VERSION 5.8 ;
BUSBITCHARS "[]" ;
DIVIDERCHAR "/" ;
UNITS
    DATABASE MICRONS 1000 ;
END UNITS

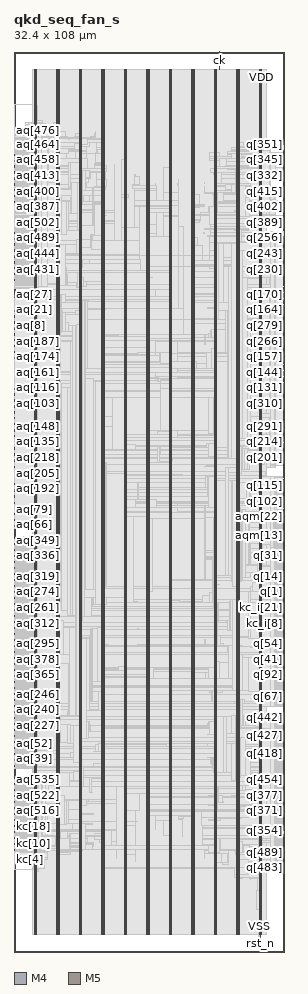
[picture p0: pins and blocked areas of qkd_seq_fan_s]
MACRO qkd_seq_fan_s
  FOREIGN qkd_seq_fan_s 0 0 ;
  CLASS BLOCK ;
  SIZE 32.4 BY 108 ;
  PIN af
    DIRECTION INPUT ;
    USE SIGNAL ;
    PORT
      LAYER M4 ;
        RECT  0 73.872 0.084 73.896 ;
    END
  END af
  PIN af_o
    DIRECTION OUTPUT ;
    USE SIGNAL ;
    PORT
      LAYER M4 ;
        RECT  32.316 47.952 32.4 47.976 ;
    END
  END af_o
  PIN aq[0]
    DIRECTION OUTPUT ;
    USE SIGNAL ;
    PORT
      LAYER M4 ;
        RECT  0 74.016 0.084 74.04 ;
    END
  END aq[0]
  PIN aq[100]
    DIRECTION OUTPUT ;
    USE SIGNAL ;
    PORT
      LAYER M4 ;
        RECT  0 65.376 0.084 65.4 ;
    END
  END aq[100]
  PIN aq[101]
    DIRECTION OUTPUT ;
    USE SIGNAL ;
    PORT
      LAYER M4 ;
        RECT  0 65.52 0.084 65.544 ;
    END
  END aq[101]
  PIN aq[102]
    DIRECTION OUTPUT ;
    USE SIGNAL ;
    PORT
      LAYER M4 ;
        RECT  0 65.664 0.084 65.688 ;
    END
  END aq[102]
  PIN aq[103]
    DIRECTION OUTPUT ;
    USE SIGNAL ;
    PORT
      LAYER M4 ;
        RECT  0 65.808 0.084 65.832 ;
    END
  END aq[103]
  PIN aq[104]
    DIRECTION OUTPUT ;
    USE SIGNAL ;
    PORT
      LAYER M4 ;
        RECT  0 65.952 0.084 65.976 ;
    END
  END aq[104]
  PIN aq[105]
    DIRECTION OUTPUT ;
    USE SIGNAL ;
    PORT
      LAYER M4 ;
        RECT  0 66.096 0.084 66.12 ;
    END
  END aq[105]
  PIN aq[106]
    DIRECTION OUTPUT ;
    USE SIGNAL ;
    PORT
      LAYER M4 ;
        RECT  0 66.24 0.084 66.264 ;
    END
  END aq[106]
  PIN aq[107]
    DIRECTION OUTPUT ;
    USE SIGNAL ;
    PORT
      LAYER M4 ;
        RECT  0 66.384 0.084 66.408 ;
    END
  END aq[107]
  PIN aq[108]
    DIRECTION OUTPUT ;
    USE SIGNAL ;
    PORT
      LAYER M4 ;
        RECT  0 66.528 0.084 66.552 ;
    END
  END aq[108]
  PIN aq[109]
    DIRECTION OUTPUT ;
    USE SIGNAL ;
    PORT
      LAYER M4 ;
        RECT  0 66.672 0.084 66.696 ;
    END
  END aq[109]
  PIN aq[10]
    DIRECTION OUTPUT ;
    USE SIGNAL ;
    PORT
      LAYER M4 ;
        RECT  0 75.456 0.084 75.48 ;
    END
  END aq[10]
  PIN aq[110]
    DIRECTION OUTPUT ;
    USE SIGNAL ;
    PORT
      LAYER M4 ;
        RECT  0 66.816 0.084 66.84 ;
    END
  END aq[110]
  PIN aq[111]
    DIRECTION OUTPUT ;
    USE SIGNAL ;
    PORT
      LAYER M4 ;
        RECT  0 66.96 0.084 66.984 ;
    END
  END aq[111]
  PIN aq[112]
    DIRECTION OUTPUT ;
    USE SIGNAL ;
    PORT
      LAYER M4 ;
        RECT  0 67.104 0.084 67.128 ;
    END
  END aq[112]
  PIN aq[113]
    DIRECTION OUTPUT ;
    USE SIGNAL ;
    PORT
      LAYER M4 ;
        RECT  0 67.248 0.084 67.272 ;
    END
  END aq[113]
  PIN aq[114]
    DIRECTION OUTPUT ;
    USE SIGNAL ;
    PORT
      LAYER M4 ;
        RECT  0 67.392 0.084 67.416 ;
    END
  END aq[114]
  PIN aq[115]
    DIRECTION OUTPUT ;
    USE SIGNAL ;
    PORT
      LAYER M4 ;
        RECT  0 67.536 0.084 67.56 ;
    END
  END aq[115]
  PIN aq[116]
    DIRECTION OUTPUT ;
    USE SIGNAL ;
    PORT
      LAYER M4 ;
        RECT  0 67.68 0.084 67.704 ;
    END
  END aq[116]
  PIN aq[117]
    DIRECTION OUTPUT ;
    USE SIGNAL ;
    PORT
      LAYER M4 ;
        RECT  0 67.824 0.084 67.848 ;
    END
  END aq[117]
  PIN aq[118]
    DIRECTION OUTPUT ;
    USE SIGNAL ;
    PORT
      LAYER M4 ;
        RECT  0 67.968 0.084 67.992 ;
    END
  END aq[118]
  PIN aq[119]
    DIRECTION OUTPUT ;
    USE SIGNAL ;
    PORT
      LAYER M4 ;
        RECT  0 68.112 0.084 68.136 ;
    END
  END aq[119]
  PIN aq[11]
    DIRECTION OUTPUT ;
    USE SIGNAL ;
    PORT
      LAYER M4 ;
        RECT  0 75.6 0.084 75.624 ;
    END
  END aq[11]
  PIN aq[120]
    DIRECTION OUTPUT ;
    USE SIGNAL ;
    PORT
      LAYER M4 ;
        RECT  0 68.256 0.084 68.28 ;
    END
  END aq[120]
  PIN aq[121]
    DIRECTION OUTPUT ;
    USE SIGNAL ;
    PORT
      LAYER M4 ;
        RECT  0 68.4 0.084 68.424 ;
    END
  END aq[121]
  PIN aq[122]
    DIRECTION OUTPUT ;
    USE SIGNAL ;
    PORT
      LAYER M4 ;
        RECT  0 68.544 0.084 68.568 ;
    END
  END aq[122]
  PIN aq[123]
    DIRECTION OUTPUT ;
    USE SIGNAL ;
    PORT
      LAYER M4 ;
        RECT  0 68.688 0.084 68.712 ;
    END
  END aq[123]
  PIN aq[124]
    DIRECTION OUTPUT ;
    USE SIGNAL ;
    PORT
      LAYER M4 ;
        RECT  0 68.832 0.084 68.856 ;
    END
  END aq[124]
  PIN aq[125]
    DIRECTION OUTPUT ;
    USE SIGNAL ;
    PORT
      LAYER M4 ;
        RECT  0 68.976 0.084 69 ;
    END
  END aq[125]
  PIN aq[126]
    DIRECTION OUTPUT ;
    USE SIGNAL ;
    PORT
      LAYER M4 ;
        RECT  0 69.12 0.084 69.144 ;
    END
  END aq[126]
  PIN aq[127]
    DIRECTION OUTPUT ;
    USE SIGNAL ;
    PORT
      LAYER M4 ;
        RECT  0 60.048 0.084 60.072 ;
    END
  END aq[127]
  PIN aq[128]
    DIRECTION OUTPUT ;
    USE SIGNAL ;
    PORT
      LAYER M4 ;
        RECT  0 60.192 0.084 60.216 ;
    END
  END aq[128]
  PIN aq[129]
    DIRECTION OUTPUT ;
    USE SIGNAL ;
    PORT
      LAYER M4 ;
        RECT  0 60.336 0.084 60.36 ;
    END
  END aq[129]
  PIN aq[12]
    DIRECTION OUTPUT ;
    USE SIGNAL ;
    PORT
      LAYER M4 ;
        RECT  0 75.744 0.084 75.768 ;
    END
  END aq[12]
  PIN aq[130]
    DIRECTION OUTPUT ;
    USE SIGNAL ;
    PORT
      LAYER M4 ;
        RECT  0 60.48 0.084 60.504 ;
    END
  END aq[130]
  PIN aq[131]
    DIRECTION OUTPUT ;
    USE SIGNAL ;
    PORT
      LAYER M4 ;
        RECT  0 60.624 0.084 60.648 ;
    END
  END aq[131]
  PIN aq[132]
    DIRECTION OUTPUT ;
    USE SIGNAL ;
    PORT
      LAYER M4 ;
        RECT  0 60.768 0.084 60.792 ;
    END
  END aq[132]
  PIN aq[133]
    DIRECTION OUTPUT ;
    USE SIGNAL ;
    PORT
      LAYER M4 ;
        RECT  0 60.912 0.084 60.936 ;
    END
  END aq[133]
  PIN aq[134]
    DIRECTION OUTPUT ;
    USE SIGNAL ;
    PORT
      LAYER M4 ;
        RECT  0 61.056 0.084 61.08 ;
    END
  END aq[134]
  PIN aq[135]
    DIRECTION OUTPUT ;
    USE SIGNAL ;
    PORT
      LAYER M4 ;
        RECT  0 61.2 0.084 61.224 ;
    END
  END aq[135]
  PIN aq[136]
    DIRECTION OUTPUT ;
    USE SIGNAL ;
    PORT
      LAYER M4 ;
        RECT  0 61.344 0.084 61.368 ;
    END
  END aq[136]
  PIN aq[137]
    DIRECTION OUTPUT ;
    USE SIGNAL ;
    PORT
      LAYER M4 ;
        RECT  0 61.488 0.084 61.512 ;
    END
  END aq[137]
  PIN aq[138]
    DIRECTION OUTPUT ;
    USE SIGNAL ;
    PORT
      LAYER M4 ;
        RECT  0 61.632 0.084 61.656 ;
    END
  END aq[138]
  PIN aq[139]
    DIRECTION OUTPUT ;
    USE SIGNAL ;
    PORT
      LAYER M4 ;
        RECT  0 61.776 0.084 61.8 ;
    END
  END aq[139]
  PIN aq[13]
    DIRECTION OUTPUT ;
    USE SIGNAL ;
    PORT
      LAYER M4 ;
        RECT  0 75.888 0.084 75.912 ;
    END
  END aq[13]
  PIN aq[140]
    DIRECTION OUTPUT ;
    USE SIGNAL ;
    PORT
      LAYER M4 ;
        RECT  0 61.92 0.084 61.944 ;
    END
  END aq[140]
  PIN aq[141]
    DIRECTION OUTPUT ;
    USE SIGNAL ;
    PORT
      LAYER M4 ;
        RECT  0 62.064 0.084 62.088 ;
    END
  END aq[141]
  PIN aq[142]
    DIRECTION OUTPUT ;
    USE SIGNAL ;
    PORT
      LAYER M4 ;
        RECT  0 62.208 0.084 62.232 ;
    END
  END aq[142]
  PIN aq[143]
    DIRECTION OUTPUT ;
    USE SIGNAL ;
    PORT
      LAYER M4 ;
        RECT  0 62.352 0.084 62.376 ;
    END
  END aq[143]
  PIN aq[144]
    DIRECTION OUTPUT ;
    USE SIGNAL ;
    PORT
      LAYER M4 ;
        RECT  0 62.496 0.084 62.52 ;
    END
  END aq[144]
  PIN aq[145]
    DIRECTION OUTPUT ;
    USE SIGNAL ;
    PORT
      LAYER M4 ;
        RECT  0 62.64 0.084 62.664 ;
    END
  END aq[145]
  PIN aq[146]
    DIRECTION OUTPUT ;
    USE SIGNAL ;
    PORT
      LAYER M4 ;
        RECT  0 62.784 0.084 62.808 ;
    END
  END aq[146]
  PIN aq[147]
    DIRECTION OUTPUT ;
    USE SIGNAL ;
    PORT
      LAYER M4 ;
        RECT  0 62.928 0.084 62.952 ;
    END
  END aq[147]
  PIN aq[148]
    DIRECTION OUTPUT ;
    USE SIGNAL ;
    PORT
      LAYER M4 ;
        RECT  0 63.072 0.084 63.096 ;
    END
  END aq[148]
  PIN aq[149]
    DIRECTION OUTPUT ;
    USE SIGNAL ;
    PORT
      LAYER M4 ;
        RECT  0 63.216 0.084 63.24 ;
    END
  END aq[149]
  PIN aq[14]
    DIRECTION OUTPUT ;
    USE SIGNAL ;
    PORT
      LAYER M4 ;
        RECT  0 76.032 0.084 76.056 ;
    END
  END aq[14]
  PIN aq[150]
    DIRECTION OUTPUT ;
    USE SIGNAL ;
    PORT
      LAYER M4 ;
        RECT  0 63.36 0.084 63.384 ;
    END
  END aq[150]
  PIN aq[151]
    DIRECTION OUTPUT ;
    USE SIGNAL ;
    PORT
      LAYER M4 ;
        RECT  0 63.504 0.084 63.528 ;
    END
  END aq[151]
  PIN aq[152]
    DIRECTION OUTPUT ;
    USE SIGNAL ;
    PORT
      LAYER M4 ;
        RECT  0 63.648 0.084 63.672 ;
    END
  END aq[152]
  PIN aq[153]
    DIRECTION OUTPUT ;
    USE SIGNAL ;
    PORT
      LAYER M4 ;
        RECT  0 63.792 0.084 63.816 ;
    END
  END aq[153]
  PIN aq[154]
    DIRECTION OUTPUT ;
    USE SIGNAL ;
    PORT
      LAYER M4 ;
        RECT  0 63.936 0.084 63.96 ;
    END
  END aq[154]
  PIN aq[155]
    DIRECTION OUTPUT ;
    USE SIGNAL ;
    PORT
      LAYER M4 ;
        RECT  0 64.08 0.084 64.104 ;
    END
  END aq[155]
  PIN aq[156]
    DIRECTION OUTPUT ;
    USE SIGNAL ;
    PORT
      LAYER M4 ;
        RECT  0 64.224 0.084 64.248 ;
    END
  END aq[156]
  PIN aq[157]
    DIRECTION OUTPUT ;
    USE SIGNAL ;
    PORT
      LAYER M4 ;
        RECT  0 64.368 0.084 64.392 ;
    END
  END aq[157]
  PIN aq[158]
    DIRECTION OUTPUT ;
    USE SIGNAL ;
    PORT
      LAYER M4 ;
        RECT  0 64.512 0.084 64.536 ;
    END
  END aq[158]
  PIN aq[159]
    DIRECTION OUTPUT ;
    USE SIGNAL ;
    PORT
      LAYER M4 ;
        RECT  0 69.264 0.084 69.288 ;
    END
  END aq[159]
  PIN aq[15]
    DIRECTION OUTPUT ;
    USE SIGNAL ;
    PORT
      LAYER M4 ;
        RECT  0 76.176 0.084 76.2 ;
    END
  END aq[15]
  PIN aq[160]
    DIRECTION OUTPUT ;
    USE SIGNAL ;
    PORT
      LAYER M4 ;
        RECT  0 69.408 0.084 69.432 ;
    END
  END aq[160]
  PIN aq[161]
    DIRECTION OUTPUT ;
    USE SIGNAL ;
    PORT
      LAYER M4 ;
        RECT  0 69.552 0.084 69.576 ;
    END
  END aq[161]
  PIN aq[162]
    DIRECTION OUTPUT ;
    USE SIGNAL ;
    PORT
      LAYER M4 ;
        RECT  0 69.696 0.084 69.72 ;
    END
  END aq[162]
  PIN aq[163]
    DIRECTION OUTPUT ;
    USE SIGNAL ;
    PORT
      LAYER M4 ;
        RECT  0 69.84 0.084 69.864 ;
    END
  END aq[163]
  PIN aq[164]
    DIRECTION OUTPUT ;
    USE SIGNAL ;
    PORT
      LAYER M4 ;
        RECT  0 69.984 0.084 70.008 ;
    END
  END aq[164]
  PIN aq[165]
    DIRECTION OUTPUT ;
    USE SIGNAL ;
    PORT
      LAYER M4 ;
        RECT  0 70.128 0.084 70.152 ;
    END
  END aq[165]
  PIN aq[166]
    DIRECTION OUTPUT ;
    USE SIGNAL ;
    PORT
      LAYER M4 ;
        RECT  0 70.272 0.084 70.296 ;
    END
  END aq[166]
  PIN aq[167]
    DIRECTION OUTPUT ;
    USE SIGNAL ;
    PORT
      LAYER M4 ;
        RECT  0 70.416 0.084 70.44 ;
    END
  END aq[167]
  PIN aq[168]
    DIRECTION OUTPUT ;
    USE SIGNAL ;
    PORT
      LAYER M4 ;
        RECT  0 70.56 0.084 70.584 ;
    END
  END aq[168]
  PIN aq[169]
    DIRECTION OUTPUT ;
    USE SIGNAL ;
    PORT
      LAYER M4 ;
        RECT  0 70.704 0.084 70.728 ;
    END
  END aq[169]
  PIN aq[16]
    DIRECTION OUTPUT ;
    USE SIGNAL ;
    PORT
      LAYER M4 ;
        RECT  0 76.32 0.084 76.344 ;
    END
  END aq[16]
  PIN aq[170]
    DIRECTION OUTPUT ;
    USE SIGNAL ;
    PORT
      LAYER M4 ;
        RECT  0 70.848 0.084 70.872 ;
    END
  END aq[170]
  PIN aq[171]
    DIRECTION OUTPUT ;
    USE SIGNAL ;
    PORT
      LAYER M4 ;
        RECT  0 70.992 0.084 71.016 ;
    END
  END aq[171]
  PIN aq[172]
    DIRECTION OUTPUT ;
    USE SIGNAL ;
    PORT
      LAYER M4 ;
        RECT  0 71.136 0.084 71.16 ;
    END
  END aq[172]
  PIN aq[173]
    DIRECTION OUTPUT ;
    USE SIGNAL ;
    PORT
      LAYER M4 ;
        RECT  0 71.28 0.084 71.304 ;
    END
  END aq[173]
  PIN aq[174]
    DIRECTION OUTPUT ;
    USE SIGNAL ;
    PORT
      LAYER M4 ;
        RECT  0 71.424 0.084 71.448 ;
    END
  END aq[174]
  PIN aq[175]
    DIRECTION OUTPUT ;
    USE SIGNAL ;
    PORT
      LAYER M4 ;
        RECT  0 71.568 0.084 71.592 ;
    END
  END aq[175]
  PIN aq[176]
    DIRECTION OUTPUT ;
    USE SIGNAL ;
    PORT
      LAYER M4 ;
        RECT  0 71.712 0.084 71.736 ;
    END
  END aq[176]
  PIN aq[177]
    DIRECTION OUTPUT ;
    USE SIGNAL ;
    PORT
      LAYER M4 ;
        RECT  0 71.856 0.084 71.88 ;
    END
  END aq[177]
  PIN aq[178]
    DIRECTION OUTPUT ;
    USE SIGNAL ;
    PORT
      LAYER M4 ;
        RECT  0 72 0.084 72.024 ;
    END
  END aq[178]
  PIN aq[179]
    DIRECTION OUTPUT ;
    USE SIGNAL ;
    PORT
      LAYER M4 ;
        RECT  0 72.144 0.084 72.168 ;
    END
  END aq[179]
  PIN aq[17]
    DIRECTION OUTPUT ;
    USE SIGNAL ;
    PORT
      LAYER M4 ;
        RECT  0 76.464 0.084 76.488 ;
    END
  END aq[17]
  PIN aq[180]
    DIRECTION OUTPUT ;
    USE SIGNAL ;
    PORT
      LAYER M4 ;
        RECT  0 72.288 0.084 72.312 ;
    END
  END aq[180]
  PIN aq[181]
    DIRECTION OUTPUT ;
    USE SIGNAL ;
    PORT
      LAYER M4 ;
        RECT  0 72.432 0.084 72.456 ;
    END
  END aq[181]
  PIN aq[182]
    DIRECTION OUTPUT ;
    USE SIGNAL ;
    PORT
      LAYER M4 ;
        RECT  0 72.576 0.084 72.6 ;
    END
  END aq[182]
  PIN aq[183]
    DIRECTION OUTPUT ;
    USE SIGNAL ;
    PORT
      LAYER M4 ;
        RECT  0 72.72 0.084 72.744 ;
    END
  END aq[183]
  PIN aq[184]
    DIRECTION OUTPUT ;
    USE SIGNAL ;
    PORT
      LAYER M4 ;
        RECT  0 72.864 0.084 72.888 ;
    END
  END aq[184]
  PIN aq[185]
    DIRECTION OUTPUT ;
    USE SIGNAL ;
    PORT
      LAYER M4 ;
        RECT  0 73.008 0.084 73.032 ;
    END
  END aq[185]
  PIN aq[186]
    DIRECTION OUTPUT ;
    USE SIGNAL ;
    PORT
      LAYER M4 ;
        RECT  0 73.152 0.084 73.176 ;
    END
  END aq[186]
  PIN aq[187]
    DIRECTION OUTPUT ;
    USE SIGNAL ;
    PORT
      LAYER M4 ;
        RECT  0 73.296 0.084 73.32 ;
    END
  END aq[187]
  PIN aq[188]
    DIRECTION OUTPUT ;
    USE SIGNAL ;
    PORT
      LAYER M4 ;
        RECT  0 73.44 0.084 73.464 ;
    END
  END aq[188]
  PIN aq[189]
    DIRECTION OUTPUT ;
    USE SIGNAL ;
    PORT
      LAYER M4 ;
        RECT  0 73.584 0.084 73.608 ;
    END
  END aq[189]
  PIN aq[18]
    DIRECTION OUTPUT ;
    USE SIGNAL ;
    PORT
      LAYER M4 ;
        RECT  0 76.608 0.084 76.632 ;
    END
  END aq[18]
  PIN aq[190]
    DIRECTION OUTPUT ;
    USE SIGNAL ;
    PORT
      LAYER M4 ;
        RECT  0 73.728 0.084 73.752 ;
    END
  END aq[190]
  PIN aq[191]
    DIRECTION OUTPUT ;
    USE SIGNAL ;
    PORT
      LAYER M4 ;
        RECT  0 55.44 0.084 55.464 ;
    END
  END aq[191]
  PIN aq[192]
    DIRECTION OUTPUT ;
    USE SIGNAL ;
    PORT
      LAYER M4 ;
        RECT  0 55.584 0.084 55.608 ;
    END
  END aq[192]
  PIN aq[193]
    DIRECTION OUTPUT ;
    USE SIGNAL ;
    PORT
      LAYER M4 ;
        RECT  0 55.728 0.084 55.752 ;
    END
  END aq[193]
  PIN aq[194]
    DIRECTION OUTPUT ;
    USE SIGNAL ;
    PORT
      LAYER M4 ;
        RECT  0 55.872 0.084 55.896 ;
    END
  END aq[194]
  PIN aq[195]
    DIRECTION OUTPUT ;
    USE SIGNAL ;
    PORT
      LAYER M4 ;
        RECT  0 56.016 0.084 56.04 ;
    END
  END aq[195]
  PIN aq[196]
    DIRECTION OUTPUT ;
    USE SIGNAL ;
    PORT
      LAYER M4 ;
        RECT  0 56.16 0.084 56.184 ;
    END
  END aq[196]
  PIN aq[197]
    DIRECTION OUTPUT ;
    USE SIGNAL ;
    PORT
      LAYER M4 ;
        RECT  0 56.304 0.084 56.328 ;
    END
  END aq[197]
  PIN aq[198]
    DIRECTION OUTPUT ;
    USE SIGNAL ;
    PORT
      LAYER M4 ;
        RECT  0 56.448 0.084 56.472 ;
    END
  END aq[198]
  PIN aq[199]
    DIRECTION OUTPUT ;
    USE SIGNAL ;
    PORT
      LAYER M4 ;
        RECT  0 56.592 0.084 56.616 ;
    END
  END aq[199]
  PIN aq[19]
    DIRECTION OUTPUT ;
    USE SIGNAL ;
    PORT
      LAYER M4 ;
        RECT  0 76.752 0.084 76.776 ;
    END
  END aq[19]
  PIN aq[1]
    DIRECTION OUTPUT ;
    USE SIGNAL ;
    PORT
      LAYER M4 ;
        RECT  0 74.16 0.084 74.184 ;
    END
  END aq[1]
  PIN aq[200]
    DIRECTION OUTPUT ;
    USE SIGNAL ;
    PORT
      LAYER M4 ;
        RECT  0 56.736 0.084 56.76 ;
    END
  END aq[200]
  PIN aq[201]
    DIRECTION OUTPUT ;
    USE SIGNAL ;
    PORT
      LAYER M4 ;
        RECT  0 56.88 0.084 56.904 ;
    END
  END aq[201]
  PIN aq[202]
    DIRECTION OUTPUT ;
    USE SIGNAL ;
    PORT
      LAYER M4 ;
        RECT  0 57.024 0.084 57.048 ;
    END
  END aq[202]
  PIN aq[203]
    DIRECTION OUTPUT ;
    USE SIGNAL ;
    PORT
      LAYER M4 ;
        RECT  0 57.168 0.084 57.192 ;
    END
  END aq[203]
  PIN aq[204]
    DIRECTION OUTPUT ;
    USE SIGNAL ;
    PORT
      LAYER M4 ;
        RECT  0 57.312 0.084 57.336 ;
    END
  END aq[204]
  PIN aq[205]
    DIRECTION OUTPUT ;
    USE SIGNAL ;
    PORT
      LAYER M4 ;
        RECT  0 57.456 0.084 57.48 ;
    END
  END aq[205]
  PIN aq[206]
    DIRECTION OUTPUT ;
    USE SIGNAL ;
    PORT
      LAYER M4 ;
        RECT  0 57.6 0.084 57.624 ;
    END
  END aq[206]
  PIN aq[207]
    DIRECTION OUTPUT ;
    USE SIGNAL ;
    PORT
      LAYER M4 ;
        RECT  0 57.744 0.084 57.768 ;
    END
  END aq[207]
  PIN aq[208]
    DIRECTION OUTPUT ;
    USE SIGNAL ;
    PORT
      LAYER M4 ;
        RECT  0 57.888 0.084 57.912 ;
    END
  END aq[208]
  PIN aq[209]
    DIRECTION OUTPUT ;
    USE SIGNAL ;
    PORT
      LAYER M4 ;
        RECT  0 58.032 0.084 58.056 ;
    END
  END aq[209]
  PIN aq[20]
    DIRECTION OUTPUT ;
    USE SIGNAL ;
    PORT
      LAYER M4 ;
        RECT  0 76.896 0.084 76.92 ;
    END
  END aq[20]
  PIN aq[210]
    DIRECTION OUTPUT ;
    USE SIGNAL ;
    PORT
      LAYER M4 ;
        RECT  0 58.176 0.084 58.2 ;
    END
  END aq[210]
  PIN aq[211]
    DIRECTION OUTPUT ;
    USE SIGNAL ;
    PORT
      LAYER M4 ;
        RECT  0 58.32 0.084 58.344 ;
    END
  END aq[211]
  PIN aq[212]
    DIRECTION OUTPUT ;
    USE SIGNAL ;
    PORT
      LAYER M4 ;
        RECT  0 58.464 0.084 58.488 ;
    END
  END aq[212]
  PIN aq[213]
    DIRECTION OUTPUT ;
    USE SIGNAL ;
    PORT
      LAYER M4 ;
        RECT  0 58.608 0.084 58.632 ;
    END
  END aq[213]
  PIN aq[214]
    DIRECTION OUTPUT ;
    USE SIGNAL ;
    PORT
      LAYER M4 ;
        RECT  0 58.752 0.084 58.776 ;
    END
  END aq[214]
  PIN aq[215]
    DIRECTION OUTPUT ;
    USE SIGNAL ;
    PORT
      LAYER M4 ;
        RECT  0 58.896 0.084 58.92 ;
    END
  END aq[215]
  PIN aq[216]
    DIRECTION OUTPUT ;
    USE SIGNAL ;
    PORT
      LAYER M4 ;
        RECT  0 59.04 0.084 59.064 ;
    END
  END aq[216]
  PIN aq[217]
    DIRECTION OUTPUT ;
    USE SIGNAL ;
    PORT
      LAYER M4 ;
        RECT  0 59.184 0.084 59.208 ;
    END
  END aq[217]
  PIN aq[218]
    DIRECTION OUTPUT ;
    USE SIGNAL ;
    PORT
      LAYER M4 ;
        RECT  0 59.328 0.084 59.352 ;
    END
  END aq[218]
  PIN aq[219]
    DIRECTION OUTPUT ;
    USE SIGNAL ;
    PORT
      LAYER M4 ;
        RECT  0 59.472 0.084 59.496 ;
    END
  END aq[219]
  PIN aq[21]
    DIRECTION OUTPUT ;
    USE SIGNAL ;
    PORT
      LAYER M4 ;
        RECT  0 77.04 0.084 77.064 ;
    END
  END aq[21]
  PIN aq[220]
    DIRECTION OUTPUT ;
    USE SIGNAL ;
    PORT
      LAYER M4 ;
        RECT  0 59.616 0.084 59.64 ;
    END
  END aq[220]
  PIN aq[221]
    DIRECTION OUTPUT ;
    USE SIGNAL ;
    PORT
      LAYER M4 ;
        RECT  0 59.76 0.084 59.784 ;
    END
  END aq[221]
  PIN aq[222]
    DIRECTION OUTPUT ;
    USE SIGNAL ;
    PORT
      LAYER M4 ;
        RECT  0 59.904 0.084 59.928 ;
    END
  END aq[222]
  PIN aq[223]
    DIRECTION OUTPUT ;
    USE SIGNAL ;
    PORT
      LAYER M4 ;
        RECT  0 26.64 0.084 26.664 ;
    END
  END aq[223]
  PIN aq[224]
    DIRECTION OUTPUT ;
    USE SIGNAL ;
    PORT
      LAYER M4 ;
        RECT  0 26.784 0.084 26.808 ;
    END
  END aq[224]
  PIN aq[225]
    DIRECTION OUTPUT ;
    USE SIGNAL ;
    PORT
      LAYER M4 ;
        RECT  0 26.928 0.084 26.952 ;
    END
  END aq[225]
  PIN aq[226]
    DIRECTION OUTPUT ;
    USE SIGNAL ;
    PORT
      LAYER M4 ;
        RECT  0 27.072 0.084 27.096 ;
    END
  END aq[226]
  PIN aq[227]
    DIRECTION OUTPUT ;
    USE SIGNAL ;
    PORT
      LAYER M4 ;
        RECT  0 27.216 0.084 27.24 ;
    END
  END aq[227]
  PIN aq[228]
    DIRECTION OUTPUT ;
    USE SIGNAL ;
    PORT
      LAYER M4 ;
        RECT  0 27.36 0.084 27.384 ;
    END
  END aq[228]
  PIN aq[229]
    DIRECTION OUTPUT ;
    USE SIGNAL ;
    PORT
      LAYER M4 ;
        RECT  0 27.504 0.084 27.528 ;
    END
  END aq[229]
  PIN aq[22]
    DIRECTION OUTPUT ;
    USE SIGNAL ;
    PORT
      LAYER M4 ;
        RECT  0 77.184 0.084 77.208 ;
    END
  END aq[22]
  PIN aq[230]
    DIRECTION OUTPUT ;
    USE SIGNAL ;
    PORT
      LAYER M4 ;
        RECT  0 27.648 0.084 27.672 ;
    END
  END aq[230]
  PIN aq[231]
    DIRECTION OUTPUT ;
    USE SIGNAL ;
    PORT
      LAYER M4 ;
        RECT  0 27.792 0.084 27.816 ;
    END
  END aq[231]
  PIN aq[232]
    DIRECTION OUTPUT ;
    USE SIGNAL ;
    PORT
      LAYER M4 ;
        RECT  0 27.936 0.084 27.96 ;
    END
  END aq[232]
  PIN aq[233]
    DIRECTION OUTPUT ;
    USE SIGNAL ;
    PORT
      LAYER M4 ;
        RECT  0 28.08 0.084 28.104 ;
    END
  END aq[233]
  PIN aq[234]
    DIRECTION OUTPUT ;
    USE SIGNAL ;
    PORT
      LAYER M4 ;
        RECT  0 28.224 0.084 28.248 ;
    END
  END aq[234]
  PIN aq[235]
    DIRECTION OUTPUT ;
    USE SIGNAL ;
    PORT
      LAYER M4 ;
        RECT  0 28.368 0.084 28.392 ;
    END
  END aq[235]
  PIN aq[236]
    DIRECTION OUTPUT ;
    USE SIGNAL ;
    PORT
      LAYER M4 ;
        RECT  0 28.512 0.084 28.536 ;
    END
  END aq[236]
  PIN aq[237]
    DIRECTION OUTPUT ;
    USE SIGNAL ;
    PORT
      LAYER M4 ;
        RECT  0 28.656 0.084 28.68 ;
    END
  END aq[237]
  PIN aq[238]
    DIRECTION OUTPUT ;
    USE SIGNAL ;
    PORT
      LAYER M4 ;
        RECT  0 28.8 0.084 28.824 ;
    END
  END aq[238]
  PIN aq[239]
    DIRECTION OUTPUT ;
    USE SIGNAL ;
    PORT
      LAYER M4 ;
        RECT  0 28.944 0.084 28.968 ;
    END
  END aq[239]
  PIN aq[23]
    DIRECTION OUTPUT ;
    USE SIGNAL ;
    PORT
      LAYER M4 ;
        RECT  0 77.328 0.084 77.352 ;
    END
  END aq[23]
  PIN aq[240]
    DIRECTION OUTPUT ;
    USE SIGNAL ;
    PORT
      LAYER M4 ;
        RECT  0 29.088 0.084 29.112 ;
    END
  END aq[240]
  PIN aq[241]
    DIRECTION OUTPUT ;
    USE SIGNAL ;
    PORT
      LAYER M4 ;
        RECT  0 29.232 0.084 29.256 ;
    END
  END aq[241]
  PIN aq[242]
    DIRECTION OUTPUT ;
    USE SIGNAL ;
    PORT
      LAYER M4 ;
        RECT  0 29.376 0.084 29.4 ;
    END
  END aq[242]
  PIN aq[243]
    DIRECTION OUTPUT ;
    USE SIGNAL ;
    PORT
      LAYER M4 ;
        RECT  0 29.52 0.084 29.544 ;
    END
  END aq[243]
  PIN aq[244]
    DIRECTION OUTPUT ;
    USE SIGNAL ;
    PORT
      LAYER M4 ;
        RECT  0 29.664 0.084 29.688 ;
    END
  END aq[244]
  PIN aq[245]
    DIRECTION OUTPUT ;
    USE SIGNAL ;
    PORT
      LAYER M4 ;
        RECT  0 29.808 0.084 29.832 ;
    END
  END aq[245]
  PIN aq[246]
    DIRECTION OUTPUT ;
    USE SIGNAL ;
    PORT
      LAYER M4 ;
        RECT  0 29.952 0.084 29.976 ;
    END
  END aq[246]
  PIN aq[247]
    DIRECTION OUTPUT ;
    USE SIGNAL ;
    PORT
      LAYER M4 ;
        RECT  0 30.096 0.084 30.12 ;
    END
  END aq[247]
  PIN aq[248]
    DIRECTION OUTPUT ;
    USE SIGNAL ;
    PORT
      LAYER M4 ;
        RECT  0 30.24 0.084 30.264 ;
    END
  END aq[248]
  PIN aq[249]
    DIRECTION OUTPUT ;
    USE SIGNAL ;
    PORT
      LAYER M4 ;
        RECT  0 30.384 0.084 30.408 ;
    END
  END aq[249]
  PIN aq[24]
    DIRECTION OUTPUT ;
    USE SIGNAL ;
    PORT
      LAYER M4 ;
        RECT  0 77.472 0.084 77.496 ;
    END
  END aq[24]
  PIN aq[250]
    DIRECTION OUTPUT ;
    USE SIGNAL ;
    PORT
      LAYER M4 ;
        RECT  0 30.528 0.084 30.552 ;
    END
  END aq[250]
  PIN aq[251]
    DIRECTION OUTPUT ;
    USE SIGNAL ;
    PORT
      LAYER M4 ;
        RECT  0 30.672 0.084 30.696 ;
    END
  END aq[251]
  PIN aq[252]
    DIRECTION OUTPUT ;
    USE SIGNAL ;
    PORT
      LAYER M4 ;
        RECT  0 30.816 0.084 30.84 ;
    END
  END aq[252]
  PIN aq[253]
    DIRECTION OUTPUT ;
    USE SIGNAL ;
    PORT
      LAYER M4 ;
        RECT  0 30.96 0.084 30.984 ;
    END
  END aq[253]
  PIN aq[254]
    DIRECTION OUTPUT ;
    USE SIGNAL ;
    PORT
      LAYER M4 ;
        RECT  0 31.104 0.084 31.128 ;
    END
  END aq[254]
  PIN aq[255]
    DIRECTION OUTPUT ;
    USE SIGNAL ;
    PORT
      LAYER M4 ;
        RECT  0 40.464 0.084 40.488 ;
    END
  END aq[255]
  PIN aq[256]
    DIRECTION OUTPUT ;
    USE SIGNAL ;
    PORT
      LAYER M4 ;
        RECT  0 40.608 0.084 40.632 ;
    END
  END aq[256]
  PIN aq[257]
    DIRECTION OUTPUT ;
    USE SIGNAL ;
    PORT
      LAYER M4 ;
        RECT  0 40.752 0.084 40.776 ;
    END
  END aq[257]
  PIN aq[258]
    DIRECTION OUTPUT ;
    USE SIGNAL ;
    PORT
      LAYER M4 ;
        RECT  0 40.896 0.084 40.92 ;
    END
  END aq[258]
  PIN aq[259]
    DIRECTION OUTPUT ;
    USE SIGNAL ;
    PORT
      LAYER M4 ;
        RECT  0 41.04 0.084 41.064 ;
    END
  END aq[259]
  PIN aq[25]
    DIRECTION OUTPUT ;
    USE SIGNAL ;
    PORT
      LAYER M4 ;
        RECT  0 77.616 0.084 77.64 ;
    END
  END aq[25]
  PIN aq[260]
    DIRECTION OUTPUT ;
    USE SIGNAL ;
    PORT
      LAYER M4 ;
        RECT  0 41.184 0.084 41.208 ;
    END
  END aq[260]
  PIN aq[261]
    DIRECTION OUTPUT ;
    USE SIGNAL ;
    PORT
      LAYER M4 ;
        RECT  0 41.328 0.084 41.352 ;
    END
  END aq[261]
  PIN aq[262]
    DIRECTION OUTPUT ;
    USE SIGNAL ;
    PORT
      LAYER M4 ;
        RECT  0 41.472 0.084 41.496 ;
    END
  END aq[262]
  PIN aq[263]
    DIRECTION OUTPUT ;
    USE SIGNAL ;
    PORT
      LAYER M4 ;
        RECT  0 41.616 0.084 41.64 ;
    END
  END aq[263]
  PIN aq[264]
    DIRECTION OUTPUT ;
    USE SIGNAL ;
    PORT
      LAYER M4 ;
        RECT  0 41.76 0.084 41.784 ;
    END
  END aq[264]
  PIN aq[265]
    DIRECTION OUTPUT ;
    USE SIGNAL ;
    PORT
      LAYER M4 ;
        RECT  0 41.904 0.084 41.928 ;
    END
  END aq[265]
  PIN aq[266]
    DIRECTION OUTPUT ;
    USE SIGNAL ;
    PORT
      LAYER M4 ;
        RECT  0 42.048 0.084 42.072 ;
    END
  END aq[266]
  PIN aq[267]
    DIRECTION OUTPUT ;
    USE SIGNAL ;
    PORT
      LAYER M4 ;
        RECT  0 42.192 0.084 42.216 ;
    END
  END aq[267]
  PIN aq[268]
    DIRECTION OUTPUT ;
    USE SIGNAL ;
    PORT
      LAYER M4 ;
        RECT  0 42.336 0.084 42.36 ;
    END
  END aq[268]
  PIN aq[269]
    DIRECTION OUTPUT ;
    USE SIGNAL ;
    PORT
      LAYER M4 ;
        RECT  0 42.48 0.084 42.504 ;
    END
  END aq[269]
  PIN aq[26]
    DIRECTION OUTPUT ;
    USE SIGNAL ;
    PORT
      LAYER M4 ;
        RECT  0 77.76 0.084 77.784 ;
    END
  END aq[26]
  PIN aq[270]
    DIRECTION OUTPUT ;
    USE SIGNAL ;
    PORT
      LAYER M4 ;
        RECT  0 42.624 0.084 42.648 ;
    END
  END aq[270]
  PIN aq[271]
    DIRECTION OUTPUT ;
    USE SIGNAL ;
    PORT
      LAYER M4 ;
        RECT  0 42.768 0.084 42.792 ;
    END
  END aq[271]
  PIN aq[272]
    DIRECTION OUTPUT ;
    USE SIGNAL ;
    PORT
      LAYER M4 ;
        RECT  0 42.912 0.084 42.936 ;
    END
  END aq[272]
  PIN aq[273]
    DIRECTION OUTPUT ;
    USE SIGNAL ;
    PORT
      LAYER M4 ;
        RECT  0 43.056 0.084 43.08 ;
    END
  END aq[273]
  PIN aq[274]
    DIRECTION OUTPUT ;
    USE SIGNAL ;
    PORT
      LAYER M4 ;
        RECT  0 43.2 0.084 43.224 ;
    END
  END aq[274]
  PIN aq[275]
    DIRECTION OUTPUT ;
    USE SIGNAL ;
    PORT
      LAYER M4 ;
        RECT  0 43.344 0.084 43.368 ;
    END
  END aq[275]
  PIN aq[276]
    DIRECTION OUTPUT ;
    USE SIGNAL ;
    PORT
      LAYER M4 ;
        RECT  0 43.488 0.084 43.512 ;
    END
  END aq[276]
  PIN aq[277]
    DIRECTION OUTPUT ;
    USE SIGNAL ;
    PORT
      LAYER M4 ;
        RECT  0 43.632 0.084 43.656 ;
    END
  END aq[277]
  PIN aq[278]
    DIRECTION OUTPUT ;
    USE SIGNAL ;
    PORT
      LAYER M4 ;
        RECT  0 43.776 0.084 43.8 ;
    END
  END aq[278]
  PIN aq[279]
    DIRECTION OUTPUT ;
    USE SIGNAL ;
    PORT
      LAYER M4 ;
        RECT  0 43.92 0.084 43.944 ;
    END
  END aq[279]
  PIN aq[27]
    DIRECTION OUTPUT ;
    USE SIGNAL ;
    PORT
      LAYER M4 ;
        RECT  0 77.904 0.084 77.928 ;
    END
  END aq[27]
  PIN aq[280]
    DIRECTION OUTPUT ;
    USE SIGNAL ;
    PORT
      LAYER M4 ;
        RECT  0 44.064 0.084 44.088 ;
    END
  END aq[280]
  PIN aq[281]
    DIRECTION OUTPUT ;
    USE SIGNAL ;
    PORT
      LAYER M4 ;
        RECT  0 44.208 0.084 44.232 ;
    END
  END aq[281]
  PIN aq[282]
    DIRECTION OUTPUT ;
    USE SIGNAL ;
    PORT
      LAYER M4 ;
        RECT  0 44.352 0.084 44.376 ;
    END
  END aq[282]
  PIN aq[283]
    DIRECTION OUTPUT ;
    USE SIGNAL ;
    PORT
      LAYER M4 ;
        RECT  0 44.496 0.084 44.52 ;
    END
  END aq[283]
  PIN aq[284]
    DIRECTION OUTPUT ;
    USE SIGNAL ;
    PORT
      LAYER M4 ;
        RECT  0 44.64 0.084 44.664 ;
    END
  END aq[284]
  PIN aq[285]
    DIRECTION OUTPUT ;
    USE SIGNAL ;
    PORT
      LAYER M4 ;
        RECT  0 44.784 0.084 44.808 ;
    END
  END aq[285]
  PIN aq[286]
    DIRECTION OUTPUT ;
    USE SIGNAL ;
    PORT
      LAYER M4 ;
        RECT  0 44.928 0.084 44.952 ;
    END
  END aq[286]
  PIN aq[287]
    DIRECTION OUTPUT ;
    USE SIGNAL ;
    PORT
      LAYER M4 ;
        RECT  0 35.856 0.084 35.88 ;
    END
  END aq[287]
  PIN aq[288]
    DIRECTION OUTPUT ;
    USE SIGNAL ;
    PORT
      LAYER M4 ;
        RECT  0 36 0.084 36.024 ;
    END
  END aq[288]
  PIN aq[289]
    DIRECTION OUTPUT ;
    USE SIGNAL ;
    PORT
      LAYER M4 ;
        RECT  0 36.144 0.084 36.168 ;
    END
  END aq[289]
  PIN aq[28]
    DIRECTION OUTPUT ;
    USE SIGNAL ;
    PORT
      LAYER M4 ;
        RECT  0 78.048 0.084 78.072 ;
    END
  END aq[28]
  PIN aq[290]
    DIRECTION OUTPUT ;
    USE SIGNAL ;
    PORT
      LAYER M4 ;
        RECT  0 36.288 0.084 36.312 ;
    END
  END aq[290]
  PIN aq[291]
    DIRECTION OUTPUT ;
    USE SIGNAL ;
    PORT
      LAYER M4 ;
        RECT  0 36.432 0.084 36.456 ;
    END
  END aq[291]
  PIN aq[292]
    DIRECTION OUTPUT ;
    USE SIGNAL ;
    PORT
      LAYER M4 ;
        RECT  0 36.576 0.084 36.6 ;
    END
  END aq[292]
  PIN aq[293]
    DIRECTION OUTPUT ;
    USE SIGNAL ;
    PORT
      LAYER M4 ;
        RECT  0 36.72 0.084 36.744 ;
    END
  END aq[293]
  PIN aq[294]
    DIRECTION OUTPUT ;
    USE SIGNAL ;
    PORT
      LAYER M4 ;
        RECT  0 36.864 0.084 36.888 ;
    END
  END aq[294]
  PIN aq[295]
    DIRECTION OUTPUT ;
    USE SIGNAL ;
    PORT
      LAYER M4 ;
        RECT  0 37.008 0.084 37.032 ;
    END
  END aq[295]
  PIN aq[296]
    DIRECTION OUTPUT ;
    USE SIGNAL ;
    PORT
      LAYER M4 ;
        RECT  0 37.152 0.084 37.176 ;
    END
  END aq[296]
  PIN aq[297]
    DIRECTION OUTPUT ;
    USE SIGNAL ;
    PORT
      LAYER M4 ;
        RECT  0 37.296 0.084 37.32 ;
    END
  END aq[297]
  PIN aq[298]
    DIRECTION OUTPUT ;
    USE SIGNAL ;
    PORT
      LAYER M4 ;
        RECT  0 37.44 0.084 37.464 ;
    END
  END aq[298]
  PIN aq[299]
    DIRECTION OUTPUT ;
    USE SIGNAL ;
    PORT
      LAYER M4 ;
        RECT  0 37.584 0.084 37.608 ;
    END
  END aq[299]
  PIN aq[29]
    DIRECTION OUTPUT ;
    USE SIGNAL ;
    PORT
      LAYER M4 ;
        RECT  0 78.192 0.084 78.216 ;
    END
  END aq[29]
  PIN aq[2]
    DIRECTION OUTPUT ;
    USE SIGNAL ;
    PORT
      LAYER M4 ;
        RECT  0 74.304 0.084 74.328 ;
    END
  END aq[2]
  PIN aq[300]
    DIRECTION OUTPUT ;
    USE SIGNAL ;
    PORT
      LAYER M4 ;
        RECT  0 37.728 0.084 37.752 ;
    END
  END aq[300]
  PIN aq[301]
    DIRECTION OUTPUT ;
    USE SIGNAL ;
    PORT
      LAYER M4 ;
        RECT  0 37.872 0.084 37.896 ;
    END
  END aq[301]
  PIN aq[302]
    DIRECTION OUTPUT ;
    USE SIGNAL ;
    PORT
      LAYER M4 ;
        RECT  0 38.016 0.084 38.04 ;
    END
  END aq[302]
  PIN aq[303]
    DIRECTION OUTPUT ;
    USE SIGNAL ;
    PORT
      LAYER M4 ;
        RECT  0 38.16 0.084 38.184 ;
    END
  END aq[303]
  PIN aq[304]
    DIRECTION OUTPUT ;
    USE SIGNAL ;
    PORT
      LAYER M4 ;
        RECT  0 38.304 0.084 38.328 ;
    END
  END aq[304]
  PIN aq[305]
    DIRECTION OUTPUT ;
    USE SIGNAL ;
    PORT
      LAYER M4 ;
        RECT  0 38.448 0.084 38.472 ;
    END
  END aq[305]
  PIN aq[306]
    DIRECTION OUTPUT ;
    USE SIGNAL ;
    PORT
      LAYER M4 ;
        RECT  0 38.592 0.084 38.616 ;
    END
  END aq[306]
  PIN aq[307]
    DIRECTION OUTPUT ;
    USE SIGNAL ;
    PORT
      LAYER M4 ;
        RECT  0 38.736 0.084 38.76 ;
    END
  END aq[307]
  PIN aq[308]
    DIRECTION OUTPUT ;
    USE SIGNAL ;
    PORT
      LAYER M4 ;
        RECT  0 38.88 0.084 38.904 ;
    END
  END aq[308]
  PIN aq[309]
    DIRECTION OUTPUT ;
    USE SIGNAL ;
    PORT
      LAYER M4 ;
        RECT  0 39.024 0.084 39.048 ;
    END
  END aq[309]
  PIN aq[30]
    DIRECTION OUTPUT ;
    USE SIGNAL ;
    PORT
      LAYER M4 ;
        RECT  0 78.336 0.084 78.36 ;
    END
  END aq[30]
  PIN aq[310]
    DIRECTION OUTPUT ;
    USE SIGNAL ;
    PORT
      LAYER M4 ;
        RECT  0 39.168 0.084 39.192 ;
    END
  END aq[310]
  PIN aq[311]
    DIRECTION OUTPUT ;
    USE SIGNAL ;
    PORT
      LAYER M4 ;
        RECT  0 39.312 0.084 39.336 ;
    END
  END aq[311]
  PIN aq[312]
    DIRECTION OUTPUT ;
    USE SIGNAL ;
    PORT
      LAYER M4 ;
        RECT  0 39.456 0.084 39.48 ;
    END
  END aq[312]
  PIN aq[313]
    DIRECTION OUTPUT ;
    USE SIGNAL ;
    PORT
      LAYER M4 ;
        RECT  0 39.6 0.084 39.624 ;
    END
  END aq[313]
  PIN aq[314]
    DIRECTION OUTPUT ;
    USE SIGNAL ;
    PORT
      LAYER M4 ;
        RECT  0 39.744 0.084 39.768 ;
    END
  END aq[314]
  PIN aq[315]
    DIRECTION OUTPUT ;
    USE SIGNAL ;
    PORT
      LAYER M4 ;
        RECT  0 39.888 0.084 39.912 ;
    END
  END aq[315]
  PIN aq[316]
    DIRECTION OUTPUT ;
    USE SIGNAL ;
    PORT
      LAYER M4 ;
        RECT  0 40.032 0.084 40.056 ;
    END
  END aq[316]
  PIN aq[317]
    DIRECTION OUTPUT ;
    USE SIGNAL ;
    PORT
      LAYER M4 ;
        RECT  0 40.176 0.084 40.2 ;
    END
  END aq[317]
  PIN aq[318]
    DIRECTION OUTPUT ;
    USE SIGNAL ;
    PORT
      LAYER M4 ;
        RECT  0 40.32 0.084 40.344 ;
    END
  END aq[318]
  PIN aq[319]
    DIRECTION OUTPUT ;
    USE SIGNAL ;
    PORT
      LAYER M4 ;
        RECT  0 45.072 0.084 45.096 ;
    END
  END aq[319]
  PIN aq[31]
    DIRECTION OUTPUT ;
    USE SIGNAL ;
    PORT
      LAYER M4 ;
        RECT  0 22.032 0.084 22.056 ;
    END
  END aq[31]
  PIN aq[320]
    DIRECTION OUTPUT ;
    USE SIGNAL ;
    PORT
      LAYER M4 ;
        RECT  0 45.216 0.084 45.24 ;
    END
  END aq[320]
  PIN aq[321]
    DIRECTION OUTPUT ;
    USE SIGNAL ;
    PORT
      LAYER M4 ;
        RECT  0 45.36 0.084 45.384 ;
    END
  END aq[321]
  PIN aq[322]
    DIRECTION OUTPUT ;
    USE SIGNAL ;
    PORT
      LAYER M4 ;
        RECT  0 45.504 0.084 45.528 ;
    END
  END aq[322]
  PIN aq[323]
    DIRECTION OUTPUT ;
    USE SIGNAL ;
    PORT
      LAYER M4 ;
        RECT  0 45.648 0.084 45.672 ;
    END
  END aq[323]
  PIN aq[324]
    DIRECTION OUTPUT ;
    USE SIGNAL ;
    PORT
      LAYER M4 ;
        RECT  0 45.792 0.084 45.816 ;
    END
  END aq[324]
  PIN aq[325]
    DIRECTION OUTPUT ;
    USE SIGNAL ;
    PORT
      LAYER M4 ;
        RECT  0 45.936 0.084 45.96 ;
    END
  END aq[325]
  PIN aq[326]
    DIRECTION OUTPUT ;
    USE SIGNAL ;
    PORT
      LAYER M4 ;
        RECT  0 46.08 0.084 46.104 ;
    END
  END aq[326]
  PIN aq[327]
    DIRECTION OUTPUT ;
    USE SIGNAL ;
    PORT
      LAYER M4 ;
        RECT  0 46.224 0.084 46.248 ;
    END
  END aq[327]
  PIN aq[328]
    DIRECTION OUTPUT ;
    USE SIGNAL ;
    PORT
      LAYER M4 ;
        RECT  0 46.368 0.084 46.392 ;
    END
  END aq[328]
  PIN aq[329]
    DIRECTION OUTPUT ;
    USE SIGNAL ;
    PORT
      LAYER M4 ;
        RECT  0 46.512 0.084 46.536 ;
    END
  END aq[329]
  PIN aq[32]
    DIRECTION OUTPUT ;
    USE SIGNAL ;
    PORT
      LAYER M4 ;
        RECT  0 22.176 0.084 22.2 ;
    END
  END aq[32]
  PIN aq[330]
    DIRECTION OUTPUT ;
    USE SIGNAL ;
    PORT
      LAYER M4 ;
        RECT  0 46.656 0.084 46.68 ;
    END
  END aq[330]
  PIN aq[331]
    DIRECTION OUTPUT ;
    USE SIGNAL ;
    PORT
      LAYER M4 ;
        RECT  0 46.8 0.084 46.824 ;
    END
  END aq[331]
  PIN aq[332]
    DIRECTION OUTPUT ;
    USE SIGNAL ;
    PORT
      LAYER M4 ;
        RECT  0 46.944 0.084 46.968 ;
    END
  END aq[332]
  PIN aq[333]
    DIRECTION OUTPUT ;
    USE SIGNAL ;
    PORT
      LAYER M4 ;
        RECT  0 47.088 0.084 47.112 ;
    END
  END aq[333]
  PIN aq[334]
    DIRECTION OUTPUT ;
    USE SIGNAL ;
    PORT
      LAYER M4 ;
        RECT  0 47.232 0.084 47.256 ;
    END
  END aq[334]
  PIN aq[335]
    DIRECTION OUTPUT ;
    USE SIGNAL ;
    PORT
      LAYER M4 ;
        RECT  0 47.376 0.084 47.4 ;
    END
  END aq[335]
  PIN aq[336]
    DIRECTION OUTPUT ;
    USE SIGNAL ;
    PORT
      LAYER M4 ;
        RECT  0 47.52 0.084 47.544 ;
    END
  END aq[336]
  PIN aq[337]
    DIRECTION OUTPUT ;
    USE SIGNAL ;
    PORT
      LAYER M4 ;
        RECT  0 47.664 0.084 47.688 ;
    END
  END aq[337]
  PIN aq[338]
    DIRECTION OUTPUT ;
    USE SIGNAL ;
    PORT
      LAYER M4 ;
        RECT  0 47.808 0.084 47.832 ;
    END
  END aq[338]
  PIN aq[339]
    DIRECTION OUTPUT ;
    USE SIGNAL ;
    PORT
      LAYER M4 ;
        RECT  0 47.952 0.084 47.976 ;
    END
  END aq[339]
  PIN aq[33]
    DIRECTION OUTPUT ;
    USE SIGNAL ;
    PORT
      LAYER M4 ;
        RECT  0 22.32 0.084 22.344 ;
    END
  END aq[33]
  PIN aq[340]
    DIRECTION OUTPUT ;
    USE SIGNAL ;
    PORT
      LAYER M4 ;
        RECT  0 48.096 0.084 48.12 ;
    END
  END aq[340]
  PIN aq[341]
    DIRECTION OUTPUT ;
    USE SIGNAL ;
    PORT
      LAYER M4 ;
        RECT  0 48.24 0.084 48.264 ;
    END
  END aq[341]
  PIN aq[342]
    DIRECTION OUTPUT ;
    USE SIGNAL ;
    PORT
      LAYER M4 ;
        RECT  0 48.384 0.084 48.408 ;
    END
  END aq[342]
  PIN aq[343]
    DIRECTION OUTPUT ;
    USE SIGNAL ;
    PORT
      LAYER M4 ;
        RECT  0 48.528 0.084 48.552 ;
    END
  END aq[343]
  PIN aq[344]
    DIRECTION OUTPUT ;
    USE SIGNAL ;
    PORT
      LAYER M4 ;
        RECT  0 48.672 0.084 48.696 ;
    END
  END aq[344]
  PIN aq[345]
    DIRECTION OUTPUT ;
    USE SIGNAL ;
    PORT
      LAYER M4 ;
        RECT  0 48.816 0.084 48.84 ;
    END
  END aq[345]
  PIN aq[346]
    DIRECTION OUTPUT ;
    USE SIGNAL ;
    PORT
      LAYER M4 ;
        RECT  0 48.96 0.084 48.984 ;
    END
  END aq[346]
  PIN aq[347]
    DIRECTION OUTPUT ;
    USE SIGNAL ;
    PORT
      LAYER M4 ;
        RECT  0 49.104 0.084 49.128 ;
    END
  END aq[347]
  PIN aq[348]
    DIRECTION OUTPUT ;
    USE SIGNAL ;
    PORT
      LAYER M4 ;
        RECT  0 49.248 0.084 49.272 ;
    END
  END aq[348]
  PIN aq[349]
    DIRECTION OUTPUT ;
    USE SIGNAL ;
    PORT
      LAYER M4 ;
        RECT  0 49.392 0.084 49.416 ;
    END
  END aq[349]
  PIN aq[34]
    DIRECTION OUTPUT ;
    USE SIGNAL ;
    PORT
      LAYER M4 ;
        RECT  0 22.464 0.084 22.488 ;
    END
  END aq[34]
  PIN aq[350]
    DIRECTION OUTPUT ;
    USE SIGNAL ;
    PORT
      LAYER M4 ;
        RECT  0 49.536 0.084 49.56 ;
    END
  END aq[350]
  PIN aq[351]
    DIRECTION OUTPUT ;
    USE SIGNAL ;
    PORT
      LAYER M4 ;
        RECT  0 31.248 0.084 31.272 ;
    END
  END aq[351]
  PIN aq[352]
    DIRECTION OUTPUT ;
    USE SIGNAL ;
    PORT
      LAYER M4 ;
        RECT  0 31.392 0.084 31.416 ;
    END
  END aq[352]
  PIN aq[353]
    DIRECTION OUTPUT ;
    USE SIGNAL ;
    PORT
      LAYER M4 ;
        RECT  0 31.536 0.084 31.56 ;
    END
  END aq[353]
  PIN aq[354]
    DIRECTION OUTPUT ;
    USE SIGNAL ;
    PORT
      LAYER M4 ;
        RECT  0 31.68 0.084 31.704 ;
    END
  END aq[354]
  PIN aq[355]
    DIRECTION OUTPUT ;
    USE SIGNAL ;
    PORT
      LAYER M4 ;
        RECT  0 31.824 0.084 31.848 ;
    END
  END aq[355]
  PIN aq[356]
    DIRECTION OUTPUT ;
    USE SIGNAL ;
    PORT
      LAYER M4 ;
        RECT  0 31.968 0.084 31.992 ;
    END
  END aq[356]
  PIN aq[357]
    DIRECTION OUTPUT ;
    USE SIGNAL ;
    PORT
      LAYER M4 ;
        RECT  0 32.112 0.084 32.136 ;
    END
  END aq[357]
  PIN aq[358]
    DIRECTION OUTPUT ;
    USE SIGNAL ;
    PORT
      LAYER M4 ;
        RECT  0 32.256 0.084 32.28 ;
    END
  END aq[358]
  PIN aq[359]
    DIRECTION OUTPUT ;
    USE SIGNAL ;
    PORT
      LAYER M4 ;
        RECT  0 32.4 0.084 32.424 ;
    END
  END aq[359]
  PIN aq[35]
    DIRECTION OUTPUT ;
    USE SIGNAL ;
    PORT
      LAYER M4 ;
        RECT  0 22.608 0.084 22.632 ;
    END
  END aq[35]
  PIN aq[360]
    DIRECTION OUTPUT ;
    USE SIGNAL ;
    PORT
      LAYER M4 ;
        RECT  0 32.544 0.084 32.568 ;
    END
  END aq[360]
  PIN aq[361]
    DIRECTION OUTPUT ;
    USE SIGNAL ;
    PORT
      LAYER M4 ;
        RECT  0 32.688 0.084 32.712 ;
    END
  END aq[361]
  PIN aq[362]
    DIRECTION OUTPUT ;
    USE SIGNAL ;
    PORT
      LAYER M4 ;
        RECT  0 32.832 0.084 32.856 ;
    END
  END aq[362]
  PIN aq[363]
    DIRECTION OUTPUT ;
    USE SIGNAL ;
    PORT
      LAYER M4 ;
        RECT  0 32.976 0.084 33 ;
    END
  END aq[363]
  PIN aq[364]
    DIRECTION OUTPUT ;
    USE SIGNAL ;
    PORT
      LAYER M4 ;
        RECT  0 33.12 0.084 33.144 ;
    END
  END aq[364]
  PIN aq[365]
    DIRECTION OUTPUT ;
    USE SIGNAL ;
    PORT
      LAYER M4 ;
        RECT  0 33.264 0.084 33.288 ;
    END
  END aq[365]
  PIN aq[366]
    DIRECTION OUTPUT ;
    USE SIGNAL ;
    PORT
      LAYER M4 ;
        RECT  0 33.408 0.084 33.432 ;
    END
  END aq[366]
  PIN aq[367]
    DIRECTION OUTPUT ;
    USE SIGNAL ;
    PORT
      LAYER M4 ;
        RECT  0 33.552 0.084 33.576 ;
    END
  END aq[367]
  PIN aq[368]
    DIRECTION OUTPUT ;
    USE SIGNAL ;
    PORT
      LAYER M4 ;
        RECT  0 33.696 0.084 33.72 ;
    END
  END aq[368]
  PIN aq[369]
    DIRECTION OUTPUT ;
    USE SIGNAL ;
    PORT
      LAYER M4 ;
        RECT  0 33.84 0.084 33.864 ;
    END
  END aq[369]
  PIN aq[36]
    DIRECTION OUTPUT ;
    USE SIGNAL ;
    PORT
      LAYER M4 ;
        RECT  0 22.752 0.084 22.776 ;
    END
  END aq[36]
  PIN aq[370]
    DIRECTION OUTPUT ;
    USE SIGNAL ;
    PORT
      LAYER M4 ;
        RECT  0 33.984 0.084 34.008 ;
    END
  END aq[370]
  PIN aq[371]
    DIRECTION OUTPUT ;
    USE SIGNAL ;
    PORT
      LAYER M4 ;
        RECT  0 34.128 0.084 34.152 ;
    END
  END aq[371]
  PIN aq[372]
    DIRECTION OUTPUT ;
    USE SIGNAL ;
    PORT
      LAYER M4 ;
        RECT  0 34.272 0.084 34.296 ;
    END
  END aq[372]
  PIN aq[373]
    DIRECTION OUTPUT ;
    USE SIGNAL ;
    PORT
      LAYER M4 ;
        RECT  0 34.416 0.084 34.44 ;
    END
  END aq[373]
  PIN aq[374]
    DIRECTION OUTPUT ;
    USE SIGNAL ;
    PORT
      LAYER M4 ;
        RECT  0 34.56 0.084 34.584 ;
    END
  END aq[374]
  PIN aq[375]
    DIRECTION OUTPUT ;
    USE SIGNAL ;
    PORT
      LAYER M4 ;
        RECT  0 34.704 0.084 34.728 ;
    END
  END aq[375]
  PIN aq[376]
    DIRECTION OUTPUT ;
    USE SIGNAL ;
    PORT
      LAYER M4 ;
        RECT  0 34.848 0.084 34.872 ;
    END
  END aq[376]
  PIN aq[377]
    DIRECTION OUTPUT ;
    USE SIGNAL ;
    PORT
      LAYER M4 ;
        RECT  0 34.992 0.084 35.016 ;
    END
  END aq[377]
  PIN aq[378]
    DIRECTION OUTPUT ;
    USE SIGNAL ;
    PORT
      LAYER M4 ;
        RECT  0 35.136 0.084 35.16 ;
    END
  END aq[378]
  PIN aq[379]
    DIRECTION OUTPUT ;
    USE SIGNAL ;
    PORT
      LAYER M4 ;
        RECT  0 35.28 0.084 35.304 ;
    END
  END aq[379]
  PIN aq[37]
    DIRECTION OUTPUT ;
    USE SIGNAL ;
    PORT
      LAYER M4 ;
        RECT  0 22.896 0.084 22.92 ;
    END
  END aq[37]
  PIN aq[380]
    DIRECTION OUTPUT ;
    USE SIGNAL ;
    PORT
      LAYER M4 ;
        RECT  0 35.424 0.084 35.448 ;
    END
  END aq[380]
  PIN aq[381]
    DIRECTION OUTPUT ;
    USE SIGNAL ;
    PORT
      LAYER M4 ;
        RECT  0 35.568 0.084 35.592 ;
    END
  END aq[381]
  PIN aq[382]
    DIRECTION OUTPUT ;
    USE SIGNAL ;
    PORT
      LAYER M4 ;
        RECT  0 35.712 0.084 35.736 ;
    END
  END aq[382]
  PIN aq[383]
    DIRECTION OUTPUT ;
    USE SIGNAL ;
    PORT
      LAYER M4 ;
        RECT  0 88.848 0.084 88.872 ;
    END
  END aq[383]
  PIN aq[384]
    DIRECTION OUTPUT ;
    USE SIGNAL ;
    PORT
      LAYER M4 ;
        RECT  0 88.992 0.084 89.016 ;
    END
  END aq[384]
  PIN aq[385]
    DIRECTION OUTPUT ;
    USE SIGNAL ;
    PORT
      LAYER M4 ;
        RECT  0 89.136 0.084 89.16 ;
    END
  END aq[385]
  PIN aq[386]
    DIRECTION OUTPUT ;
    USE SIGNAL ;
    PORT
      LAYER M4 ;
        RECT  0 89.28 0.084 89.304 ;
    END
  END aq[386]
  PIN aq[387]
    DIRECTION OUTPUT ;
    USE SIGNAL ;
    PORT
      LAYER M4 ;
        RECT  0 89.424 0.084 89.448 ;
    END
  END aq[387]
  PIN aq[388]
    DIRECTION OUTPUT ;
    USE SIGNAL ;
    PORT
      LAYER M4 ;
        RECT  0 89.568 0.084 89.592 ;
    END
  END aq[388]
  PIN aq[389]
    DIRECTION OUTPUT ;
    USE SIGNAL ;
    PORT
      LAYER M4 ;
        RECT  0 89.712 0.084 89.736 ;
    END
  END aq[389]
  PIN aq[38]
    DIRECTION OUTPUT ;
    USE SIGNAL ;
    PORT
      LAYER M4 ;
        RECT  0 23.04 0.084 23.064 ;
    END
  END aq[38]
  PIN aq[390]
    DIRECTION OUTPUT ;
    USE SIGNAL ;
    PORT
      LAYER M4 ;
        RECT  0 89.856 0.084 89.88 ;
    END
  END aq[390]
  PIN aq[391]
    DIRECTION OUTPUT ;
    USE SIGNAL ;
    PORT
      LAYER M4 ;
        RECT  0 90 0.084 90.024 ;
    END
  END aq[391]
  PIN aq[392]
    DIRECTION OUTPUT ;
    USE SIGNAL ;
    PORT
      LAYER M4 ;
        RECT  0 90.144 0.084 90.168 ;
    END
  END aq[392]
  PIN aq[393]
    DIRECTION OUTPUT ;
    USE SIGNAL ;
    PORT
      LAYER M4 ;
        RECT  0 90.288 0.084 90.312 ;
    END
  END aq[393]
  PIN aq[394]
    DIRECTION OUTPUT ;
    USE SIGNAL ;
    PORT
      LAYER M4 ;
        RECT  0 90.432 0.084 90.456 ;
    END
  END aq[394]
  PIN aq[395]
    DIRECTION OUTPUT ;
    USE SIGNAL ;
    PORT
      LAYER M4 ;
        RECT  0 90.576 0.084 90.6 ;
    END
  END aq[395]
  PIN aq[396]
    DIRECTION OUTPUT ;
    USE SIGNAL ;
    PORT
      LAYER M4 ;
        RECT  0 90.72 0.084 90.744 ;
    END
  END aq[396]
  PIN aq[397]
    DIRECTION OUTPUT ;
    USE SIGNAL ;
    PORT
      LAYER M4 ;
        RECT  0 90.864 0.084 90.888 ;
    END
  END aq[397]
  PIN aq[398]
    DIRECTION OUTPUT ;
    USE SIGNAL ;
    PORT
      LAYER M4 ;
        RECT  0 91.008 0.084 91.032 ;
    END
  END aq[398]
  PIN aq[399]
    DIRECTION OUTPUT ;
    USE SIGNAL ;
    PORT
      LAYER M4 ;
        RECT  0 91.152 0.084 91.176 ;
    END
  END aq[399]
  PIN aq[39]
    DIRECTION OUTPUT ;
    USE SIGNAL ;
    PORT
      LAYER M4 ;
        RECT  0 23.184 0.084 23.208 ;
    END
  END aq[39]
  PIN aq[3]
    DIRECTION OUTPUT ;
    USE SIGNAL ;
    PORT
      LAYER M4 ;
        RECT  0 74.448 0.084 74.472 ;
    END
  END aq[3]
  PIN aq[400]
    DIRECTION OUTPUT ;
    USE SIGNAL ;
    PORT
      LAYER M4 ;
        RECT  0 91.296 0.084 91.32 ;
    END
  END aq[400]
  PIN aq[401]
    DIRECTION OUTPUT ;
    USE SIGNAL ;
    PORT
      LAYER M4 ;
        RECT  0 91.44 0.084 91.464 ;
    END
  END aq[401]
  PIN aq[402]
    DIRECTION OUTPUT ;
    USE SIGNAL ;
    PORT
      LAYER M4 ;
        RECT  0 91.584 0.084 91.608 ;
    END
  END aq[402]
  PIN aq[403]
    DIRECTION OUTPUT ;
    USE SIGNAL ;
    PORT
      LAYER M4 ;
        RECT  0 91.728 0.084 91.752 ;
    END
  END aq[403]
  PIN aq[404]
    DIRECTION OUTPUT ;
    USE SIGNAL ;
    PORT
      LAYER M4 ;
        RECT  0 91.872 0.084 91.896 ;
    END
  END aq[404]
  PIN aq[405]
    DIRECTION OUTPUT ;
    USE SIGNAL ;
    PORT
      LAYER M4 ;
        RECT  0 92.016 0.084 92.04 ;
    END
  END aq[405]
  PIN aq[406]
    DIRECTION OUTPUT ;
    USE SIGNAL ;
    PORT
      LAYER M4 ;
        RECT  0 92.16 0.084 92.184 ;
    END
  END aq[406]
  PIN aq[407]
    DIRECTION OUTPUT ;
    USE SIGNAL ;
    PORT
      LAYER M4 ;
        RECT  0 92.304 0.084 92.328 ;
    END
  END aq[407]
  PIN aq[408]
    DIRECTION OUTPUT ;
    USE SIGNAL ;
    PORT
      LAYER M4 ;
        RECT  0 92.448 0.084 92.472 ;
    END
  END aq[408]
  PIN aq[409]
    DIRECTION OUTPUT ;
    USE SIGNAL ;
    PORT
      LAYER M4 ;
        RECT  0 92.592 0.084 92.616 ;
    END
  END aq[409]
  PIN aq[40]
    DIRECTION OUTPUT ;
    USE SIGNAL ;
    PORT
      LAYER M4 ;
        RECT  0 23.328 0.084 23.352 ;
    END
  END aq[40]
  PIN aq[410]
    DIRECTION OUTPUT ;
    USE SIGNAL ;
    PORT
      LAYER M4 ;
        RECT  0 92.736 0.084 92.76 ;
    END
  END aq[410]
  PIN aq[411]
    DIRECTION OUTPUT ;
    USE SIGNAL ;
    PORT
      LAYER M4 ;
        RECT  0 92.88 0.084 92.904 ;
    END
  END aq[411]
  PIN aq[412]
    DIRECTION OUTPUT ;
    USE SIGNAL ;
    PORT
      LAYER M4 ;
        RECT  0 93.024 0.084 93.048 ;
    END
  END aq[412]
  PIN aq[413]
    DIRECTION OUTPUT ;
    USE SIGNAL ;
    PORT
      LAYER M4 ;
        RECT  0 93.168 0.084 93.192 ;
    END
  END aq[413]
  PIN aq[414]
    DIRECTION OUTPUT ;
    USE SIGNAL ;
    PORT
      LAYER M4 ;
        RECT  0 93.312 0.084 93.336 ;
    END
  END aq[414]
  PIN aq[415]
    DIRECTION OUTPUT ;
    USE SIGNAL ;
    PORT
      LAYER M4 ;
        RECT  0 79.632 0.084 79.656 ;
    END
  END aq[415]
  PIN aq[416]
    DIRECTION OUTPUT ;
    USE SIGNAL ;
    PORT
      LAYER M4 ;
        RECT  0 79.776 0.084 79.8 ;
    END
  END aq[416]
  PIN aq[417]
    DIRECTION OUTPUT ;
    USE SIGNAL ;
    PORT
      LAYER M4 ;
        RECT  0 79.92 0.084 79.944 ;
    END
  END aq[417]
  PIN aq[418]
    DIRECTION OUTPUT ;
    USE SIGNAL ;
    PORT
      LAYER M4 ;
        RECT  0 80.064 0.084 80.088 ;
    END
  END aq[418]
  PIN aq[419]
    DIRECTION OUTPUT ;
    USE SIGNAL ;
    PORT
      LAYER M4 ;
        RECT  0 80.208 0.084 80.232 ;
    END
  END aq[419]
  PIN aq[41]
    DIRECTION OUTPUT ;
    USE SIGNAL ;
    PORT
      LAYER M4 ;
        RECT  0 23.472 0.084 23.496 ;
    END
  END aq[41]
  PIN aq[420]
    DIRECTION OUTPUT ;
    USE SIGNAL ;
    PORT
      LAYER M4 ;
        RECT  0 80.352 0.084 80.376 ;
    END
  END aq[420]
  PIN aq[421]
    DIRECTION OUTPUT ;
    USE SIGNAL ;
    PORT
      LAYER M4 ;
        RECT  0 80.496 0.084 80.52 ;
    END
  END aq[421]
  PIN aq[422]
    DIRECTION OUTPUT ;
    USE SIGNAL ;
    PORT
      LAYER M4 ;
        RECT  0 80.64 0.084 80.664 ;
    END
  END aq[422]
  PIN aq[423]
    DIRECTION OUTPUT ;
    USE SIGNAL ;
    PORT
      LAYER M4 ;
        RECT  0 80.784 0.084 80.808 ;
    END
  END aq[423]
  PIN aq[424]
    DIRECTION OUTPUT ;
    USE SIGNAL ;
    PORT
      LAYER M4 ;
        RECT  0 80.928 0.084 80.952 ;
    END
  END aq[424]
  PIN aq[425]
    DIRECTION OUTPUT ;
    USE SIGNAL ;
    PORT
      LAYER M4 ;
        RECT  0 81.072 0.084 81.096 ;
    END
  END aq[425]
  PIN aq[426]
    DIRECTION OUTPUT ;
    USE SIGNAL ;
    PORT
      LAYER M4 ;
        RECT  0 81.216 0.084 81.24 ;
    END
  END aq[426]
  PIN aq[427]
    DIRECTION OUTPUT ;
    USE SIGNAL ;
    PORT
      LAYER M4 ;
        RECT  0 81.36 0.084 81.384 ;
    END
  END aq[427]
  PIN aq[428]
    DIRECTION OUTPUT ;
    USE SIGNAL ;
    PORT
      LAYER M4 ;
        RECT  0 81.504 0.084 81.528 ;
    END
  END aq[428]
  PIN aq[429]
    DIRECTION OUTPUT ;
    USE SIGNAL ;
    PORT
      LAYER M4 ;
        RECT  0 81.648 0.084 81.672 ;
    END
  END aq[429]
  PIN aq[42]
    DIRECTION OUTPUT ;
    USE SIGNAL ;
    PORT
      LAYER M4 ;
        RECT  0 23.616 0.084 23.64 ;
    END
  END aq[42]
  PIN aq[430]
    DIRECTION OUTPUT ;
    USE SIGNAL ;
    PORT
      LAYER M4 ;
        RECT  0 81.792 0.084 81.816 ;
    END
  END aq[430]
  PIN aq[431]
    DIRECTION OUTPUT ;
    USE SIGNAL ;
    PORT
      LAYER M4 ;
        RECT  0 81.936 0.084 81.96 ;
    END
  END aq[431]
  PIN aq[432]
    DIRECTION OUTPUT ;
    USE SIGNAL ;
    PORT
      LAYER M4 ;
        RECT  0 82.08 0.084 82.104 ;
    END
  END aq[432]
  PIN aq[433]
    DIRECTION OUTPUT ;
    USE SIGNAL ;
    PORT
      LAYER M4 ;
        RECT  0 82.224 0.084 82.248 ;
    END
  END aq[433]
  PIN aq[434]
    DIRECTION OUTPUT ;
    USE SIGNAL ;
    PORT
      LAYER M4 ;
        RECT  0 82.368 0.084 82.392 ;
    END
  END aq[434]
  PIN aq[435]
    DIRECTION OUTPUT ;
    USE SIGNAL ;
    PORT
      LAYER M4 ;
        RECT  0 82.512 0.084 82.536 ;
    END
  END aq[435]
  PIN aq[436]
    DIRECTION OUTPUT ;
    USE SIGNAL ;
    PORT
      LAYER M4 ;
        RECT  0 82.656 0.084 82.68 ;
    END
  END aq[436]
  PIN aq[437]
    DIRECTION OUTPUT ;
    USE SIGNAL ;
    PORT
      LAYER M4 ;
        RECT  0 82.8 0.084 82.824 ;
    END
  END aq[437]
  PIN aq[438]
    DIRECTION OUTPUT ;
    USE SIGNAL ;
    PORT
      LAYER M4 ;
        RECT  0 82.944 0.084 82.968 ;
    END
  END aq[438]
  PIN aq[439]
    DIRECTION OUTPUT ;
    USE SIGNAL ;
    PORT
      LAYER M4 ;
        RECT  0 83.088 0.084 83.112 ;
    END
  END aq[439]
  PIN aq[43]
    DIRECTION OUTPUT ;
    USE SIGNAL ;
    PORT
      LAYER M4 ;
        RECT  0 23.76 0.084 23.784 ;
    END
  END aq[43]
  PIN aq[440]
    DIRECTION OUTPUT ;
    USE SIGNAL ;
    PORT
      LAYER M4 ;
        RECT  0 83.232 0.084 83.256 ;
    END
  END aq[440]
  PIN aq[441]
    DIRECTION OUTPUT ;
    USE SIGNAL ;
    PORT
      LAYER M4 ;
        RECT  0 83.376 0.084 83.4 ;
    END
  END aq[441]
  PIN aq[442]
    DIRECTION OUTPUT ;
    USE SIGNAL ;
    PORT
      LAYER M4 ;
        RECT  0 83.52 0.084 83.544 ;
    END
  END aq[442]
  PIN aq[443]
    DIRECTION OUTPUT ;
    USE SIGNAL ;
    PORT
      LAYER M4 ;
        RECT  0 83.664 0.084 83.688 ;
    END
  END aq[443]
  PIN aq[444]
    DIRECTION OUTPUT ;
    USE SIGNAL ;
    PORT
      LAYER M4 ;
        RECT  0 83.808 0.084 83.832 ;
    END
  END aq[444]
  PIN aq[445]
    DIRECTION OUTPUT ;
    USE SIGNAL ;
    PORT
      LAYER M4 ;
        RECT  0 83.952 0.084 83.976 ;
    END
  END aq[445]
  PIN aq[446]
    DIRECTION OUTPUT ;
    USE SIGNAL ;
    PORT
      LAYER M4 ;
        RECT  0 84.096 0.084 84.12 ;
    END
  END aq[446]
  PIN aq[447]
    DIRECTION OUTPUT ;
    USE SIGNAL ;
    PORT
      LAYER M4 ;
        RECT  0 93.456 0.084 93.48 ;
    END
  END aq[447]
  PIN aq[448]
    DIRECTION OUTPUT ;
    USE SIGNAL ;
    PORT
      LAYER M4 ;
        RECT  0 93.6 0.084 93.624 ;
    END
  END aq[448]
  PIN aq[449]
    DIRECTION OUTPUT ;
    USE SIGNAL ;
    PORT
      LAYER M4 ;
        RECT  0 93.744 0.084 93.768 ;
    END
  END aq[449]
  PIN aq[44]
    DIRECTION OUTPUT ;
    USE SIGNAL ;
    PORT
      LAYER M4 ;
        RECT  0 23.904 0.084 23.928 ;
    END
  END aq[44]
  PIN aq[450]
    DIRECTION OUTPUT ;
    USE SIGNAL ;
    PORT
      LAYER M4 ;
        RECT  0 93.888 0.084 93.912 ;
    END
  END aq[450]
  PIN aq[451]
    DIRECTION OUTPUT ;
    USE SIGNAL ;
    PORT
      LAYER M4 ;
        RECT  0 94.032 0.084 94.056 ;
    END
  END aq[451]
  PIN aq[452]
    DIRECTION OUTPUT ;
    USE SIGNAL ;
    PORT
      LAYER M4 ;
        RECT  0 94.176 0.084 94.2 ;
    END
  END aq[452]
  PIN aq[453]
    DIRECTION OUTPUT ;
    USE SIGNAL ;
    PORT
      LAYER M4 ;
        RECT  0 94.32 0.084 94.344 ;
    END
  END aq[453]
  PIN aq[454]
    DIRECTION OUTPUT ;
    USE SIGNAL ;
    PORT
      LAYER M4 ;
        RECT  0 94.464 0.084 94.488 ;
    END
  END aq[454]
  PIN aq[455]
    DIRECTION OUTPUT ;
    USE SIGNAL ;
    PORT
      LAYER M4 ;
        RECT  0 94.608 0.084 94.632 ;
    END
  END aq[455]
  PIN aq[456]
    DIRECTION OUTPUT ;
    USE SIGNAL ;
    PORT
      LAYER M4 ;
        RECT  0 94.752 0.084 94.776 ;
    END
  END aq[456]
  PIN aq[457]
    DIRECTION OUTPUT ;
    USE SIGNAL ;
    PORT
      LAYER M4 ;
        RECT  0 94.896 0.084 94.92 ;
    END
  END aq[457]
  PIN aq[458]
    DIRECTION OUTPUT ;
    USE SIGNAL ;
    PORT
      LAYER M4 ;
        RECT  0 95.04 0.084 95.064 ;
    END
  END aq[458]
  PIN aq[459]
    DIRECTION OUTPUT ;
    USE SIGNAL ;
    PORT
      LAYER M4 ;
        RECT  0 95.184 0.084 95.208 ;
    END
  END aq[459]
  PIN aq[45]
    DIRECTION OUTPUT ;
    USE SIGNAL ;
    PORT
      LAYER M4 ;
        RECT  0 24.048 0.084 24.072 ;
    END
  END aq[45]
  PIN aq[460]
    DIRECTION OUTPUT ;
    USE SIGNAL ;
    PORT
      LAYER M4 ;
        RECT  0 95.328 0.084 95.352 ;
    END
  END aq[460]
  PIN aq[461]
    DIRECTION OUTPUT ;
    USE SIGNAL ;
    PORT
      LAYER M4 ;
        RECT  0 95.472 0.084 95.496 ;
    END
  END aq[461]
  PIN aq[462]
    DIRECTION OUTPUT ;
    USE SIGNAL ;
    PORT
      LAYER M4 ;
        RECT  0 95.616 0.084 95.64 ;
    END
  END aq[462]
  PIN aq[463]
    DIRECTION OUTPUT ;
    USE SIGNAL ;
    PORT
      LAYER M4 ;
        RECT  0 95.76 0.084 95.784 ;
    END
  END aq[463]
  PIN aq[464]
    DIRECTION OUTPUT ;
    USE SIGNAL ;
    PORT
      LAYER M4 ;
        RECT  0 95.904 0.084 95.928 ;
    END
  END aq[464]
  PIN aq[465]
    DIRECTION OUTPUT ;
    USE SIGNAL ;
    PORT
      LAYER M4 ;
        RECT  0 96.048 0.084 96.072 ;
    END
  END aq[465]
  PIN aq[466]
    DIRECTION OUTPUT ;
    USE SIGNAL ;
    PORT
      LAYER M4 ;
        RECT  0 96.192 0.084 96.216 ;
    END
  END aq[466]
  PIN aq[467]
    DIRECTION OUTPUT ;
    USE SIGNAL ;
    PORT
      LAYER M4 ;
        RECT  0 96.336 0.084 96.36 ;
    END
  END aq[467]
  PIN aq[468]
    DIRECTION OUTPUT ;
    USE SIGNAL ;
    PORT
      LAYER M4 ;
        RECT  0 96.48 0.084 96.504 ;
    END
  END aq[468]
  PIN aq[469]
    DIRECTION OUTPUT ;
    USE SIGNAL ;
    PORT
      LAYER M4 ;
        RECT  0 96.624 0.084 96.648 ;
    END
  END aq[469]
  PIN aq[46]
    DIRECTION OUTPUT ;
    USE SIGNAL ;
    PORT
      LAYER M4 ;
        RECT  0 24.192 0.084 24.216 ;
    END
  END aq[46]
  PIN aq[470]
    DIRECTION OUTPUT ;
    USE SIGNAL ;
    PORT
      LAYER M4 ;
        RECT  0 96.768 0.084 96.792 ;
    END
  END aq[470]
  PIN aq[471]
    DIRECTION OUTPUT ;
    USE SIGNAL ;
    PORT
      LAYER M4 ;
        RECT  0 96.912 0.084 96.936 ;
    END
  END aq[471]
  PIN aq[472]
    DIRECTION OUTPUT ;
    USE SIGNAL ;
    PORT
      LAYER M4 ;
        RECT  0 97.056 0.084 97.08 ;
    END
  END aq[472]
  PIN aq[473]
    DIRECTION OUTPUT ;
    USE SIGNAL ;
    PORT
      LAYER M4 ;
        RECT  0 97.2 0.084 97.224 ;
    END
  END aq[473]
  PIN aq[474]
    DIRECTION OUTPUT ;
    USE SIGNAL ;
    PORT
      LAYER M4 ;
        RECT  0 97.344 0.084 97.368 ;
    END
  END aq[474]
  PIN aq[475]
    DIRECTION OUTPUT ;
    USE SIGNAL ;
    PORT
      LAYER M4 ;
        RECT  0 97.488 0.084 97.512 ;
    END
  END aq[475]
  PIN aq[476]
    DIRECTION OUTPUT ;
    USE SIGNAL ;
    PORT
      LAYER M4 ;
        RECT  0 97.632 0.084 97.656 ;
    END
  END aq[476]
  PIN aq[477]
    DIRECTION OUTPUT ;
    USE SIGNAL ;
    PORT
      LAYER M4 ;
        RECT  0 97.776 0.084 97.8 ;
    END
  END aq[477]
  PIN aq[478]
    DIRECTION OUTPUT ;
    USE SIGNAL ;
    PORT
      LAYER M4 ;
        RECT  0 97.92 0.084 97.944 ;
    END
  END aq[478]
  PIN aq[479]
    DIRECTION OUTPUT ;
    USE SIGNAL ;
    PORT
      LAYER M4 ;
        RECT  0 84.24 0.084 84.264 ;
    END
  END aq[479]
  PIN aq[47]
    DIRECTION OUTPUT ;
    USE SIGNAL ;
    PORT
      LAYER M4 ;
        RECT  0 24.336 0.084 24.36 ;
    END
  END aq[47]
  PIN aq[480]
    DIRECTION OUTPUT ;
    USE SIGNAL ;
    PORT
      LAYER M4 ;
        RECT  0 84.384 0.084 84.408 ;
    END
  END aq[480]
  PIN aq[481]
    DIRECTION OUTPUT ;
    USE SIGNAL ;
    PORT
      LAYER M4 ;
        RECT  0 84.528 0.084 84.552 ;
    END
  END aq[481]
  PIN aq[482]
    DIRECTION OUTPUT ;
    USE SIGNAL ;
    PORT
      LAYER M4 ;
        RECT  0 84.672 0.084 84.696 ;
    END
  END aq[482]
  PIN aq[483]
    DIRECTION OUTPUT ;
    USE SIGNAL ;
    PORT
      LAYER M4 ;
        RECT  0 84.816 0.084 84.84 ;
    END
  END aq[483]
  PIN aq[484]
    DIRECTION OUTPUT ;
    USE SIGNAL ;
    PORT
      LAYER M4 ;
        RECT  0 84.96 0.084 84.984 ;
    END
  END aq[484]
  PIN aq[485]
    DIRECTION OUTPUT ;
    USE SIGNAL ;
    PORT
      LAYER M4 ;
        RECT  0 85.104 0.084 85.128 ;
    END
  END aq[485]
  PIN aq[486]
    DIRECTION OUTPUT ;
    USE SIGNAL ;
    PORT
      LAYER M4 ;
        RECT  0 85.248 0.084 85.272 ;
    END
  END aq[486]
  PIN aq[487]
    DIRECTION OUTPUT ;
    USE SIGNAL ;
    PORT
      LAYER M4 ;
        RECT  0 85.392 0.084 85.416 ;
    END
  END aq[487]
  PIN aq[488]
    DIRECTION OUTPUT ;
    USE SIGNAL ;
    PORT
      LAYER M4 ;
        RECT  0 85.536 0.084 85.56 ;
    END
  END aq[488]
  PIN aq[489]
    DIRECTION OUTPUT ;
    USE SIGNAL ;
    PORT
      LAYER M4 ;
        RECT  0 85.68 0.084 85.704 ;
    END
  END aq[489]
  PIN aq[48]
    DIRECTION OUTPUT ;
    USE SIGNAL ;
    PORT
      LAYER M4 ;
        RECT  0 24.48 0.084 24.504 ;
    END
  END aq[48]
  PIN aq[490]
    DIRECTION OUTPUT ;
    USE SIGNAL ;
    PORT
      LAYER M4 ;
        RECT  0 85.824 0.084 85.848 ;
    END
  END aq[490]
  PIN aq[491]
    DIRECTION OUTPUT ;
    USE SIGNAL ;
    PORT
      LAYER M4 ;
        RECT  0 85.968 0.084 85.992 ;
    END
  END aq[491]
  PIN aq[492]
    DIRECTION OUTPUT ;
    USE SIGNAL ;
    PORT
      LAYER M4 ;
        RECT  0 86.112 0.084 86.136 ;
    END
  END aq[492]
  PIN aq[493]
    DIRECTION OUTPUT ;
    USE SIGNAL ;
    PORT
      LAYER M4 ;
        RECT  0 86.256 0.084 86.28 ;
    END
  END aq[493]
  PIN aq[494]
    DIRECTION OUTPUT ;
    USE SIGNAL ;
    PORT
      LAYER M4 ;
        RECT  0 86.4 0.084 86.424 ;
    END
  END aq[494]
  PIN aq[495]
    DIRECTION OUTPUT ;
    USE SIGNAL ;
    PORT
      LAYER M4 ;
        RECT  0 86.544 0.084 86.568 ;
    END
  END aq[495]
  PIN aq[496]
    DIRECTION OUTPUT ;
    USE SIGNAL ;
    PORT
      LAYER M4 ;
        RECT  0 86.688 0.084 86.712 ;
    END
  END aq[496]
  PIN aq[497]
    DIRECTION OUTPUT ;
    USE SIGNAL ;
    PORT
      LAYER M4 ;
        RECT  0 86.832 0.084 86.856 ;
    END
  END aq[497]
  PIN aq[498]
    DIRECTION OUTPUT ;
    USE SIGNAL ;
    PORT
      LAYER M4 ;
        RECT  0 86.976 0.084 87 ;
    END
  END aq[498]
  PIN aq[499]
    DIRECTION OUTPUT ;
    USE SIGNAL ;
    PORT
      LAYER M4 ;
        RECT  0 87.12 0.084 87.144 ;
    END
  END aq[499]
  PIN aq[49]
    DIRECTION OUTPUT ;
    USE SIGNAL ;
    PORT
      LAYER M4 ;
        RECT  0 24.624 0.084 24.648 ;
    END
  END aq[49]
  PIN aq[4]
    DIRECTION OUTPUT ;
    USE SIGNAL ;
    PORT
      LAYER M4 ;
        RECT  0 74.592 0.084 74.616 ;
    END
  END aq[4]
  PIN aq[500]
    DIRECTION OUTPUT ;
    USE SIGNAL ;
    PORT
      LAYER M4 ;
        RECT  0 87.264 0.084 87.288 ;
    END
  END aq[500]
  PIN aq[501]
    DIRECTION OUTPUT ;
    USE SIGNAL ;
    PORT
      LAYER M4 ;
        RECT  0 87.408 0.084 87.432 ;
    END
  END aq[501]
  PIN aq[502]
    DIRECTION OUTPUT ;
    USE SIGNAL ;
    PORT
      LAYER M4 ;
        RECT  0 87.552 0.084 87.576 ;
    END
  END aq[502]
  PIN aq[503]
    DIRECTION OUTPUT ;
    USE SIGNAL ;
    PORT
      LAYER M4 ;
        RECT  0 87.696 0.084 87.72 ;
    END
  END aq[503]
  PIN aq[504]
    DIRECTION OUTPUT ;
    USE SIGNAL ;
    PORT
      LAYER M4 ;
        RECT  0 87.84 0.084 87.864 ;
    END
  END aq[504]
  PIN aq[505]
    DIRECTION OUTPUT ;
    USE SIGNAL ;
    PORT
      LAYER M4 ;
        RECT  0 87.984 0.084 88.008 ;
    END
  END aq[505]
  PIN aq[506]
    DIRECTION OUTPUT ;
    USE SIGNAL ;
    PORT
      LAYER M4 ;
        RECT  0 88.128 0.084 88.152 ;
    END
  END aq[506]
  PIN aq[507]
    DIRECTION OUTPUT ;
    USE SIGNAL ;
    PORT
      LAYER M4 ;
        RECT  0 88.272 0.084 88.296 ;
    END
  END aq[507]
  PIN aq[508]
    DIRECTION OUTPUT ;
    USE SIGNAL ;
    PORT
      LAYER M4 ;
        RECT  0 88.416 0.084 88.44 ;
    END
  END aq[508]
  PIN aq[509]
    DIRECTION OUTPUT ;
    USE SIGNAL ;
    PORT
      LAYER M4 ;
        RECT  0 88.56 0.084 88.584 ;
    END
  END aq[509]
  PIN aq[50]
    DIRECTION OUTPUT ;
    USE SIGNAL ;
    PORT
      LAYER M4 ;
        RECT  0 24.768 0.084 24.792 ;
    END
  END aq[50]
  PIN aq[510]
    DIRECTION OUTPUT ;
    USE SIGNAL ;
    PORT
      LAYER M4 ;
        RECT  0 88.704 0.084 88.728 ;
    END
  END aq[510]
  PIN aq[511]
    DIRECTION OUTPUT ;
    USE SIGNAL ;
    PORT
      LAYER M4 ;
        RECT  0 16.272 0.084 16.296 ;
    END
  END aq[511]
  PIN aq[512]
    DIRECTION OUTPUT ;
    USE SIGNAL ;
    PORT
      LAYER M4 ;
        RECT  0 16.416 0.084 16.44 ;
    END
  END aq[512]
  PIN aq[513]
    DIRECTION OUTPUT ;
    USE SIGNAL ;
    PORT
      LAYER M4 ;
        RECT  0 16.56 0.084 16.584 ;
    END
  END aq[513]
  PIN aq[514]
    DIRECTION OUTPUT ;
    USE SIGNAL ;
    PORT
      LAYER M4 ;
        RECT  0 16.704 0.084 16.728 ;
    END
  END aq[514]
  PIN aq[515]
    DIRECTION OUTPUT ;
    USE SIGNAL ;
    PORT
      LAYER M4 ;
        RECT  0 16.848 0.084 16.872 ;
    END
  END aq[515]
  PIN aq[516]
    DIRECTION OUTPUT ;
    USE SIGNAL ;
    PORT
      LAYER M4 ;
        RECT  0 16.992 0.084 17.016 ;
    END
  END aq[516]
  PIN aq[517]
    DIRECTION OUTPUT ;
    USE SIGNAL ;
    PORT
      LAYER M4 ;
        RECT  0 17.136 0.084 17.16 ;
    END
  END aq[517]
  PIN aq[518]
    DIRECTION OUTPUT ;
    USE SIGNAL ;
    PORT
      LAYER M4 ;
        RECT  0 17.28 0.084 17.304 ;
    END
  END aq[518]
  PIN aq[519]
    DIRECTION OUTPUT ;
    USE SIGNAL ;
    PORT
      LAYER M4 ;
        RECT  0 17.424 0.084 17.448 ;
    END
  END aq[519]
  PIN aq[51]
    DIRECTION OUTPUT ;
    USE SIGNAL ;
    PORT
      LAYER M4 ;
        RECT  0 24.912 0.084 24.936 ;
    END
  END aq[51]
  PIN aq[520]
    DIRECTION OUTPUT ;
    USE SIGNAL ;
    PORT
      LAYER M4 ;
        RECT  0 17.568 0.084 17.592 ;
    END
  END aq[520]
  PIN aq[521]
    DIRECTION OUTPUT ;
    USE SIGNAL ;
    PORT
      LAYER M4 ;
        RECT  0 17.712 0.084 17.736 ;
    END
  END aq[521]
  PIN aq[522]
    DIRECTION OUTPUT ;
    USE SIGNAL ;
    PORT
      LAYER M4 ;
        RECT  0 17.856 0.084 17.88 ;
    END
  END aq[522]
  PIN aq[523]
    DIRECTION OUTPUT ;
    USE SIGNAL ;
    PORT
      LAYER M4 ;
        RECT  0 18 0.084 18.024 ;
    END
  END aq[523]
  PIN aq[524]
    DIRECTION OUTPUT ;
    USE SIGNAL ;
    PORT
      LAYER M4 ;
        RECT  0 18.144 0.084 18.168 ;
    END
  END aq[524]
  PIN aq[525]
    DIRECTION OUTPUT ;
    USE SIGNAL ;
    PORT
      LAYER M4 ;
        RECT  0 18.288 0.084 18.312 ;
    END
  END aq[525]
  PIN aq[526]
    DIRECTION OUTPUT ;
    USE SIGNAL ;
    PORT
      LAYER M4 ;
        RECT  0 18.432 0.084 18.456 ;
    END
  END aq[526]
  PIN aq[527]
    DIRECTION OUTPUT ;
    USE SIGNAL ;
    PORT
      LAYER M4 ;
        RECT  0 18.576 0.084 18.6 ;
    END
  END aq[527]
  PIN aq[528]
    DIRECTION OUTPUT ;
    USE SIGNAL ;
    PORT
      LAYER M4 ;
        RECT  0 18.72 0.084 18.744 ;
    END
  END aq[528]
  PIN aq[529]
    DIRECTION OUTPUT ;
    USE SIGNAL ;
    PORT
      LAYER M4 ;
        RECT  0 18.864 0.084 18.888 ;
    END
  END aq[529]
  PIN aq[52]
    DIRECTION OUTPUT ;
    USE SIGNAL ;
    PORT
      LAYER M4 ;
        RECT  0 25.056 0.084 25.08 ;
    END
  END aq[52]
  PIN aq[530]
    DIRECTION OUTPUT ;
    USE SIGNAL ;
    PORT
      LAYER M4 ;
        RECT  0 19.008 0.084 19.032 ;
    END
  END aq[530]
  PIN aq[531]
    DIRECTION OUTPUT ;
    USE SIGNAL ;
    PORT
      LAYER M4 ;
        RECT  0 19.152 0.084 19.176 ;
    END
  END aq[531]
  PIN aq[532]
    DIRECTION OUTPUT ;
    USE SIGNAL ;
    PORT
      LAYER M4 ;
        RECT  0 19.296 0.084 19.32 ;
    END
  END aq[532]
  PIN aq[533]
    DIRECTION OUTPUT ;
    USE SIGNAL ;
    PORT
      LAYER M4 ;
        RECT  0 19.44 0.084 19.464 ;
    END
  END aq[533]
  PIN aq[534]
    DIRECTION OUTPUT ;
    USE SIGNAL ;
    PORT
      LAYER M4 ;
        RECT  0 19.584 0.084 19.608 ;
    END
  END aq[534]
  PIN aq[535]
    DIRECTION OUTPUT ;
    USE SIGNAL ;
    PORT
      LAYER M4 ;
        RECT  0 19.728 0.084 19.752 ;
    END
  END aq[535]
  PIN aq[536]
    DIRECTION OUTPUT ;
    USE SIGNAL ;
    PORT
      LAYER M4 ;
        RECT  0 19.872 0.084 19.896 ;
    END
  END aq[536]
  PIN aq[537]
    DIRECTION OUTPUT ;
    USE SIGNAL ;
    PORT
      LAYER M4 ;
        RECT  0 20.016 0.084 20.04 ;
    END
  END aq[537]
  PIN aq[538]
    DIRECTION OUTPUT ;
    USE SIGNAL ;
    PORT
      LAYER M4 ;
        RECT  0 20.16 0.084 20.184 ;
    END
  END aq[538]
  PIN aq[539]
    DIRECTION OUTPUT ;
    USE SIGNAL ;
    PORT
      LAYER M4 ;
        RECT  0 20.304 0.084 20.328 ;
    END
  END aq[539]
  PIN aq[53]
    DIRECTION OUTPUT ;
    USE SIGNAL ;
    PORT
      LAYER M4 ;
        RECT  0 25.2 0.084 25.224 ;
    END
  END aq[53]
  PIN aq[54]
    DIRECTION OUTPUT ;
    USE SIGNAL ;
    PORT
      LAYER M4 ;
        RECT  0 25.344 0.084 25.368 ;
    END
  END aq[54]
  PIN aq[55]
    DIRECTION OUTPUT ;
    USE SIGNAL ;
    PORT
      LAYER M4 ;
        RECT  0 25.488 0.084 25.512 ;
    END
  END aq[55]
  PIN aq[56]
    DIRECTION OUTPUT ;
    USE SIGNAL ;
    PORT
      LAYER M4 ;
        RECT  0 25.632 0.084 25.656 ;
    END
  END aq[56]
  PIN aq[57]
    DIRECTION OUTPUT ;
    USE SIGNAL ;
    PORT
      LAYER M4 ;
        RECT  0 25.776 0.084 25.8 ;
    END
  END aq[57]
  PIN aq[58]
    DIRECTION OUTPUT ;
    USE SIGNAL ;
    PORT
      LAYER M4 ;
        RECT  0 25.92 0.084 25.944 ;
    END
  END aq[58]
  PIN aq[59]
    DIRECTION OUTPUT ;
    USE SIGNAL ;
    PORT
      LAYER M4 ;
        RECT  0 26.064 0.084 26.088 ;
    END
  END aq[59]
  PIN aq[5]
    DIRECTION OUTPUT ;
    USE SIGNAL ;
    PORT
      LAYER M4 ;
        RECT  0 74.736 0.084 74.76 ;
    END
  END aq[5]
  PIN aq[60]
    DIRECTION OUTPUT ;
    USE SIGNAL ;
    PORT
      LAYER M4 ;
        RECT  0 26.208 0.084 26.232 ;
    END
  END aq[60]
  PIN aq[61]
    DIRECTION OUTPUT ;
    USE SIGNAL ;
    PORT
      LAYER M4 ;
        RECT  0 26.352 0.084 26.376 ;
    END
  END aq[61]
  PIN aq[62]
    DIRECTION OUTPUT ;
    USE SIGNAL ;
    PORT
      LAYER M4 ;
        RECT  0 26.496 0.084 26.52 ;
    END
  END aq[62]
  PIN aq[63]
    DIRECTION OUTPUT ;
    USE SIGNAL ;
    PORT
      LAYER M4 ;
        RECT  0 50.832 0.084 50.856 ;
    END
  END aq[63]
  PIN aq[64]
    DIRECTION OUTPUT ;
    USE SIGNAL ;
    PORT
      LAYER M4 ;
        RECT  0 50.976 0.084 51 ;
    END
  END aq[64]
  PIN aq[65]
    DIRECTION OUTPUT ;
    USE SIGNAL ;
    PORT
      LAYER M4 ;
        RECT  0 51.12 0.084 51.144 ;
    END
  END aq[65]
  PIN aq[66]
    DIRECTION OUTPUT ;
    USE SIGNAL ;
    PORT
      LAYER M4 ;
        RECT  0 51.264 0.084 51.288 ;
    END
  END aq[66]
  PIN aq[67]
    DIRECTION OUTPUT ;
    USE SIGNAL ;
    PORT
      LAYER M4 ;
        RECT  0 51.408 0.084 51.432 ;
    END
  END aq[67]
  PIN aq[68]
    DIRECTION OUTPUT ;
    USE SIGNAL ;
    PORT
      LAYER M4 ;
        RECT  0 51.552 0.084 51.576 ;
    END
  END aq[68]
  PIN aq[69]
    DIRECTION OUTPUT ;
    USE SIGNAL ;
    PORT
      LAYER M4 ;
        RECT  0 51.696 0.084 51.72 ;
    END
  END aq[69]
  PIN aq[6]
    DIRECTION OUTPUT ;
    USE SIGNAL ;
    PORT
      LAYER M4 ;
        RECT  0 74.88 0.084 74.904 ;
    END
  END aq[6]
  PIN aq[70]
    DIRECTION OUTPUT ;
    USE SIGNAL ;
    PORT
      LAYER M4 ;
        RECT  0 51.84 0.084 51.864 ;
    END
  END aq[70]
  PIN aq[71]
    DIRECTION OUTPUT ;
    USE SIGNAL ;
    PORT
      LAYER M4 ;
        RECT  0 51.984 0.084 52.008 ;
    END
  END aq[71]
  PIN aq[72]
    DIRECTION OUTPUT ;
    USE SIGNAL ;
    PORT
      LAYER M4 ;
        RECT  0 52.128 0.084 52.152 ;
    END
  END aq[72]
  PIN aq[73]
    DIRECTION OUTPUT ;
    USE SIGNAL ;
    PORT
      LAYER M4 ;
        RECT  0 52.272 0.084 52.296 ;
    END
  END aq[73]
  PIN aq[74]
    DIRECTION OUTPUT ;
    USE SIGNAL ;
    PORT
      LAYER M4 ;
        RECT  0 52.416 0.084 52.44 ;
    END
  END aq[74]
  PIN aq[75]
    DIRECTION OUTPUT ;
    USE SIGNAL ;
    PORT
      LAYER M4 ;
        RECT  0 52.56 0.084 52.584 ;
    END
  END aq[75]
  PIN aq[76]
    DIRECTION OUTPUT ;
    USE SIGNAL ;
    PORT
      LAYER M4 ;
        RECT  0 52.704 0.084 52.728 ;
    END
  END aq[76]
  PIN aq[77]
    DIRECTION OUTPUT ;
    USE SIGNAL ;
    PORT
      LAYER M4 ;
        RECT  0 52.848 0.084 52.872 ;
    END
  END aq[77]
  PIN aq[78]
    DIRECTION OUTPUT ;
    USE SIGNAL ;
    PORT
      LAYER M4 ;
        RECT  0 52.992 0.084 53.016 ;
    END
  END aq[78]
  PIN aq[79]
    DIRECTION OUTPUT ;
    USE SIGNAL ;
    PORT
      LAYER M4 ;
        RECT  0 53.136 0.084 53.16 ;
    END
  END aq[79]
  PIN aq[7]
    DIRECTION OUTPUT ;
    USE SIGNAL ;
    PORT
      LAYER M4 ;
        RECT  0 75.024 0.084 75.048 ;
    END
  END aq[7]
  PIN aq[80]
    DIRECTION OUTPUT ;
    USE SIGNAL ;
    PORT
      LAYER M4 ;
        RECT  0 53.28 0.084 53.304 ;
    END
  END aq[80]
  PIN aq[81]
    DIRECTION OUTPUT ;
    USE SIGNAL ;
    PORT
      LAYER M4 ;
        RECT  0 53.424 0.084 53.448 ;
    END
  END aq[81]
  PIN aq[82]
    DIRECTION OUTPUT ;
    USE SIGNAL ;
    PORT
      LAYER M4 ;
        RECT  0 53.568 0.084 53.592 ;
    END
  END aq[82]
  PIN aq[83]
    DIRECTION OUTPUT ;
    USE SIGNAL ;
    PORT
      LAYER M4 ;
        RECT  0 53.712 0.084 53.736 ;
    END
  END aq[83]
  PIN aq[84]
    DIRECTION OUTPUT ;
    USE SIGNAL ;
    PORT
      LAYER M4 ;
        RECT  0 53.856 0.084 53.88 ;
    END
  END aq[84]
  PIN aq[85]
    DIRECTION OUTPUT ;
    USE SIGNAL ;
    PORT
      LAYER M4 ;
        RECT  0 54 0.084 54.024 ;
    END
  END aq[85]
  PIN aq[86]
    DIRECTION OUTPUT ;
    USE SIGNAL ;
    PORT
      LAYER M4 ;
        RECT  0 54.144 0.084 54.168 ;
    END
  END aq[86]
  PIN aq[87]
    DIRECTION OUTPUT ;
    USE SIGNAL ;
    PORT
      LAYER M4 ;
        RECT  0 54.288 0.084 54.312 ;
    END
  END aq[87]
  PIN aq[88]
    DIRECTION OUTPUT ;
    USE SIGNAL ;
    PORT
      LAYER M4 ;
        RECT  0 54.432 0.084 54.456 ;
    END
  END aq[88]
  PIN aq[89]
    DIRECTION OUTPUT ;
    USE SIGNAL ;
    PORT
      LAYER M4 ;
        RECT  0 54.576 0.084 54.6 ;
    END
  END aq[89]
  PIN aq[8]
    DIRECTION OUTPUT ;
    USE SIGNAL ;
    PORT
      LAYER M4 ;
        RECT  0 75.168 0.084 75.192 ;
    END
  END aq[8]
  PIN aq[90]
    DIRECTION OUTPUT ;
    USE SIGNAL ;
    PORT
      LAYER M4 ;
        RECT  0 54.72 0.084 54.744 ;
    END
  END aq[90]
  PIN aq[91]
    DIRECTION OUTPUT ;
    USE SIGNAL ;
    PORT
      LAYER M4 ;
        RECT  0 54.864 0.084 54.888 ;
    END
  END aq[91]
  PIN aq[92]
    DIRECTION OUTPUT ;
    USE SIGNAL ;
    PORT
      LAYER M4 ;
        RECT  0 55.008 0.084 55.032 ;
    END
  END aq[92]
  PIN aq[93]
    DIRECTION OUTPUT ;
    USE SIGNAL ;
    PORT
      LAYER M4 ;
        RECT  0 55.152 0.084 55.176 ;
    END
  END aq[93]
  PIN aq[94]
    DIRECTION OUTPUT ;
    USE SIGNAL ;
    PORT
      LAYER M4 ;
        RECT  0 55.296 0.084 55.32 ;
    END
  END aq[94]
  PIN aq[95]
    DIRECTION OUTPUT ;
    USE SIGNAL ;
    PORT
      LAYER M4 ;
        RECT  0 64.656 0.084 64.68 ;
    END
  END aq[95]
  PIN aq[96]
    DIRECTION OUTPUT ;
    USE SIGNAL ;
    PORT
      LAYER M4 ;
        RECT  0 64.8 0.084 64.824 ;
    END
  END aq[96]
  PIN aq[97]
    DIRECTION OUTPUT ;
    USE SIGNAL ;
    PORT
      LAYER M4 ;
        RECT  0 64.944 0.084 64.968 ;
    END
  END aq[97]
  PIN aq[98]
    DIRECTION OUTPUT ;
    USE SIGNAL ;
    PORT
      LAYER M4 ;
        RECT  0 65.088 0.084 65.112 ;
    END
  END aq[98]
  PIN aq[99]
    DIRECTION OUTPUT ;
    USE SIGNAL ;
    PORT
      LAYER M4 ;
        RECT  0 65.232 0.084 65.256 ;
    END
  END aq[99]
  PIN aq[9]
    DIRECTION OUTPUT ;
    USE SIGNAL ;
    PORT
      LAYER M4 ;
        RECT  0 75.312 0.084 75.336 ;
    END
  END aq[9]
  PIN aqm[0]
    DIRECTION INPUT ;
    USE SIGNAL ;
    PORT
      LAYER M4 ;
        RECT  32.316 48.096 32.4 48.12 ;
    END
  END aqm[0]
  PIN aqm[10]
    DIRECTION INPUT ;
    USE SIGNAL ;
    PORT
      LAYER M4 ;
        RECT  32.316 49.536 32.4 49.56 ;
    END
  END aqm[10]
  PIN aqm[11]
    DIRECTION INPUT ;
    USE SIGNAL ;
    PORT
      LAYER M4 ;
        RECT  32.316 49.68 32.4 49.704 ;
    END
  END aqm[11]
  PIN aqm[12]
    DIRECTION INPUT ;
    USE SIGNAL ;
    PORT
      LAYER M4 ;
        RECT  32.316 49.824 32.4 49.848 ;
    END
  END aqm[12]
  PIN aqm[13]
    DIRECTION INPUT ;
    USE SIGNAL ;
    PORT
      LAYER M4 ;
        RECT  32.316 49.968 32.4 49.992 ;
    END
  END aqm[13]
  PIN aqm[14]
    DIRECTION INPUT ;
    USE SIGNAL ;
    PORT
      LAYER M4 ;
        RECT  32.316 50.112 32.4 50.136 ;
    END
  END aqm[14]
  PIN aqm[15]
    DIRECTION INPUT ;
    USE SIGNAL ;
    PORT
      LAYER M4 ;
        RECT  32.316 50.256 32.4 50.28 ;
    END
  END aqm[15]
  PIN aqm[16]
    DIRECTION INPUT ;
    USE SIGNAL ;
    PORT
      LAYER M4 ;
        RECT  32.316 50.4 32.4 50.424 ;
    END
  END aqm[16]
  PIN aqm[17]
    DIRECTION INPUT ;
    USE SIGNAL ;
    PORT
      LAYER M4 ;
        RECT  32.316 50.544 32.4 50.568 ;
    END
  END aqm[17]
  PIN aqm[18]
    DIRECTION INPUT ;
    USE SIGNAL ;
    PORT
      LAYER M4 ;
        RECT  32.316 50.688 32.4 50.712 ;
    END
  END aqm[18]
  PIN aqm[19]
    DIRECTION INPUT ;
    USE SIGNAL ;
    PORT
      LAYER M4 ;
        RECT  32.316 50.832 32.4 50.856 ;
    END
  END aqm[19]
  PIN aqm[1]
    DIRECTION INPUT ;
    USE SIGNAL ;
    PORT
      LAYER M4 ;
        RECT  32.316 48.24 32.4 48.264 ;
    END
  END aqm[1]
  PIN aqm[20]
    DIRECTION INPUT ;
    USE SIGNAL ;
    PORT
      LAYER M4 ;
        RECT  32.316 50.976 32.4 51 ;
    END
  END aqm[20]
  PIN aqm[21]
    DIRECTION INPUT ;
    USE SIGNAL ;
    PORT
      LAYER M4 ;
        RECT  32.316 51.12 32.4 51.144 ;
    END
  END aqm[21]
  PIN aqm[22]
    DIRECTION INPUT ;
    USE SIGNAL ;
    PORT
      LAYER M4 ;
        RECT  32.316 51.264 32.4 51.288 ;
    END
  END aqm[22]
  PIN aqm[23]
    DIRECTION INPUT ;
    USE SIGNAL ;
    PORT
      LAYER M4 ;
        RECT  32.316 51.408 32.4 51.432 ;
    END
  END aqm[23]
  PIN aqm[24]
    DIRECTION INPUT ;
    USE SIGNAL ;
    PORT
      LAYER M4 ;
        RECT  32.316 51.552 32.4 51.576 ;
    END
  END aqm[24]
  PIN aqm[25]
    DIRECTION INPUT ;
    USE SIGNAL ;
    PORT
      LAYER M4 ;
        RECT  32.316 51.696 32.4 51.72 ;
    END
  END aqm[25]
  PIN aqm[26]
    DIRECTION INPUT ;
    USE SIGNAL ;
    PORT
      LAYER M4 ;
        RECT  32.316 51.84 32.4 51.864 ;
    END
  END aqm[26]
  PIN aqm[27]
    DIRECTION INPUT ;
    USE SIGNAL ;
    PORT
      LAYER M4 ;
        RECT  32.316 51.984 32.4 52.008 ;
    END
  END aqm[27]
  PIN aqm[2]
    DIRECTION INPUT ;
    USE SIGNAL ;
    PORT
      LAYER M4 ;
        RECT  32.316 48.384 32.4 48.408 ;
    END
  END aqm[2]
  PIN aqm[3]
    DIRECTION INPUT ;
    USE SIGNAL ;
    PORT
      LAYER M4 ;
        RECT  32.316 48.528 32.4 48.552 ;
    END
  END aqm[3]
  PIN aqm[4]
    DIRECTION INPUT ;
    USE SIGNAL ;
    PORT
      LAYER M4 ;
        RECT  32.316 48.672 32.4 48.696 ;
    END
  END aqm[4]
  PIN aqm[5]
    DIRECTION INPUT ;
    USE SIGNAL ;
    PORT
      LAYER M4 ;
        RECT  32.316 48.816 32.4 48.84 ;
    END
  END aqm[5]
  PIN aqm[6]
    DIRECTION INPUT ;
    USE SIGNAL ;
    PORT
      LAYER M4 ;
        RECT  32.316 48.96 32.4 48.984 ;
    END
  END aqm[6]
  PIN aqm[7]
    DIRECTION INPUT ;
    USE SIGNAL ;
    PORT
      LAYER M4 ;
        RECT  32.316 49.104 32.4 49.128 ;
    END
  END aqm[7]
  PIN aqm[8]
    DIRECTION INPUT ;
    USE SIGNAL ;
    PORT
      LAYER M4 ;
        RECT  32.316 49.248 32.4 49.272 ;
    END
  END aqm[8]
  PIN aqm[9]
    DIRECTION INPUT ;
    USE SIGNAL ;
    PORT
      LAYER M4 ;
        RECT  32.316 49.392 32.4 49.416 ;
    END
  END aqm[9]
  PIN ck
    DIRECTION INPUT ;
    USE SIGNAL ;
    PORT
      LAYER M5 ;
        RECT  24.624 107.916 24.648 108 ;
    END
    PORT
      LAYER M5 ;
        RECT  24.624 105.863 24.648 107.984 ;
    END
  END ck
  PIN kc[0]
    DIRECTION OUTPUT ;
    USE SIGNAL ;
    PORT
      LAYER M4 ;
        RECT  0 20.448 0.084 20.472 ;
    END
  END kc[0]
  PIN kc[10]
    DIRECTION OUTPUT ;
    USE SIGNAL ;
    PORT
      LAYER M4 ;
        RECT  0 12.96 0.084 12.984 ;
    END
  END kc[10]
  PIN kc[11]
    DIRECTION OUTPUT ;
    USE SIGNAL ;
    PORT
      LAYER M4 ;
        RECT  0 13.104 0.084 13.128 ;
    END
  END kc[11]
  PIN kc[12]
    DIRECTION OUTPUT ;
    USE SIGNAL ;
    PORT
      LAYER M4 ;
        RECT  0 13.248 0.084 13.272 ;
    END
  END kc[12]
  PIN kc[13]
    DIRECTION OUTPUT ;
    USE SIGNAL ;
    PORT
      LAYER M4 ;
        RECT  0 13.392 0.084 13.416 ;
    END
  END kc[13]
  PIN kc[14]
    DIRECTION OUTPUT ;
    USE SIGNAL ;
    PORT
      LAYER M4 ;
        RECT  0 13.536 0.084 13.56 ;
    END
  END kc[14]
  PIN kc[15]
    DIRECTION OUTPUT ;
    USE SIGNAL ;
    PORT
      LAYER M4 ;
        RECT  0 13.68 0.084 13.704 ;
    END
  END kc[15]
  PIN kc[16]
    DIRECTION OUTPUT ;
    USE SIGNAL ;
    PORT
      LAYER M4 ;
        RECT  0 13.824 0.084 13.848 ;
    END
  END kc[16]
  PIN kc[17]
    DIRECTION OUTPUT ;
    USE SIGNAL ;
    PORT
      LAYER M4 ;
        RECT  0 13.968 0.084 13.992 ;
    END
  END kc[17]
  PIN kc[18]
    DIRECTION OUTPUT ;
    USE SIGNAL ;
    PORT
      LAYER M4 ;
        RECT  0 14.112 0.084 14.136 ;
    END
  END kc[18]
  PIN kc[19]
    DIRECTION OUTPUT ;
    USE SIGNAL ;
    PORT
      LAYER M4 ;
        RECT  0 14.256 0.084 14.28 ;
    END
  END kc[19]
  PIN kc[1]
    DIRECTION OUTPUT ;
    USE SIGNAL ;
    PORT
      LAYER M4 ;
        RECT  0 20.592 0.084 20.616 ;
    END
  END kc[1]
  PIN kc[20]
    DIRECTION OUTPUT ;
    USE SIGNAL ;
    PORT
      LAYER M4 ;
        RECT  0 14.4 0.084 14.424 ;
    END
  END kc[20]
  PIN kc[21]
    DIRECTION OUTPUT ;
    USE SIGNAL ;
    PORT
      LAYER M4 ;
        RECT  0 14.544 0.084 14.568 ;
    END
  END kc[21]
  PIN kc[22]
    DIRECTION OUTPUT ;
    USE SIGNAL ;
    PORT
      LAYER M4 ;
        RECT  0 14.688 0.084 14.712 ;
    END
  END kc[22]
  PIN kc[23]
    DIRECTION OUTPUT ;
    USE SIGNAL ;
    PORT
      LAYER M4 ;
        RECT  0 14.832 0.084 14.856 ;
    END
  END kc[23]
  PIN kc[24]
    DIRECTION OUTPUT ;
    USE SIGNAL ;
    PORT
      LAYER M4 ;
        RECT  0 14.976 0.084 15 ;
    END
  END kc[24]
  PIN kc[25]
    DIRECTION OUTPUT ;
    USE SIGNAL ;
    PORT
      LAYER M4 ;
        RECT  0 15.12 0.084 15.144 ;
    END
  END kc[25]
  PIN kc[26]
    DIRECTION OUTPUT ;
    USE SIGNAL ;
    PORT
      LAYER M4 ;
        RECT  0 15.264 0.084 15.288 ;
    END
  END kc[26]
  PIN kc[27]
    DIRECTION OUTPUT ;
    USE SIGNAL ;
    PORT
      LAYER M4 ;
        RECT  0 15.408 0.084 15.432 ;
    END
  END kc[27]
  PIN kc[28]
    DIRECTION OUTPUT ;
    USE SIGNAL ;
    PORT
      LAYER M4 ;
        RECT  0 15.552 0.084 15.576 ;
    END
  END kc[28]
  PIN kc[29]
    DIRECTION OUTPUT ;
    USE SIGNAL ;
    PORT
      LAYER M4 ;
        RECT  0 15.696 0.084 15.72 ;
    END
  END kc[29]
  PIN kc[2]
    DIRECTION OUTPUT ;
    USE SIGNAL ;
    PORT
      LAYER M4 ;
        RECT  0 20.736 0.084 20.76 ;
    END
  END kc[2]
  PIN kc[30]
    DIRECTION OUTPUT ;
    USE SIGNAL ;
    PORT
      LAYER M4 ;
        RECT  0 15.84 0.084 15.864 ;
    END
  END kc[30]
  PIN kc[31]
    DIRECTION OUTPUT ;
    USE SIGNAL ;
    PORT
      LAYER M4 ;
        RECT  0 15.984 0.084 16.008 ;
    END
  END kc[31]
  PIN kc[32]
    DIRECTION OUTPUT ;
    USE SIGNAL ;
    PORT
      LAYER M4 ;
        RECT  0 16.128 0.084 16.152 ;
    END
  END kc[32]
  PIN kc[3]
    DIRECTION OUTPUT ;
    USE SIGNAL ;
    PORT
      LAYER M4 ;
        RECT  0 11.952 0.084 11.976 ;
    END
  END kc[3]
  PIN kc[4]
    DIRECTION OUTPUT ;
    USE SIGNAL ;
    PORT
      LAYER M4 ;
        RECT  0 12.096 0.084 12.12 ;
    END
  END kc[4]
  PIN kc[5]
    DIRECTION OUTPUT ;
    USE SIGNAL ;
    PORT
      LAYER M4 ;
        RECT  0 12.24 0.084 12.264 ;
    END
  END kc[5]
  PIN kc[6]
    DIRECTION OUTPUT ;
    USE SIGNAL ;
    PORT
      LAYER M4 ;
        RECT  0 12.384 0.084 12.408 ;
    END
  END kc[6]
  PIN kc[7]
    DIRECTION OUTPUT ;
    USE SIGNAL ;
    PORT
      LAYER M4 ;
        RECT  0 12.528 0.084 12.552 ;
    END
  END kc[7]
  PIN kc[8]
    DIRECTION OUTPUT ;
    USE SIGNAL ;
    PORT
      LAYER M4 ;
        RECT  0 12.672 0.084 12.696 ;
    END
  END kc[8]
  PIN kc[9]
    DIRECTION OUTPUT ;
    USE SIGNAL ;
    PORT
      LAYER M4 ;
        RECT  0 12.816 0.084 12.84 ;
    END
  END kc[9]
  PIN kc_i[0]
    DIRECTION INPUT ;
    USE SIGNAL ;
    PORT
      LAYER M4 ;
        RECT  32.316 52.128 32.4 52.152 ;
    END
  END kc_i[0]
  PIN kc_i[10]
    DIRECTION INPUT ;
    USE SIGNAL ;
    PORT
      LAYER M4 ;
        RECT  32.316 39.744 32.4 39.768 ;
    END
  END kc_i[10]
  PIN kc_i[11]
    DIRECTION INPUT ;
    USE SIGNAL ;
    PORT
      LAYER M4 ;
        RECT  32.316 39.888 32.4 39.912 ;
    END
  END kc_i[11]
  PIN kc_i[12]
    DIRECTION INPUT ;
    USE SIGNAL ;
    PORT
      LAYER M4 ;
        RECT  32.316 40.032 32.4 40.056 ;
    END
  END kc_i[12]
  PIN kc_i[13]
    DIRECTION INPUT ;
    USE SIGNAL ;
    PORT
      LAYER M4 ;
        RECT  32.316 40.176 32.4 40.2 ;
    END
  END kc_i[13]
  PIN kc_i[14]
    DIRECTION INPUT ;
    USE SIGNAL ;
    PORT
      LAYER M4 ;
        RECT  32.316 40.32 32.4 40.344 ;
    END
  END kc_i[14]
  PIN kc_i[15]
    DIRECTION INPUT ;
    USE SIGNAL ;
    PORT
      LAYER M4 ;
        RECT  32.316 40.464 32.4 40.488 ;
    END
  END kc_i[15]
  PIN kc_i[16]
    DIRECTION INPUT ;
    USE SIGNAL ;
    PORT
      LAYER M4 ;
        RECT  32.316 40.608 32.4 40.632 ;
    END
  END kc_i[16]
  PIN kc_i[17]
    DIRECTION INPUT ;
    USE SIGNAL ;
    PORT
      LAYER M4 ;
        RECT  32.316 40.752 32.4 40.776 ;
    END
  END kc_i[17]
  PIN kc_i[18]
    DIRECTION INPUT ;
    USE SIGNAL ;
    PORT
      LAYER M4 ;
        RECT  32.316 40.896 32.4 40.92 ;
    END
  END kc_i[18]
  PIN kc_i[19]
    DIRECTION INPUT ;
    USE SIGNAL ;
    PORT
      LAYER M4 ;
        RECT  32.316 41.04 32.4 41.064 ;
    END
  END kc_i[19]
  PIN kc_i[1]
    DIRECTION INPUT ;
    USE SIGNAL ;
    PORT
      LAYER M4 ;
        RECT  32.316 52.272 32.4 52.296 ;
    END
  END kc_i[1]
  PIN kc_i[20]
    DIRECTION INPUT ;
    USE SIGNAL ;
    PORT
      LAYER M4 ;
        RECT  32.316 41.184 32.4 41.208 ;
    END
  END kc_i[20]
  PIN kc_i[21]
    DIRECTION INPUT ;
    USE SIGNAL ;
    PORT
      LAYER M4 ;
        RECT  32.316 41.328 32.4 41.352 ;
    END
  END kc_i[21]
  PIN kc_i[22]
    DIRECTION INPUT ;
    USE SIGNAL ;
    PORT
      LAYER M4 ;
        RECT  32.316 41.472 32.4 41.496 ;
    END
  END kc_i[22]
  PIN kc_i[23]
    DIRECTION INPUT ;
    USE SIGNAL ;
    PORT
      LAYER M4 ;
        RECT  32.316 41.616 32.4 41.64 ;
    END
  END kc_i[23]
  PIN kc_i[24]
    DIRECTION INPUT ;
    USE SIGNAL ;
    PORT
      LAYER M4 ;
        RECT  32.316 41.76 32.4 41.784 ;
    END
  END kc_i[24]
  PIN kc_i[25]
    DIRECTION INPUT ;
    USE SIGNAL ;
    PORT
      LAYER M4 ;
        RECT  32.316 41.904 32.4 41.928 ;
    END
  END kc_i[25]
  PIN kc_i[26]
    DIRECTION INPUT ;
    USE SIGNAL ;
    PORT
      LAYER M4 ;
        RECT  32.316 42.048 32.4 42.072 ;
    END
  END kc_i[26]
  PIN kc_i[27]
    DIRECTION INPUT ;
    USE SIGNAL ;
    PORT
      LAYER M4 ;
        RECT  32.316 42.192 32.4 42.216 ;
    END
  END kc_i[27]
  PIN kc_i[28]
    DIRECTION INPUT ;
    USE SIGNAL ;
    PORT
      LAYER M4 ;
        RECT  32.316 42.336 32.4 42.36 ;
    END
  END kc_i[28]
  PIN kc_i[29]
    DIRECTION INPUT ;
    USE SIGNAL ;
    PORT
      LAYER M4 ;
        RECT  32.316 42.48 32.4 42.504 ;
    END
  END kc_i[29]
  PIN kc_i[2]
    DIRECTION INPUT ;
    USE SIGNAL ;
    PORT
      LAYER M4 ;
        RECT  32.316 52.416 32.4 52.44 ;
    END
  END kc_i[2]
  PIN kc_i[30]
    DIRECTION INPUT ;
    USE SIGNAL ;
    PORT
      LAYER M4 ;
        RECT  32.316 42.624 32.4 42.648 ;
    END
  END kc_i[30]
  PIN kc_i[31]
    DIRECTION INPUT ;
    USE SIGNAL ;
    PORT
      LAYER M4 ;
        RECT  32.316 42.768 32.4 42.792 ;
    END
  END kc_i[31]
  PIN kc_i[32]
    DIRECTION INPUT ;
    USE SIGNAL ;
    PORT
      LAYER M4 ;
        RECT  32.316 42.912 32.4 42.936 ;
    END
  END kc_i[32]
  PIN kc_i[3]
    DIRECTION INPUT ;
    USE SIGNAL ;
    PORT
      LAYER M4 ;
        RECT  32.316 38.736 32.4 38.76 ;
    END
  END kc_i[3]
  PIN kc_i[4]
    DIRECTION INPUT ;
    USE SIGNAL ;
    PORT
      LAYER M4 ;
        RECT  32.316 38.88 32.4 38.904 ;
    END
  END kc_i[4]
  PIN kc_i[5]
    DIRECTION INPUT ;
    USE SIGNAL ;
    PORT
      LAYER M4 ;
        RECT  32.316 39.024 32.4 39.048 ;
    END
  END kc_i[5]
  PIN kc_i[6]
    DIRECTION INPUT ;
    USE SIGNAL ;
    PORT
      LAYER M4 ;
        RECT  32.316 39.168 32.4 39.192 ;
    END
  END kc_i[6]
  PIN kc_i[7]
    DIRECTION INPUT ;
    USE SIGNAL ;
    PORT
      LAYER M4 ;
        RECT  32.316 39.312 32.4 39.336 ;
    END
  END kc_i[7]
  PIN kc_i[8]
    DIRECTION INPUT ;
    USE SIGNAL ;
    PORT
      LAYER M4 ;
        RECT  32.316 39.456 32.4 39.48 ;
    END
  END kc_i[8]
  PIN kc_i[9]
    DIRECTION INPUT ;
    USE SIGNAL ;
    PORT
      LAYER M4 ;
        RECT  32.316 39.6 32.4 39.624 ;
    END
  END kc_i[9]
  PIN q[0]
    DIRECTION INPUT ;
    USE SIGNAL ;
    PORT
      LAYER M4 ;
        RECT  32.316 43.056 32.4 43.08 ;
    END
  END q[0]
  PIN q[100]
    DIRECTION INPUT ;
    USE SIGNAL ;
    PORT
      LAYER M4 ;
        RECT  32.316 52.848 32.4 52.872 ;
    END
  END q[100]
  PIN q[101]
    DIRECTION INPUT ;
    USE SIGNAL ;
    PORT
      LAYER M4 ;
        RECT  32.316 52.992 32.4 53.016 ;
    END
  END q[101]
  PIN q[102]
    DIRECTION INPUT ;
    USE SIGNAL ;
    PORT
      LAYER M4 ;
        RECT  32.316 53.136 32.4 53.16 ;
    END
  END q[102]
  PIN q[103]
    DIRECTION INPUT ;
    USE SIGNAL ;
    PORT
      LAYER M4 ;
        RECT  32.316 53.28 32.4 53.304 ;
    END
  END q[103]
  PIN q[104]
    DIRECTION INPUT ;
    USE SIGNAL ;
    PORT
      LAYER M4 ;
        RECT  32.316 53.424 32.4 53.448 ;
    END
  END q[104]
  PIN q[105]
    DIRECTION INPUT ;
    USE SIGNAL ;
    PORT
      LAYER M4 ;
        RECT  32.316 53.568 32.4 53.592 ;
    END
  END q[105]
  PIN q[106]
    DIRECTION INPUT ;
    USE SIGNAL ;
    PORT
      LAYER M4 ;
        RECT  32.316 53.712 32.4 53.736 ;
    END
  END q[106]
  PIN q[107]
    DIRECTION INPUT ;
    USE SIGNAL ;
    PORT
      LAYER M4 ;
        RECT  32.316 53.856 32.4 53.88 ;
    END
  END q[107]
  PIN q[108]
    DIRECTION INPUT ;
    USE SIGNAL ;
    PORT
      LAYER M4 ;
        RECT  32.316 54 32.4 54.024 ;
    END
  END q[108]
  PIN q[109]
    DIRECTION INPUT ;
    USE SIGNAL ;
    PORT
      LAYER M4 ;
        RECT  32.316 54.144 32.4 54.168 ;
    END
  END q[109]
  PIN q[10]
    DIRECTION INPUT ;
    USE SIGNAL ;
    PORT
      LAYER M4 ;
        RECT  32.316 44.496 32.4 44.52 ;
    END
  END q[10]
  PIN q[110]
    DIRECTION INPUT ;
    USE SIGNAL ;
    PORT
      LAYER M4 ;
        RECT  32.316 54.288 32.4 54.312 ;
    END
  END q[110]
  PIN q[111]
    DIRECTION INPUT ;
    USE SIGNAL ;
    PORT
      LAYER M4 ;
        RECT  32.316 54.432 32.4 54.456 ;
    END
  END q[111]
  PIN q[112]
    DIRECTION INPUT ;
    USE SIGNAL ;
    PORT
      LAYER M4 ;
        RECT  32.316 54.576 32.4 54.6 ;
    END
  END q[112]
  PIN q[113]
    DIRECTION INPUT ;
    USE SIGNAL ;
    PORT
      LAYER M4 ;
        RECT  32.316 54.72 32.4 54.744 ;
    END
  END q[113]
  PIN q[114]
    DIRECTION INPUT ;
    USE SIGNAL ;
    PORT
      LAYER M4 ;
        RECT  32.316 54.864 32.4 54.888 ;
    END
  END q[114]
  PIN q[115]
    DIRECTION INPUT ;
    USE SIGNAL ;
    PORT
      LAYER M4 ;
        RECT  32.316 55.008 32.4 55.032 ;
    END
  END q[115]
  PIN q[116]
    DIRECTION INPUT ;
    USE SIGNAL ;
    PORT
      LAYER M4 ;
        RECT  32.316 55.152 32.4 55.176 ;
    END
  END q[116]
  PIN q[117]
    DIRECTION INPUT ;
    USE SIGNAL ;
    PORT
      LAYER M4 ;
        RECT  32.316 55.296 32.4 55.32 ;
    END
  END q[117]
  PIN q[118]
    DIRECTION INPUT ;
    USE SIGNAL ;
    PORT
      LAYER M4 ;
        RECT  32.316 55.44 32.4 55.464 ;
    END
  END q[118]
  PIN q[119]
    DIRECTION INPUT ;
    USE SIGNAL ;
    PORT
      LAYER M4 ;
        RECT  32.316 55.584 32.4 55.608 ;
    END
  END q[119]
  PIN q[11]
    DIRECTION INPUT ;
    USE SIGNAL ;
    PORT
      LAYER M4 ;
        RECT  32.316 44.64 32.4 44.664 ;
    END
  END q[11]
  PIN q[120]
    DIRECTION INPUT ;
    USE SIGNAL ;
    PORT
      LAYER M4 ;
        RECT  32.316 55.728 32.4 55.752 ;
    END
  END q[120]
  PIN q[121]
    DIRECTION INPUT ;
    USE SIGNAL ;
    PORT
      LAYER M4 ;
        RECT  32.316 55.872 32.4 55.896 ;
    END
  END q[121]
  PIN q[122]
    DIRECTION INPUT ;
    USE SIGNAL ;
    PORT
      LAYER M4 ;
        RECT  32.316 56.016 32.4 56.04 ;
    END
  END q[122]
  PIN q[123]
    DIRECTION INPUT ;
    USE SIGNAL ;
    PORT
      LAYER M4 ;
        RECT  32.316 56.16 32.4 56.184 ;
    END
  END q[123]
  PIN q[124]
    DIRECTION INPUT ;
    USE SIGNAL ;
    PORT
      LAYER M4 ;
        RECT  32.316 56.304 32.4 56.328 ;
    END
  END q[124]
  PIN q[125]
    DIRECTION INPUT ;
    USE SIGNAL ;
    PORT
      LAYER M4 ;
        RECT  32.316 56.448 32.4 56.472 ;
    END
  END q[125]
  PIN q[126]
    DIRECTION INPUT ;
    USE SIGNAL ;
    PORT
      LAYER M4 ;
        RECT  32.316 56.592 32.4 56.616 ;
    END
  END q[126]
  PIN q[127]
    DIRECTION INPUT ;
    USE SIGNAL ;
    PORT
      LAYER M4 ;
        RECT  32.316 56.736 32.4 56.76 ;
    END
  END q[127]
  PIN q[128]
    DIRECTION INPUT ;
    USE SIGNAL ;
    PORT
      LAYER M4 ;
        RECT  32.316 56.88 32.4 56.904 ;
    END
  END q[128]
  PIN q[129]
    DIRECTION INPUT ;
    USE SIGNAL ;
    PORT
      LAYER M4 ;
        RECT  32.316 57.024 32.4 57.048 ;
    END
  END q[129]
  PIN q[12]
    DIRECTION INPUT ;
    USE SIGNAL ;
    PORT
      LAYER M4 ;
        RECT  32.316 44.784 32.4 44.808 ;
    END
  END q[12]
  PIN q[130]
    DIRECTION INPUT ;
    USE SIGNAL ;
    PORT
      LAYER M4 ;
        RECT  32.316 67.536 32.4 67.56 ;
    END
  END q[130]
  PIN q[131]
    DIRECTION INPUT ;
    USE SIGNAL ;
    PORT
      LAYER M4 ;
        RECT  32.316 67.68 32.4 67.704 ;
    END
  END q[131]
  PIN q[132]
    DIRECTION INPUT ;
    USE SIGNAL ;
    PORT
      LAYER M4 ;
        RECT  32.316 67.824 32.4 67.848 ;
    END
  END q[132]
  PIN q[133]
    DIRECTION INPUT ;
    USE SIGNAL ;
    PORT
      LAYER M4 ;
        RECT  32.316 67.968 32.4 67.992 ;
    END
  END q[133]
  PIN q[134]
    DIRECTION INPUT ;
    USE SIGNAL ;
    PORT
      LAYER M4 ;
        RECT  32.316 68.112 32.4 68.136 ;
    END
  END q[134]
  PIN q[135]
    DIRECTION INPUT ;
    USE SIGNAL ;
    PORT
      LAYER M4 ;
        RECT  32.316 68.256 32.4 68.28 ;
    END
  END q[135]
  PIN q[136]
    DIRECTION INPUT ;
    USE SIGNAL ;
    PORT
      LAYER M4 ;
        RECT  32.316 68.4 32.4 68.424 ;
    END
  END q[136]
  PIN q[137]
    DIRECTION INPUT ;
    USE SIGNAL ;
    PORT
      LAYER M4 ;
        RECT  32.316 68.544 32.4 68.568 ;
    END
  END q[137]
  PIN q[138]
    DIRECTION INPUT ;
    USE SIGNAL ;
    PORT
      LAYER M4 ;
        RECT  32.316 68.688 32.4 68.712 ;
    END
  END q[138]
  PIN q[139]
    DIRECTION INPUT ;
    USE SIGNAL ;
    PORT
      LAYER M4 ;
        RECT  32.316 68.832 32.4 68.856 ;
    END
  END q[139]
  PIN q[13]
    DIRECTION INPUT ;
    USE SIGNAL ;
    PORT
      LAYER M4 ;
        RECT  32.316 44.928 32.4 44.952 ;
    END
  END q[13]
  PIN q[140]
    DIRECTION INPUT ;
    USE SIGNAL ;
    PORT
      LAYER M4 ;
        RECT  32.316 68.976 32.4 69 ;
    END
  END q[140]
  PIN q[141]
    DIRECTION INPUT ;
    USE SIGNAL ;
    PORT
      LAYER M4 ;
        RECT  32.316 69.12 32.4 69.144 ;
    END
  END q[141]
  PIN q[142]
    DIRECTION INPUT ;
    USE SIGNAL ;
    PORT
      LAYER M4 ;
        RECT  32.316 69.264 32.4 69.288 ;
    END
  END q[142]
  PIN q[143]
    DIRECTION INPUT ;
    USE SIGNAL ;
    PORT
      LAYER M4 ;
        RECT  32.316 69.408 32.4 69.432 ;
    END
  END q[143]
  PIN q[144]
    DIRECTION INPUT ;
    USE SIGNAL ;
    PORT
      LAYER M4 ;
        RECT  32.316 69.552 32.4 69.576 ;
    END
  END q[144]
  PIN q[145]
    DIRECTION INPUT ;
    USE SIGNAL ;
    PORT
      LAYER M4 ;
        RECT  32.316 69.696 32.4 69.72 ;
    END
  END q[145]
  PIN q[146]
    DIRECTION INPUT ;
    USE SIGNAL ;
    PORT
      LAYER M4 ;
        RECT  32.316 69.84 32.4 69.864 ;
    END
  END q[146]
  PIN q[147]
    DIRECTION INPUT ;
    USE SIGNAL ;
    PORT
      LAYER M4 ;
        RECT  32.316 69.984 32.4 70.008 ;
    END
  END q[147]
  PIN q[148]
    DIRECTION INPUT ;
    USE SIGNAL ;
    PORT
      LAYER M4 ;
        RECT  32.316 70.128 32.4 70.152 ;
    END
  END q[148]
  PIN q[149]
    DIRECTION INPUT ;
    USE SIGNAL ;
    PORT
      LAYER M4 ;
        RECT  32.316 70.272 32.4 70.296 ;
    END
  END q[149]
  PIN q[14]
    DIRECTION INPUT ;
    USE SIGNAL ;
    PORT
      LAYER M4 ;
        RECT  32.316 45.072 32.4 45.096 ;
    END
  END q[14]
  PIN q[150]
    DIRECTION INPUT ;
    USE SIGNAL ;
    PORT
      LAYER M4 ;
        RECT  32.316 70.416 32.4 70.44 ;
    END
  END q[150]
  PIN q[151]
    DIRECTION INPUT ;
    USE SIGNAL ;
    PORT
      LAYER M4 ;
        RECT  32.316 70.56 32.4 70.584 ;
    END
  END q[151]
  PIN q[152]
    DIRECTION INPUT ;
    USE SIGNAL ;
    PORT
      LAYER M4 ;
        RECT  32.316 70.704 32.4 70.728 ;
    END
  END q[152]
  PIN q[153]
    DIRECTION INPUT ;
    USE SIGNAL ;
    PORT
      LAYER M4 ;
        RECT  32.316 70.848 32.4 70.872 ;
    END
  END q[153]
  PIN q[154]
    DIRECTION INPUT ;
    USE SIGNAL ;
    PORT
      LAYER M4 ;
        RECT  32.316 70.992 32.4 71.016 ;
    END
  END q[154]
  PIN q[155]
    DIRECTION INPUT ;
    USE SIGNAL ;
    PORT
      LAYER M4 ;
        RECT  32.316 71.136 32.4 71.16 ;
    END
  END q[155]
  PIN q[156]
    DIRECTION INPUT ;
    USE SIGNAL ;
    PORT
      LAYER M4 ;
        RECT  32.316 71.28 32.4 71.304 ;
    END
  END q[156]
  PIN q[157]
    DIRECTION INPUT ;
    USE SIGNAL ;
    PORT
      LAYER M4 ;
        RECT  32.316 71.424 32.4 71.448 ;
    END
  END q[157]
  PIN q[158]
    DIRECTION INPUT ;
    USE SIGNAL ;
    PORT
      LAYER M4 ;
        RECT  32.316 71.568 32.4 71.592 ;
    END
  END q[158]
  PIN q[159]
    DIRECTION INPUT ;
    USE SIGNAL ;
    PORT
      LAYER M4 ;
        RECT  32.316 71.712 32.4 71.736 ;
    END
  END q[159]
  PIN q[15]
    DIRECTION INPUT ;
    USE SIGNAL ;
    PORT
      LAYER M4 ;
        RECT  32.316 45.216 32.4 45.24 ;
    END
  END q[15]
  PIN q[160]
    DIRECTION INPUT ;
    USE SIGNAL ;
    PORT
      LAYER M4 ;
        RECT  32.316 71.856 32.4 71.88 ;
    END
  END q[160]
  PIN q[161]
    DIRECTION INPUT ;
    USE SIGNAL ;
    PORT
      LAYER M4 ;
        RECT  32.316 72 32.4 72.024 ;
    END
  END q[161]
  PIN q[162]
    DIRECTION INPUT ;
    USE SIGNAL ;
    PORT
      LAYER M4 ;
        RECT  32.316 76.752 32.4 76.776 ;
    END
  END q[162]
  PIN q[163]
    DIRECTION INPUT ;
    USE SIGNAL ;
    PORT
      LAYER M4 ;
        RECT  32.316 76.896 32.4 76.92 ;
    END
  END q[163]
  PIN q[164]
    DIRECTION INPUT ;
    USE SIGNAL ;
    PORT
      LAYER M4 ;
        RECT  32.316 77.04 32.4 77.064 ;
    END
  END q[164]
  PIN q[165]
    DIRECTION INPUT ;
    USE SIGNAL ;
    PORT
      LAYER M4 ;
        RECT  32.316 77.184 32.4 77.208 ;
    END
  END q[165]
  PIN q[166]
    DIRECTION INPUT ;
    USE SIGNAL ;
    PORT
      LAYER M4 ;
        RECT  32.316 77.328 32.4 77.352 ;
    END
  END q[166]
  PIN q[167]
    DIRECTION INPUT ;
    USE SIGNAL ;
    PORT
      LAYER M4 ;
        RECT  32.316 77.472 32.4 77.496 ;
    END
  END q[167]
  PIN q[168]
    DIRECTION INPUT ;
    USE SIGNAL ;
    PORT
      LAYER M4 ;
        RECT  32.316 77.616 32.4 77.64 ;
    END
  END q[168]
  PIN q[169]
    DIRECTION INPUT ;
    USE SIGNAL ;
    PORT
      LAYER M4 ;
        RECT  32.316 77.76 32.4 77.784 ;
    END
  END q[169]
  PIN q[16]
    DIRECTION INPUT ;
    USE SIGNAL ;
    PORT
      LAYER M4 ;
        RECT  32.316 45.36 32.4 45.384 ;
    END
  END q[16]
  PIN q[170]
    DIRECTION INPUT ;
    USE SIGNAL ;
    PORT
      LAYER M4 ;
        RECT  32.316 77.904 32.4 77.928 ;
    END
  END q[170]
  PIN q[171]
    DIRECTION INPUT ;
    USE SIGNAL ;
    PORT
      LAYER M4 ;
        RECT  32.316 78.048 32.4 78.072 ;
    END
  END q[171]
  PIN q[172]
    DIRECTION INPUT ;
    USE SIGNAL ;
    PORT
      LAYER M4 ;
        RECT  32.316 78.192 32.4 78.216 ;
    END
  END q[172]
  PIN q[173]
    DIRECTION INPUT ;
    USE SIGNAL ;
    PORT
      LAYER M4 ;
        RECT  32.316 78.336 32.4 78.36 ;
    END
  END q[173]
  PIN q[174]
    DIRECTION INPUT ;
    USE SIGNAL ;
    PORT
      LAYER M4 ;
        RECT  32.316 78.48 32.4 78.504 ;
    END
  END q[174]
  PIN q[175]
    DIRECTION INPUT ;
    USE SIGNAL ;
    PORT
      LAYER M4 ;
        RECT  32.316 78.624 32.4 78.648 ;
    END
  END q[175]
  PIN q[176]
    DIRECTION INPUT ;
    USE SIGNAL ;
    PORT
      LAYER M4 ;
        RECT  32.316 78.768 32.4 78.792 ;
    END
  END q[176]
  PIN q[177]
    DIRECTION INPUT ;
    USE SIGNAL ;
    PORT
      LAYER M4 ;
        RECT  32.316 78.912 32.4 78.936 ;
    END
  END q[177]
  PIN q[178]
    DIRECTION INPUT ;
    USE SIGNAL ;
    PORT
      LAYER M4 ;
        RECT  32.316 79.056 32.4 79.08 ;
    END
  END q[178]
  PIN q[179]
    DIRECTION INPUT ;
    USE SIGNAL ;
    PORT
      LAYER M4 ;
        RECT  32.316 79.2 32.4 79.224 ;
    END
  END q[179]
  PIN q[17]
    DIRECTION INPUT ;
    USE SIGNAL ;
    PORT
      LAYER M4 ;
        RECT  32.316 45.504 32.4 45.528 ;
    END
  END q[17]
  PIN q[180]
    DIRECTION INPUT ;
    USE SIGNAL ;
    PORT
      LAYER M4 ;
        RECT  32.316 79.344 32.4 79.368 ;
    END
  END q[180]
  PIN q[181]
    DIRECTION INPUT ;
    USE SIGNAL ;
    PORT
      LAYER M4 ;
        RECT  32.316 79.488 32.4 79.512 ;
    END
  END q[181]
  PIN q[182]
    DIRECTION INPUT ;
    USE SIGNAL ;
    PORT
      LAYER M4 ;
        RECT  32.316 79.632 32.4 79.656 ;
    END
  END q[182]
  PIN q[183]
    DIRECTION INPUT ;
    USE SIGNAL ;
    PORT
      LAYER M4 ;
        RECT  32.316 79.776 32.4 79.8 ;
    END
  END q[183]
  PIN q[184]
    DIRECTION INPUT ;
    USE SIGNAL ;
    PORT
      LAYER M4 ;
        RECT  32.316 79.92 32.4 79.944 ;
    END
  END q[184]
  PIN q[185]
    DIRECTION INPUT ;
    USE SIGNAL ;
    PORT
      LAYER M4 ;
        RECT  32.316 80.064 32.4 80.088 ;
    END
  END q[185]
  PIN q[186]
    DIRECTION INPUT ;
    USE SIGNAL ;
    PORT
      LAYER M4 ;
        RECT  32.316 80.208 32.4 80.232 ;
    END
  END q[186]
  PIN q[187]
    DIRECTION INPUT ;
    USE SIGNAL ;
    PORT
      LAYER M4 ;
        RECT  32.316 80.352 32.4 80.376 ;
    END
  END q[187]
  PIN q[188]
    DIRECTION INPUT ;
    USE SIGNAL ;
    PORT
      LAYER M4 ;
        RECT  32.316 80.496 32.4 80.52 ;
    END
  END q[188]
  PIN q[189]
    DIRECTION INPUT ;
    USE SIGNAL ;
    PORT
      LAYER M4 ;
        RECT  32.316 80.64 32.4 80.664 ;
    END
  END q[189]
  PIN q[18]
    DIRECTION INPUT ;
    USE SIGNAL ;
    PORT
      LAYER M4 ;
        RECT  32.316 45.648 32.4 45.672 ;
    END
  END q[18]
  PIN q[190]
    DIRECTION INPUT ;
    USE SIGNAL ;
    PORT
      LAYER M4 ;
        RECT  32.316 80.784 32.4 80.808 ;
    END
  END q[190]
  PIN q[191]
    DIRECTION INPUT ;
    USE SIGNAL ;
    PORT
      LAYER M4 ;
        RECT  32.316 80.928 32.4 80.952 ;
    END
  END q[191]
  PIN q[192]
    DIRECTION INPUT ;
    USE SIGNAL ;
    PORT
      LAYER M4 ;
        RECT  32.316 81.072 32.4 81.096 ;
    END
  END q[192]
  PIN q[193]
    DIRECTION INPUT ;
    USE SIGNAL ;
    PORT
      LAYER M4 ;
        RECT  32.316 81.216 32.4 81.24 ;
    END
  END q[193]
  PIN q[194]
    DIRECTION INPUT ;
    USE SIGNAL ;
    PORT
      LAYER M4 ;
        RECT  32.316 58.32 32.4 58.344 ;
    END
  END q[194]
  PIN q[195]
    DIRECTION INPUT ;
    USE SIGNAL ;
    PORT
      LAYER M4 ;
        RECT  32.316 58.464 32.4 58.488 ;
    END
  END q[195]
  PIN q[196]
    DIRECTION INPUT ;
    USE SIGNAL ;
    PORT
      LAYER M4 ;
        RECT  32.316 58.608 32.4 58.632 ;
    END
  END q[196]
  PIN q[197]
    DIRECTION INPUT ;
    USE SIGNAL ;
    PORT
      LAYER M4 ;
        RECT  32.316 58.752 32.4 58.776 ;
    END
  END q[197]
  PIN q[198]
    DIRECTION INPUT ;
    USE SIGNAL ;
    PORT
      LAYER M4 ;
        RECT  32.316 58.896 32.4 58.92 ;
    END
  END q[198]
  PIN q[199]
    DIRECTION INPUT ;
    USE SIGNAL ;
    PORT
      LAYER M4 ;
        RECT  32.316 59.04 32.4 59.064 ;
    END
  END q[199]
  PIN q[19]
    DIRECTION INPUT ;
    USE SIGNAL ;
    PORT
      LAYER M4 ;
        RECT  32.316 45.792 32.4 45.816 ;
    END
  END q[19]
  PIN q[1]
    DIRECTION INPUT ;
    USE SIGNAL ;
    PORT
      LAYER M4 ;
        RECT  32.316 43.2 32.4 43.224 ;
    END
  END q[1]
  PIN q[200]
    DIRECTION INPUT ;
    USE SIGNAL ;
    PORT
      LAYER M4 ;
        RECT  32.316 59.184 32.4 59.208 ;
    END
  END q[200]
  PIN q[201]
    DIRECTION INPUT ;
    USE SIGNAL ;
    PORT
      LAYER M4 ;
        RECT  32.316 59.328 32.4 59.352 ;
    END
  END q[201]
  PIN q[202]
    DIRECTION INPUT ;
    USE SIGNAL ;
    PORT
      LAYER M4 ;
        RECT  32.316 59.472 32.4 59.496 ;
    END
  END q[202]
  PIN q[203]
    DIRECTION INPUT ;
    USE SIGNAL ;
    PORT
      LAYER M4 ;
        RECT  32.316 59.616 32.4 59.64 ;
    END
  END q[203]
  PIN q[204]
    DIRECTION INPUT ;
    USE SIGNAL ;
    PORT
      LAYER M4 ;
        RECT  32.316 59.76 32.4 59.784 ;
    END
  END q[204]
  PIN q[205]
    DIRECTION INPUT ;
    USE SIGNAL ;
    PORT
      LAYER M4 ;
        RECT  32.316 59.904 32.4 59.928 ;
    END
  END q[205]
  PIN q[206]
    DIRECTION INPUT ;
    USE SIGNAL ;
    PORT
      LAYER M4 ;
        RECT  32.316 60.048 32.4 60.072 ;
    END
  END q[206]
  PIN q[207]
    DIRECTION INPUT ;
    USE SIGNAL ;
    PORT
      LAYER M4 ;
        RECT  32.316 60.192 32.4 60.216 ;
    END
  END q[207]
  PIN q[208]
    DIRECTION INPUT ;
    USE SIGNAL ;
    PORT
      LAYER M4 ;
        RECT  32.316 60.336 32.4 60.36 ;
    END
  END q[208]
  PIN q[209]
    DIRECTION INPUT ;
    USE SIGNAL ;
    PORT
      LAYER M4 ;
        RECT  32.316 60.48 32.4 60.504 ;
    END
  END q[209]
  PIN q[20]
    DIRECTION INPUT ;
    USE SIGNAL ;
    PORT
      LAYER M4 ;
        RECT  32.316 45.936 32.4 45.96 ;
    END
  END q[20]
  PIN q[210]
    DIRECTION INPUT ;
    USE SIGNAL ;
    PORT
      LAYER M4 ;
        RECT  32.316 60.624 32.4 60.648 ;
    END
  END q[210]
  PIN q[211]
    DIRECTION INPUT ;
    USE SIGNAL ;
    PORT
      LAYER M4 ;
        RECT  32.316 60.768 32.4 60.792 ;
    END
  END q[211]
  PIN q[212]
    DIRECTION INPUT ;
    USE SIGNAL ;
    PORT
      LAYER M4 ;
        RECT  32.316 60.912 32.4 60.936 ;
    END
  END q[212]
  PIN q[213]
    DIRECTION INPUT ;
    USE SIGNAL ;
    PORT
      LAYER M4 ;
        RECT  32.316 61.056 32.4 61.08 ;
    END
  END q[213]
  PIN q[214]
    DIRECTION INPUT ;
    USE SIGNAL ;
    PORT
      LAYER M4 ;
        RECT  32.316 61.2 32.4 61.224 ;
    END
  END q[214]
  PIN q[215]
    DIRECTION INPUT ;
    USE SIGNAL ;
    PORT
      LAYER M4 ;
        RECT  32.316 61.344 32.4 61.368 ;
    END
  END q[215]
  PIN q[216]
    DIRECTION INPUT ;
    USE SIGNAL ;
    PORT
      LAYER M4 ;
        RECT  32.316 61.488 32.4 61.512 ;
    END
  END q[216]
  PIN q[217]
    DIRECTION INPUT ;
    USE SIGNAL ;
    PORT
      LAYER M4 ;
        RECT  32.316 61.632 32.4 61.656 ;
    END
  END q[217]
  PIN q[218]
    DIRECTION INPUT ;
    USE SIGNAL ;
    PORT
      LAYER M4 ;
        RECT  32.316 61.776 32.4 61.8 ;
    END
  END q[218]
  PIN q[219]
    DIRECTION INPUT ;
    USE SIGNAL ;
    PORT
      LAYER M4 ;
        RECT  32.316 61.92 32.4 61.944 ;
    END
  END q[219]
  PIN q[21]
    DIRECTION INPUT ;
    USE SIGNAL ;
    PORT
      LAYER M4 ;
        RECT  32.316 46.08 32.4 46.104 ;
    END
  END q[21]
  PIN q[220]
    DIRECTION INPUT ;
    USE SIGNAL ;
    PORT
      LAYER M4 ;
        RECT  32.316 62.064 32.4 62.088 ;
    END
  END q[220]
  PIN q[221]
    DIRECTION INPUT ;
    USE SIGNAL ;
    PORT
      LAYER M4 ;
        RECT  32.316 62.208 32.4 62.232 ;
    END
  END q[221]
  PIN q[222]
    DIRECTION INPUT ;
    USE SIGNAL ;
    PORT
      LAYER M4 ;
        RECT  32.316 62.352 32.4 62.376 ;
    END
  END q[222]
  PIN q[223]
    DIRECTION INPUT ;
    USE SIGNAL ;
    PORT
      LAYER M4 ;
        RECT  32.316 62.496 32.4 62.52 ;
    END
  END q[223]
  PIN q[224]
    DIRECTION INPUT ;
    USE SIGNAL ;
    PORT
      LAYER M4 ;
        RECT  32.316 62.64 32.4 62.664 ;
    END
  END q[224]
  PIN q[225]
    DIRECTION INPUT ;
    USE SIGNAL ;
    PORT
      LAYER M4 ;
        RECT  32.316 62.784 32.4 62.808 ;
    END
  END q[225]
  PIN q[226]
    DIRECTION INPUT ;
    USE SIGNAL ;
    PORT
      LAYER M4 ;
        RECT  32.316 81.36 32.4 81.384 ;
    END
  END q[226]
  PIN q[227]
    DIRECTION INPUT ;
    USE SIGNAL ;
    PORT
      LAYER M4 ;
        RECT  32.316 81.504 32.4 81.528 ;
    END
  END q[227]
  PIN q[228]
    DIRECTION INPUT ;
    USE SIGNAL ;
    PORT
      LAYER M4 ;
        RECT  32.316 81.648 32.4 81.672 ;
    END
  END q[228]
  PIN q[229]
    DIRECTION INPUT ;
    USE SIGNAL ;
    PORT
      LAYER M4 ;
        RECT  32.316 81.792 32.4 81.816 ;
    END
  END q[229]
  PIN q[22]
    DIRECTION INPUT ;
    USE SIGNAL ;
    PORT
      LAYER M4 ;
        RECT  32.316 46.224 32.4 46.248 ;
    END
  END q[22]
  PIN q[230]
    DIRECTION INPUT ;
    USE SIGNAL ;
    PORT
      LAYER M4 ;
        RECT  32.316 81.936 32.4 81.96 ;
    END
  END q[230]
  PIN q[231]
    DIRECTION INPUT ;
    USE SIGNAL ;
    PORT
      LAYER M4 ;
        RECT  32.316 82.08 32.4 82.104 ;
    END
  END q[231]
  PIN q[232]
    DIRECTION INPUT ;
    USE SIGNAL ;
    PORT
      LAYER M4 ;
        RECT  32.316 82.224 32.4 82.248 ;
    END
  END q[232]
  PIN q[233]
    DIRECTION INPUT ;
    USE SIGNAL ;
    PORT
      LAYER M4 ;
        RECT  32.316 82.368 32.4 82.392 ;
    END
  END q[233]
  PIN q[234]
    DIRECTION INPUT ;
    USE SIGNAL ;
    PORT
      LAYER M4 ;
        RECT  32.316 82.512 32.4 82.536 ;
    END
  END q[234]
  PIN q[235]
    DIRECTION INPUT ;
    USE SIGNAL ;
    PORT
      LAYER M4 ;
        RECT  32.316 82.656 32.4 82.68 ;
    END
  END q[235]
  PIN q[236]
    DIRECTION INPUT ;
    USE SIGNAL ;
    PORT
      LAYER M4 ;
        RECT  32.316 82.8 32.4 82.824 ;
    END
  END q[236]
  PIN q[237]
    DIRECTION INPUT ;
    USE SIGNAL ;
    PORT
      LAYER M4 ;
        RECT  32.316 82.944 32.4 82.968 ;
    END
  END q[237]
  PIN q[238]
    DIRECTION INPUT ;
    USE SIGNAL ;
    PORT
      LAYER M4 ;
        RECT  32.316 83.088 32.4 83.112 ;
    END
  END q[238]
  PIN q[239]
    DIRECTION INPUT ;
    USE SIGNAL ;
    PORT
      LAYER M4 ;
        RECT  32.316 83.232 32.4 83.256 ;
    END
  END q[239]
  PIN q[23]
    DIRECTION INPUT ;
    USE SIGNAL ;
    PORT
      LAYER M4 ;
        RECT  32.316 46.368 32.4 46.392 ;
    END
  END q[23]
  PIN q[240]
    DIRECTION INPUT ;
    USE SIGNAL ;
    PORT
      LAYER M4 ;
        RECT  32.316 83.376 32.4 83.4 ;
    END
  END q[240]
  PIN q[241]
    DIRECTION INPUT ;
    USE SIGNAL ;
    PORT
      LAYER M4 ;
        RECT  32.316 83.52 32.4 83.544 ;
    END
  END q[241]
  PIN q[242]
    DIRECTION INPUT ;
    USE SIGNAL ;
    PORT
      LAYER M4 ;
        RECT  32.316 83.664 32.4 83.688 ;
    END
  END q[242]
  PIN q[243]
    DIRECTION INPUT ;
    USE SIGNAL ;
    PORT
      LAYER M4 ;
        RECT  32.316 83.808 32.4 83.832 ;
    END
  END q[243]
  PIN q[244]
    DIRECTION INPUT ;
    USE SIGNAL ;
    PORT
      LAYER M4 ;
        RECT  32.316 83.952 32.4 83.976 ;
    END
  END q[244]
  PIN q[245]
    DIRECTION INPUT ;
    USE SIGNAL ;
    PORT
      LAYER M4 ;
        RECT  32.316 84.096 32.4 84.12 ;
    END
  END q[245]
  PIN q[246]
    DIRECTION INPUT ;
    USE SIGNAL ;
    PORT
      LAYER M4 ;
        RECT  32.316 84.24 32.4 84.264 ;
    END
  END q[246]
  PIN q[247]
    DIRECTION INPUT ;
    USE SIGNAL ;
    PORT
      LAYER M4 ;
        RECT  32.316 84.384 32.4 84.408 ;
    END
  END q[247]
  PIN q[248]
    DIRECTION INPUT ;
    USE SIGNAL ;
    PORT
      LAYER M4 ;
        RECT  32.316 84.528 32.4 84.552 ;
    END
  END q[248]
  PIN q[249]
    DIRECTION INPUT ;
    USE SIGNAL ;
    PORT
      LAYER M4 ;
        RECT  32.316 84.672 32.4 84.696 ;
    END
  END q[249]
  PIN q[24]
    DIRECTION INPUT ;
    USE SIGNAL ;
    PORT
      LAYER M4 ;
        RECT  32.316 46.512 32.4 46.536 ;
    END
  END q[24]
  PIN q[250]
    DIRECTION INPUT ;
    USE SIGNAL ;
    PORT
      LAYER M4 ;
        RECT  32.316 84.816 32.4 84.84 ;
    END
  END q[250]
  PIN q[251]
    DIRECTION INPUT ;
    USE SIGNAL ;
    PORT
      LAYER M4 ;
        RECT  32.316 84.96 32.4 84.984 ;
    END
  END q[251]
  PIN q[252]
    DIRECTION INPUT ;
    USE SIGNAL ;
    PORT
      LAYER M4 ;
        RECT  32.316 85.104 32.4 85.128 ;
    END
  END q[252]
  PIN q[253]
    DIRECTION INPUT ;
    USE SIGNAL ;
    PORT
      LAYER M4 ;
        RECT  32.316 85.248 32.4 85.272 ;
    END
  END q[253]
  PIN q[254]
    DIRECTION INPUT ;
    USE SIGNAL ;
    PORT
      LAYER M4 ;
        RECT  32.316 85.392 32.4 85.416 ;
    END
  END q[254]
  PIN q[255]
    DIRECTION INPUT ;
    USE SIGNAL ;
    PORT
      LAYER M4 ;
        RECT  32.316 85.536 32.4 85.56 ;
    END
  END q[255]
  PIN q[256]
    DIRECTION INPUT ;
    USE SIGNAL ;
    PORT
      LAYER M4 ;
        RECT  32.316 85.68 32.4 85.704 ;
    END
  END q[256]
  PIN q[257]
    DIRECTION INPUT ;
    USE SIGNAL ;
    PORT
      LAYER M4 ;
        RECT  32.316 85.824 32.4 85.848 ;
    END
  END q[257]
  PIN q[258]
    DIRECTION INPUT ;
    USE SIGNAL ;
    PORT
      LAYER M4 ;
        RECT  32.316 72.144 32.4 72.168 ;
    END
  END q[258]
  PIN q[259]
    DIRECTION INPUT ;
    USE SIGNAL ;
    PORT
      LAYER M4 ;
        RECT  32.316 72.288 32.4 72.312 ;
    END
  END q[259]
  PIN q[25]
    DIRECTION INPUT ;
    USE SIGNAL ;
    PORT
      LAYER M4 ;
        RECT  32.316 46.656 32.4 46.68 ;
    END
  END q[25]
  PIN q[260]
    DIRECTION INPUT ;
    USE SIGNAL ;
    PORT
      LAYER M4 ;
        RECT  32.316 72.432 32.4 72.456 ;
    END
  END q[260]
  PIN q[261]
    DIRECTION INPUT ;
    USE SIGNAL ;
    PORT
      LAYER M4 ;
        RECT  32.316 72.576 32.4 72.6 ;
    END
  END q[261]
  PIN q[262]
    DIRECTION INPUT ;
    USE SIGNAL ;
    PORT
      LAYER M4 ;
        RECT  32.316 72.72 32.4 72.744 ;
    END
  END q[262]
  PIN q[263]
    DIRECTION INPUT ;
    USE SIGNAL ;
    PORT
      LAYER M4 ;
        RECT  32.316 72.864 32.4 72.888 ;
    END
  END q[263]
  PIN q[264]
    DIRECTION INPUT ;
    USE SIGNAL ;
    PORT
      LAYER M4 ;
        RECT  32.316 73.008 32.4 73.032 ;
    END
  END q[264]
  PIN q[265]
    DIRECTION INPUT ;
    USE SIGNAL ;
    PORT
      LAYER M4 ;
        RECT  32.316 73.152 32.4 73.176 ;
    END
  END q[265]
  PIN q[266]
    DIRECTION INPUT ;
    USE SIGNAL ;
    PORT
      LAYER M4 ;
        RECT  32.316 73.296 32.4 73.32 ;
    END
  END q[266]
  PIN q[267]
    DIRECTION INPUT ;
    USE SIGNAL ;
    PORT
      LAYER M4 ;
        RECT  32.316 73.44 32.4 73.464 ;
    END
  END q[267]
  PIN q[268]
    DIRECTION INPUT ;
    USE SIGNAL ;
    PORT
      LAYER M4 ;
        RECT  32.316 73.584 32.4 73.608 ;
    END
  END q[268]
  PIN q[269]
    DIRECTION INPUT ;
    USE SIGNAL ;
    PORT
      LAYER M4 ;
        RECT  32.316 73.728 32.4 73.752 ;
    END
  END q[269]
  PIN q[26]
    DIRECTION INPUT ;
    USE SIGNAL ;
    PORT
      LAYER M4 ;
        RECT  32.316 46.8 32.4 46.824 ;
    END
  END q[26]
  PIN q[270]
    DIRECTION INPUT ;
    USE SIGNAL ;
    PORT
      LAYER M4 ;
        RECT  32.316 73.872 32.4 73.896 ;
    END
  END q[270]
  PIN q[271]
    DIRECTION INPUT ;
    USE SIGNAL ;
    PORT
      LAYER M4 ;
        RECT  32.316 74.016 32.4 74.04 ;
    END
  END q[271]
  PIN q[272]
    DIRECTION INPUT ;
    USE SIGNAL ;
    PORT
      LAYER M4 ;
        RECT  32.316 74.16 32.4 74.184 ;
    END
  END q[272]
  PIN q[273]
    DIRECTION INPUT ;
    USE SIGNAL ;
    PORT
      LAYER M4 ;
        RECT  32.316 74.304 32.4 74.328 ;
    END
  END q[273]
  PIN q[274]
    DIRECTION INPUT ;
    USE SIGNAL ;
    PORT
      LAYER M4 ;
        RECT  32.316 74.448 32.4 74.472 ;
    END
  END q[274]
  PIN q[275]
    DIRECTION INPUT ;
    USE SIGNAL ;
    PORT
      LAYER M4 ;
        RECT  32.316 74.592 32.4 74.616 ;
    END
  END q[275]
  PIN q[276]
    DIRECTION INPUT ;
    USE SIGNAL ;
    PORT
      LAYER M4 ;
        RECT  32.316 74.736 32.4 74.76 ;
    END
  END q[276]
  PIN q[277]
    DIRECTION INPUT ;
    USE SIGNAL ;
    PORT
      LAYER M4 ;
        RECT  32.316 74.88 32.4 74.904 ;
    END
  END q[277]
  PIN q[278]
    DIRECTION INPUT ;
    USE SIGNAL ;
    PORT
      LAYER M4 ;
        RECT  32.316 75.024 32.4 75.048 ;
    END
  END q[278]
  PIN q[279]
    DIRECTION INPUT ;
    USE SIGNAL ;
    PORT
      LAYER M4 ;
        RECT  32.316 75.168 32.4 75.192 ;
    END
  END q[279]
  PIN q[27]
    DIRECTION INPUT ;
    USE SIGNAL ;
    PORT
      LAYER M4 ;
        RECT  32.316 46.944 32.4 46.968 ;
    END
  END q[27]
  PIN q[280]
    DIRECTION INPUT ;
    USE SIGNAL ;
    PORT
      LAYER M4 ;
        RECT  32.316 75.312 32.4 75.336 ;
    END
  END q[280]
  PIN q[281]
    DIRECTION INPUT ;
    USE SIGNAL ;
    PORT
      LAYER M4 ;
        RECT  32.316 75.456 32.4 75.48 ;
    END
  END q[281]
  PIN q[282]
    DIRECTION INPUT ;
    USE SIGNAL ;
    PORT
      LAYER M4 ;
        RECT  32.316 75.6 32.4 75.624 ;
    END
  END q[282]
  PIN q[283]
    DIRECTION INPUT ;
    USE SIGNAL ;
    PORT
      LAYER M4 ;
        RECT  32.316 75.744 32.4 75.768 ;
    END
  END q[283]
  PIN q[284]
    DIRECTION INPUT ;
    USE SIGNAL ;
    PORT
      LAYER M4 ;
        RECT  32.316 75.888 32.4 75.912 ;
    END
  END q[284]
  PIN q[285]
    DIRECTION INPUT ;
    USE SIGNAL ;
    PORT
      LAYER M4 ;
        RECT  32.316 76.032 32.4 76.056 ;
    END
  END q[285]
  PIN q[286]
    DIRECTION INPUT ;
    USE SIGNAL ;
    PORT
      LAYER M4 ;
        RECT  32.316 76.176 32.4 76.2 ;
    END
  END q[286]
  PIN q[287]
    DIRECTION INPUT ;
    USE SIGNAL ;
    PORT
      LAYER M4 ;
        RECT  32.316 76.32 32.4 76.344 ;
    END
  END q[287]
  PIN q[288]
    DIRECTION INPUT ;
    USE SIGNAL ;
    PORT
      LAYER M4 ;
        RECT  32.316 76.464 32.4 76.488 ;
    END
  END q[288]
  PIN q[289]
    DIRECTION INPUT ;
    USE SIGNAL ;
    PORT
      LAYER M4 ;
        RECT  32.316 76.608 32.4 76.632 ;
    END
  END q[289]
  PIN q[28]
    DIRECTION INPUT ;
    USE SIGNAL ;
    PORT
      LAYER M4 ;
        RECT  32.316 47.088 32.4 47.112 ;
    END
  END q[28]
  PIN q[290]
    DIRECTION INPUT ;
    USE SIGNAL ;
    PORT
      LAYER M4 ;
        RECT  32.316 62.928 32.4 62.952 ;
    END
  END q[290]
  PIN q[291]
    DIRECTION INPUT ;
    USE SIGNAL ;
    PORT
      LAYER M4 ;
        RECT  32.316 63.072 32.4 63.096 ;
    END
  END q[291]
  PIN q[292]
    DIRECTION INPUT ;
    USE SIGNAL ;
    PORT
      LAYER M4 ;
        RECT  32.316 63.216 32.4 63.24 ;
    END
  END q[292]
  PIN q[293]
    DIRECTION INPUT ;
    USE SIGNAL ;
    PORT
      LAYER M4 ;
        RECT  32.316 63.36 32.4 63.384 ;
    END
  END q[293]
  PIN q[294]
    DIRECTION INPUT ;
    USE SIGNAL ;
    PORT
      LAYER M4 ;
        RECT  32.316 63.504 32.4 63.528 ;
    END
  END q[294]
  PIN q[295]
    DIRECTION INPUT ;
    USE SIGNAL ;
    PORT
      LAYER M4 ;
        RECT  32.316 63.648 32.4 63.672 ;
    END
  END q[295]
  PIN q[296]
    DIRECTION INPUT ;
    USE SIGNAL ;
    PORT
      LAYER M4 ;
        RECT  32.316 63.792 32.4 63.816 ;
    END
  END q[296]
  PIN q[297]
    DIRECTION INPUT ;
    USE SIGNAL ;
    PORT
      LAYER M4 ;
        RECT  32.316 63.936 32.4 63.96 ;
    END
  END q[297]
  PIN q[298]
    DIRECTION INPUT ;
    USE SIGNAL ;
    PORT
      LAYER M4 ;
        RECT  32.316 64.08 32.4 64.104 ;
    END
  END q[298]
  PIN q[299]
    DIRECTION INPUT ;
    USE SIGNAL ;
    PORT
      LAYER M4 ;
        RECT  32.316 64.224 32.4 64.248 ;
    END
  END q[299]
  PIN q[29]
    DIRECTION INPUT ;
    USE SIGNAL ;
    PORT
      LAYER M4 ;
        RECT  32.316 47.232 32.4 47.256 ;
    END
  END q[29]
  PIN q[2]
    DIRECTION INPUT ;
    USE SIGNAL ;
    PORT
      LAYER M4 ;
        RECT  32.316 43.344 32.4 43.368 ;
    END
  END q[2]
  PIN q[300]
    DIRECTION INPUT ;
    USE SIGNAL ;
    PORT
      LAYER M4 ;
        RECT  32.316 64.368 32.4 64.392 ;
    END
  END q[300]
  PIN q[301]
    DIRECTION INPUT ;
    USE SIGNAL ;
    PORT
      LAYER M4 ;
        RECT  32.316 64.512 32.4 64.536 ;
    END
  END q[301]
  PIN q[302]
    DIRECTION INPUT ;
    USE SIGNAL ;
    PORT
      LAYER M4 ;
        RECT  32.316 64.656 32.4 64.68 ;
    END
  END q[302]
  PIN q[303]
    DIRECTION INPUT ;
    USE SIGNAL ;
    PORT
      LAYER M4 ;
        RECT  32.316 64.8 32.4 64.824 ;
    END
  END q[303]
  PIN q[304]
    DIRECTION INPUT ;
    USE SIGNAL ;
    PORT
      LAYER M4 ;
        RECT  32.316 64.944 32.4 64.968 ;
    END
  END q[304]
  PIN q[305]
    DIRECTION INPUT ;
    USE SIGNAL ;
    PORT
      LAYER M4 ;
        RECT  32.316 65.088 32.4 65.112 ;
    END
  END q[305]
  PIN q[306]
    DIRECTION INPUT ;
    USE SIGNAL ;
    PORT
      LAYER M4 ;
        RECT  32.316 65.232 32.4 65.256 ;
    END
  END q[306]
  PIN q[307]
    DIRECTION INPUT ;
    USE SIGNAL ;
    PORT
      LAYER M4 ;
        RECT  32.316 65.376 32.4 65.4 ;
    END
  END q[307]
  PIN q[308]
    DIRECTION INPUT ;
    USE SIGNAL ;
    PORT
      LAYER M4 ;
        RECT  32.316 65.52 32.4 65.544 ;
    END
  END q[308]
  PIN q[309]
    DIRECTION INPUT ;
    USE SIGNAL ;
    PORT
      LAYER M4 ;
        RECT  32.316 65.664 32.4 65.688 ;
    END
  END q[309]
  PIN q[30]
    DIRECTION INPUT ;
    USE SIGNAL ;
    PORT
      LAYER M4 ;
        RECT  32.316 47.376 32.4 47.4 ;
    END
  END q[30]
  PIN q[310]
    DIRECTION INPUT ;
    USE SIGNAL ;
    PORT
      LAYER M4 ;
        RECT  32.316 65.808 32.4 65.832 ;
    END
  END q[310]
  PIN q[311]
    DIRECTION INPUT ;
    USE SIGNAL ;
    PORT
      LAYER M4 ;
        RECT  32.316 65.952 32.4 65.976 ;
    END
  END q[311]
  PIN q[312]
    DIRECTION INPUT ;
    USE SIGNAL ;
    PORT
      LAYER M4 ;
        RECT  32.316 66.096 32.4 66.12 ;
    END
  END q[312]
  PIN q[313]
    DIRECTION INPUT ;
    USE SIGNAL ;
    PORT
      LAYER M4 ;
        RECT  32.316 66.24 32.4 66.264 ;
    END
  END q[313]
  PIN q[314]
    DIRECTION INPUT ;
    USE SIGNAL ;
    PORT
      LAYER M4 ;
        RECT  32.316 66.384 32.4 66.408 ;
    END
  END q[314]
  PIN q[315]
    DIRECTION INPUT ;
    USE SIGNAL ;
    PORT
      LAYER M4 ;
        RECT  32.316 66.528 32.4 66.552 ;
    END
  END q[315]
  PIN q[316]
    DIRECTION INPUT ;
    USE SIGNAL ;
    PORT
      LAYER M4 ;
        RECT  32.316 66.672 32.4 66.696 ;
    END
  END q[316]
  PIN q[317]
    DIRECTION INPUT ;
    USE SIGNAL ;
    PORT
      LAYER M4 ;
        RECT  32.316 66.816 32.4 66.84 ;
    END
  END q[317]
  PIN q[318]
    DIRECTION INPUT ;
    USE SIGNAL ;
    PORT
      LAYER M4 ;
        RECT  32.316 66.96 32.4 66.984 ;
    END
  END q[318]
  PIN q[319]
    DIRECTION INPUT ;
    USE SIGNAL ;
    PORT
      LAYER M4 ;
        RECT  32.316 67.104 32.4 67.128 ;
    END
  END q[319]
  PIN q[31]
    DIRECTION INPUT ;
    USE SIGNAL ;
    PORT
      LAYER M4 ;
        RECT  32.316 47.52 32.4 47.544 ;
    END
  END q[31]
  PIN q[320]
    DIRECTION INPUT ;
    USE SIGNAL ;
    PORT
      LAYER M4 ;
        RECT  32.316 67.248 32.4 67.272 ;
    END
  END q[320]
  PIN q[321]
    DIRECTION INPUT ;
    USE SIGNAL ;
    PORT
      LAYER M4 ;
        RECT  32.316 67.392 32.4 67.416 ;
    END
  END q[321]
  PIN q[322]
    DIRECTION INPUT ;
    USE SIGNAL ;
    PORT
      LAYER M4 ;
        RECT  32.316 91.728 32.4 91.752 ;
    END
  END q[322]
  PIN q[323]
    DIRECTION INPUT ;
    USE SIGNAL ;
    PORT
      LAYER M4 ;
        RECT  32.316 91.872 32.4 91.896 ;
    END
  END q[323]
  PIN q[324]
    DIRECTION INPUT ;
    USE SIGNAL ;
    PORT
      LAYER M4 ;
        RECT  32.316 92.016 32.4 92.04 ;
    END
  END q[324]
  PIN q[325]
    DIRECTION INPUT ;
    USE SIGNAL ;
    PORT
      LAYER M4 ;
        RECT  32.316 92.16 32.4 92.184 ;
    END
  END q[325]
  PIN q[326]
    DIRECTION INPUT ;
    USE SIGNAL ;
    PORT
      LAYER M4 ;
        RECT  32.316 92.304 32.4 92.328 ;
    END
  END q[326]
  PIN q[327]
    DIRECTION INPUT ;
    USE SIGNAL ;
    PORT
      LAYER M4 ;
        RECT  32.316 92.448 32.4 92.472 ;
    END
  END q[327]
  PIN q[328]
    DIRECTION INPUT ;
    USE SIGNAL ;
    PORT
      LAYER M4 ;
        RECT  32.316 92.592 32.4 92.616 ;
    END
  END q[328]
  PIN q[329]
    DIRECTION INPUT ;
    USE SIGNAL ;
    PORT
      LAYER M4 ;
        RECT  32.316 92.736 32.4 92.76 ;
    END
  END q[329]
  PIN q[32]
    DIRECTION INPUT ;
    USE SIGNAL ;
    PORT
      LAYER M4 ;
        RECT  32.316 47.664 32.4 47.688 ;
    END
  END q[32]
  PIN q[330]
    DIRECTION INPUT ;
    USE SIGNAL ;
    PORT
      LAYER M4 ;
        RECT  32.316 92.88 32.4 92.904 ;
    END
  END q[330]
  PIN q[331]
    DIRECTION INPUT ;
    USE SIGNAL ;
    PORT
      LAYER M4 ;
        RECT  32.316 93.024 32.4 93.048 ;
    END
  END q[331]
  PIN q[332]
    DIRECTION INPUT ;
    USE SIGNAL ;
    PORT
      LAYER M4 ;
        RECT  32.316 93.168 32.4 93.192 ;
    END
  END q[332]
  PIN q[333]
    DIRECTION INPUT ;
    USE SIGNAL ;
    PORT
      LAYER M4 ;
        RECT  32.316 93.312 32.4 93.336 ;
    END
  END q[333]
  PIN q[334]
    DIRECTION INPUT ;
    USE SIGNAL ;
    PORT
      LAYER M4 ;
        RECT  32.316 93.456 32.4 93.48 ;
    END
  END q[334]
  PIN q[335]
    DIRECTION INPUT ;
    USE SIGNAL ;
    PORT
      LAYER M4 ;
        RECT  32.316 93.6 32.4 93.624 ;
    END
  END q[335]
  PIN q[336]
    DIRECTION INPUT ;
    USE SIGNAL ;
    PORT
      LAYER M4 ;
        RECT  32.316 93.744 32.4 93.768 ;
    END
  END q[336]
  PIN q[337]
    DIRECTION INPUT ;
    USE SIGNAL ;
    PORT
      LAYER M4 ;
        RECT  32.316 93.888 32.4 93.912 ;
    END
  END q[337]
  PIN q[338]
    DIRECTION INPUT ;
    USE SIGNAL ;
    PORT
      LAYER M4 ;
        RECT  32.316 94.032 32.4 94.056 ;
    END
  END q[338]
  PIN q[339]
    DIRECTION INPUT ;
    USE SIGNAL ;
    PORT
      LAYER M4 ;
        RECT  32.316 94.176 32.4 94.2 ;
    END
  END q[339]
  PIN q[33]
    DIRECTION INPUT ;
    USE SIGNAL ;
    PORT
      LAYER M4 ;
        RECT  32.316 47.808 32.4 47.832 ;
    END
  END q[33]
  PIN q[340]
    DIRECTION INPUT ;
    USE SIGNAL ;
    PORT
      LAYER M4 ;
        RECT  32.316 94.32 32.4 94.344 ;
    END
  END q[340]
  PIN q[341]
    DIRECTION INPUT ;
    USE SIGNAL ;
    PORT
      LAYER M4 ;
        RECT  32.316 94.464 32.4 94.488 ;
    END
  END q[341]
  PIN q[342]
    DIRECTION INPUT ;
    USE SIGNAL ;
    PORT
      LAYER M4 ;
        RECT  32.316 94.608 32.4 94.632 ;
    END
  END q[342]
  PIN q[343]
    DIRECTION INPUT ;
    USE SIGNAL ;
    PORT
      LAYER M4 ;
        RECT  32.316 94.752 32.4 94.776 ;
    END
  END q[343]
  PIN q[344]
    DIRECTION INPUT ;
    USE SIGNAL ;
    PORT
      LAYER M4 ;
        RECT  32.316 94.896 32.4 94.92 ;
    END
  END q[344]
  PIN q[345]
    DIRECTION INPUT ;
    USE SIGNAL ;
    PORT
      LAYER M4 ;
        RECT  32.316 95.04 32.4 95.064 ;
    END
  END q[345]
  PIN q[346]
    DIRECTION INPUT ;
    USE SIGNAL ;
    PORT
      LAYER M4 ;
        RECT  32.316 95.184 32.4 95.208 ;
    END
  END q[346]
  PIN q[347]
    DIRECTION INPUT ;
    USE SIGNAL ;
    PORT
      LAYER M4 ;
        RECT  32.316 95.328 32.4 95.352 ;
    END
  END q[347]
  PIN q[348]
    DIRECTION INPUT ;
    USE SIGNAL ;
    PORT
      LAYER M4 ;
        RECT  32.316 95.472 32.4 95.496 ;
    END
  END q[348]
  PIN q[349]
    DIRECTION INPUT ;
    USE SIGNAL ;
    PORT
      LAYER M4 ;
        RECT  32.316 95.616 32.4 95.64 ;
    END
  END q[349]
  PIN q[34]
    DIRECTION INPUT ;
    USE SIGNAL ;
    PORT
      LAYER M4 ;
        RECT  32.316 34.128 32.4 34.152 ;
    END
  END q[34]
  PIN q[350]
    DIRECTION INPUT ;
    USE SIGNAL ;
    PORT
      LAYER M4 ;
        RECT  32.316 95.76 32.4 95.784 ;
    END
  END q[350]
  PIN q[351]
    DIRECTION INPUT ;
    USE SIGNAL ;
    PORT
      LAYER M4 ;
        RECT  32.316 95.904 32.4 95.928 ;
    END
  END q[351]
  PIN q[352]
    DIRECTION INPUT ;
    USE SIGNAL ;
    PORT
      LAYER M4 ;
        RECT  32.316 96.048 32.4 96.072 ;
    END
  END q[352]
  PIN q[353]
    DIRECTION INPUT ;
    USE SIGNAL ;
    PORT
      LAYER M4 ;
        RECT  32.316 96.192 32.4 96.216 ;
    END
  END q[353]
  PIN q[354]
    DIRECTION INPUT ;
    USE SIGNAL ;
    PORT
      LAYER M4 ;
        RECT  32.316 14.544 32.4 14.568 ;
    END
  END q[354]
  PIN q[355]
    DIRECTION INPUT ;
    USE SIGNAL ;
    PORT
      LAYER M4 ;
        RECT  32.316 14.688 32.4 14.712 ;
    END
  END q[355]
  PIN q[356]
    DIRECTION INPUT ;
    USE SIGNAL ;
    PORT
      LAYER M4 ;
        RECT  32.316 14.832 32.4 14.856 ;
    END
  END q[356]
  PIN q[357]
    DIRECTION INPUT ;
    USE SIGNAL ;
    PORT
      LAYER M4 ;
        RECT  32.316 14.976 32.4 15 ;
    END
  END q[357]
  PIN q[358]
    DIRECTION INPUT ;
    USE SIGNAL ;
    PORT
      LAYER M4 ;
        RECT  32.316 15.12 32.4 15.144 ;
    END
  END q[358]
  PIN q[359]
    DIRECTION INPUT ;
    USE SIGNAL ;
    PORT
      LAYER M4 ;
        RECT  32.316 15.264 32.4 15.288 ;
    END
  END q[359]
  PIN q[35]
    DIRECTION INPUT ;
    USE SIGNAL ;
    PORT
      LAYER M4 ;
        RECT  32.316 34.272 32.4 34.296 ;
    END
  END q[35]
  PIN q[360]
    DIRECTION INPUT ;
    USE SIGNAL ;
    PORT
      LAYER M4 ;
        RECT  32.316 15.408 32.4 15.432 ;
    END
  END q[360]
  PIN q[361]
    DIRECTION INPUT ;
    USE SIGNAL ;
    PORT
      LAYER M4 ;
        RECT  32.316 15.552 32.4 15.576 ;
    END
  END q[361]
  PIN q[362]
    DIRECTION INPUT ;
    USE SIGNAL ;
    PORT
      LAYER M4 ;
        RECT  32.316 15.696 32.4 15.72 ;
    END
  END q[362]
  PIN q[363]
    DIRECTION INPUT ;
    USE SIGNAL ;
    PORT
      LAYER M4 ;
        RECT  32.316 15.84 32.4 15.864 ;
    END
  END q[363]
  PIN q[364]
    DIRECTION INPUT ;
    USE SIGNAL ;
    PORT
      LAYER M4 ;
        RECT  32.316 15.984 32.4 16.008 ;
    END
  END q[364]
  PIN q[365]
    DIRECTION INPUT ;
    USE SIGNAL ;
    PORT
      LAYER M4 ;
        RECT  32.316 16.128 32.4 16.152 ;
    END
  END q[365]
  PIN q[366]
    DIRECTION INPUT ;
    USE SIGNAL ;
    PORT
      LAYER M4 ;
        RECT  32.316 16.272 32.4 16.296 ;
    END
  END q[366]
  PIN q[367]
    DIRECTION INPUT ;
    USE SIGNAL ;
    PORT
      LAYER M4 ;
        RECT  32.316 16.416 32.4 16.44 ;
    END
  END q[367]
  PIN q[368]
    DIRECTION INPUT ;
    USE SIGNAL ;
    PORT
      LAYER M4 ;
        RECT  32.316 16.56 32.4 16.584 ;
    END
  END q[368]
  PIN q[369]
    DIRECTION INPUT ;
    USE SIGNAL ;
    PORT
      LAYER M4 ;
        RECT  32.316 16.704 32.4 16.728 ;
    END
  END q[369]
  PIN q[36]
    DIRECTION INPUT ;
    USE SIGNAL ;
    PORT
      LAYER M4 ;
        RECT  32.316 34.416 32.4 34.44 ;
    END
  END q[36]
  PIN q[370]
    DIRECTION INPUT ;
    USE SIGNAL ;
    PORT
      LAYER M4 ;
        RECT  32.316 16.848 32.4 16.872 ;
    END
  END q[370]
  PIN q[371]
    DIRECTION INPUT ;
    USE SIGNAL ;
    PORT
      LAYER M4 ;
        RECT  32.316 16.992 32.4 17.016 ;
    END
  END q[371]
  PIN q[372]
    DIRECTION INPUT ;
    USE SIGNAL ;
    PORT
      LAYER M4 ;
        RECT  32.316 17.136 32.4 17.16 ;
    END
  END q[372]
  PIN q[373]
    DIRECTION INPUT ;
    USE SIGNAL ;
    PORT
      LAYER M4 ;
        RECT  32.316 17.28 32.4 17.304 ;
    END
  END q[373]
  PIN q[374]
    DIRECTION INPUT ;
    USE SIGNAL ;
    PORT
      LAYER M4 ;
        RECT  32.316 17.424 32.4 17.448 ;
    END
  END q[374]
  PIN q[375]
    DIRECTION INPUT ;
    USE SIGNAL ;
    PORT
      LAYER M4 ;
        RECT  32.316 17.568 32.4 17.592 ;
    END
  END q[375]
  PIN q[376]
    DIRECTION INPUT ;
    USE SIGNAL ;
    PORT
      LAYER M4 ;
        RECT  32.316 17.712 32.4 17.736 ;
    END
  END q[376]
  PIN q[377]
    DIRECTION INPUT ;
    USE SIGNAL ;
    PORT
      LAYER M4 ;
        RECT  32.316 17.856 32.4 17.88 ;
    END
  END q[377]
  PIN q[378]
    DIRECTION INPUT ;
    USE SIGNAL ;
    PORT
      LAYER M4 ;
        RECT  32.316 18 32.4 18.024 ;
    END
  END q[378]
  PIN q[379]
    DIRECTION INPUT ;
    USE SIGNAL ;
    PORT
      LAYER M4 ;
        RECT  32.316 18.144 32.4 18.168 ;
    END
  END q[379]
  PIN q[37]
    DIRECTION INPUT ;
    USE SIGNAL ;
    PORT
      LAYER M4 ;
        RECT  32.316 34.56 32.4 34.584 ;
    END
  END q[37]
  PIN q[380]
    DIRECTION INPUT ;
    USE SIGNAL ;
    PORT
      LAYER M4 ;
        RECT  32.316 18.288 32.4 18.312 ;
    END
  END q[380]
  PIN q[381]
    DIRECTION INPUT ;
    USE SIGNAL ;
    PORT
      LAYER M4 ;
        RECT  32.316 18.432 32.4 18.456 ;
    END
  END q[381]
  PIN q[382]
    DIRECTION INPUT ;
    USE SIGNAL ;
    PORT
      LAYER M4 ;
        RECT  32.316 18.576 32.4 18.6 ;
    END
  END q[382]
  PIN q[383]
    DIRECTION INPUT ;
    USE SIGNAL ;
    PORT
      LAYER M4 ;
        RECT  32.316 18.72 32.4 18.744 ;
    END
  END q[383]
  PIN q[384]
    DIRECTION INPUT ;
    USE SIGNAL ;
    PORT
      LAYER M4 ;
        RECT  32.316 18.864 32.4 18.888 ;
    END
  END q[384]
  PIN q[385]
    DIRECTION INPUT ;
    USE SIGNAL ;
    PORT
      LAYER M4 ;
        RECT  32.316 19.008 32.4 19.032 ;
    END
  END q[385]
  PIN q[386]
    DIRECTION INPUT ;
    USE SIGNAL ;
    PORT
      LAYER M4 ;
        RECT  32.316 87.12 32.4 87.144 ;
    END
  END q[386]
  PIN q[387]
    DIRECTION INPUT ;
    USE SIGNAL ;
    PORT
      LAYER M4 ;
        RECT  32.316 87.264 32.4 87.288 ;
    END
  END q[387]
  PIN q[388]
    DIRECTION INPUT ;
    USE SIGNAL ;
    PORT
      LAYER M4 ;
        RECT  32.316 87.408 32.4 87.432 ;
    END
  END q[388]
  PIN q[389]
    DIRECTION INPUT ;
    USE SIGNAL ;
    PORT
      LAYER M4 ;
        RECT  32.316 87.552 32.4 87.576 ;
    END
  END q[389]
  PIN q[38]
    DIRECTION INPUT ;
    USE SIGNAL ;
    PORT
      LAYER M4 ;
        RECT  32.316 34.704 32.4 34.728 ;
    END
  END q[38]
  PIN q[390]
    DIRECTION INPUT ;
    USE SIGNAL ;
    PORT
      LAYER M4 ;
        RECT  32.316 87.696 32.4 87.72 ;
    END
  END q[390]
  PIN q[391]
    DIRECTION INPUT ;
    USE SIGNAL ;
    PORT
      LAYER M4 ;
        RECT  32.316 87.84 32.4 87.864 ;
    END
  END q[391]
  PIN q[392]
    DIRECTION INPUT ;
    USE SIGNAL ;
    PORT
      LAYER M4 ;
        RECT  32.316 87.984 32.4 88.008 ;
    END
  END q[392]
  PIN q[393]
    DIRECTION INPUT ;
    USE SIGNAL ;
    PORT
      LAYER M4 ;
        RECT  32.316 88.128 32.4 88.152 ;
    END
  END q[393]
  PIN q[394]
    DIRECTION INPUT ;
    USE SIGNAL ;
    PORT
      LAYER M4 ;
        RECT  32.316 88.272 32.4 88.296 ;
    END
  END q[394]
  PIN q[395]
    DIRECTION INPUT ;
    USE SIGNAL ;
    PORT
      LAYER M4 ;
        RECT  32.316 88.416 32.4 88.44 ;
    END
  END q[395]
  PIN q[396]
    DIRECTION INPUT ;
    USE SIGNAL ;
    PORT
      LAYER M4 ;
        RECT  32.316 88.56 32.4 88.584 ;
    END
  END q[396]
  PIN q[397]
    DIRECTION INPUT ;
    USE SIGNAL ;
    PORT
      LAYER M4 ;
        RECT  32.316 88.704 32.4 88.728 ;
    END
  END q[397]
  PIN q[398]
    DIRECTION INPUT ;
    USE SIGNAL ;
    PORT
      LAYER M4 ;
        RECT  32.316 88.848 32.4 88.872 ;
    END
  END q[398]
  PIN q[399]
    DIRECTION INPUT ;
    USE SIGNAL ;
    PORT
      LAYER M4 ;
        RECT  32.316 88.992 32.4 89.016 ;
    END
  END q[399]
  PIN q[39]
    DIRECTION INPUT ;
    USE SIGNAL ;
    PORT
      LAYER M4 ;
        RECT  32.316 34.848 32.4 34.872 ;
    END
  END q[39]
  PIN q[3]
    DIRECTION INPUT ;
    USE SIGNAL ;
    PORT
      LAYER M4 ;
        RECT  32.316 43.488 32.4 43.512 ;
    END
  END q[3]
  PIN q[400]
    DIRECTION INPUT ;
    USE SIGNAL ;
    PORT
      LAYER M4 ;
        RECT  32.316 89.136 32.4 89.16 ;
    END
  END q[400]
  PIN q[401]
    DIRECTION INPUT ;
    USE SIGNAL ;
    PORT
      LAYER M4 ;
        RECT  32.316 89.28 32.4 89.304 ;
    END
  END q[401]
  PIN q[402]
    DIRECTION INPUT ;
    USE SIGNAL ;
    PORT
      LAYER M4 ;
        RECT  32.316 89.424 32.4 89.448 ;
    END
  END q[402]
  PIN q[403]
    DIRECTION INPUT ;
    USE SIGNAL ;
    PORT
      LAYER M4 ;
        RECT  32.316 89.568 32.4 89.592 ;
    END
  END q[403]
  PIN q[404]
    DIRECTION INPUT ;
    USE SIGNAL ;
    PORT
      LAYER M4 ;
        RECT  32.316 89.712 32.4 89.736 ;
    END
  END q[404]
  PIN q[405]
    DIRECTION INPUT ;
    USE SIGNAL ;
    PORT
      LAYER M4 ;
        RECT  32.316 89.856 32.4 89.88 ;
    END
  END q[405]
  PIN q[406]
    DIRECTION INPUT ;
    USE SIGNAL ;
    PORT
      LAYER M4 ;
        RECT  32.316 90 32.4 90.024 ;
    END
  END q[406]
  PIN q[407]
    DIRECTION INPUT ;
    USE SIGNAL ;
    PORT
      LAYER M4 ;
        RECT  32.316 90.144 32.4 90.168 ;
    END
  END q[407]
  PIN q[408]
    DIRECTION INPUT ;
    USE SIGNAL ;
    PORT
      LAYER M4 ;
        RECT  32.316 90.288 32.4 90.312 ;
    END
  END q[408]
  PIN q[409]
    DIRECTION INPUT ;
    USE SIGNAL ;
    PORT
      LAYER M4 ;
        RECT  32.316 90.432 32.4 90.456 ;
    END
  END q[409]
  PIN q[40]
    DIRECTION INPUT ;
    USE SIGNAL ;
    PORT
      LAYER M4 ;
        RECT  32.316 34.992 32.4 35.016 ;
    END
  END q[40]
  PIN q[410]
    DIRECTION INPUT ;
    USE SIGNAL ;
    PORT
      LAYER M4 ;
        RECT  32.316 90.576 32.4 90.6 ;
    END
  END q[410]
  PIN q[411]
    DIRECTION INPUT ;
    USE SIGNAL ;
    PORT
      LAYER M4 ;
        RECT  32.316 90.72 32.4 90.744 ;
    END
  END q[411]
  PIN q[412]
    DIRECTION INPUT ;
    USE SIGNAL ;
    PORT
      LAYER M4 ;
        RECT  32.316 90.864 32.4 90.888 ;
    END
  END q[412]
  PIN q[413]
    DIRECTION INPUT ;
    USE SIGNAL ;
    PORT
      LAYER M4 ;
        RECT  32.316 91.008 32.4 91.032 ;
    END
  END q[413]
  PIN q[414]
    DIRECTION INPUT ;
    USE SIGNAL ;
    PORT
      LAYER M4 ;
        RECT  32.316 91.152 32.4 91.176 ;
    END
  END q[414]
  PIN q[415]
    DIRECTION INPUT ;
    USE SIGNAL ;
    PORT
      LAYER M4 ;
        RECT  32.316 91.296 32.4 91.32 ;
    END
  END q[415]
  PIN q[416]
    DIRECTION INPUT ;
    USE SIGNAL ;
    PORT
      LAYER M4 ;
        RECT  32.316 91.44 32.4 91.464 ;
    END
  END q[416]
  PIN q[417]
    DIRECTION INPUT ;
    USE SIGNAL ;
    PORT
      LAYER M4 ;
        RECT  32.316 91.584 32.4 91.608 ;
    END
  END q[417]
  PIN q[418]
    DIRECTION INPUT ;
    USE SIGNAL ;
    PORT
      LAYER M4 ;
        RECT  32.316 23.76 32.4 23.784 ;
    END
  END q[418]
  PIN q[419]
    DIRECTION INPUT ;
    USE SIGNAL ;
    PORT
      LAYER M4 ;
        RECT  32.316 23.904 32.4 23.928 ;
    END
  END q[419]
  PIN q[41]
    DIRECTION INPUT ;
    USE SIGNAL ;
    PORT
      LAYER M4 ;
        RECT  32.316 35.136 32.4 35.16 ;
    END
  END q[41]
  PIN q[420]
    DIRECTION INPUT ;
    USE SIGNAL ;
    PORT
      LAYER M4 ;
        RECT  32.316 24.048 32.4 24.072 ;
    END
  END q[420]
  PIN q[421]
    DIRECTION INPUT ;
    USE SIGNAL ;
    PORT
      LAYER M4 ;
        RECT  32.316 24.192 32.4 24.216 ;
    END
  END q[421]
  PIN q[422]
    DIRECTION INPUT ;
    USE SIGNAL ;
    PORT
      LAYER M4 ;
        RECT  32.316 24.336 32.4 24.36 ;
    END
  END q[422]
  PIN q[423]
    DIRECTION INPUT ;
    USE SIGNAL ;
    PORT
      LAYER M4 ;
        RECT  32.316 24.48 32.4 24.504 ;
    END
  END q[423]
  PIN q[424]
    DIRECTION INPUT ;
    USE SIGNAL ;
    PORT
      LAYER M4 ;
        RECT  32.316 24.624 32.4 24.648 ;
    END
  END q[424]
  PIN q[425]
    DIRECTION INPUT ;
    USE SIGNAL ;
    PORT
      LAYER M4 ;
        RECT  32.316 24.768 32.4 24.792 ;
    END
  END q[425]
  PIN q[426]
    DIRECTION INPUT ;
    USE SIGNAL ;
    PORT
      LAYER M4 ;
        RECT  32.316 24.912 32.4 24.936 ;
    END
  END q[426]
  PIN q[427]
    DIRECTION INPUT ;
    USE SIGNAL ;
    PORT
      LAYER M4 ;
        RECT  32.316 25.056 32.4 25.08 ;
    END
  END q[427]
  PIN q[428]
    DIRECTION INPUT ;
    USE SIGNAL ;
    PORT
      LAYER M4 ;
        RECT  32.316 25.2 32.4 25.224 ;
    END
  END q[428]
  PIN q[429]
    DIRECTION INPUT ;
    USE SIGNAL ;
    PORT
      LAYER M4 ;
        RECT  32.316 25.344 32.4 25.368 ;
    END
  END q[429]
  PIN q[42]
    DIRECTION INPUT ;
    USE SIGNAL ;
    PORT
      LAYER M4 ;
        RECT  32.316 35.28 32.4 35.304 ;
    END
  END q[42]
  PIN q[430]
    DIRECTION INPUT ;
    USE SIGNAL ;
    PORT
      LAYER M4 ;
        RECT  32.316 25.488 32.4 25.512 ;
    END
  END q[430]
  PIN q[431]
    DIRECTION INPUT ;
    USE SIGNAL ;
    PORT
      LAYER M4 ;
        RECT  32.316 25.632 32.4 25.656 ;
    END
  END q[431]
  PIN q[432]
    DIRECTION INPUT ;
    USE SIGNAL ;
    PORT
      LAYER M4 ;
        RECT  32.316 25.776 32.4 25.8 ;
    END
  END q[432]
  PIN q[433]
    DIRECTION INPUT ;
    USE SIGNAL ;
    PORT
      LAYER M4 ;
        RECT  32.316 25.92 32.4 25.944 ;
    END
  END q[433]
  PIN q[434]
    DIRECTION INPUT ;
    USE SIGNAL ;
    PORT
      LAYER M4 ;
        RECT  32.316 26.064 32.4 26.088 ;
    END
  END q[434]
  PIN q[435]
    DIRECTION INPUT ;
    USE SIGNAL ;
    PORT
      LAYER M4 ;
        RECT  32.316 26.208 32.4 26.232 ;
    END
  END q[435]
  PIN q[436]
    DIRECTION INPUT ;
    USE SIGNAL ;
    PORT
      LAYER M4 ;
        RECT  32.316 26.352 32.4 26.376 ;
    END
  END q[436]
  PIN q[437]
    DIRECTION INPUT ;
    USE SIGNAL ;
    PORT
      LAYER M4 ;
        RECT  32.316 26.496 32.4 26.52 ;
    END
  END q[437]
  PIN q[438]
    DIRECTION INPUT ;
    USE SIGNAL ;
    PORT
      LAYER M4 ;
        RECT  32.316 26.64 32.4 26.664 ;
    END
  END q[438]
  PIN q[439]
    DIRECTION INPUT ;
    USE SIGNAL ;
    PORT
      LAYER M4 ;
        RECT  32.316 26.784 32.4 26.808 ;
    END
  END q[439]
  PIN q[43]
    DIRECTION INPUT ;
    USE SIGNAL ;
    PORT
      LAYER M4 ;
        RECT  32.316 35.424 32.4 35.448 ;
    END
  END q[43]
  PIN q[440]
    DIRECTION INPUT ;
    USE SIGNAL ;
    PORT
      LAYER M4 ;
        RECT  32.316 26.928 32.4 26.952 ;
    END
  END q[440]
  PIN q[441]
    DIRECTION INPUT ;
    USE SIGNAL ;
    PORT
      LAYER M4 ;
        RECT  32.316 27.072 32.4 27.096 ;
    END
  END q[441]
  PIN q[442]
    DIRECTION INPUT ;
    USE SIGNAL ;
    PORT
      LAYER M4 ;
        RECT  32.316 27.216 32.4 27.24 ;
    END
  END q[442]
  PIN q[443]
    DIRECTION INPUT ;
    USE SIGNAL ;
    PORT
      LAYER M4 ;
        RECT  32.316 27.36 32.4 27.384 ;
    END
  END q[443]
  PIN q[444]
    DIRECTION INPUT ;
    USE SIGNAL ;
    PORT
      LAYER M4 ;
        RECT  32.316 27.504 32.4 27.528 ;
    END
  END q[444]
  PIN q[445]
    DIRECTION INPUT ;
    USE SIGNAL ;
    PORT
      LAYER M4 ;
        RECT  32.316 27.648 32.4 27.672 ;
    END
  END q[445]
  PIN q[446]
    DIRECTION INPUT ;
    USE SIGNAL ;
    PORT
      LAYER M4 ;
        RECT  32.316 27.792 32.4 27.816 ;
    END
  END q[446]
  PIN q[447]
    DIRECTION INPUT ;
    USE SIGNAL ;
    PORT
      LAYER M4 ;
        RECT  32.316 27.936 32.4 27.96 ;
    END
  END q[447]
  PIN q[448]
    DIRECTION INPUT ;
    USE SIGNAL ;
    PORT
      LAYER M4 ;
        RECT  32.316 28.08 32.4 28.104 ;
    END
  END q[448]
  PIN q[449]
    DIRECTION INPUT ;
    USE SIGNAL ;
    PORT
      LAYER M4 ;
        RECT  32.316 28.224 32.4 28.248 ;
    END
  END q[449]
  PIN q[44]
    DIRECTION INPUT ;
    USE SIGNAL ;
    PORT
      LAYER M4 ;
        RECT  32.316 35.568 32.4 35.592 ;
    END
  END q[44]
  PIN q[450]
    DIRECTION INPUT ;
    USE SIGNAL ;
    PORT
      LAYER M4 ;
        RECT  32.316 19.152 32.4 19.176 ;
    END
  END q[450]
  PIN q[451]
    DIRECTION INPUT ;
    USE SIGNAL ;
    PORT
      LAYER M4 ;
        RECT  32.316 19.296 32.4 19.32 ;
    END
  END q[451]
  PIN q[452]
    DIRECTION INPUT ;
    USE SIGNAL ;
    PORT
      LAYER M4 ;
        RECT  32.316 19.44 32.4 19.464 ;
    END
  END q[452]
  PIN q[453]
    DIRECTION INPUT ;
    USE SIGNAL ;
    PORT
      LAYER M4 ;
        RECT  32.316 19.584 32.4 19.608 ;
    END
  END q[453]
  PIN q[454]
    DIRECTION INPUT ;
    USE SIGNAL ;
    PORT
      LAYER M4 ;
        RECT  32.316 19.728 32.4 19.752 ;
    END
  END q[454]
  PIN q[455]
    DIRECTION INPUT ;
    USE SIGNAL ;
    PORT
      LAYER M4 ;
        RECT  32.316 19.872 32.4 19.896 ;
    END
  END q[455]
  PIN q[456]
    DIRECTION INPUT ;
    USE SIGNAL ;
    PORT
      LAYER M4 ;
        RECT  32.316 20.016 32.4 20.04 ;
    END
  END q[456]
  PIN q[457]
    DIRECTION INPUT ;
    USE SIGNAL ;
    PORT
      LAYER M4 ;
        RECT  32.316 20.16 32.4 20.184 ;
    END
  END q[457]
  PIN q[458]
    DIRECTION INPUT ;
    USE SIGNAL ;
    PORT
      LAYER M4 ;
        RECT  32.316 20.304 32.4 20.328 ;
    END
  END q[458]
  PIN q[459]
    DIRECTION INPUT ;
    USE SIGNAL ;
    PORT
      LAYER M4 ;
        RECT  32.316 20.448 32.4 20.472 ;
    END
  END q[459]
  PIN q[45]
    DIRECTION INPUT ;
    USE SIGNAL ;
    PORT
      LAYER M4 ;
        RECT  32.316 35.712 32.4 35.736 ;
    END
  END q[45]
  PIN q[460]
    DIRECTION INPUT ;
    USE SIGNAL ;
    PORT
      LAYER M4 ;
        RECT  32.316 20.592 32.4 20.616 ;
    END
  END q[460]
  PIN q[461]
    DIRECTION INPUT ;
    USE SIGNAL ;
    PORT
      LAYER M4 ;
        RECT  32.316 20.736 32.4 20.76 ;
    END
  END q[461]
  PIN q[462]
    DIRECTION INPUT ;
    USE SIGNAL ;
    PORT
      LAYER M4 ;
        RECT  32.316 20.88 32.4 20.904 ;
    END
  END q[462]
  PIN q[463]
    DIRECTION INPUT ;
    USE SIGNAL ;
    PORT
      LAYER M4 ;
        RECT  32.316 21.024 32.4 21.048 ;
    END
  END q[463]
  PIN q[464]
    DIRECTION INPUT ;
    USE SIGNAL ;
    PORT
      LAYER M4 ;
        RECT  32.316 21.168 32.4 21.192 ;
    END
  END q[464]
  PIN q[465]
    DIRECTION INPUT ;
    USE SIGNAL ;
    PORT
      LAYER M4 ;
        RECT  32.316 21.312 32.4 21.336 ;
    END
  END q[465]
  PIN q[466]
    DIRECTION INPUT ;
    USE SIGNAL ;
    PORT
      LAYER M4 ;
        RECT  32.316 21.456 32.4 21.48 ;
    END
  END q[466]
  PIN q[467]
    DIRECTION INPUT ;
    USE SIGNAL ;
    PORT
      LAYER M4 ;
        RECT  32.316 21.6 32.4 21.624 ;
    END
  END q[467]
  PIN q[468]
    DIRECTION INPUT ;
    USE SIGNAL ;
    PORT
      LAYER M4 ;
        RECT  32.316 21.744 32.4 21.768 ;
    END
  END q[468]
  PIN q[469]
    DIRECTION INPUT ;
    USE SIGNAL ;
    PORT
      LAYER M4 ;
        RECT  32.316 21.888 32.4 21.912 ;
    END
  END q[469]
  PIN q[46]
    DIRECTION INPUT ;
    USE SIGNAL ;
    PORT
      LAYER M4 ;
        RECT  32.316 35.856 32.4 35.88 ;
    END
  END q[46]
  PIN q[470]
    DIRECTION INPUT ;
    USE SIGNAL ;
    PORT
      LAYER M4 ;
        RECT  32.316 22.032 32.4 22.056 ;
    END
  END q[470]
  PIN q[471]
    DIRECTION INPUT ;
    USE SIGNAL ;
    PORT
      LAYER M4 ;
        RECT  32.316 22.176 32.4 22.2 ;
    END
  END q[471]
  PIN q[472]
    DIRECTION INPUT ;
    USE SIGNAL ;
    PORT
      LAYER M4 ;
        RECT  32.316 22.32 32.4 22.344 ;
    END
  END q[472]
  PIN q[473]
    DIRECTION INPUT ;
    USE SIGNAL ;
    PORT
      LAYER M4 ;
        RECT  32.316 22.464 32.4 22.488 ;
    END
  END q[473]
  PIN q[474]
    DIRECTION INPUT ;
    USE SIGNAL ;
    PORT
      LAYER M4 ;
        RECT  32.316 22.608 32.4 22.632 ;
    END
  END q[474]
  PIN q[475]
    DIRECTION INPUT ;
    USE SIGNAL ;
    PORT
      LAYER M4 ;
        RECT  32.316 22.752 32.4 22.776 ;
    END
  END q[475]
  PIN q[476]
    DIRECTION INPUT ;
    USE SIGNAL ;
    PORT
      LAYER M4 ;
        RECT  32.316 22.896 32.4 22.92 ;
    END
  END q[476]
  PIN q[477]
    DIRECTION INPUT ;
    USE SIGNAL ;
    PORT
      LAYER M4 ;
        RECT  32.316 23.04 32.4 23.064 ;
    END
  END q[477]
  PIN q[478]
    DIRECTION INPUT ;
    USE SIGNAL ;
    PORT
      LAYER M4 ;
        RECT  32.316 23.184 32.4 23.208 ;
    END
  END q[478]
  PIN q[479]
    DIRECTION INPUT ;
    USE SIGNAL ;
    PORT
      LAYER M4 ;
        RECT  32.316 23.328 32.4 23.352 ;
    END
  END q[479]
  PIN q[47]
    DIRECTION INPUT ;
    USE SIGNAL ;
    PORT
      LAYER M4 ;
        RECT  32.316 36 32.4 36.024 ;
    END
  END q[47]
  PIN q[480]
    DIRECTION INPUT ;
    USE SIGNAL ;
    PORT
      LAYER M4 ;
        RECT  32.316 23.472 32.4 23.496 ;
    END
  END q[480]
  PIN q[481]
    DIRECTION INPUT ;
    USE SIGNAL ;
    PORT
      LAYER M4 ;
        RECT  32.316 23.616 32.4 23.64 ;
    END
  END q[481]
  PIN q[482]
    DIRECTION INPUT ;
    USE SIGNAL ;
    PORT
      LAYER M4 ;
        RECT  32.316 9.936 32.4 9.96 ;
    END
  END q[482]
  PIN q[483]
    DIRECTION INPUT ;
    USE SIGNAL ;
    PORT
      LAYER M4 ;
        RECT  32.316 10.08 32.4 10.104 ;
    END
  END q[483]
  PIN q[484]
    DIRECTION INPUT ;
    USE SIGNAL ;
    PORT
      LAYER M4 ;
        RECT  32.316 10.224 32.4 10.248 ;
    END
  END q[484]
  PIN q[485]
    DIRECTION INPUT ;
    USE SIGNAL ;
    PORT
      LAYER M4 ;
        RECT  32.316 10.368 32.4 10.392 ;
    END
  END q[485]
  PIN q[486]
    DIRECTION INPUT ;
    USE SIGNAL ;
    PORT
      LAYER M4 ;
        RECT  32.316 10.512 32.4 10.536 ;
    END
  END q[486]
  PIN q[487]
    DIRECTION INPUT ;
    USE SIGNAL ;
    PORT
      LAYER M4 ;
        RECT  32.316 10.656 32.4 10.68 ;
    END
  END q[487]
  PIN q[488]
    DIRECTION INPUT ;
    USE SIGNAL ;
    PORT
      LAYER M4 ;
        RECT  32.316 10.8 32.4 10.824 ;
    END
  END q[488]
  PIN q[489]
    DIRECTION INPUT ;
    USE SIGNAL ;
    PORT
      LAYER M4 ;
        RECT  32.316 10.944 32.4 10.968 ;
    END
  END q[489]
  PIN q[48]
    DIRECTION INPUT ;
    USE SIGNAL ;
    PORT
      LAYER M4 ;
        RECT  32.316 36.144 32.4 36.168 ;
    END
  END q[48]
  PIN q[490]
    DIRECTION INPUT ;
    USE SIGNAL ;
    PORT
      LAYER M4 ;
        RECT  32.316 11.088 32.4 11.112 ;
    END
  END q[490]
  PIN q[491]
    DIRECTION INPUT ;
    USE SIGNAL ;
    PORT
      LAYER M4 ;
        RECT  32.316 11.232 32.4 11.256 ;
    END
  END q[491]
  PIN q[492]
    DIRECTION INPUT ;
    USE SIGNAL ;
    PORT
      LAYER M4 ;
        RECT  32.316 11.376 32.4 11.4 ;
    END
  END q[492]
  PIN q[493]
    DIRECTION INPUT ;
    USE SIGNAL ;
    PORT
      LAYER M4 ;
        RECT  32.316 11.52 32.4 11.544 ;
    END
  END q[493]
  PIN q[494]
    DIRECTION INPUT ;
    USE SIGNAL ;
    PORT
      LAYER M4 ;
        RECT  32.316 11.664 32.4 11.688 ;
    END
  END q[494]
  PIN q[495]
    DIRECTION INPUT ;
    USE SIGNAL ;
    PORT
      LAYER M4 ;
        RECT  32.316 11.808 32.4 11.832 ;
    END
  END q[495]
  PIN q[496]
    DIRECTION INPUT ;
    USE SIGNAL ;
    PORT
      LAYER M4 ;
        RECT  32.316 11.952 32.4 11.976 ;
    END
  END q[496]
  PIN q[497]
    DIRECTION INPUT ;
    USE SIGNAL ;
    PORT
      LAYER M4 ;
        RECT  32.316 12.096 32.4 12.12 ;
    END
  END q[497]
  PIN q[498]
    DIRECTION INPUT ;
    USE SIGNAL ;
    PORT
      LAYER M4 ;
        RECT  32.316 12.24 32.4 12.264 ;
    END
  END q[498]
  PIN q[499]
    DIRECTION INPUT ;
    USE SIGNAL ;
    PORT
      LAYER M4 ;
        RECT  32.316 12.384 32.4 12.408 ;
    END
  END q[499]
  PIN q[49]
    DIRECTION INPUT ;
    USE SIGNAL ;
    PORT
      LAYER M4 ;
        RECT  32.316 36.288 32.4 36.312 ;
    END
  END q[49]
  PIN q[4]
    DIRECTION INPUT ;
    USE SIGNAL ;
    PORT
      LAYER M4 ;
        RECT  32.316 43.632 32.4 43.656 ;
    END
  END q[4]
  PIN q[500]
    DIRECTION INPUT ;
    USE SIGNAL ;
    PORT
      LAYER M4 ;
        RECT  32.316 12.528 32.4 12.552 ;
    END
  END q[500]
  PIN q[501]
    DIRECTION INPUT ;
    USE SIGNAL ;
    PORT
      LAYER M4 ;
        RECT  32.316 12.672 32.4 12.696 ;
    END
  END q[501]
  PIN q[502]
    DIRECTION INPUT ;
    USE SIGNAL ;
    PORT
      LAYER M4 ;
        RECT  32.316 12.816 32.4 12.84 ;
    END
  END q[502]
  PIN q[503]
    DIRECTION INPUT ;
    USE SIGNAL ;
    PORT
      LAYER M4 ;
        RECT  32.316 12.96 32.4 12.984 ;
    END
  END q[503]
  PIN q[504]
    DIRECTION INPUT ;
    USE SIGNAL ;
    PORT
      LAYER M4 ;
        RECT  32.316 13.104 32.4 13.128 ;
    END
  END q[504]
  PIN q[505]
    DIRECTION INPUT ;
    USE SIGNAL ;
    PORT
      LAYER M4 ;
        RECT  32.316 13.248 32.4 13.272 ;
    END
  END q[505]
  PIN q[506]
    DIRECTION INPUT ;
    USE SIGNAL ;
    PORT
      LAYER M4 ;
        RECT  32.316 13.392 32.4 13.416 ;
    END
  END q[506]
  PIN q[507]
    DIRECTION INPUT ;
    USE SIGNAL ;
    PORT
      LAYER M4 ;
        RECT  32.316 13.536 32.4 13.56 ;
    END
  END q[507]
  PIN q[508]
    DIRECTION INPUT ;
    USE SIGNAL ;
    PORT
      LAYER M4 ;
        RECT  32.316 13.68 32.4 13.704 ;
    END
  END q[508]
  PIN q[509]
    DIRECTION INPUT ;
    USE SIGNAL ;
    PORT
      LAYER M4 ;
        RECT  32.316 13.824 32.4 13.848 ;
    END
  END q[509]
  PIN q[50]
    DIRECTION INPUT ;
    USE SIGNAL ;
    PORT
      LAYER M4 ;
        RECT  32.316 36.432 32.4 36.456 ;
    END
  END q[50]
  PIN q[510]
    DIRECTION INPUT ;
    USE SIGNAL ;
    PORT
      LAYER M4 ;
        RECT  32.316 13.968 32.4 13.992 ;
    END
  END q[510]
  PIN q[511]
    DIRECTION INPUT ;
    USE SIGNAL ;
    PORT
      LAYER M4 ;
        RECT  32.316 14.112 32.4 14.136 ;
    END
  END q[511]
  PIN q[51]
    DIRECTION INPUT ;
    USE SIGNAL ;
    PORT
      LAYER M4 ;
        RECT  32.316 36.576 32.4 36.6 ;
    END
  END q[51]
  PIN q[52]
    DIRECTION INPUT ;
    USE SIGNAL ;
    PORT
      LAYER M4 ;
        RECT  32.316 36.72 32.4 36.744 ;
    END
  END q[52]
  PIN q[53]
    DIRECTION INPUT ;
    USE SIGNAL ;
    PORT
      LAYER M4 ;
        RECT  32.316 36.864 32.4 36.888 ;
    END
  END q[53]
  PIN q[54]
    DIRECTION INPUT ;
    USE SIGNAL ;
    PORT
      LAYER M4 ;
        RECT  32.316 37.008 32.4 37.032 ;
    END
  END q[54]
  PIN q[55]
    DIRECTION INPUT ;
    USE SIGNAL ;
    PORT
      LAYER M4 ;
        RECT  32.316 37.152 32.4 37.176 ;
    END
  END q[55]
  PIN q[56]
    DIRECTION INPUT ;
    USE SIGNAL ;
    PORT
      LAYER M4 ;
        RECT  32.316 37.296 32.4 37.32 ;
    END
  END q[56]
  PIN q[57]
    DIRECTION INPUT ;
    USE SIGNAL ;
    PORT
      LAYER M4 ;
        RECT  32.316 37.44 32.4 37.464 ;
    END
  END q[57]
  PIN q[58]
    DIRECTION INPUT ;
    USE SIGNAL ;
    PORT
      LAYER M4 ;
        RECT  32.316 37.584 32.4 37.608 ;
    END
  END q[58]
  PIN q[59]
    DIRECTION INPUT ;
    USE SIGNAL ;
    PORT
      LAYER M4 ;
        RECT  32.316 37.728 32.4 37.752 ;
    END
  END q[59]
  PIN q[5]
    DIRECTION INPUT ;
    USE SIGNAL ;
    PORT
      LAYER M4 ;
        RECT  32.316 43.776 32.4 43.8 ;
    END
  END q[5]
  PIN q[60]
    DIRECTION INPUT ;
    USE SIGNAL ;
    PORT
      LAYER M4 ;
        RECT  32.316 37.872 32.4 37.896 ;
    END
  END q[60]
  PIN q[61]
    DIRECTION INPUT ;
    USE SIGNAL ;
    PORT
      LAYER M4 ;
        RECT  32.316 38.016 32.4 38.04 ;
    END
  END q[61]
  PIN q[62]
    DIRECTION INPUT ;
    USE SIGNAL ;
    PORT
      LAYER M4 ;
        RECT  32.316 38.16 32.4 38.184 ;
    END
  END q[62]
  PIN q[63]
    DIRECTION INPUT ;
    USE SIGNAL ;
    PORT
      LAYER M4 ;
        RECT  32.316 38.304 32.4 38.328 ;
    END
  END q[63]
  PIN q[64]
    DIRECTION INPUT ;
    USE SIGNAL ;
    PORT
      LAYER M4 ;
        RECT  32.316 38.448 32.4 38.472 ;
    END
  END q[64]
  PIN q[65]
    DIRECTION INPUT ;
    USE SIGNAL ;
    PORT
      LAYER M4 ;
        RECT  32.316 38.592 32.4 38.616 ;
    END
  END q[65]
  PIN q[66]
    DIRECTION INPUT ;
    USE SIGNAL ;
    PORT
      LAYER M4 ;
        RECT  32.316 29.52 32.4 29.544 ;
    END
  END q[66]
  PIN q[67]
    DIRECTION INPUT ;
    USE SIGNAL ;
    PORT
      LAYER M4 ;
        RECT  32.316 29.664 32.4 29.688 ;
    END
  END q[67]
  PIN q[68]
    DIRECTION INPUT ;
    USE SIGNAL ;
    PORT
      LAYER M4 ;
        RECT  32.316 29.808 32.4 29.832 ;
    END
  END q[68]
  PIN q[69]
    DIRECTION INPUT ;
    USE SIGNAL ;
    PORT
      LAYER M4 ;
        RECT  32.316 29.952 32.4 29.976 ;
    END
  END q[69]
  PIN q[6]
    DIRECTION INPUT ;
    USE SIGNAL ;
    PORT
      LAYER M4 ;
        RECT  32.316 43.92 32.4 43.944 ;
    END
  END q[6]
  PIN q[70]
    DIRECTION INPUT ;
    USE SIGNAL ;
    PORT
      LAYER M4 ;
        RECT  32.316 30.096 32.4 30.12 ;
    END
  END q[70]
  PIN q[71]
    DIRECTION INPUT ;
    USE SIGNAL ;
    PORT
      LAYER M4 ;
        RECT  32.316 30.24 32.4 30.264 ;
    END
  END q[71]
  PIN q[72]
    DIRECTION INPUT ;
    USE SIGNAL ;
    PORT
      LAYER M4 ;
        RECT  32.316 30.384 32.4 30.408 ;
    END
  END q[72]
  PIN q[73]
    DIRECTION INPUT ;
    USE SIGNAL ;
    PORT
      LAYER M4 ;
        RECT  32.316 30.528 32.4 30.552 ;
    END
  END q[73]
  PIN q[74]
    DIRECTION INPUT ;
    USE SIGNAL ;
    PORT
      LAYER M4 ;
        RECT  32.316 30.672 32.4 30.696 ;
    END
  END q[74]
  PIN q[75]
    DIRECTION INPUT ;
    USE SIGNAL ;
    PORT
      LAYER M4 ;
        RECT  32.316 30.816 32.4 30.84 ;
    END
  END q[75]
  PIN q[76]
    DIRECTION INPUT ;
    USE SIGNAL ;
    PORT
      LAYER M4 ;
        RECT  32.316 30.96 32.4 30.984 ;
    END
  END q[76]
  PIN q[77]
    DIRECTION INPUT ;
    USE SIGNAL ;
    PORT
      LAYER M4 ;
        RECT  32.316 31.104 32.4 31.128 ;
    END
  END q[77]
  PIN q[78]
    DIRECTION INPUT ;
    USE SIGNAL ;
    PORT
      LAYER M4 ;
        RECT  32.316 31.248 32.4 31.272 ;
    END
  END q[78]
  PIN q[79]
    DIRECTION INPUT ;
    USE SIGNAL ;
    PORT
      LAYER M4 ;
        RECT  32.316 31.392 32.4 31.416 ;
    END
  END q[79]
  PIN q[7]
    DIRECTION INPUT ;
    USE SIGNAL ;
    PORT
      LAYER M4 ;
        RECT  32.316 44.064 32.4 44.088 ;
    END
  END q[7]
  PIN q[80]
    DIRECTION INPUT ;
    USE SIGNAL ;
    PORT
      LAYER M4 ;
        RECT  32.316 31.536 32.4 31.56 ;
    END
  END q[80]
  PIN q[81]
    DIRECTION INPUT ;
    USE SIGNAL ;
    PORT
      LAYER M4 ;
        RECT  32.316 31.68 32.4 31.704 ;
    END
  END q[81]
  PIN q[82]
    DIRECTION INPUT ;
    USE SIGNAL ;
    PORT
      LAYER M4 ;
        RECT  32.316 31.824 32.4 31.848 ;
    END
  END q[82]
  PIN q[83]
    DIRECTION INPUT ;
    USE SIGNAL ;
    PORT
      LAYER M4 ;
        RECT  32.316 31.968 32.4 31.992 ;
    END
  END q[83]
  PIN q[84]
    DIRECTION INPUT ;
    USE SIGNAL ;
    PORT
      LAYER M4 ;
        RECT  32.316 32.112 32.4 32.136 ;
    END
  END q[84]
  PIN q[85]
    DIRECTION INPUT ;
    USE SIGNAL ;
    PORT
      LAYER M4 ;
        RECT  32.316 32.256 32.4 32.28 ;
    END
  END q[85]
  PIN q[86]
    DIRECTION INPUT ;
    USE SIGNAL ;
    PORT
      LAYER M4 ;
        RECT  32.316 32.4 32.4 32.424 ;
    END
  END q[86]
  PIN q[87]
    DIRECTION INPUT ;
    USE SIGNAL ;
    PORT
      LAYER M4 ;
        RECT  32.316 32.544 32.4 32.568 ;
    END
  END q[87]
  PIN q[88]
    DIRECTION INPUT ;
    USE SIGNAL ;
    PORT
      LAYER M4 ;
        RECT  32.316 32.688 32.4 32.712 ;
    END
  END q[88]
  PIN q[89]
    DIRECTION INPUT ;
    USE SIGNAL ;
    PORT
      LAYER M4 ;
        RECT  32.316 32.832 32.4 32.856 ;
    END
  END q[89]
  PIN q[8]
    DIRECTION INPUT ;
    USE SIGNAL ;
    PORT
      LAYER M4 ;
        RECT  32.316 44.208 32.4 44.232 ;
    END
  END q[8]
  PIN q[90]
    DIRECTION INPUT ;
    USE SIGNAL ;
    PORT
      LAYER M4 ;
        RECT  32.316 32.976 32.4 33 ;
    END
  END q[90]
  PIN q[91]
    DIRECTION INPUT ;
    USE SIGNAL ;
    PORT
      LAYER M4 ;
        RECT  32.316 33.12 32.4 33.144 ;
    END
  END q[91]
  PIN q[92]
    DIRECTION INPUT ;
    USE SIGNAL ;
    PORT
      LAYER M4 ;
        RECT  32.316 33.264 32.4 33.288 ;
    END
  END q[92]
  PIN q[93]
    DIRECTION INPUT ;
    USE SIGNAL ;
    PORT
      LAYER M4 ;
        RECT  32.316 33.408 32.4 33.432 ;
    END
  END q[93]
  PIN q[94]
    DIRECTION INPUT ;
    USE SIGNAL ;
    PORT
      LAYER M4 ;
        RECT  32.316 33.552 32.4 33.576 ;
    END
  END q[94]
  PIN q[95]
    DIRECTION INPUT ;
    USE SIGNAL ;
    PORT
      LAYER M4 ;
        RECT  32.316 33.696 32.4 33.72 ;
    END
  END q[95]
  PIN q[96]
    DIRECTION INPUT ;
    USE SIGNAL ;
    PORT
      LAYER M4 ;
        RECT  32.316 33.84 32.4 33.864 ;
    END
  END q[96]
  PIN q[97]
    DIRECTION INPUT ;
    USE SIGNAL ;
    PORT
      LAYER M4 ;
        RECT  32.316 33.984 32.4 34.008 ;
    END
  END q[97]
  PIN q[98]
    DIRECTION INPUT ;
    USE SIGNAL ;
    PORT
      LAYER M4 ;
        RECT  32.316 52.56 32.4 52.584 ;
    END
  END q[98]
  PIN q[99]
    DIRECTION INPUT ;
    USE SIGNAL ;
    PORT
      LAYER M4 ;
        RECT  32.316 52.704 32.4 52.728 ;
    END
  END q[99]
  PIN q[9]
    DIRECTION INPUT ;
    USE SIGNAL ;
    PORT
      LAYER M4 ;
        RECT  32.316 44.352 32.4 44.376 ;
    END
  END q[9]
  PIN rst_n
    DIRECTION INPUT ;
    USE SIGNAL ;
    PORT
      LAYER M5 ;
        RECT  29.52 0 29.544 0.084 ;
    END
    PORT
      LAYER M5 ;
        RECT  29.52 0.016 29.544 2.137 ;
    END
  END rst_n
  PIN VDD
    DIRECTION INOUT ;
    USE POWER ;
    PORT
      LAYER M5 ;
        RECT  29.592 2.151 29.712 105.849 ;
        RECT  26.892 2.151 27.012 105.849 ;
        RECT  24.192 2.151 24.312 105.849 ;
        RECT  21.492 2.151 21.612 105.849 ;
        RECT  18.792 2.151 18.912 105.849 ;
        RECT  16.092 2.151 16.212 105.849 ;
        RECT  13.392 2.151 13.512 105.849 ;
        RECT  10.692 2.151 10.812 105.849 ;
        RECT  7.992 2.151 8.112 105.849 ;
        RECT  5.292 2.151 5.412 105.849 ;
        RECT  2.592 2.151 2.712 105.849 ;
    END
  END VDD
  PIN VSS
    DIRECTION INOUT ;
    USE GROUND ;
    PORT
      LAYER M5 ;
        RECT  29.4 2.137 29.52 105.863 ;
        RECT  26.7 2.137 26.82 105.863 ;
        RECT  24 2.137 24.12 105.863 ;
        RECT  21.3 2.137 21.42 105.863 ;
        RECT  18.6 2.137 18.72 105.863 ;
        RECT  15.9 2.137 16.02 105.863 ;
        RECT  13.2 2.137 13.32 105.863 ;
        RECT  10.5 2.137 10.62 105.863 ;
        RECT  7.8 2.137 7.92 105.863 ;
        RECT  5.1 2.137 5.22 105.863 ;
        RECT  2.4 2.137 2.52 105.863 ;
    END
  END VSS
  # OT_OBS_CLOSED layer=M5 d_um=1.536 added=88
  OBS
    LAYER RVTN ;
     RECT  2.16 2.16 30.24 2.295 ;
     RECT  2.16 2.565 30.24 2.835 ;
     RECT  2.16 3.105 30.24 3.375 ;
     RECT  2.16 3.645 30.24 3.915 ;
     RECT  2.16 4.185 30.24 4.455 ;
     RECT  2.16 4.725 30.24 4.995 ;
     RECT  2.16 5.265 30.24 5.535 ;
     RECT  2.16 5.805 30.24 6.075 ;
     RECT  2.16 6.345 30.24 6.615 ;
     RECT  2.16 6.885 30.24 7.155 ;
     RECT  2.16 7.425 30.24 7.695 ;
     RECT  2.16 7.965 30.24 8.235 ;
     RECT  2.16 8.505 30.24 8.775 ;
     RECT  2.16 9.045 30.24 9.315 ;
     RECT  2.16 9.585 30.24 9.855 ;
     RECT  2.16 10.125 30.24 10.395 ;
     RECT  2.16 10.665 30.24 10.935 ;
     RECT  2.16 11.205 30.24 11.475 ;
     RECT  2.16 11.745 30.24 12.015 ;
     RECT  2.16 12.285 30.24 12.555 ;
     RECT  2.16 12.825 30.24 13.095 ;
     RECT  2.16 13.365 30.24 13.635 ;
     RECT  2.16 13.905 30.24 14.175 ;
     RECT  2.16 14.445 30.24 14.715 ;
     RECT  2.16 14.985 30.24 15.255 ;
     RECT  2.16 15.525 30.24 15.795 ;
     RECT  2.16 16.065 30.24 16.335 ;
     RECT  2.16 16.605 30.24 16.875 ;
     RECT  2.16 17.145 30.24 17.415 ;
     RECT  2.16 17.685 30.24 17.955 ;
     RECT  2.16 18.225 30.24 18.495 ;
     RECT  2.16 18.765 30.24 19.035 ;
     RECT  2.16 19.305 30.24 19.575 ;
     RECT  2.16 19.845 30.24 20.115 ;
     RECT  2.16 20.385 30.24 20.655 ;
     RECT  2.16 20.925 30.24 21.195 ;
     RECT  2.16 21.465 30.24 21.735 ;
     RECT  2.16 22.005 30.24 22.275 ;
     RECT  2.16 22.545 30.24 22.815 ;
     RECT  2.16 23.085 30.24 23.355 ;
     RECT  2.16 23.625 30.24 23.895 ;
     RECT  2.16 24.165 30.24 24.435 ;
     RECT  2.16 24.705 30.24 24.975 ;
     RECT  2.16 25.245 30.24 25.515 ;
     RECT  2.16 25.785 30.24 26.055 ;
     RECT  2.16 26.325 30.24 26.595 ;
     RECT  2.16 26.865 30.24 27.135 ;
     RECT  2.16 27.405 30.24 27.675 ;
     RECT  2.16 27.945 30.24 28.215 ;
     RECT  2.16 28.485 30.24 28.755 ;
     RECT  2.16 29.025 30.24 29.295 ;
     RECT  2.16 29.565 30.24 29.835 ;
     RECT  2.16 30.105 30.24 30.375 ;
     RECT  2.16 30.645 30.24 30.915 ;
     RECT  2.16 31.185 30.24 31.455 ;
     RECT  2.16 31.725 30.24 31.995 ;
     RECT  2.16 32.265 30.24 32.535 ;
     RECT  2.16 32.805 30.24 33.075 ;
     RECT  2.16 33.345 30.24 33.615 ;
     RECT  2.16 33.885 30.24 34.155 ;
     RECT  2.16 34.425 30.24 34.695 ;
     RECT  2.16 34.965 30.24 35.235 ;
     RECT  2.16 35.505 30.24 35.775 ;
     RECT  2.16 36.045 30.24 36.315 ;
     RECT  2.16 36.585 30.24 36.855 ;
     RECT  2.16 37.125 30.24 37.395 ;
     RECT  2.16 37.665 30.24 37.935 ;
     RECT  2.16 38.205 30.24 38.475 ;
     RECT  2.16 38.745 30.24 39.015 ;
     RECT  2.16 39.285 30.24 39.555 ;
     RECT  2.16 39.825 30.24 40.095 ;
     RECT  2.16 40.365 30.24 40.635 ;
     RECT  2.16 40.905 30.24 41.175 ;
     RECT  2.16 41.445 30.24 41.715 ;
     RECT  2.16 41.985 30.24 42.255 ;
     RECT  2.16 42.525 30.24 42.795 ;
     RECT  2.16 43.065 30.24 43.335 ;
     RECT  2.16 43.605 30.24 43.875 ;
     RECT  2.16 44.145 30.24 44.415 ;
     RECT  2.16 44.685 30.24 44.955 ;
     RECT  2.16 45.225 30.24 45.495 ;
     RECT  2.16 45.765 30.24 46.035 ;
     RECT  2.16 46.305 30.24 46.575 ;
     RECT  2.16 46.845 30.24 47.115 ;
     RECT  2.16 47.385 30.24 47.655 ;
     RECT  2.16 47.925 30.24 48.195 ;
     RECT  2.16 48.465 30.24 48.735 ;
     RECT  2.16 49.005 30.24 49.275 ;
     RECT  2.16 49.545 30.24 49.815 ;
     RECT  2.16 50.085 30.24 50.355 ;
     RECT  2.16 50.625 30.24 50.895 ;
     RECT  2.16 51.165 30.24 51.435 ;
     RECT  2.16 51.705 30.24 51.975 ;
     RECT  2.16 52.245 30.24 52.515 ;
     RECT  2.16 52.785 30.24 53.055 ;
     RECT  2.16 53.325 30.24 53.595 ;
     RECT  2.16 53.865 30.24 54.135 ;
     RECT  2.16 54.405 30.24 54.675 ;
     RECT  2.16 54.945 30.24 55.215 ;
     RECT  2.16 55.485 30.24 55.755 ;
     RECT  2.16 56.025 30.24 56.295 ;
     RECT  2.16 56.565 30.24 56.835 ;
     RECT  2.16 57.105 30.24 57.375 ;
     RECT  2.16 57.645 30.24 57.915 ;
     RECT  2.16 58.185 30.24 58.455 ;
     RECT  2.16 58.725 30.24 58.995 ;
     RECT  2.16 59.265 30.24 59.535 ;
     RECT  2.16 59.805 30.24 60.075 ;
     RECT  2.16 60.345 30.24 60.615 ;
     RECT  2.16 60.885 30.24 61.155 ;
     RECT  2.16 61.425 30.24 61.695 ;
     RECT  2.16 61.965 30.24 62.235 ;
     RECT  2.16 62.505 30.24 62.775 ;
     RECT  2.16 63.045 30.24 63.315 ;
     RECT  2.16 63.585 30.24 63.855 ;
     RECT  2.16 64.125 30.24 64.395 ;
     RECT  2.16 64.665 30.24 64.935 ;
     RECT  2.16 65.205 30.24 65.475 ;
     RECT  2.16 65.745 30.24 66.015 ;
     RECT  2.16 66.285 30.24 66.555 ;
     RECT  2.16 66.825 30.24 67.095 ;
     RECT  2.16 67.365 30.24 67.635 ;
     RECT  2.16 67.905 30.24 68.175 ;
     RECT  2.16 68.445 30.24 68.715 ;
     RECT  2.16 68.985 30.24 69.255 ;
     RECT  2.16 69.525 30.24 69.795 ;
     RECT  2.16 70.065 30.24 70.335 ;
     RECT  2.16 70.605 30.24 70.875 ;
     RECT  2.16 71.145 30.24 71.415 ;
     RECT  2.16 71.685 30.24 71.955 ;
     RECT  2.16 72.225 30.24 72.495 ;
     RECT  2.16 72.765 30.24 73.035 ;
     RECT  2.16 73.305 30.24 73.575 ;
     RECT  2.16 73.845 30.24 74.115 ;
     RECT  2.16 74.385 30.24 74.655 ;
     RECT  2.16 74.925 30.24 75.195 ;
     RECT  2.16 75.465 30.24 75.735 ;
     RECT  2.16 76.005 30.24 76.275 ;
     RECT  2.16 76.545 30.24 76.815 ;
     RECT  2.16 77.085 30.24 77.355 ;
     RECT  2.16 77.625 30.24 77.895 ;
     RECT  2.16 78.165 30.24 78.435 ;
     RECT  2.16 78.705 30.24 78.975 ;
     RECT  2.16 79.245 30.24 79.515 ;
     RECT  2.16 79.785 30.24 80.055 ;
     RECT  2.16 80.325 30.24 80.595 ;
     RECT  2.16 80.865 30.24 81.135 ;
     RECT  2.16 81.405 30.24 81.675 ;
     RECT  2.16 81.945 30.24 82.215 ;
     RECT  2.16 82.485 30.24 82.755 ;
     RECT  2.16 83.025 30.24 83.295 ;
     RECT  2.16 83.565 30.24 83.835 ;
     RECT  2.16 84.105 30.24 84.375 ;
     RECT  2.16 84.645 30.24 84.915 ;
     RECT  2.16 85.185 30.24 85.455 ;
     RECT  2.16 85.725 30.24 85.995 ;
     RECT  2.16 86.265 30.24 86.535 ;
     RECT  2.16 86.805 30.24 87.075 ;
     RECT  2.16 87.345 30.24 87.615 ;
     RECT  2.16 87.885 30.24 88.155 ;
     RECT  2.16 88.425 30.24 88.695 ;
     RECT  2.16 88.965 30.24 89.235 ;
     RECT  2.16 89.505 30.24 89.775 ;
     RECT  2.16 90.045 30.24 90.315 ;
     RECT  2.16 90.585 30.24 90.855 ;
     RECT  2.16 91.125 30.24 91.395 ;
     RECT  2.16 91.665 30.24 91.935 ;
     RECT  2.16 92.205 30.24 92.475 ;
     RECT  2.16 92.745 30.24 93.015 ;
     RECT  2.16 93.285 30.24 93.555 ;
     RECT  2.16 93.825 30.24 94.095 ;
     RECT  2.16 94.365 30.24 94.635 ;
     RECT  2.16 94.905 30.24 95.175 ;
     RECT  2.16 95.445 30.24 95.715 ;
     RECT  2.16 95.985 30.24 96.255 ;
     RECT  2.16 96.525 30.24 96.795 ;
     RECT  2.16 97.065 30.24 97.335 ;
     RECT  2.16 97.605 30.24 97.875 ;
     RECT  2.16 98.145 30.24 98.415 ;
     RECT  2.16 98.685 30.24 98.955 ;
     RECT  2.16 99.225 30.24 99.495 ;
     RECT  2.16 99.765 30.24 100.035 ;
     RECT  2.16 100.305 30.24 100.575 ;
     RECT  2.16 100.845 30.24 101.115 ;
     RECT  2.16 101.385 30.24 101.655 ;
     RECT  2.16 101.925 30.24 102.195 ;
     RECT  2.16 102.465 30.24 102.735 ;
     RECT  2.16 103.005 30.24 103.275 ;
     RECT  2.16 103.545 30.24 103.815 ;
     RECT  2.16 104.085 30.24 104.355 ;
     RECT  2.16 104.625 30.24 104.895 ;
     RECT  2.16 105.165 30.24 105.435 ;
     RECT  2.16 105.705 30.24 105.84 ;
    LAYER RVTP ;
     RECT  2.16 2.295 30.24 2.565 ;
     RECT  2.16 2.835 30.24 3.105 ;
     RECT  2.16 3.375 30.24 3.645 ;
     RECT  2.16 3.915 30.24 4.185 ;
     RECT  2.16 4.455 30.24 4.725 ;
     RECT  2.16 4.995 30.24 5.265 ;
     RECT  2.16 5.535 30.24 5.805 ;
     RECT  2.16 6.075 30.24 6.345 ;
     RECT  2.16 6.615 30.24 6.885 ;
     RECT  2.16 7.155 30.24 7.425 ;
     RECT  2.16 7.695 30.24 7.965 ;
     RECT  2.16 8.235 30.24 8.505 ;
     RECT  2.16 8.775 30.24 9.045 ;
     RECT  2.16 9.315 30.24 9.585 ;
     RECT  2.16 9.855 30.24 10.125 ;
     RECT  2.16 10.395 30.24 10.665 ;
     RECT  2.16 10.935 30.24 11.205 ;
     RECT  2.16 11.475 30.24 11.745 ;
     RECT  2.16 12.015 30.24 12.285 ;
     RECT  2.16 12.555 30.24 12.825 ;
     RECT  2.16 13.095 30.24 13.365 ;
     RECT  2.16 13.635 30.24 13.905 ;
     RECT  2.16 14.175 30.24 14.445 ;
     RECT  2.16 14.715 30.24 14.985 ;
     RECT  2.16 15.255 30.24 15.525 ;
     RECT  2.16 15.795 30.24 16.065 ;
     RECT  2.16 16.335 30.24 16.605 ;
     RECT  2.16 16.875 30.24 17.145 ;
     RECT  2.16 17.415 30.24 17.685 ;
     RECT  2.16 17.955 30.24 18.225 ;
     RECT  2.16 18.495 30.24 18.765 ;
     RECT  2.16 19.035 30.24 19.305 ;
     RECT  2.16 19.575 30.24 19.845 ;
     RECT  2.16 20.115 30.24 20.385 ;
     RECT  2.16 20.655 30.24 20.925 ;
     RECT  2.16 21.195 30.24 21.465 ;
     RECT  2.16 21.735 30.24 22.005 ;
     RECT  2.16 22.275 30.24 22.545 ;
     RECT  2.16 22.815 30.24 23.085 ;
     RECT  2.16 23.355 30.24 23.625 ;
     RECT  2.16 23.895 30.24 24.165 ;
     RECT  2.16 24.435 30.24 24.705 ;
     RECT  2.16 24.975 30.24 25.245 ;
     RECT  2.16 25.515 30.24 25.785 ;
     RECT  2.16 26.055 30.24 26.325 ;
     RECT  2.16 26.595 30.24 26.865 ;
     RECT  2.16 27.135 30.24 27.405 ;
     RECT  2.16 27.675 30.24 27.945 ;
     RECT  2.16 28.215 30.24 28.485 ;
     RECT  2.16 28.755 30.24 29.025 ;
     RECT  2.16 29.295 30.24 29.565 ;
     RECT  2.16 29.835 30.24 30.105 ;
     RECT  2.16 30.375 30.24 30.645 ;
     RECT  2.16 30.915 30.24 31.185 ;
     RECT  2.16 31.455 30.24 31.725 ;
     RECT  2.16 31.995 30.24 32.265 ;
     RECT  2.16 32.535 30.24 32.805 ;
     RECT  2.16 33.075 30.24 33.345 ;
     RECT  2.16 33.615 30.24 33.885 ;
     RECT  2.16 34.155 30.24 34.425 ;
     RECT  2.16 34.695 30.24 34.965 ;
     RECT  2.16 35.235 30.24 35.505 ;
     RECT  2.16 35.775 30.24 36.045 ;
     RECT  2.16 36.315 30.24 36.585 ;
     RECT  2.16 36.855 30.24 37.125 ;
     RECT  2.16 37.395 30.24 37.665 ;
     RECT  2.16 37.935 30.24 38.205 ;
     RECT  2.16 38.475 30.24 38.745 ;
     RECT  2.16 39.015 30.24 39.285 ;
     RECT  2.16 39.555 30.24 39.825 ;
     RECT  2.16 40.095 30.24 40.365 ;
     RECT  2.16 40.635 30.24 40.905 ;
     RECT  2.16 41.175 30.24 41.445 ;
     RECT  2.16 41.715 30.24 41.985 ;
     RECT  2.16 42.255 30.24 42.525 ;
     RECT  2.16 42.795 30.24 43.065 ;
     RECT  2.16 43.335 30.24 43.605 ;
     RECT  2.16 43.875 30.24 44.145 ;
     RECT  2.16 44.415 30.24 44.685 ;
     RECT  2.16 44.955 30.24 45.225 ;
     RECT  2.16 45.495 30.24 45.765 ;
     RECT  2.16 46.035 30.24 46.305 ;
     RECT  2.16 46.575 30.24 46.845 ;
     RECT  2.16 47.115 30.24 47.385 ;
     RECT  2.16 47.655 30.24 47.925 ;
     RECT  2.16 48.195 30.24 48.465 ;
     RECT  2.16 48.735 30.24 49.005 ;
     RECT  2.16 49.275 30.24 49.545 ;
     RECT  2.16 49.815 30.24 50.085 ;
     RECT  2.16 50.355 30.24 50.625 ;
     RECT  2.16 50.895 30.24 51.165 ;
     RECT  2.16 51.435 30.24 51.705 ;
     RECT  2.16 51.975 30.24 52.245 ;
     RECT  2.16 52.515 30.24 52.785 ;
     RECT  2.16 53.055 30.24 53.325 ;
     RECT  2.16 53.595 30.24 53.865 ;
     RECT  2.16 54.135 30.24 54.405 ;
     RECT  2.16 54.675 30.24 54.945 ;
     RECT  2.16 55.215 30.24 55.485 ;
     RECT  2.16 55.755 30.24 56.025 ;
     RECT  2.16 56.295 30.24 56.565 ;
     RECT  2.16 56.835 30.24 57.105 ;
     RECT  2.16 57.375 30.24 57.645 ;
     RECT  2.16 57.915 30.24 58.185 ;
     RECT  2.16 58.455 30.24 58.725 ;
     RECT  2.16 58.995 30.24 59.265 ;
     RECT  2.16 59.535 30.24 59.805 ;
     RECT  2.16 60.075 30.24 60.345 ;
     RECT  2.16 60.615 30.24 60.885 ;
     RECT  2.16 61.155 30.24 61.425 ;
     RECT  2.16 61.695 30.24 61.965 ;
     RECT  2.16 62.235 30.24 62.505 ;
     RECT  2.16 62.775 30.24 63.045 ;
     RECT  2.16 63.315 30.24 63.585 ;
     RECT  2.16 63.855 30.24 64.125 ;
     RECT  2.16 64.395 30.24 64.665 ;
     RECT  2.16 64.935 30.24 65.205 ;
     RECT  2.16 65.475 30.24 65.745 ;
     RECT  2.16 66.015 30.24 66.285 ;
     RECT  2.16 66.555 30.24 66.825 ;
     RECT  2.16 67.095 30.24 67.365 ;
     RECT  2.16 67.635 30.24 67.905 ;
     RECT  2.16 68.175 30.24 68.445 ;
     RECT  2.16 68.715 30.24 68.985 ;
     RECT  2.16 69.255 30.24 69.525 ;
     RECT  2.16 69.795 30.24 70.065 ;
     RECT  2.16 70.335 30.24 70.605 ;
     RECT  2.16 70.875 30.24 71.145 ;
     RECT  2.16 71.415 30.24 71.685 ;
     RECT  2.16 71.955 30.24 72.225 ;
     RECT  2.16 72.495 30.24 72.765 ;
     RECT  2.16 73.035 30.24 73.305 ;
     RECT  2.16 73.575 30.24 73.845 ;
     RECT  2.16 74.115 30.24 74.385 ;
     RECT  2.16 74.655 30.24 74.925 ;
     RECT  2.16 75.195 30.24 75.465 ;
     RECT  2.16 75.735 30.24 76.005 ;
     RECT  2.16 76.275 30.24 76.545 ;
     RECT  2.16 76.815 30.24 77.085 ;
     RECT  2.16 77.355 30.24 77.625 ;
     RECT  2.16 77.895 30.24 78.165 ;
     RECT  2.16 78.435 30.24 78.705 ;
     RECT  2.16 78.975 30.24 79.245 ;
     RECT  2.16 79.515 30.24 79.785 ;
     RECT  2.16 80.055 30.24 80.325 ;
     RECT  2.16 80.595 30.24 80.865 ;
     RECT  2.16 81.135 30.24 81.405 ;
     RECT  2.16 81.675 30.24 81.945 ;
     RECT  2.16 82.215 30.24 82.485 ;
     RECT  2.16 82.755 30.24 83.025 ;
     RECT  2.16 83.295 30.24 83.565 ;
     RECT  2.16 83.835 30.24 84.105 ;
     RECT  2.16 84.375 30.24 84.645 ;
     RECT  2.16 84.915 30.24 85.185 ;
     RECT  2.16 85.455 30.24 85.725 ;
     RECT  2.16 85.995 30.24 86.265 ;
     RECT  2.16 86.535 30.24 86.805 ;
     RECT  2.16 87.075 30.24 87.345 ;
     RECT  2.16 87.615 30.24 87.885 ;
     RECT  2.16 88.155 30.24 88.425 ;
     RECT  2.16 88.695 30.24 88.965 ;
     RECT  2.16 89.235 30.24 89.505 ;
     RECT  2.16 89.775 30.24 90.045 ;
     RECT  2.16 90.315 30.24 90.585 ;
     RECT  2.16 90.855 30.24 91.125 ;
     RECT  2.16 91.395 30.24 91.665 ;
     RECT  2.16 91.935 30.24 92.205 ;
     RECT  2.16 92.475 30.24 92.745 ;
     RECT  2.16 93.015 30.24 93.285 ;
     RECT  2.16 93.555 30.24 93.825 ;
     RECT  2.16 94.095 30.24 94.365 ;
     RECT  2.16 94.635 30.24 94.905 ;
     RECT  2.16 95.175 30.24 95.445 ;
     RECT  2.16 95.715 30.24 95.985 ;
     RECT  2.16 96.255 30.24 96.525 ;
     RECT  2.16 96.795 30.24 97.065 ;
     RECT  2.16 97.335 30.24 97.605 ;
     RECT  2.16 97.875 30.24 98.145 ;
     RECT  2.16 98.415 30.24 98.685 ;
     RECT  2.16 98.955 30.24 99.225 ;
     RECT  2.16 99.495 30.24 99.765 ;
     RECT  2.16 100.035 30.24 100.305 ;
     RECT  2.16 100.575 30.24 100.845 ;
     RECT  2.16 101.115 30.24 101.385 ;
     RECT  2.16 101.655 30.24 101.925 ;
     RECT  2.16 102.195 30.24 102.465 ;
     RECT  2.16 102.735 30.24 103.005 ;
     RECT  2.16 103.275 30.24 103.545 ;
     RECT  2.16 103.815 30.24 104.085 ;
     RECT  2.16 104.355 30.24 104.625 ;
     RECT  2.16 104.895 30.24 105.165 ;
     RECT  2.16 105.435 30.24 105.705 ;
    LAYER M1 ;
     RECT  2.16 2.151 30.24 105.849 ;
    LAYER M2 ;
     RECT  0.031 10.836 0.131 10.854 ;
     RECT  0.031 95.724 0.131 95.742 ;
     RECT  0.175 12.294 0.211 12.312 ;
     RECT  0.103 14.796 0.211 14.814 ;
     RECT  0.103 39.096 0.239 39.114 ;
     RECT  0.139 11.214 0.283 11.394 ;
     RECT  0.211 12.294 0.283 12.546 ;
     RECT  0.463 22.626 0.499 22.644 ;
     RECT  0.499 22.518 0.535 22.644 ;
     RECT  0.499 24.48 0.535 24.498 ;
     RECT  0.499 52.416 0.535 53.154 ;
     RECT  0.499 57.726 0.535 57.744 ;
     RECT  0.103 72.54 0.535 72.558 ;
     RECT  0.535 63.396 1.147 63.414 ;
     RECT  0.535 22.014 1.175 23.148 ;
     RECT  0.535 51.246 1.175 53.856 ;
     RECT  1.147 63.324 1.175 63.414 ;
     RECT  0.283 11.214 1.435 12.546 ;
     RECT  1.399 99.576 1.723 99.594 ;
     RECT  1.759 98.496 1.795 98.514 ;
     RECT  1.795 98.46 1.831 98.514 ;
     RECT  1.831 98.226 2.155 98.514 ;
     RECT  1.723 99.306 2.155 99.594 ;
     RECT  0.031 9.936 2.16 9.954 ;
     RECT  1.435 10.746 2.16 12.546 ;
     RECT  0.499 13.644 2.16 13.662 ;
     RECT  0.211 14.454 2.16 14.814 ;
     RECT  0.103 15.876 2.16 15.894 ;
     RECT  1.175 22.014 2.16 22.914 ;
     RECT  0.535 23.904 2.16 25.614 ;
     RECT  0.535 27.144 2.16 27.162 ;
     RECT  0.535 31.806 2.16 31.824 ;
     RECT  0.535 35.244 2.16 35.262 ;
     RECT  1.147 49.896 2.16 49.914 ;
     RECT  1.175 51.246 2.16 51.264 ;
     RECT  1.175 52.056 2.16 53.856 ;
     RECT  0.535 55.224 2.16 55.242 ;
     RECT  0.535 57.384 2.16 57.744 ;
     RECT  1.175 63.324 2.16 63.342 ;
     RECT  0.535 68.256 2.16 68.274 ;
     RECT  0.535 69.498 2.16 69.516 ;
     RECT  0.535 72.126 2.16 72.558 ;
     RECT  0.175 79.596 2.16 79.614 ;
     RECT  0.535 80.874 2.16 81.774 ;
     RECT  0.535 82.764 2.16 82.782 ;
     RECT  0.535 85.194 2.16 85.212 ;
     RECT  0.103 88.866 2.16 88.884 ;
     RECT  0.103 92.286 2.16 92.304 ;
     RECT  0.535 93.834 2.16 93.852 ;
     RECT  0.211 94.608 2.16 94.626 ;
     RECT  2.155 98.226 2.16 99.594 ;
     RECT  0.031 101.736 2.16 101.754 ;
     RECT  2.16 2.151 30.24 105.849 ;
     RECT  30.24 29.772 30.659 33.336 ;
     RECT  30.24 10.062 30.767 28.71 ;
     RECT  30.24 34.128 30.767 57.06 ;
     RECT  30.24 58.122 30.767 86.49 ;
     RECT  30.24 87.282 30.767 96.786 ;
     RECT  30.767 10.062 30.803 24.39 ;
     RECT  30.767 25.452 30.803 28.71 ;
     RECT  30.767 34.362 30.803 39.276 ;
     RECT  30.767 45.162 30.803 53.82 ;
     RECT  30.767 58.122 30.803 68.94 ;
     RECT  30.767 70.074 30.803 84.06 ;
     RECT  30.767 87.282 30.803 92.196 ;
     RECT  30.803 45.432 30.839 53.82 ;
     RECT  30.803 70.074 30.839 82.71 ;
     RECT  30.803 87.282 30.839 91.89 ;
     RECT  30.803 15.57 31.307 18.99 ;
     RECT  30.803 19.782 31.307 24.39 ;
     RECT  30.803 36.63 31.307 39.276 ;
     RECT  30.767 40.068 31.307 44.37 ;
     RECT  30.839 45.432 31.307 52.812 ;
     RECT  30.767 54.756 31.307 57.06 ;
     RECT  30.803 58.122 31.307 59.49 ;
     RECT  30.803 60.282 31.307 63.576 ;
     RECT  30.803 67.068 31.307 68.94 ;
     RECT  30.767 93.258 31.307 94.86 ;
     RECT  30.803 10.062 31.343 14.67 ;
     RECT  31.307 15.57 31.343 16.02 ;
     RECT  31.307 16.812 31.343 16.83 ;
     RECT  31.307 17.694 31.343 18.72 ;
     RECT  31.307 19.782 31.343 21.42 ;
     RECT  31.307 22.212 31.343 24.39 ;
     RECT  30.803 26.334 31.343 28.71 ;
     RECT  30.659 29.772 31.343 33.3 ;
     RECT  30.803 34.362 31.343 35.73 ;
     RECT  31.307 36.63 31.343 38.196 ;
     RECT  31.307 38.988 31.343 39.078 ;
     RECT  31.307 40.068 31.343 40.896 ;
     RECT  31.307 41.688 31.343 44.37 ;
     RECT  31.307 45.432 31.343 49.572 ;
     RECT  31.307 50.328 31.343 52.812 ;
     RECT  31.307 54.756 31.343 54.9 ;
     RECT  31.307 55.692 31.343 56.79 ;
     RECT  31.307 58.122 31.343 59.22 ;
     RECT  31.307 60.282 31.343 60.3 ;
     RECT  31.307 61.128 31.343 61.146 ;
     RECT  31.307 61.902 31.343 62.532 ;
     RECT  31.307 63.324 31.343 63.576 ;
     RECT  30.803 64.674 31.343 66.24 ;
     RECT  31.307 67.068 31.343 68.13 ;
     RECT  30.839 70.074 31.343 79.272 ;
     RECT  30.839 80.028 31.343 82.71 ;
     RECT  30.803 84.042 31.343 84.06 ;
     RECT  30.767 84.888 31.343 86.49 ;
     RECT  30.839 87.282 31.343 91.08 ;
     RECT  30.839 91.872 31.343 91.89 ;
     RECT  31.307 93.6 31.343 94.86 ;
     RECT  31.343 11.826 31.379 12.114 ;
     RECT  31.343 17.694 31.379 17.712 ;
     RECT  31.343 39.06 31.379 39.078 ;
     RECT  31.343 46.584 31.379 48.384 ;
     RECT  31.343 54.756 31.379 54.774 ;
     RECT  31.343 58.122 31.379 58.14 ;
     RECT  31.343 63.324 31.379 63.342 ;
     RECT  31.307 68.922 31.379 68.94 ;
     RECT  31.343 70.578 31.379 70.596 ;
     RECT  30.767 95.652 31.379 95.976 ;
     RECT  31.379 46.584 31.415 47.646 ;
     RECT  31.343 28.026 32.279 28.71 ;
     RECT  31.343 51.714 32.279 51.768 ;
     RECT  31.343 52.56 32.279 52.812 ;
     RECT  31.343 64.674 32.279 65.7 ;
     RECT  31.343 67.068 32.279 67.32 ;
     RECT  31.343 90.018 32.279 90.144 ;
     RECT  31.343 93.798 32.279 94.194 ;
     RECT  31.379 11.826 32.315 11.844 ;
     RECT  31.343 26.334 32.315 26.82 ;
     RECT  32.279 28.026 32.315 28.044 ;
     RECT  31.343 30.384 32.315 30.402 ;
     RECT  31.343 36.63 32.315 37.224 ;
     RECT  31.343 41.688 32.315 42.012 ;
     RECT  31.415 46.584 32.315 47.106 ;
     RECT  31.343 50.868 32.315 50.886 ;
     RECT  32.279 51.714 32.315 51.732 ;
     RECT  32.279 52.794 32.315 52.812 ;
     RECT  32.279 64.674 32.315 64.692 ;
     RECT  32.279 65.682 32.315 65.7 ;
     RECT  32.279 67.068 32.315 67.086 ;
     RECT  31.343 72.576 32.315 72.792 ;
     RECT  31.343 78.372 32.315 79.272 ;
     RECT  31.343 81.954 32.315 82.71 ;
     RECT  31.343 86.472 32.315 86.49 ;
     RECT  31.343 88.398 32.315 88.416 ;
     RECT  32.279 90.018 32.315 90.036 ;
     RECT  32.279 93.798 32.315 93.816 ;
     RECT  31.379 95.958 32.315 95.976 ;
     RECT  30.767 96.768 32.315 96.786 ;
    LAYER M3 ;
     RECT  29.34 1.723 29.358 2.143 ;
     RECT  2.415 2.143 2.505 2.413 ;
     RECT  5.115 2.143 5.205 2.413 ;
     RECT  7.815 2.143 7.905 2.413 ;
     RECT  10.515 2.143 10.605 2.413 ;
     RECT  13.215 2.143 13.305 2.413 ;
     RECT  15.915 2.143 16.005 2.413 ;
     RECT  18.615 2.143 18.705 2.413 ;
     RECT  21.315 2.143 21.405 2.413 ;
     RECT  24.015 2.143 24.105 2.413 ;
     RECT  26.715 2.143 26.805 2.413 ;
     RECT  29.34 2.143 29.505 2.413 ;
     RECT  29.34 2.413 29.697 2.525 ;
     RECT  29.415 2.525 29.697 5.071 ;
     RECT  29.088 5.071 29.697 7.385 ;
     RECT  28.332 8.671 28.35 8.815 ;
     RECT  26.715 2.413 26.997 8.851 ;
     RECT  28.296 8.815 28.35 8.851 ;
     RECT  29.16 7.385 29.697 8.851 ;
     RECT  26.715 8.851 27.45 8.941 ;
     RECT  28.296 8.851 29.697 8.941 ;
     RECT  26.715 8.941 29.697 8.977 ;
     RECT  26.496 8.977 29.697 9.293 ;
     RECT  2.415 2.413 2.697 9.625 ;
     RECT  2.415 9.625 2.79 9.661 ;
     RECT  26.64 9.293 29.697 9.815 ;
     RECT  2.415 9.661 2.934 9.895 ;
     RECT  2.376 9.895 2.934 10.057 ;
     RECT  26.715 9.815 29.697 10.075 ;
     RECT  26.715 10.075 29.826 10.157 ;
     RECT  31.32 9.931 31.338 10.219 ;
     RECT  30.744 10.219 31.338 10.355 ;
     RECT  2.376 10.057 3.618 10.669 ;
     RECT  24.015 2.413 24.297 10.705 ;
     RECT  25.056 10.471 25.722 10.705 ;
     RECT  24.015 10.705 25.722 10.733 ;
     RECT  0.036 9.931 0.054 10.831 ;
     RECT  0.036 10.831 0.126 10.859 ;
     RECT  1.44 10.741 1.458 11.011 ;
     RECT  2.304 10.669 3.618 11.011 ;
     RECT  26.715 10.157 29.697 11.083 ;
     RECT  1.44 11.011 3.618 11.137 ;
     RECT  0.108 10.859 0.126 11.209 ;
     RECT  31.284 10.355 31.338 11.227 ;
     RECT  0.108 11.209 0.522 11.281 ;
     RECT  1.44 11.137 3.978 11.281 ;
     RECT  26.715 11.083 30.222 11.641 ;
     RECT  31.248 11.227 31.338 11.641 ;
     RECT  5.115 2.413 5.397 11.749 ;
     RECT  13.215 2.413 13.497 11.749 ;
     RECT  14.544 10.903 14.562 11.749 ;
     RECT  22.824 11.209 22.842 11.821 ;
     RECT  24.015 10.733 24.858 11.821 ;
     RECT  25.668 10.733 25.722 11.821 ;
     RECT  32.292 11.803 32.31 11.849 ;
     RECT  0.108 11.281 3.978 11.983 ;
     RECT  5.115 11.749 6.75 11.983 ;
     RECT  26.568 11.641 31.338 12.047 ;
     RECT  0.108 11.983 4.05 12.055 ;
     RECT  5.115 11.983 6.786 12.091 ;
     RECT  7.815 2.413 8.097 12.091 ;
     RECT  26.568 12.047 29.754 12.091 ;
     RECT  30.744 12.047 31.338 12.091 ;
     RECT  0.108 12.055 4.23 12.125 ;
     RECT  1.152 12.125 4.23 12.181 ;
     RECT  5.115 12.091 8.097 12.181 ;
     RECT  22.824 11.821 25.722 12.181 ;
     RECT  26.496 12.091 29.754 12.181 ;
     RECT  1.152 12.181 8.19 12.361 ;
     RECT  30.744 12.091 31.374 12.413 ;
     RECT  22.824 12.181 29.754 12.523 ;
     RECT  12.24 11.209 12.258 12.559 ;
     RECT  1.152 12.361 8.838 12.631 ;
     RECT  1.152 12.631 9.486 12.749 ;
     RECT  22.68 12.523 29.754 12.901 ;
     RECT  1.152 12.749 3.654 13.019 ;
     RECT  4.932 12.749 9.486 13.019 ;
     RECT  5.004 13.019 9.486 13.091 ;
     RECT  10.515 2.413 10.797 13.171 ;
     RECT  11.736 12.559 12.258 13.261 ;
     RECT  0.108 12.125 0.306 13.277 ;
     RECT  10.296 13.171 10.797 13.441 ;
     RECT  22.608 12.901 29.79 13.441 ;
     RECT  1.152 13.019 3.618 13.565 ;
     RECT  0.144 13.277 0.306 13.639 ;
     RECT  1.152 13.565 1.458 13.639 ;
     RECT  22.608 13.441 29.826 13.639 ;
     RECT  30.744 12.413 31.338 13.639 ;
     RECT  5.004 13.091 8.838 13.661 ;
     RECT  0.144 13.639 1.458 13.709 ;
     RECT  2.232 13.565 3.618 13.801 ;
     RECT  5.004 13.661 5.526 13.801 ;
     RECT  6.444 13.661 8.838 13.909 ;
     RECT  9.612 13.441 10.797 13.909 ;
     RECT  22.608 13.639 31.338 13.937 ;
     RECT  6.444 13.909 10.797 13.981 ;
     RECT  18.615 2.413 18.897 13.981 ;
     RECT  30.744 13.937 31.338 14.171 ;
     RECT  2.232 13.801 5.526 14.485 ;
     RECT  6.444 13.981 10.818 14.485 ;
     RECT  2.232 14.485 10.818 14.521 ;
     RECT  11.664 13.261 12.258 14.521 ;
     RECT  0.144 13.709 1.206 14.573 ;
     RECT  2.232 14.521 12.258 14.675 ;
     RECT  31.284 14.171 31.338 14.675 ;
     RECT  0.144 14.573 0.522 14.717 ;
     RECT  0.144 14.717 0.234 14.791 ;
     RECT  22.608 13.937 30.006 14.827 ;
     RECT  22.608 14.827 30.222 14.917 ;
     RECT  20.232 13.909 20.25 14.989 ;
     RECT  0.108 14.791 0.234 15.005 ;
     RECT  0.108 15.005 0.126 15.149 ;
     RECT  22.608 14.917 30.798 15.215 ;
     RECT  13.215 11.749 14.562 15.223 ;
     RECT  22.608 15.215 30.222 15.223 ;
     RECT  2.232 14.675 7.038 15.421 ;
     RECT  2.232 15.421 7.074 15.449 ;
     RECT  2.268 15.449 7.074 15.5 ;
     RECT  2.304 15.5 7.074 15.601 ;
     RECT  7.815 14.675 12.258 15.601 ;
     RECT  13.215 15.223 14.634 15.601 ;
     RECT  13.215 15.601 14.85 15.719 ;
     RECT  16.92 14.683 16.938 15.727 ;
     RECT  17.964 13.981 18.897 15.727 ;
     RECT  20.196 14.989 20.25 15.871 ;
     RECT  0.108 15.871 0.126 16.027 ;
     RECT  19.692 15.871 20.25 16.069 ;
     RECT  22.5 15.223 30.222 16.097 ;
     RECT  31.284 15.403 31.338 16.123 ;
     RECT  0.108 16.027 0.162 16.157 ;
     RECT  0.108 16.157 0.126 16.301 ;
     RECT  19.692 16.069 20.286 16.303 ;
     RECT  21.315 2.413 21.597 16.303 ;
     RECT  16.92 15.727 18.897 16.375 ;
     RECT  19.692 16.303 21.597 16.375 ;
     RECT  15.915 2.413 16.197 16.411 ;
     RECT  16.92 16.375 21.597 16.411 ;
     RECT  15.915 16.411 21.597 16.807 ;
     RECT  22.5 16.097 29.826 16.807 ;
     RECT  13.215 15.719 14.634 16.951 ;
     RECT  15.915 16.807 29.826 16.951 ;
     RECT  30.708 16.123 31.338 16.951 ;
     RECT  15.915 16.951 31.338 17.069 ;
     RECT  0.144 16.987 0.162 17.405 ;
     RECT  15.915 17.069 29.826 17.645 ;
     RECT  30.744 17.069 31.338 17.689 ;
     RECT  2.304 15.601 12.258 17.851 ;
     RECT  30.744 17.689 31.374 17.885 ;
     RECT  2.268 17.851 12.258 18.329 ;
     RECT  15.915 17.645 29.718 18.535 ;
     RECT  15.915 18.535 29.934 18.689 ;
     RECT  30.744 17.885 31.338 18.725 ;
     RECT  30.744 18.725 31.302 18.995 ;
     RECT  13.215 16.951 15.102 19.003 ;
     RECT  15.915 18.689 29.79 19.003 ;
     RECT  30.744 18.995 30.798 19.325 ;
     RECT  13.215 19.003 29.79 19.579 ;
     RECT  2.304 18.329 12.258 19.849 ;
     RECT  13.215 19.579 30.258 19.849 ;
     RECT  0.144 19.723 0.162 20.141 ;
     RECT  31.32 19.723 31.338 20.281 ;
     RECT  31.284 20.281 31.338 20.333 ;
     RECT  2.304 19.849 30.258 20.417 ;
     RECT  2.304 20.417 30.114 20.443 ;
     RECT  2.268 20.443 30.114 20.489 ;
     RECT  2.304 20.489 30.114 21.157 ;
     RECT  31.32 20.333 31.338 21.157 ;
     RECT  2.304 21.157 31.338 21.197 ;
     RECT  31.284 21.197 31.338 21.425 ;
     RECT  31.284 21.425 31.302 21.695 ;
     RECT  2.304 21.197 30.222 21.811 ;
     RECT  2.268 21.811 30.222 22.199 ;
     RECT  2.268 22.199 29.826 22.205 ;
     RECT  2.34 22.205 29.826 22.235 ;
     RECT  31.32 22.171 31.338 22.459 ;
     RECT  0.54 22.009 0.558 22.513 ;
     RECT  30.636 22.459 31.338 22.541 ;
     RECT  0.504 22.513 0.558 22.549 ;
     RECT  0.504 22.549 1.17 22.603 ;
     RECT  0.504 22.603 1.278 22.621 ;
     RECT  0.468 22.621 1.278 22.781 ;
     RECT  30.708 22.541 31.338 22.811 ;
     RECT  2.34 22.235 29.697 23.053 ;
     RECT  2.34 23.053 29.718 23.083 ;
     RECT  2.304 23.083 29.718 23.089 ;
     RECT  0.468 22.781 1.17 23.153 ;
     RECT  2.304 23.089 29.754 23.851 ;
     RECT  2.268 23.851 29.754 23.863 ;
     RECT  0.468 23.153 0.558 23.933 ;
     RECT  2.268 23.863 29.79 24.365 ;
     RECT  30.744 22.811 31.338 24.395 ;
     RECT  2.304 24.365 29.79 24.619 ;
     RECT  30.744 24.395 30.762 24.619 ;
     RECT  0.504 23.933 0.558 24.667 ;
     RECT  0.504 24.667 1.17 25.085 ;
     RECT  2.304 24.619 30.762 25.277 ;
     RECT  0.504 25.085 0.558 25.339 ;
     RECT  30.672 25.277 30.762 25.447 ;
     RECT  0.144 25.339 0.558 25.469 ;
     RECT  2.304 25.277 29.826 25.709 ;
     RECT  30.672 25.447 30.798 25.745 ;
     RECT  0.54 25.469 0.558 25.949 ;
     RECT  30.744 25.745 30.798 26.347 ;
     RECT  2.304 25.709 29.754 26.761 ;
     RECT  30.744 26.347 31.338 26.779 ;
     RECT  32.292 26.059 32.31 26.825 ;
     RECT  30.636 26.779 31.338 26.861 ;
     RECT  30.744 26.861 31.338 26.897 ;
     RECT  2.304 26.761 29.826 26.923 ;
     RECT  0.144 26.203 0.162 27.139 ;
     RECT  2.268 26.923 29.898 27.239 ;
     RECT  0.144 27.139 0.558 27.389 ;
     RECT  30.78 26.897 31.338 27.779 ;
     RECT  2.304 27.239 29.898 27.913 ;
     RECT  0.144 27.389 0.162 27.917 ;
     RECT  32.292 27.787 32.31 27.931 ;
     RECT  32.256 27.931 32.31 28.049 ;
     RECT  2.304 27.913 30.762 28.211 ;
     RECT  30.744 28.211 30.762 28.481 ;
     RECT  32.256 28.049 32.274 28.715 ;
     RECT  0.144 28.651 0.162 28.781 ;
     RECT  2.304 28.211 29.697 29.083 ;
     RECT  2.268 29.083 29.697 29.497 ;
     RECT  2.268 29.497 30.186 29.803 ;
     RECT  31.32 29.659 31.338 29.803 ;
     RECT  2.268 29.803 31.338 29.867 ;
     RECT  0.144 29.851 0.162 29.981 ;
     RECT  2.34 29.867 31.338 30.065 ;
     RECT  32.292 30.091 32.31 30.407 ;
     RECT  0.324 30.235 0.342 30.413 ;
     RECT  0.144 30.811 0.162 30.941 ;
     RECT  2.34 30.065 29.79 30.955 ;
     RECT  30.708 30.065 31.338 30.955 ;
     RECT  1.152 31.483 1.17 31.531 ;
     RECT  1.152 31.531 1.278 31.709 ;
     RECT  2.304 30.955 31.338 31.765 ;
     RECT  2.268 31.765 31.338 31.853 ;
     RECT  2.304 31.853 31.338 31.955 ;
     RECT  0.54 31.801 0.558 31.997 ;
     RECT  2.304 31.955 29.718 32.881 ;
     RECT  2.304 32.881 29.898 32.971 ;
     RECT  2.268 32.971 29.898 33.071 ;
     RECT  2.304 33.071 29.898 33.241 ;
     RECT  30.708 31.955 31.338 33.241 ;
     RECT  2.304 33.241 31.338 33.305 ;
     RECT  0.144 33.307 0.162 33.437 ;
     RECT  2.304 33.305 30.762 33.883 ;
     RECT  2.268 33.883 30.762 34.013 ;
     RECT  2.304 34.013 30.762 34.123 ;
     RECT  0.144 34.843 0.162 35.239 ;
     RECT  0.144 35.239 0.558 35.453 ;
     RECT  2.304 34.123 31.338 35.735 ;
     RECT  2.304 35.735 30.798 35.885 ;
     RECT  2.34 35.885 30.798 36.617 ;
     RECT  2.34 36.617 29.826 36.715 ;
     RECT  30.744 36.617 30.798 36.715 ;
     RECT  0.144 35.453 0.162 37.037 ;
     RECT  32.292 36.283 32.31 37.229 ;
     RECT  2.304 36.715 29.826 37.723 ;
     RECT  30.744 36.715 31.338 37.723 ;
     RECT  2.268 37.723 31.338 38.039 ;
     RECT  0.144 37.915 0.162 38.045 ;
     RECT  2.304 38.039 31.338 38.731 ;
     RECT  0.144 39.019 0.162 39.067 ;
     RECT  2.304 38.731 31.374 39.083 ;
     RECT  0.144 39.067 0.234 39.091 ;
     RECT  0.108 39.091 0.234 39.341 ;
     RECT  2.304 39.083 31.338 39.551 ;
     RECT  32.22 39.883 32.238 40.013 ;
     RECT  0.324 39.883 0.342 40.061 ;
     RECT  2.304 39.551 30.222 40.315 ;
     RECT  31.32 39.551 31.338 40.891 ;
     RECT  2.304 40.315 30.294 41.035 ;
     RECT  31.284 40.891 31.338 41.035 ;
     RECT  2.304 41.035 31.338 41.171 ;
     RECT  31.284 41.171 31.338 41.243 ;
     RECT  2.304 41.171 30.222 41.513 ;
     RECT  32.292 41.467 32.31 41.611 ;
     RECT  0.144 40.459 0.162 41.741 ;
     RECT  32.256 41.611 32.31 41.755 ;
     RECT  32.22 41.755 32.31 41.819 ;
     RECT  32.292 41.819 32.31 42.017 ;
     RECT  31.32 41.243 31.338 42.025 ;
     RECT  2.304 41.513 29.697 42.331 ;
     RECT  30.78 42.025 31.338 42.331 ;
     RECT  0.144 42.619 0.162 43.229 ;
     RECT  2.304 42.331 31.338 43.609 ;
     RECT  2.268 43.609 31.338 43.673 ;
     RECT  2.268 43.673 29.79 44.528 ;
     RECT  2.304 44.528 29.79 44.635 ;
     RECT  30.744 43.673 31.338 44.635 ;
     RECT  2.304 44.635 31.338 44.915 ;
     RECT  0.144 45.067 0.162 45.197 ;
     RECT  0.324 45.355 0.342 45.533 ;
     RECT  19.62 44.915 31.338 46.337 ;
     RECT  30.78 46.337 31.338 46.541 ;
     RECT  31.32 46.541 31.338 46.651 ;
     RECT  0.144 45.931 0.162 46.685 ;
     RECT  31.32 46.651 31.374 46.877 ;
     RECT  32.292 46.363 32.31 47.111 ;
     RECT  19.62 46.337 29.826 47.227 ;
     RECT  19.62 47.227 30.222 47.317 ;
     RECT  31.32 46.877 31.338 47.317 ;
     RECT  19.62 47.317 31.338 47.405 ;
     RECT  19.62 47.405 30.222 47.453 ;
     RECT  31.284 47.405 31.338 47.623 ;
     RECT  31.284 47.623 31.41 47.837 ;
     RECT  2.304 44.915 18.897 47.893 ;
     RECT  19.62 47.453 29.754 47.893 ;
     RECT  0.144 48.091 0.162 48.221 ;
     RECT  31.284 47.837 31.374 48.235 ;
     RECT  2.304 47.893 29.754 48.361 ;
     RECT  2.304 48.361 29.826 48.389 ;
     RECT  31.248 48.235 31.374 48.413 ;
     RECT  19.62 48.389 29.826 48.461 ;
     RECT  31.248 48.413 31.338 48.523 ;
     RECT  2.304 48.389 18.897 48.569 ;
     RECT  30.744 48.523 31.338 49.351 ;
     RECT  0.144 49.099 0.162 49.517 ;
     RECT  30.708 49.351 31.338 49.541 ;
     RECT  2.415 48.569 18.897 49.621 ;
     RECT  19.62 48.461 29.79 49.621 ;
     RECT  1.152 47.803 1.17 49.919 ;
     RECT  2.376 49.621 18.897 50.045 ;
     RECT  19.62 49.621 29.934 50.107 ;
     RECT  19.62 50.107 30.222 50.395 ;
     RECT  31.284 49.541 31.338 50.539 ;
     RECT  2.415 50.045 18.897 50.593 ;
     RECT  19.62 50.395 30.258 50.593 ;
     RECT  2.415 50.593 30.258 50.693 ;
     RECT  2.415 50.693 29.697 50.791 ;
     RECT  2.376 50.791 29.697 51.511 ;
     RECT  32.292 50.683 32.31 51.547 ;
     RECT  31.104 50.539 31.338 51.673 ;
     RECT  2.304 51.511 29.697 51.709 ;
     RECT  30.78 51.673 31.338 51.725 ;
     RECT  2.268 51.709 29.697 51.781 ;
     RECT  2.268 51.781 30.114 51.869 ;
     RECT  2.304 51.869 30.114 51.971 ;
     RECT  0.54 51.241 0.558 51.979 ;
     RECT  0.54 51.979 1.17 52.079 ;
     RECT  0.54 52.079 0.558 52.123 ;
     RECT  0.144 52.123 0.558 52.253 ;
     RECT  32.256 51.547 32.31 52.583 ;
     RECT  31.248 51.725 31.338 52.699 ;
     RECT  2.304 51.971 29.826 52.709 ;
     RECT  30.744 52.699 31.338 52.745 ;
     RECT  2.304 52.709 18.897 52.789 ;
     RECT  32.292 52.583 32.31 52.817 ;
     RECT  19.62 52.709 29.826 52.861 ;
     RECT  30.744 52.745 30.798 52.861 ;
     RECT  2.268 52.789 18.897 52.877 ;
     RECT  0.504 52.253 0.558 53.419 ;
     RECT  19.62 52.861 30.798 53.527 ;
     RECT  0.18 53.419 0.558 53.707 ;
     RECT  2.304 52.877 18.897 53.761 ;
     RECT  19.62 53.527 30.834 53.761 ;
     RECT  0.18 53.707 1.17 53.837 ;
     RECT  2.304 53.761 30.834 53.885 ;
     RECT  0.18 53.837 0.558 53.899 ;
     RECT  2.304 53.885 30.762 54.059 ;
     RECT  0.144 53.899 0.558 54.173 ;
     RECT  0.144 54.173 0.162 54.413 ;
     RECT  2.415 54.059 30.762 54.671 ;
     RECT  30.708 54.671 30.762 54.715 ;
     RECT  30.708 54.715 31.338 54.751 ;
     RECT  2.415 54.671 29.826 55.111 ;
     RECT  30.708 54.751 31.374 55.181 ;
     RECT  1.152 54.571 1.17 55.219 ;
     RECT  0.54 55.219 1.17 55.469 ;
     RECT  2.376 55.111 29.826 55.525 ;
     RECT  2.304 55.525 29.826 55.723 ;
     RECT  30.708 55.181 31.338 55.723 ;
     RECT  2.304 55.723 31.338 55.823 ;
     RECT  32.22 55.867 32.238 55.997 ;
     RECT  30.708 55.823 31.338 56.597 ;
     RECT  31.284 56.597 31.338 56.795 ;
     RECT  2.304 55.823 29.754 56.875 ;
     RECT  31.284 56.795 31.302 57.065 ;
     RECT  2.304 56.875 30.222 57.173 ;
     RECT  0.144 55.579 0.162 57.197 ;
     RECT  2.304 57.173 30.186 57.641 ;
     RECT  2.304 57.641 29.754 57.713 ;
     RECT  0.504 57.379 0.558 57.931 ;
     RECT  0.504 57.931 1.17 58.061 ;
     RECT  0.504 58.061 0.522 58.349 ;
     RECT  31.356 58.117 31.374 58.349 ;
     RECT  2.304 57.713 29.697 58.531 ;
     RECT  0.18 58.507 0.198 58.637 ;
     RECT  30.744 58.387 31.338 58.991 ;
     RECT  2.304 58.531 30.006 59.189 ;
     RECT  31.284 58.991 31.338 59.225 ;
     RECT  2.376 59.189 30.006 59.323 ;
     RECT  0.324 59.323 0.342 59.501 ;
     RECT  2.376 59.323 30.222 59.645 ;
     RECT  2.415 59.645 30.222 59.737 ;
     RECT  31.284 59.225 31.302 59.737 ;
     RECT  0.144 59.899 0.162 60.029 ;
     RECT  2.415 59.737 31.302 60.187 ;
     RECT  2.415 60.187 31.338 60.611 ;
     RECT  0.324 60.475 0.342 60.653 ;
     RECT  2.415 60.611 29.934 60.763 ;
     RECT  30.744 60.611 31.338 61.229 ;
     RECT  2.304 60.763 29.934 61.339 ;
     RECT  1.152 61.387 1.17 61.517 ;
     RECT  2.304 61.339 30.186 61.727 ;
     RECT  0.324 61.771 0.342 61.949 ;
     RECT  19.656 61.727 30.186 62.005 ;
     RECT  0.216 61.963 0.234 62.093 ;
     RECT  19.656 62.005 30.222 62.093 ;
     RECT  2.304 61.727 18.897 62.159 ;
     RECT  31.284 61.229 31.338 62.203 ;
     RECT  17.208 62.159 18.897 62.465 ;
     RECT  0.144 62.539 0.162 62.669 ;
     RECT  17.244 62.465 18.897 63.085 ;
     RECT  19.656 62.093 29.697 63.085 ;
     RECT  17.244 63.085 29.697 63.211 ;
     RECT  30.708 62.203 31.338 63.211 ;
     RECT  17.244 63.211 31.338 63.319 ;
     RECT  1.152 62.347 1.17 63.391 ;
     RECT  0.54 63.391 1.17 63.677 ;
     RECT  17.244 63.319 31.374 63.677 ;
     RECT  0.54 63.677 0.558 63.965 ;
     RECT  17.244 63.677 30.798 64.589 ;
     RECT  30.744 64.589 30.798 64.625 ;
     RECT  2.304 62.159 16.197 64.633 ;
     RECT  17.244 64.589 29.697 64.633 ;
     RECT  0.144 64.219 0.162 64.637 ;
     RECT  1.152 64.699 1.17 64.829 ;
     RECT  30.78 64.625 30.798 64.829 ;
     RECT  32.292 64.651 32.31 65.083 ;
     RECT  32.256 65.083 32.31 65.165 ;
     RECT  2.304 64.633 29.697 65.399 ;
     RECT  31.32 65.209 31.374 65.405 ;
     RECT  0.144 65.371 0.162 65.501 ;
     RECT  2.34 65.399 29.697 65.515 ;
     RECT  32.292 65.165 32.31 65.705 ;
     RECT  31.32 65.405 31.338 65.803 ;
     RECT  2.34 65.515 29.826 65.947 ;
     RECT  30.744 65.803 31.338 65.947 ;
     RECT  0.216 65.803 0.342 65.981 ;
     RECT  0.216 65.981 0.234 66.125 ;
     RECT  2.34 65.947 31.338 66.245 ;
     RECT  2.34 66.245 30.798 66.283 ;
     RECT  2.304 66.283 30.798 66.413 ;
     RECT  2.34 66.413 30.798 66.557 ;
     RECT  32.292 66.955 32.31 67.09 ;
     RECT  32.256 67.09 32.31 67.091 ;
     RECT  2.34 66.557 30.762 67.297 ;
     RECT  32.256 67.091 32.274 67.325 ;
     RECT  2.304 67.297 30.762 67.387 ;
     RECT  2.304 67.387 31.338 67.433 ;
     RECT  30.6 67.433 31.338 67.595 ;
     RECT  30.636 67.595 31.338 68.135 ;
     RECT  2.304 67.433 29.826 68.207 ;
     RECT  0.144 66.571 0.162 68.251 ;
     RECT  0.144 68.251 0.558 68.429 ;
     RECT  19.656 68.207 29.826 68.539 ;
     RECT  30.636 68.135 31.302 68.539 ;
     RECT  2.304 68.207 18.897 68.573 ;
     RECT  2.412 68.573 18.897 68.639 ;
     RECT  19.656 68.539 31.302 68.917 ;
     RECT  19.656 68.917 31.374 69.005 ;
     RECT  16.92 68.639 18.897 69.025 ;
     RECT  19.656 69.005 30.762 69.025 ;
     RECT  2.412 68.639 16.197 69.331 ;
     RECT  0.144 68.429 0.162 69.493 ;
     RECT  16.92 69.025 30.762 69.521 ;
     RECT  2.304 69.331 16.197 69.529 ;
     RECT  16.92 69.521 18.897 69.529 ;
     RECT  0.144 69.493 0.558 69.533 ;
     RECT  0.54 69.533 0.558 69.725 ;
     RECT  19.656 69.521 30.762 69.835 ;
     RECT  19.656 69.835 31.338 69.989 ;
     RECT  30.636 69.989 31.338 70.061 ;
     RECT  19.656 69.989 29.862 70.097 ;
     RECT  2.304 69.529 18.897 70.123 ;
     RECT  2.268 70.123 18.897 70.445 ;
     RECT  30.744 70.061 31.338 70.573 ;
     RECT  30.744 70.573 31.374 70.733 ;
     RECT  30.744 70.733 31.338 70.834 ;
     RECT  30.708 70.834 31.338 70.979 ;
     RECT  0.144 70.987 0.162 71.117 ;
     RECT  19.656 70.097 29.826 71.419 ;
     RECT  2.304 70.445 18.897 71.609 ;
     RECT  2.304 71.609 16.254 71.681 ;
     RECT  19.656 71.419 30.222 71.851 ;
     RECT  19.656 71.851 30.258 71.995 ;
     RECT  31.284 70.979 31.338 71.995 ;
     RECT  0.54 72.121 0.558 72.187 ;
     RECT  0.144 72.187 0.558 72.535 ;
     RECT  2.304 71.681 16.197 72.571 ;
     RECT  32.292 72.427 32.31 72.797 ;
     RECT  0.108 72.535 0.558 72.893 ;
     RECT  17.028 71.609 18.897 73.237 ;
     RECT  19.656 71.995 31.338 73.237 ;
     RECT  2.304 72.571 16.254 73.381 ;
     RECT  17.028 73.237 31.338 73.381 ;
     RECT  0.108 72.893 0.126 73.627 ;
     RECT  2.304 73.381 31.338 73.805 ;
     RECT  0.108 73.627 0.162 73.901 ;
     RECT  2.304 73.805 20.43 73.949 ;
     RECT  21.315 73.805 31.338 74.045 ;
     RECT  30.636 74.045 31.338 74.381 ;
     RECT  0.144 73.901 0.162 75.149 ;
     RECT  31.284 74.381 31.338 75.163 ;
     RECT  30.744 75.163 31.338 75.307 ;
     RECT  21.315 74.045 29.826 75.451 ;
     RECT  30.636 75.307 31.338 75.451 ;
     RECT  21.315 75.451 31.338 75.965 ;
     RECT  0.324 76.603 0.342 76.781 ;
     RECT  2.304 73.949 20.358 77.279 ;
     RECT  31.284 75.965 31.338 77.855 ;
     RECT  0.144 77.179 0.162 77.885 ;
     RECT  21.315 75.965 30.222 77.899 ;
     RECT  2.304 77.279 18.897 78.089 ;
     RECT  21.315 77.899 30.258 78.133 ;
     RECT  31.32 77.855 31.338 78.161 ;
     RECT  2.34 78.089 18.897 78.359 ;
     RECT  0.108 78.331 0.126 78.461 ;
     RECT  21.315 78.133 30.294 78.619 ;
     RECT  2.376 78.359 18.897 78.701 ;
     RECT  21.315 78.619 30.762 78.901 ;
     RECT  21.315 78.901 30.798 79.007 ;
     RECT  30.744 79.007 30.798 79.051 ;
     RECT  32.292 78.187 32.31 79.277 ;
     RECT  2.376 78.701 16.197 79.483 ;
     RECT  17.028 78.701 18.897 79.483 ;
     RECT  32.22 79.339 32.238 79.483 ;
     RECT  32.148 79.483 32.238 79.565 ;
     RECT  32.148 79.565 32.166 79.613 ;
     RECT  21.315 79.007 29.826 79.771 ;
     RECT  30.744 79.051 31.338 79.771 ;
     RECT  0.18 79.591 0.198 79.819 ;
     RECT  0.144 79.819 0.198 79.949 ;
     RECT  2.376 79.483 18.897 80.059 ;
     RECT  21.315 79.771 31.338 80.123 ;
     RECT  0.18 79.949 0.198 80.869 ;
     RECT  0.18 80.869 0.558 80.923 ;
     RECT  21.315 80.123 29.697 80.923 ;
     RECT  30.708 80.123 31.338 80.923 ;
     RECT  0.144 80.923 1.134 81.053 ;
     RECT  2.304 80.059 18.897 81.599 ;
     RECT  21.315 80.923 31.338 81.635 ;
     RECT  2.415 81.599 18.897 81.779 ;
     RECT  21.315 81.635 30.798 82.363 ;
     RECT  21.315 82.363 31.338 82.445 ;
     RECT  2.415 81.779 15.174 82.651 ;
     RECT  32.292 81.355 32.31 82.715 ;
     RECT  21.315 82.445 30.798 82.949 ;
     RECT  0.54 81.053 0.558 82.987 ;
     RECT  0.144 82.987 0.558 83.117 ;
     RECT  2.304 82.651 15.174 83.129 ;
     RECT  0.18 83.117 0.558 83.261 ;
     RECT  0.18 83.261 0.198 83.405 ;
     RECT  2.304 83.129 15.102 83.563 ;
     RECT  2.268 83.563 15.102 83.693 ;
     RECT  23.508 82.949 30.798 83.947 ;
     RECT  21.315 82.949 22.59 84.749 ;
     RECT  0.144 84.139 0.162 84.941 ;
     RECT  23.508 83.947 31.338 85.145 ;
     RECT  2.304 83.693 15.102 85.379 ;
     RECT  0.54 85.189 0.558 85.565 ;
     RECT  21.315 84.749 22.014 85.757 ;
     RECT  23.508 85.145 30.258 85.915 ;
     RECT  15.915 81.779 18.897 85.919 ;
     RECT  23.256 85.915 30.258 85.955 ;
     RECT  31.284 85.145 31.338 85.991 ;
     RECT  15.915 85.919 17.154 86.189 ;
     RECT  31.284 85.991 31.302 86.225 ;
     RECT  22.788 86.197 22.806 86.333 ;
     RECT  23.544 85.955 30.258 86.333 ;
     RECT  32.292 85.819 32.31 86.495 ;
     RECT  0.144 85.723 0.162 86.573 ;
     RECT  23.544 86.333 29.697 86.701 ;
     RECT  22.824 86.701 29.697 86.873 ;
     RECT  12.852 85.379 15.102 86.909 ;
     RECT  19.728 77.279 20.358 87.071 ;
     RECT  23.544 86.873 29.697 87.115 ;
     RECT  15.915 86.189 16.197 87.241 ;
     RECT  17.136 86.189 17.154 87.241 ;
     RECT  2.304 85.379 12.042 87.385 ;
     RECT  23.544 87.115 30.222 87.403 ;
     RECT  31.32 87.259 31.338 87.403 ;
     RECT  2.196 87.385 12.042 87.437 ;
     RECT  21.315 85.757 21.597 87.547 ;
     RECT  2.304 87.437 12.042 87.647 ;
     RECT  0.144 87.595 0.162 87.725 ;
     RECT  2.34 87.647 12.042 87.809 ;
     RECT  21.315 87.547 22.266 87.817 ;
     RECT  21.315 87.817 22.338 87.925 ;
     RECT  23.544 87.403 31.338 88.027 ;
     RECT  17.964 85.919 18.897 88.231 ;
     RECT  19.728 87.071 19.746 88.231 ;
     RECT  17.964 88.231 19.746 88.349 ;
     RECT  32.292 88.267 32.31 88.421 ;
     RECT  21.315 87.925 22.41 88.429 ;
     RECT  23.436 88.027 31.338 88.429 ;
     RECT  21.315 88.429 31.338 88.457 ;
     RECT  21.315 88.457 29.826 88.493 ;
     RECT  2.415 87.809 12.042 88.735 ;
     RECT  15.915 87.241 17.154 88.735 ;
     RECT  17.964 88.349 18.897 88.735 ;
     RECT  22.32 88.493 29.826 88.763 ;
     RECT  0.144 88.459 0.162 88.861 ;
     RECT  0.108 88.861 0.162 88.877 ;
     RECT  2.34 88.735 12.042 88.997 ;
     RECT  0.108 88.877 0.126 89.021 ;
     RECT  2.34 88.997 10.797 89.041 ;
     RECT  15.915 88.735 18.897 89.239 ;
     RECT  30.708 88.457 31.338 89.275 ;
     RECT  21.315 88.493 21.597 89.311 ;
     RECT  23.328 88.763 29.826 89.501 ;
     RECT  14.508 86.909 15.102 89.509 ;
     RECT  15.915 89.239 18.954 89.509 ;
     RECT  21.315 89.311 22.266 89.509 ;
     RECT  14.508 89.509 18.954 89.545 ;
     RECT  19.728 88.349 19.746 89.545 ;
     RECT  21.315 89.509 22.914 89.609 ;
     RECT  21.315 89.609 22.842 89.699 ;
     RECT  2.304 89.041 10.797 89.851 ;
     RECT  23.904 89.501 29.826 89.851 ;
     RECT  30.636 89.275 31.338 89.851 ;
     RECT  2.304 89.851 10.89 89.969 ;
     RECT  23.904 89.851 31.338 89.969 ;
     RECT  32.292 89.851 32.31 89.995 ;
     RECT  2.304 89.969 10.854 90.029 ;
     RECT  32.256 89.995 32.31 90.041 ;
     RECT  2.304 90.029 8.37 90.121 ;
     RECT  14.508 89.545 19.746 90.149 ;
     RECT  32.256 90.041 32.274 90.149 ;
     RECT  2.268 90.121 8.37 90.173 ;
     RECT  23.94 89.969 31.338 90.173 ;
     RECT  30.78 90.173 31.338 90.317 ;
     RECT  12.852 86.909 13.497 90.589 ;
     RECT  2.304 90.173 8.37 90.751 ;
     RECT  9.108 90.029 10.854 90.751 ;
     RECT  23.94 90.173 29.826 90.859 ;
     RECT  21.315 89.699 22.266 90.923 ;
     RECT  12.852 90.589 13.698 90.959 ;
     RECT  23.832 90.859 29.826 91.003 ;
     RECT  23.832 91.003 30.222 91.021 ;
     RECT  17.964 90.149 19.746 91.085 ;
     RECT  22.824 91.021 30.222 91.157 ;
     RECT  22.824 91.157 22.914 91.193 ;
     RECT  24.015 91.157 30.222 91.327 ;
     RECT  31.284 90.317 31.338 91.327 ;
     RECT  14.508 90.149 17.154 91.391 ;
     RECT  2.304 90.751 10.854 91.471 ;
     RECT  2.304 91.471 10.926 91.589 ;
     RECT  9.432 91.589 10.926 91.625 ;
     RECT  14.508 91.391 17.118 91.669 ;
     RECT  0.144 90.427 0.162 91.757 ;
     RECT  9.648 91.625 10.926 91.831 ;
     RECT  9.648 91.831 11.07 91.895 ;
     RECT  22.896 91.193 22.914 91.895 ;
     RECT  24.015 91.327 31.338 91.895 ;
     RECT  14.256 91.669 17.118 91.931 ;
     RECT  24.015 91.895 30.798 91.975 ;
     RECT  15.915 91.931 17.01 92.003 ;
     RECT  19.728 91.085 19.746 92.011 ;
     RECT  14.256 91.931 15.102 92.129 ;
     RECT  19.62 92.011 19.746 92.165 ;
     RECT  16.992 92.003 17.01 92.237 ;
     RECT  24.012 91.975 30.798 92.237 ;
     RECT  19.728 92.165 19.746 92.281 ;
     RECT  22.86 92.209 22.878 92.309 ;
     RECT  0.108 92.281 0.126 92.333 ;
     RECT  2.304 91.589 8.694 92.371 ;
     RECT  19.728 92.281 19.782 92.579 ;
     RECT  19.764 92.579 19.782 92.669 ;
     RECT  9.864 91.895 11.07 92.741 ;
     RECT  24.015 92.237 30.798 92.765 ;
     RECT  2.304 92.371 8.91 92.821 ;
     RECT  0.144 92.779 0.162 92.909 ;
     RECT  14.508 92.129 15.102 93.047 ;
     RECT  24.015 92.765 30.222 93.289 ;
     RECT  14.508 93.047 14.526 93.317 ;
     RECT  23.94 93.289 30.222 93.317 ;
     RECT  32.292 93.307 32.31 93.451 ;
     RECT  2.304 92.821 9.126 93.499 ;
     RECT  9.864 92.741 11.034 93.499 ;
     RECT  23.94 93.317 29.898 93.499 ;
     RECT  2.304 93.499 11.034 93.631 ;
     RECT  31.284 93.019 31.338 93.757 ;
     RECT  0.108 93.163 0.126 93.787 ;
     RECT  32.256 93.451 32.31 93.821 ;
     RECT  0.108 93.787 0.162 93.829 ;
     RECT  2.304 93.631 11.106 94.019 ;
     RECT  23.544 93.499 29.898 94.019 ;
     RECT  17.964 91.085 18.897 94.199 ;
     RECT  32.256 93.821 32.274 94.199 ;
     RECT  0.108 93.829 0.558 94.205 ;
     RECT  24.015 94.019 29.826 94.289 ;
     RECT  9.684 94.019 11.106 94.361 ;
     RECT  25.416 94.289 29.826 94.397 ;
     RECT  9.684 94.361 10.818 94.469 ;
     RECT  12.024 88.997 12.042 94.469 ;
     RECT  9.684 94.469 10.797 94.595 ;
     RECT  0.108 94.205 0.234 94.637 ;
     RECT  32.22 94.603 32.238 94.733 ;
     RECT  30.78 93.757 31.338 94.865 ;
     RECT  25.452 94.397 29.826 94.891 ;
     RECT  24.015 94.289 24.678 94.939 ;
     RECT  12.852 90.959 13.497 95.099 ;
     RECT  0.108 94.637 0.162 95.165 ;
     RECT  2.304 94.019 8.766 95.171 ;
     RECT  23.472 94.939 24.678 95.179 ;
     RECT  25.452 94.891 30.762 95.179 ;
     RECT  7.416 95.171 8.766 95.279 ;
     RECT  23.472 95.179 30.762 95.405 ;
     RECT  25.632 95.405 30.762 95.647 ;
     RECT  0.108 95.165 0.126 95.719 ;
     RECT  25.632 95.647 31.374 95.789 ;
     RECT  9.756 94.595 10.797 95.909 ;
     RECT  23.472 95.405 24.642 95.909 ;
     RECT  25.632 95.789 30.762 96.017 ;
     RECT  2.304 95.171 6.354 96.025 ;
     RECT  7.416 95.279 8.694 96.025 ;
     RECT  9.864 95.909 10.797 96.061 ;
     RECT  1.404 95.467 1.422 96.187 ;
     RECT  2.304 96.025 8.694 96.187 ;
     RECT  26.136 96.017 30.762 96.215 ;
     RECT  26.136 96.215 30.222 96.287 ;
     RECT  0.036 95.719 0.126 96.331 ;
     RECT  26.136 96.287 29.697 96.485 ;
     RECT  0.036 96.331 0.342 96.509 ;
     RECT  9.864 96.061 10.89 96.593 ;
     RECT  1.404 96.187 8.694 96.691 ;
     RECT  26.715 96.485 29.697 96.719 ;
     RECT  0.036 96.509 0.162 96.749 ;
     RECT  32.292 95.179 32.31 96.791 ;
     RECT  28.584 96.719 29.697 96.863 ;
     RECT  29.016 96.863 29.697 96.989 ;
     RECT  1.404 96.691 9.09 97.105 ;
     RECT  9.864 96.593 10.797 97.105 ;
     RECT  26.715 96.719 27.486 97.169 ;
     RECT  0.036 96.749 0.054 97.483 ;
     RECT  1.404 97.105 10.797 97.565 ;
     RECT  0.036 97.483 0.162 97.613 ;
     RECT  10.515 97.565 10.797 97.681 ;
     RECT  1.404 97.565 9.774 97.709 ;
     RECT  1.404 97.709 8.097 97.799 ;
     RECT  1.404 97.799 6.39 97.835 ;
     RECT  1.404 97.835 6.282 97.871 ;
     RECT  7.2 97.799 8.097 97.871 ;
     RECT  9.144 97.709 9.774 97.871 ;
     RECT  1.404 97.871 6.246 97.907 ;
     RECT  9.684 97.871 9.774 98.177 ;
     RECT  10.515 97.681 10.89 98.213 ;
     RECT  7.344 97.871 8.097 98.249 ;
     RECT  1.404 97.907 6.174 98.411 ;
     RECT  1.404 98.411 6.138 98.447 ;
     RECT  1.404 98.447 5.49 98.519 ;
     RECT  9.756 98.177 9.774 98.519 ;
     RECT  1.404 98.519 5.397 98.915 ;
     RECT  1.404 98.915 3.834 99.329 ;
     RECT  2.34 99.329 3.834 99.419 ;
     RECT  2.34 99.419 3.474 99.455 ;
     RECT  4.716 98.915 5.397 99.491 ;
     RECT  2.376 99.455 3.474 99.527 ;
     RECT  1.404 99.329 1.422 99.599 ;
     RECT  2.415 99.527 3.474 99.761 ;
     RECT  2.415 99.761 2.826 101.615 ;
     RECT  0.036 97.613 0.054 101.759 ;
     RECT  2.415 101.615 2.697 105.587 ;
     RECT  5.115 99.491 5.397 105.587 ;
     RECT  7.815 98.249 8.097 105.587 ;
     RECT  10.515 98.213 10.797 105.587 ;
     RECT  13.215 95.099 13.497 105.587 ;
     RECT  15.915 92.003 16.197 105.587 ;
     RECT  18.615 94.199 18.897 105.587 ;
     RECT  21.315 90.923 21.597 105.587 ;
     RECT  24.015 95.909 24.297 105.587 ;
     RECT  26.715 97.169 26.997 105.587 ;
     RECT  29.415 96.989 29.697 105.587 ;
     RECT  2.415 105.587 2.505 105.857 ;
     RECT  5.115 105.587 5.205 105.857 ;
     RECT  7.815 105.587 7.905 105.857 ;
     RECT  10.515 105.587 10.605 105.857 ;
     RECT  13.215 105.587 13.305 105.857 ;
     RECT  15.915 105.587 16.005 105.857 ;
     RECT  18.615 105.587 18.705 105.857 ;
     RECT  21.315 105.587 21.405 105.857 ;
     RECT  24.015 105.587 24.105 105.857 ;
     RECT  26.715 105.587 26.805 105.857 ;
     RECT  29.415 105.587 29.505 105.857 ;
    LAYER M4 ;
     RECT  0.084 50.832 0.097 50.856 ;
     RECT  0.06 50.856 0.097 50.976 ;
     RECT  0.084 50.976 0.097 51 ;
     RECT  0.06 51 0.097 51.12 ;
     RECT  0.084 51.12 0.097 51.144 ;
     RECT  0.06 51.144 0.097 51.264 ;
     RECT  0.084 51.264 0.097 51.288 ;
     RECT  0.06 51.288 0.097 51.408 ;
     RECT  0.084 51.408 0.097 51.432 ;
     RECT  0.06 51.432 0.097 51.552 ;
     RECT  0.084 51.552 0.097 51.576 ;
     RECT  0.06 51.576 0.097 51.696 ;
     RECT  0.084 51.696 0.097 51.72 ;
     RECT  0.06 51.72 0.097 51.84 ;
     RECT  0.084 51.84 0.097 51.864 ;
     RECT  0.06 51.864 0.097 51.984 ;
     RECT  0.084 51.984 0.097 52.008 ;
     RECT  0.06 52.008 0.097 52.128 ;
     RECT  0.084 52.128 0.097 52.152 ;
     RECT  0.06 52.152 0.097 52.272 ;
     RECT  0.084 52.272 0.097 52.296 ;
     RECT  0.06 52.296 0.097 52.416 ;
     RECT  0.084 52.416 0.097 52.44 ;
     RECT  0.06 52.44 0.097 52.56 ;
     RECT  0.084 52.56 0.097 52.584 ;
     RECT  0.06 52.584 0.097 52.704 ;
     RECT  0.084 52.704 0.097 52.728 ;
     RECT  0.06 52.728 0.097 52.848 ;
     RECT  0.084 52.848 0.097 52.872 ;
     RECT  0.06 52.872 0.097 52.992 ;
     RECT  0.084 52.992 0.097 53.016 ;
     RECT  0.06 53.016 0.097 53.136 ;
     RECT  0.084 53.136 0.097 53.16 ;
     RECT  0.06 53.16 0.097 53.28 ;
     RECT  0.084 53.28 0.097 53.304 ;
     RECT  0.06 53.304 0.097 53.424 ;
     RECT  0.084 53.424 0.097 53.448 ;
     RECT  0.06 53.448 0.097 53.568 ;
     RECT  0.084 53.568 0.097 53.592 ;
     RECT  0.06 53.592 0.097 53.712 ;
     RECT  0.084 53.712 0.097 53.736 ;
     RECT  0.06 53.736 0.097 53.856 ;
     RECT  0.084 53.856 0.097 53.88 ;
     RECT  0.06 53.88 0.097 54 ;
     RECT  0.084 54 0.097 54.024 ;
     RECT  0.06 54.024 0.097 54.144 ;
     RECT  0.084 54.144 0.097 54.168 ;
     RECT  0.06 54.168 0.097 54.288 ;
     RECT  0.084 54.288 0.097 54.312 ;
     RECT  0.06 54.312 0.097 54.432 ;
     RECT  0.084 54.432 0.097 54.456 ;
     RECT  0.06 54.456 0.097 54.576 ;
     RECT  0.084 54.576 0.097 54.6 ;
     RECT  0.06 54.6 0.097 54.72 ;
     RECT  0.084 54.72 0.097 54.744 ;
     RECT  0.06 54.744 0.097 54.864 ;
     RECT  0.084 54.864 0.097 54.888 ;
     RECT  0.06 54.888 0.097 55.008 ;
     RECT  0.084 55.008 0.097 55.032 ;
     RECT  0.06 55.032 0.097 55.152 ;
     RECT  0.084 55.152 0.097 55.176 ;
     RECT  0.06 55.176 0.097 55.296 ;
     RECT  0.084 55.296 0.097 55.32 ;
     RECT  0.06 55.32 0.097 55.44 ;
     RECT  0.084 55.44 0.097 55.464 ;
     RECT  0.06 55.464 0.097 55.584 ;
     RECT  0.084 55.584 0.097 55.608 ;
     RECT  0.06 55.608 0.097 55.728 ;
     RECT  0.084 55.728 0.097 55.752 ;
     RECT  0.06 55.752 0.097 55.872 ;
     RECT  0.084 55.872 0.097 55.896 ;
     RECT  0.06 55.896 0.097 56.016 ;
     RECT  0.084 56.016 0.097 56.04 ;
     RECT  0.06 56.04 0.097 56.16 ;
     RECT  0.084 56.16 0.097 56.184 ;
     RECT  0.06 56.184 0.097 56.304 ;
     RECT  0.084 56.304 0.097 56.328 ;
     RECT  0.06 56.328 0.097 56.448 ;
     RECT  0.084 56.448 0.097 56.472 ;
     RECT  0.06 56.472 0.097 56.592 ;
     RECT  0.084 56.592 0.097 56.616 ;
     RECT  0.06 56.616 0.097 56.736 ;
     RECT  0.084 56.736 0.097 56.76 ;
     RECT  0.06 56.76 0.097 56.88 ;
     RECT  0.084 56.88 0.097 56.904 ;
     RECT  0.06 56.904 0.097 57.024 ;
     RECT  0.084 57.024 0.097 57.048 ;
     RECT  0.06 57.048 0.097 57.168 ;
     RECT  0.084 57.168 0.097 57.192 ;
     RECT  0.06 57.192 0.097 57.312 ;
     RECT  0.084 57.312 0.097 57.336 ;
     RECT  0.06 57.336 0.097 57.456 ;
     RECT  0.084 57.456 0.097 57.48 ;
     RECT  0.06 57.48 0.097 57.6 ;
     RECT  0.084 57.6 0.097 57.624 ;
     RECT  0.06 57.624 0.097 57.744 ;
     RECT  0.084 57.744 0.097 57.768 ;
     RECT  0.06 57.768 0.097 57.888 ;
     RECT  0.084 57.888 0.097 57.912 ;
     RECT  0.06 57.912 0.097 58.032 ;
     RECT  0.084 58.032 0.097 58.056 ;
     RECT  0.06 58.056 0.097 58.176 ;
     RECT  0.084 58.176 0.097 58.2 ;
     RECT  0.06 58.2 0.097 58.32 ;
     RECT  0.084 58.32 0.097 58.344 ;
     RECT  0.06 58.344 0.097 58.464 ;
     RECT  0.084 58.464 0.097 58.488 ;
     RECT  0.06 58.488 0.097 58.608 ;
     RECT  0.084 58.608 0.097 58.632 ;
     RECT  0.06 58.632 0.097 58.752 ;
     RECT  0.084 58.752 0.097 58.776 ;
     RECT  0.06 58.776 0.097 58.896 ;
     RECT  0.084 58.896 0.097 58.92 ;
     RECT  0.06 58.92 0.097 59.04 ;
     RECT  0.084 59.04 0.097 59.064 ;
     RECT  0.06 59.064 0.097 59.184 ;
     RECT  0.084 59.184 0.097 59.208 ;
     RECT  0.06 59.208 0.097 59.328 ;
     RECT  0.084 59.328 0.097 59.352 ;
     RECT  0.06 59.352 0.097 59.472 ;
     RECT  0.084 59.472 0.097 59.496 ;
     RECT  0.06 59.496 0.097 59.616 ;
     RECT  0.084 59.616 0.097 59.64 ;
     RECT  0.06 59.64 0.097 59.76 ;
     RECT  0.084 59.76 0.097 59.784 ;
     RECT  0.06 59.784 0.097 59.904 ;
     RECT  0.084 59.904 0.097 59.928 ;
     RECT  0.06 59.928 0.097 60.048 ;
     RECT  0.084 60.048 0.097 60.072 ;
     RECT  0.06 60.072 0.097 60.192 ;
     RECT  0.084 60.192 0.097 60.216 ;
     RECT  0.06 60.216 0.097 60.336 ;
     RECT  0.084 60.336 0.097 60.36 ;
     RECT  0.06 60.36 0.097 60.48 ;
     RECT  0.084 60.48 0.097 60.504 ;
     RECT  0.06 60.504 0.097 60.624 ;
     RECT  0.084 60.624 0.097 60.648 ;
     RECT  0.06 60.648 0.097 60.768 ;
     RECT  0.084 60.768 0.097 60.792 ;
     RECT  0.06 60.792 0.097 60.912 ;
     RECT  0.084 60.912 0.097 60.936 ;
     RECT  0.06 60.936 0.097 61.056 ;
     RECT  0.084 61.056 0.097 61.08 ;
     RECT  0.06 61.08 0.097 61.2 ;
     RECT  0.084 61.2 0.097 61.224 ;
     RECT  0.06 61.224 0.097 61.344 ;
     RECT  0.084 61.344 0.097 61.368 ;
     RECT  0.06 61.368 0.097 61.488 ;
     RECT  0.084 61.488 0.097 61.512 ;
     RECT  0.06 61.512 0.097 61.632 ;
     RECT  0.084 61.632 0.097 61.656 ;
     RECT  0.06 61.656 0.097 61.776 ;
     RECT  0.084 61.776 0.097 61.8 ;
     RECT  0.06 61.8 0.097 61.92 ;
     RECT  0.084 61.92 0.097 61.944 ;
     RECT  0.06 61.944 0.097 62.064 ;
     RECT  0.084 62.064 0.097 62.088 ;
     RECT  0.06 62.088 0.097 62.208 ;
     RECT  0.084 62.208 0.097 62.232 ;
     RECT  0.06 62.232 0.097 62.352 ;
     RECT  0.084 62.352 0.097 62.376 ;
     RECT  0.06 62.376 0.097 62.496 ;
     RECT  0.084 62.496 0.097 62.52 ;
     RECT  0.06 62.52 0.097 62.64 ;
     RECT  0.084 62.64 0.097 62.664 ;
     RECT  0.06 62.664 0.097 62.784 ;
     RECT  0.084 62.784 0.097 62.808 ;
     RECT  0.06 62.808 0.097 62.928 ;
     RECT  0.084 62.928 0.097 62.952 ;
     RECT  0.06 62.952 0.097 63.072 ;
     RECT  0.084 63.072 0.097 63.096 ;
     RECT  0.06 63.096 0.097 63.216 ;
     RECT  0.084 63.216 0.097 63.24 ;
     RECT  0.06 63.24 0.097 63.36 ;
     RECT  0.084 63.36 0.097 63.384 ;
     RECT  0.06 63.384 0.097 63.504 ;
     RECT  0.084 63.504 0.097 63.528 ;
     RECT  0.06 63.528 0.097 63.648 ;
     RECT  0.084 63.648 0.097 63.672 ;
     RECT  0.06 63.672 0.097 63.792 ;
     RECT  0.084 63.792 0.097 63.816 ;
     RECT  0.06 63.816 0.097 63.936 ;
     RECT  0.084 63.936 0.097 63.96 ;
     RECT  0.06 63.96 0.097 64.08 ;
     RECT  0.084 64.08 0.097 64.104 ;
     RECT  0.06 64.104 0.097 64.224 ;
     RECT  0.084 64.224 0.097 64.248 ;
     RECT  0.06 64.248 0.097 64.368 ;
     RECT  0.084 64.368 0.097 64.392 ;
     RECT  0.06 64.392 0.097 64.512 ;
     RECT  0.084 64.512 0.097 64.536 ;
     RECT  0.06 64.536 0.097 64.656 ;
     RECT  0.084 64.656 0.097 64.68 ;
     RECT  0.06 64.68 0.097 64.8 ;
     RECT  0.084 64.8 0.097 64.824 ;
     RECT  0.06 64.824 0.097 64.944 ;
     RECT  0.084 64.944 0.097 64.968 ;
     RECT  0.06 64.968 0.097 65.088 ;
     RECT  0.084 65.088 0.097 65.112 ;
     RECT  0.06 65.112 0.097 65.232 ;
     RECT  0.084 65.232 0.097 65.256 ;
     RECT  0.06 65.256 0.097 65.376 ;
     RECT  0.084 65.376 0.097 65.4 ;
     RECT  0.06 65.4 0.097 65.52 ;
     RECT  0.084 65.52 0.097 65.544 ;
     RECT  0.06 65.544 0.097 65.664 ;
     RECT  0.084 65.664 0.097 65.688 ;
     RECT  0.06 65.688 0.097 65.808 ;
     RECT  0.084 65.808 0.097 65.832 ;
     RECT  0.06 65.832 0.097 65.952 ;
     RECT  0.084 65.952 0.097 65.976 ;
     RECT  0.06 65.976 0.097 66.096 ;
     RECT  0.084 66.096 0.097 66.12 ;
     RECT  0.06 66.12 0.097 66.24 ;
     RECT  0.084 66.24 0.097 66.264 ;
     RECT  0.06 66.264 0.097 66.384 ;
     RECT  0.084 66.384 0.097 66.408 ;
     RECT  0.06 66.408 0.097 66.528 ;
     RECT  0.084 66.528 0.097 66.552 ;
     RECT  0.06 66.552 0.097 66.672 ;
     RECT  0.084 66.672 0.097 66.696 ;
     RECT  0.06 66.696 0.097 66.816 ;
     RECT  0.084 66.816 0.097 66.84 ;
     RECT  0.06 66.84 0.097 66.96 ;
     RECT  0.084 66.96 0.097 66.984 ;
     RECT  0.06 66.984 0.097 67.104 ;
     RECT  0.084 67.104 0.097 67.128 ;
     RECT  0.06 67.128 0.097 67.248 ;
     RECT  0.084 67.248 0.097 67.272 ;
     RECT  0.06 67.272 0.097 67.392 ;
     RECT  0.084 67.392 0.097 67.416 ;
     RECT  0.06 67.416 0.097 67.536 ;
     RECT  0.084 67.536 0.097 67.56 ;
     RECT  0.06 67.56 0.097 67.68 ;
     RECT  0.084 67.68 0.097 67.704 ;
     RECT  0.06 67.704 0.097 67.824 ;
     RECT  0.084 67.824 0.097 67.848 ;
     RECT  0.06 67.848 0.097 67.968 ;
     RECT  0.084 67.968 0.097 67.992 ;
     RECT  0.06 67.992 0.097 68.112 ;
     RECT  0.084 68.112 0.097 68.136 ;
     RECT  0.06 68.136 0.097 68.256 ;
     RECT  0.084 68.256 0.097 68.28 ;
     RECT  0.06 68.28 0.097 68.4 ;
     RECT  0.084 68.4 0.097 68.424 ;
     RECT  0.06 68.424 0.097 68.544 ;
     RECT  0.084 68.544 0.097 68.568 ;
     RECT  0.06 68.568 0.097 68.688 ;
     RECT  0.084 68.688 0.097 68.712 ;
     RECT  0.06 68.712 0.097 68.832 ;
     RECT  0.084 68.832 0.097 68.856 ;
     RECT  0.06 68.856 0.097 68.976 ;
     RECT  0.084 68.976 0.097 69 ;
     RECT  0.06 69 0.097 69.12 ;
     RECT  0.084 69.12 0.097 69.144 ;
     RECT  0.06 69.144 0.097 69.264 ;
     RECT  0.084 69.264 0.097 69.288 ;
     RECT  0.06 69.288 0.097 69.408 ;
     RECT  0.084 69.408 0.097 69.432 ;
     RECT  0.06 69.432 0.097 69.552 ;
     RECT  0.084 69.552 0.097 69.576 ;
     RECT  0.06 69.576 0.097 69.696 ;
     RECT  0.084 69.696 0.097 69.72 ;
     RECT  0.06 69.72 0.097 69.84 ;
     RECT  0.084 69.84 0.097 69.864 ;
     RECT  0.06 69.864 0.097 69.984 ;
     RECT  0.084 69.984 0.097 70.008 ;
     RECT  0.06 70.008 0.097 70.128 ;
     RECT  0.084 70.128 0.097 70.152 ;
     RECT  0.06 70.152 0.097 70.272 ;
     RECT  0.084 70.272 0.097 70.296 ;
     RECT  0.06 70.296 0.097 70.416 ;
     RECT  0.084 70.416 0.097 70.44 ;
     RECT  0.06 70.44 0.097 70.56 ;
     RECT  0.084 70.56 0.097 70.584 ;
     RECT  0.06 70.584 0.097 70.704 ;
     RECT  0.084 70.704 0.097 70.728 ;
     RECT  0.06 70.728 0.097 70.848 ;
     RECT  0.084 70.848 0.097 70.872 ;
     RECT  0.06 70.872 0.097 70.992 ;
     RECT  0.084 70.992 0.097 71.016 ;
     RECT  0.06 71.016 0.097 71.136 ;
     RECT  0.084 71.136 0.097 71.16 ;
     RECT  0.06 71.16 0.097 71.28 ;
     RECT  0.084 71.28 0.097 71.304 ;
     RECT  0.06 71.304 0.097 71.424 ;
     RECT  0.084 71.424 0.097 71.448 ;
     RECT  0.06 71.448 0.097 71.568 ;
     RECT  0.084 71.568 0.097 71.592 ;
     RECT  0.06 71.592 0.097 71.712 ;
     RECT  0.084 71.712 0.097 71.736 ;
     RECT  0.06 71.736 0.097 71.856 ;
     RECT  0.084 71.856 0.097 71.88 ;
     RECT  0.06 71.88 0.097 72 ;
     RECT  0.084 72 0.097 72.024 ;
     RECT  0.06 72.024 0.097 72.144 ;
     RECT  0.084 72.144 0.097 72.168 ;
     RECT  0.06 72.168 0.097 72.288 ;
     RECT  0.084 72.288 0.097 72.312 ;
     RECT  0.06 72.312 0.097 72.432 ;
     RECT  0.084 72.432 0.097 72.456 ;
     RECT  0.06 72.456 0.097 72.576 ;
     RECT  0.084 72.576 0.097 72.6 ;
     RECT  0.06 72.6 0.097 72.72 ;
     RECT  0.084 72.72 0.097 72.744 ;
     RECT  0.06 72.744 0.097 72.864 ;
     RECT  0.084 72.864 0.097 72.888 ;
     RECT  0.06 72.888 0.097 73.008 ;
     RECT  0.084 73.008 0.097 73.032 ;
     RECT  0.06 73.032 0.097 73.152 ;
     RECT  0.084 73.152 0.097 73.176 ;
     RECT  0.06 73.176 0.097 73.296 ;
     RECT  0.084 73.296 0.097 73.32 ;
     RECT  0.06 73.32 0.097 73.44 ;
     RECT  0.084 73.44 0.097 73.464 ;
     RECT  0.06 73.464 0.097 73.584 ;
     RECT  0.084 73.584 0.097 73.608 ;
     RECT  0.06 73.608 0.097 73.728 ;
     RECT  0.084 73.728 0.097 73.752 ;
     RECT  0.06 73.752 0.097 73.872 ;
     RECT  0.084 73.872 0.097 73.896 ;
     RECT  0.06 73.896 0.097 74.016 ;
     RECT  0.084 74.016 0.097 74.04 ;
     RECT  0.06 74.04 0.097 74.16 ;
     RECT  0.084 74.16 0.097 74.184 ;
     RECT  0.06 74.184 0.097 74.304 ;
     RECT  0.084 74.304 0.097 74.328 ;
     RECT  0.06 74.328 0.097 74.448 ;
     RECT  0.084 74.448 0.097 74.472 ;
     RECT  0.06 74.472 0.097 74.592 ;
     RECT  0.084 74.592 0.097 74.616 ;
     RECT  0.06 74.616 0.097 74.736 ;
     RECT  0.084 74.736 0.097 74.76 ;
     RECT  0.06 74.76 0.097 74.88 ;
     RECT  0.084 74.88 0.097 74.904 ;
     RECT  0.06 74.904 0.097 75.024 ;
     RECT  0.084 75.024 0.097 75.048 ;
     RECT  0.06 75.048 0.097 75.168 ;
     RECT  0.084 75.168 0.097 75.192 ;
     RECT  0.06 75.192 0.097 75.312 ;
     RECT  0.084 75.312 0.097 75.336 ;
     RECT  0.06 75.336 0.097 75.456 ;
     RECT  0.084 75.456 0.097 75.48 ;
     RECT  0.06 75.48 0.097 75.6 ;
     RECT  0.084 75.6 0.097 75.624 ;
     RECT  0.06 75.624 0.097 75.744 ;
     RECT  0.084 75.744 0.097 75.768 ;
     RECT  0.06 75.768 0.097 75.888 ;
     RECT  0.084 75.888 0.097 75.912 ;
     RECT  0.06 75.912 0.097 76.032 ;
     RECT  0.084 76.032 0.097 76.056 ;
     RECT  0.06 76.056 0.097 76.176 ;
     RECT  0.084 76.176 0.097 76.2 ;
     RECT  0.06 76.2 0.097 76.32 ;
     RECT  0.084 76.32 0.097 76.344 ;
     RECT  0.06 76.344 0.097 76.464 ;
     RECT  0.084 76.464 0.097 76.488 ;
     RECT  0.06 76.488 0.097 76.608 ;
     RECT  0.084 76.608 0.097 76.632 ;
     RECT  0.06 76.632 0.097 76.752 ;
     RECT  0.084 76.752 0.097 76.776 ;
     RECT  0.06 76.776 0.097 76.896 ;
     RECT  0.084 76.896 0.097 76.92 ;
     RECT  0.06 76.92 0.097 77.04 ;
     RECT  0.084 77.04 0.097 77.064 ;
     RECT  0.06 77.064 0.097 77.184 ;
     RECT  0.084 77.184 0.097 77.208 ;
     RECT  0.06 77.208 0.097 77.328 ;
     RECT  0.084 77.328 0.097 77.352 ;
     RECT  0.06 77.352 0.097 77.472 ;
     RECT  0.084 77.472 0.097 77.496 ;
     RECT  0.06 77.496 0.097 77.616 ;
     RECT  0.084 77.616 0.097 77.64 ;
     RECT  0.06 77.64 0.097 77.76 ;
     RECT  0.084 77.76 0.097 77.784 ;
     RECT  0.06 77.784 0.097 77.904 ;
     RECT  0.084 77.904 0.097 77.928 ;
     RECT  0.06 77.928 0.097 78.048 ;
     RECT  0.084 78.048 0.097 78.072 ;
     RECT  0.06 78.072 0.097 78.192 ;
     RECT  0.084 78.192 0.097 78.216 ;
     RECT  0.06 78.216 0.097 78.336 ;
     RECT  0.084 78.336 0.097 78.36 ;
     RECT  0.084 11.952 2.293 11.976 ;
     RECT  0.06 11.976 2.293 12.096 ;
     RECT  0.084 12.096 2.293 12.12 ;
     RECT  0.06 12.12 2.293 12.24 ;
     RECT  0.084 12.24 2.293 12.264 ;
     RECT  0.06 12.264 2.293 12.384 ;
     RECT  0.084 12.384 2.293 12.408 ;
     RECT  0.06 12.408 2.293 12.528 ;
     RECT  0.084 12.528 2.293 12.552 ;
     RECT  0.06 12.552 2.293 12.672 ;
     RECT  0.084 12.672 2.293 12.696 ;
     RECT  0.06 12.696 2.293 12.816 ;
     RECT  0.084 12.816 2.293 12.84 ;
     RECT  0.06 12.84 2.293 12.96 ;
     RECT  0.084 12.96 2.293 12.984 ;
     RECT  0.06 12.984 2.293 13.104 ;
     RECT  0.084 13.104 2.293 13.128 ;
     RECT  0.06 13.128 2.293 13.248 ;
     RECT  0.084 13.248 2.293 13.272 ;
     RECT  0.06 13.272 2.293 13.392 ;
     RECT  0.084 13.392 2.293 13.416 ;
     RECT  0.06 13.416 2.293 13.536 ;
     RECT  0.084 13.536 2.293 13.56 ;
     RECT  0.06 13.56 2.293 13.68 ;
     RECT  0.084 13.68 2.293 13.704 ;
     RECT  0.06 13.704 2.293 13.824 ;
     RECT  0.084 13.824 2.293 13.848 ;
     RECT  0.06 13.848 2.293 13.968 ;
     RECT  0.084 13.968 2.293 13.992 ;
     RECT  0.06 13.992 2.293 14.112 ;
     RECT  0.084 14.112 2.293 14.136 ;
     RECT  0.06 14.136 2.293 14.256 ;
     RECT  0.084 14.256 2.293 14.28 ;
     RECT  0.06 14.28 2.293 14.4 ;
     RECT  0.084 14.4 2.293 14.424 ;
     RECT  0.06 14.424 2.293 14.544 ;
     RECT  0.084 14.544 2.293 14.568 ;
     RECT  0.06 14.568 2.293 14.688 ;
     RECT  0.084 14.688 2.293 14.712 ;
     RECT  0.06 14.712 2.293 14.832 ;
     RECT  0.084 14.832 2.293 14.856 ;
     RECT  0.06 14.856 2.293 14.976 ;
     RECT  0.084 14.976 2.293 15 ;
     RECT  0.06 15 2.293 15.12 ;
     RECT  0.084 15.12 2.293 15.144 ;
     RECT  0.06 15.144 2.293 15.264 ;
     RECT  0.084 15.264 2.293 15.288 ;
     RECT  0.06 15.288 2.293 15.408 ;
     RECT  0.084 15.408 2.293 15.432 ;
     RECT  0.06 15.432 2.293 15.552 ;
     RECT  0.084 15.552 2.293 15.576 ;
     RECT  0.06 15.576 2.293 15.696 ;
     RECT  0.084 15.696 2.293 15.72 ;
     RECT  0.06 15.72 2.293 15.84 ;
     RECT  0.084 15.84 2.293 15.864 ;
     RECT  0.06 15.864 2.293 15.984 ;
     RECT  0.084 15.984 2.293 16.008 ;
     RECT  0.06 16.008 2.293 16.128 ;
     RECT  0.084 16.128 2.293 16.152 ;
     RECT  0.06 16.152 2.293 16.272 ;
     RECT  0.084 16.272 2.293 16.296 ;
     RECT  0.06 16.296 2.293 16.416 ;
     RECT  0.084 16.416 2.293 16.44 ;
     RECT  0.06 16.44 2.293 16.56 ;
     RECT  0.084 16.56 2.293 16.584 ;
     RECT  0.06 16.584 2.293 16.704 ;
     RECT  0.084 16.704 2.293 16.728 ;
     RECT  0.06 16.728 2.293 16.848 ;
     RECT  0.084 16.848 2.293 16.872 ;
     RECT  0.06 16.872 2.293 16.992 ;
     RECT  0.084 16.992 2.293 17.016 ;
     RECT  0.06 17.016 2.293 17.136 ;
     RECT  0.084 17.136 2.293 17.16 ;
     RECT  0.06 17.16 2.293 17.28 ;
     RECT  0.084 17.28 2.293 17.304 ;
     RECT  0.06 17.304 2.293 17.424 ;
     RECT  0.084 17.424 2.293 17.448 ;
     RECT  0.06 17.448 2.293 17.568 ;
     RECT  0.084 17.568 2.293 17.592 ;
     RECT  0.06 17.592 2.293 17.712 ;
     RECT  0.084 17.712 2.293 17.736 ;
     RECT  0.06 17.736 2.293 17.856 ;
     RECT  0.084 17.856 2.293 17.88 ;
     RECT  0.06 17.88 2.293 18 ;
     RECT  0.084 18 2.293 18.024 ;
     RECT  0.06 18.024 2.293 18.144 ;
     RECT  0.084 18.144 2.293 18.168 ;
     RECT  0.06 18.168 2.293 18.288 ;
     RECT  0.084 18.288 2.293 18.312 ;
     RECT  0.06 18.312 2.293 18.432 ;
     RECT  0.084 18.432 2.293 18.456 ;
     RECT  0.06 18.456 2.293 18.576 ;
     RECT  0.084 18.576 2.293 18.6 ;
     RECT  0.06 18.6 2.293 18.72 ;
     RECT  0.084 18.72 2.293 18.744 ;
     RECT  0.06 18.744 2.293 18.864 ;
     RECT  0.084 18.864 2.293 18.888 ;
     RECT  0.06 18.888 2.293 19.008 ;
     RECT  0.084 19.008 2.293 19.032 ;
     RECT  0.06 19.032 2.293 19.152 ;
     RECT  0.084 19.152 2.293 19.176 ;
     RECT  0.06 19.176 2.293 19.296 ;
     RECT  0.084 19.296 2.293 19.32 ;
     RECT  0.06 19.32 2.293 19.44 ;
     RECT  0.084 19.44 2.293 19.464 ;
     RECT  0.06 19.464 2.293 19.584 ;
     RECT  0.084 19.584 2.293 19.608 ;
     RECT  0.06 19.608 2.293 19.728 ;
     RECT  0.084 19.728 2.293 19.752 ;
     RECT  0.06 19.752 2.293 19.872 ;
     RECT  0.084 19.872 2.293 19.896 ;
     RECT  0.06 19.896 2.293 20.016 ;
     RECT  0.084 20.016 2.293 20.04 ;
     RECT  0.06 20.04 2.293 20.16 ;
     RECT  0.084 20.16 2.293 20.184 ;
     RECT  0.06 20.184 2.293 20.304 ;
     RECT  0.084 20.304 2.293 20.328 ;
     RECT  0.06 20.328 2.293 20.448 ;
     RECT  0.084 20.448 2.293 20.472 ;
     RECT  0.06 20.472 2.293 20.592 ;
     RECT  0.084 20.592 2.293 20.616 ;
     RECT  0.06 20.616 2.293 20.736 ;
     RECT  0.084 20.736 2.293 20.76 ;
     RECT  2.293 11.76 2.408 20.76 ;
     RECT  0.084 22.032 2.408 22.056 ;
     RECT  0.06 22.056 2.408 22.176 ;
     RECT  0.084 22.176 2.408 22.2 ;
     RECT  0.06 22.2 2.408 22.32 ;
     RECT  0.084 22.32 2.408 22.344 ;
     RECT  0.06 22.344 2.408 22.464 ;
     RECT  0.084 22.464 2.408 22.488 ;
     RECT  0.06 22.488 2.408 22.608 ;
     RECT  0.084 22.608 2.408 22.632 ;
     RECT  0.06 22.632 2.408 22.752 ;
     RECT  0.084 22.752 2.408 22.776 ;
     RECT  0.06 22.776 2.408 22.896 ;
     RECT  0.084 22.896 2.408 22.92 ;
     RECT  0.06 22.92 2.408 23.04 ;
     RECT  0.084 23.04 2.408 23.064 ;
     RECT  0.06 23.064 2.408 23.184 ;
     RECT  0.084 23.184 2.408 23.208 ;
     RECT  0.06 23.208 2.408 23.328 ;
     RECT  0.084 23.328 2.408 23.352 ;
     RECT  0.06 23.352 2.408 23.472 ;
     RECT  0.084 23.472 2.408 23.496 ;
     RECT  0.06 23.496 2.408 23.616 ;
     RECT  0.084 23.616 2.408 23.64 ;
     RECT  0.06 23.64 2.408 23.76 ;
     RECT  0.084 23.76 2.408 23.784 ;
     RECT  0.06 23.784 2.408 23.904 ;
     RECT  0.084 23.904 2.408 23.928 ;
     RECT  0.06 23.928 2.408 24.048 ;
     RECT  0.084 24.048 2.408 24.072 ;
     RECT  0.06 24.072 2.408 24.192 ;
     RECT  0.084 24.192 2.408 24.216 ;
     RECT  0.06 24.216 2.408 24.336 ;
     RECT  0.084 24.336 2.408 24.36 ;
     RECT  0.06 24.36 2.408 24.48 ;
     RECT  0.084 24.48 2.408 24.504 ;
     RECT  0.06 24.504 2.408 24.624 ;
     RECT  0.084 24.624 2.408 24.648 ;
     RECT  0.06 24.648 2.408 24.768 ;
     RECT  0.084 24.768 2.408 24.792 ;
     RECT  0.06 24.792 2.408 24.912 ;
     RECT  0.084 24.912 2.408 24.936 ;
     RECT  0.06 24.936 2.408 25.056 ;
     RECT  0.084 25.056 2.408 25.08 ;
     RECT  0.06 25.08 2.408 25.2 ;
     RECT  0.084 25.2 2.408 25.224 ;
     RECT  0.06 25.224 2.408 25.344 ;
     RECT  0.084 25.344 2.408 25.368 ;
     RECT  0.06 25.368 2.408 25.488 ;
     RECT  0.084 25.488 2.408 25.512 ;
     RECT  0.06 25.512 2.408 25.632 ;
     RECT  0.084 25.632 2.408 25.656 ;
     RECT  0.06 25.656 2.408 25.776 ;
     RECT  0.084 25.776 2.408 25.8 ;
     RECT  0.06 25.8 2.408 25.92 ;
     RECT  0.084 25.92 2.408 25.944 ;
     RECT  0.06 25.944 2.408 26.064 ;
     RECT  0.084 26.064 2.408 26.088 ;
     RECT  0.06 26.088 2.408 26.208 ;
     RECT  0.084 26.208 2.408 26.232 ;
     RECT  0.06 26.232 2.408 26.352 ;
     RECT  0.084 26.352 2.408 26.376 ;
     RECT  0.06 26.376 2.408 26.496 ;
     RECT  0.084 26.496 2.408 26.52 ;
     RECT  0.06 26.52 2.408 26.64 ;
     RECT  0.084 26.64 2.408 26.664 ;
     RECT  0.06 26.664 2.408 26.784 ;
     RECT  0.084 26.784 2.408 26.808 ;
     RECT  0.06 26.808 2.408 26.928 ;
     RECT  0.084 26.928 2.408 26.952 ;
     RECT  0.06 26.952 2.408 27.072 ;
     RECT  0.084 27.072 2.408 27.096 ;
     RECT  0.06 27.096 2.408 27.216 ;
     RECT  0.084 27.216 2.408 27.24 ;
     RECT  0.06 27.24 2.408 27.36 ;
     RECT  0.084 27.36 2.408 27.384 ;
     RECT  0.06 27.384 2.408 27.504 ;
     RECT  0.084 27.504 2.408 27.528 ;
     RECT  0.06 27.528 2.408 27.648 ;
     RECT  0.084 27.648 2.408 27.672 ;
     RECT  0.06 27.672 2.408 27.792 ;
     RECT  0.084 27.792 2.408 27.816 ;
     RECT  0.06 27.816 2.408 27.936 ;
     RECT  0.084 27.936 2.408 27.96 ;
     RECT  0.06 27.96 2.408 28.08 ;
     RECT  0.084 28.08 2.408 28.104 ;
     RECT  0.06 28.104 2.408 28.224 ;
     RECT  0.084 28.224 2.408 28.248 ;
     RECT  0.06 28.248 2.408 28.368 ;
     RECT  0.084 28.368 2.408 28.392 ;
     RECT  0.06 28.392 2.408 28.512 ;
     RECT  0.084 28.512 2.408 28.536 ;
     RECT  0.06 28.536 2.408 28.656 ;
     RECT  0.084 28.656 2.408 28.68 ;
     RECT  0.06 28.68 2.408 28.8 ;
     RECT  0.084 28.8 2.408 28.824 ;
     RECT  0.06 28.824 2.408 28.944 ;
     RECT  0.084 28.944 2.408 28.968 ;
     RECT  0.06 28.968 2.408 29.088 ;
     RECT  0.084 29.088 2.408 29.112 ;
     RECT  0.06 29.112 2.408 29.232 ;
     RECT  0.084 29.232 2.408 29.256 ;
     RECT  0.06 29.256 2.408 29.376 ;
     RECT  0.084 29.376 2.408 29.4 ;
     RECT  0.06 29.4 2.408 29.52 ;
     RECT  0.084 29.52 2.408 29.544 ;
     RECT  0.06 29.544 2.408 29.664 ;
     RECT  0.084 29.664 2.408 29.688 ;
     RECT  0.06 29.688 2.408 29.808 ;
     RECT  0.084 29.808 2.408 29.832 ;
     RECT  0.06 29.832 2.408 29.952 ;
     RECT  0.084 29.952 2.408 29.976 ;
     RECT  0.06 29.976 2.408 30.096 ;
     RECT  0.084 30.096 2.408 30.12 ;
     RECT  0.06 30.12 2.408 30.24 ;
     RECT  0.084 30.24 2.408 30.264 ;
     RECT  0.06 30.264 2.408 30.384 ;
     RECT  0.084 30.384 2.408 30.408 ;
     RECT  0.06 30.408 2.408 30.528 ;
     RECT  0.084 30.528 2.408 30.552 ;
     RECT  0.06 30.552 2.408 30.672 ;
     RECT  0.084 30.672 2.408 30.696 ;
     RECT  0.06 30.696 2.408 30.816 ;
     RECT  0.084 30.816 2.408 30.84 ;
     RECT  0.06 30.84 2.408 30.96 ;
     RECT  0.084 30.96 2.408 30.984 ;
     RECT  0.06 30.984 2.408 31.104 ;
     RECT  0.084 31.104 2.408 31.128 ;
     RECT  0.06 31.128 2.408 31.248 ;
     RECT  0.084 31.248 2.408 31.272 ;
     RECT  0.06 31.272 2.408 31.392 ;
     RECT  0.084 31.392 2.408 31.416 ;
     RECT  0.06 31.416 2.408 31.536 ;
     RECT  0.084 31.536 2.408 31.56 ;
     RECT  0.06 31.56 2.408 31.68 ;
     RECT  0.084 31.68 2.408 31.704 ;
     RECT  0.06 31.704 2.408 31.824 ;
     RECT  0.084 31.824 2.408 31.848 ;
     RECT  0.06 31.848 2.408 31.968 ;
     RECT  0.084 31.968 2.408 31.992 ;
     RECT  0.06 31.992 2.408 32.112 ;
     RECT  0.084 32.112 2.408 32.136 ;
     RECT  0.06 32.136 2.408 32.256 ;
     RECT  0.084 32.256 2.408 32.28 ;
     RECT  0.06 32.28 2.408 32.4 ;
     RECT  0.084 32.4 2.408 32.424 ;
     RECT  0.06 32.424 2.408 32.544 ;
     RECT  0.084 32.544 2.408 32.568 ;
     RECT  0.06 32.568 2.408 32.688 ;
     RECT  0.084 32.688 2.408 32.712 ;
     RECT  0.06 32.712 2.408 32.832 ;
     RECT  0.084 32.832 2.408 32.856 ;
     RECT  0.06 32.856 2.408 32.976 ;
     RECT  0.084 32.976 2.408 33 ;
     RECT  0.06 33 2.408 33.12 ;
     RECT  0.084 33.12 2.408 33.144 ;
     RECT  0.06 33.144 2.408 33.264 ;
     RECT  0.084 33.264 2.408 33.288 ;
     RECT  0.06 33.288 2.408 33.408 ;
     RECT  0.084 33.408 2.408 33.432 ;
     RECT  0.06 33.432 2.408 33.552 ;
     RECT  0.084 33.552 2.408 33.576 ;
     RECT  0.06 33.576 2.408 33.696 ;
     RECT  0.084 33.696 2.408 33.72 ;
     RECT  0.06 33.72 2.408 33.84 ;
     RECT  0.084 33.84 2.408 33.864 ;
     RECT  0.06 33.864 2.408 33.984 ;
     RECT  0.084 33.984 2.408 34.008 ;
     RECT  0.06 34.008 2.408 34.128 ;
     RECT  0.084 34.128 2.408 34.152 ;
     RECT  0.06 34.152 2.408 34.272 ;
     RECT  0.084 34.272 2.408 34.296 ;
     RECT  0.06 34.296 2.408 34.416 ;
     RECT  0.084 34.416 2.408 34.44 ;
     RECT  0.06 34.44 2.408 34.56 ;
     RECT  0.084 34.56 2.408 34.584 ;
     RECT  0.06 34.584 2.408 34.704 ;
     RECT  0.084 34.704 2.408 34.728 ;
     RECT  0.06 34.728 2.408 34.848 ;
     RECT  0.084 34.848 2.408 34.872 ;
     RECT  0.06 34.872 2.408 34.992 ;
     RECT  0.084 34.992 2.408 35.016 ;
     RECT  0.06 35.016 2.408 35.136 ;
     RECT  0.084 35.136 2.408 35.16 ;
     RECT  0.06 35.16 2.408 35.28 ;
     RECT  0.084 35.28 2.408 35.304 ;
     RECT  0.06 35.304 2.408 35.424 ;
     RECT  0.084 35.424 2.408 35.448 ;
     RECT  0.06 35.448 2.408 35.568 ;
     RECT  0.084 35.568 2.408 35.592 ;
     RECT  0.06 35.592 2.408 35.712 ;
     RECT  0.084 35.712 2.408 35.736 ;
     RECT  0.06 35.736 2.408 35.856 ;
     RECT  0.084 35.856 2.408 35.88 ;
     RECT  0.06 35.88 2.408 36 ;
     RECT  0.084 36 2.408 36.024 ;
     RECT  0.06 36.024 2.408 36.144 ;
     RECT  0.084 36.144 2.408 36.168 ;
     RECT  0.06 36.168 2.408 36.288 ;
     RECT  0.084 36.288 2.408 36.312 ;
     RECT  0.06 36.312 2.408 36.432 ;
     RECT  0.084 36.432 2.408 36.456 ;
     RECT  0.06 36.456 2.408 36.576 ;
     RECT  0.084 36.576 2.408 36.6 ;
     RECT  0.06 36.6 2.408 36.72 ;
     RECT  0.084 36.72 2.408 36.744 ;
     RECT  0.06 36.744 2.408 36.864 ;
     RECT  0.084 36.864 2.408 36.888 ;
     RECT  0.06 36.888 2.408 37.008 ;
     RECT  0.084 37.008 2.408 37.032 ;
     RECT  0.06 37.032 2.408 37.152 ;
     RECT  0.084 37.152 2.408 37.176 ;
     RECT  0.06 37.176 2.408 37.296 ;
     RECT  0.084 37.296 2.408 37.32 ;
     RECT  0.06 37.32 2.408 37.44 ;
     RECT  0.084 37.44 2.408 37.464 ;
     RECT  0.06 37.464 2.408 37.584 ;
     RECT  0.084 37.584 2.408 37.608 ;
     RECT  0.06 37.608 2.408 37.728 ;
     RECT  0.084 37.728 2.408 37.752 ;
     RECT  0.06 37.752 2.408 37.872 ;
     RECT  0.084 37.872 2.408 37.896 ;
     RECT  0.06 37.896 2.408 38.016 ;
     RECT  0.084 38.016 2.408 38.04 ;
     RECT  0.06 38.04 2.408 38.16 ;
     RECT  0.084 38.16 2.408 38.184 ;
     RECT  0.06 38.184 2.408 38.304 ;
     RECT  0.084 38.304 2.408 38.328 ;
     RECT  0.06 38.328 2.408 38.448 ;
     RECT  0.084 38.448 2.408 38.472 ;
     RECT  0.06 38.472 2.408 38.592 ;
     RECT  0.084 38.592 2.408 38.616 ;
     RECT  0.06 38.616 2.408 38.736 ;
     RECT  0.084 38.736 2.408 38.76 ;
     RECT  0.06 38.76 2.408 38.88 ;
     RECT  0.084 38.88 2.408 38.904 ;
     RECT  0.06 38.904 2.408 39.024 ;
     RECT  0.084 39.024 2.408 39.048 ;
     RECT  0.06 39.048 2.408 39.168 ;
     RECT  0.084 39.168 2.408 39.192 ;
     RECT  0.06 39.192 2.408 39.312 ;
     RECT  0.084 39.312 2.408 39.336 ;
     RECT  0.06 39.336 2.408 39.456 ;
     RECT  0.084 39.456 2.408 39.48 ;
     RECT  0.06 39.48 2.408 39.6 ;
     RECT  0.084 39.6 2.408 39.624 ;
     RECT  0.06 39.624 2.408 39.744 ;
     RECT  0.084 39.744 2.408 39.768 ;
     RECT  0.06 39.768 2.408 39.888 ;
     RECT  0.084 39.888 2.408 39.912 ;
     RECT  0.06 39.912 2.408 40.032 ;
     RECT  0.084 40.032 2.408 40.056 ;
     RECT  0.06 40.056 2.408 40.176 ;
     RECT  0.084 40.176 2.408 40.2 ;
     RECT  0.06 40.2 2.408 40.32 ;
     RECT  0.084 40.32 2.408 40.344 ;
     RECT  0.06 40.344 2.408 40.464 ;
     RECT  0.084 40.464 2.408 40.488 ;
     RECT  0.06 40.488 2.408 40.608 ;
     RECT  0.084 40.608 2.408 40.632 ;
     RECT  0.06 40.632 2.408 40.752 ;
     RECT  0.084 40.752 2.408 40.776 ;
     RECT  0.06 40.776 2.408 40.896 ;
     RECT  0.084 40.896 2.408 40.92 ;
     RECT  0.06 40.92 2.408 41.04 ;
     RECT  0.084 41.04 2.408 41.064 ;
     RECT  0.06 41.064 2.408 41.184 ;
     RECT  0.084 41.184 2.408 41.208 ;
     RECT  0.06 41.208 2.408 41.328 ;
     RECT  0.084 41.328 2.408 41.352 ;
     RECT  0.06 41.352 2.408 41.472 ;
     RECT  0.084 41.472 2.408 41.496 ;
     RECT  0.06 41.496 2.408 41.616 ;
     RECT  0.084 41.616 2.408 41.64 ;
     RECT  0.06 41.64 2.408 41.76 ;
     RECT  0.084 41.76 2.408 41.784 ;
     RECT  0.06 41.784 2.408 41.904 ;
     RECT  0.084 41.904 2.408 41.928 ;
     RECT  0.06 41.928 2.408 42.048 ;
     RECT  0.084 42.048 2.408 42.072 ;
     RECT  0.06 42.072 2.408 42.192 ;
     RECT  0.084 42.192 2.408 42.216 ;
     RECT  0.06 42.216 2.408 42.336 ;
     RECT  0.084 42.336 2.408 42.36 ;
     RECT  0.06 42.36 2.408 42.48 ;
     RECT  0.084 42.48 2.408 42.504 ;
     RECT  0.06 42.504 2.408 42.624 ;
     RECT  0.084 42.624 2.408 42.648 ;
     RECT  0.06 42.648 2.408 42.768 ;
     RECT  0.084 42.768 2.408 42.792 ;
     RECT  0.06 42.792 2.408 42.912 ;
     RECT  0.084 42.912 2.408 42.936 ;
     RECT  0.06 42.936 2.408 43.056 ;
     RECT  0.084 43.056 2.408 43.08 ;
     RECT  0.06 43.08 2.408 43.2 ;
     RECT  0.084 43.2 2.408 43.224 ;
     RECT  0.06 43.224 2.408 43.344 ;
     RECT  0.084 43.344 2.408 43.368 ;
     RECT  0.06 43.368 2.408 43.488 ;
     RECT  0.084 43.488 2.408 43.512 ;
     RECT  0.06 43.512 2.408 43.632 ;
     RECT  0.084 43.632 2.408 43.656 ;
     RECT  0.06 43.656 2.408 43.776 ;
     RECT  0.084 43.776 2.408 43.8 ;
     RECT  0.06 43.8 2.408 43.92 ;
     RECT  0.084 43.92 2.408 43.944 ;
     RECT  0.06 43.944 2.408 44.064 ;
     RECT  0.084 44.064 2.408 44.088 ;
     RECT  0.06 44.088 2.408 44.208 ;
     RECT  0.084 44.208 2.408 44.232 ;
     RECT  0.06 44.232 2.408 44.352 ;
     RECT  0.084 44.352 2.408 44.376 ;
     RECT  0.06 44.376 2.408 44.496 ;
     RECT  0.084 44.496 2.408 44.52 ;
     RECT  0.06 44.52 2.408 44.64 ;
     RECT  0.084 44.64 2.408 44.664 ;
     RECT  0.06 44.664 2.408 44.784 ;
     RECT  0.084 44.784 2.408 44.808 ;
     RECT  0.06 44.808 2.408 44.928 ;
     RECT  0.084 44.928 2.408 44.952 ;
     RECT  0.06 44.952 2.408 45.072 ;
     RECT  0.084 45.072 2.408 45.096 ;
     RECT  0.06 45.096 2.408 45.216 ;
     RECT  0.084 45.216 2.408 45.24 ;
     RECT  0.06 45.24 2.408 45.36 ;
     RECT  0.084 45.36 2.408 45.384 ;
     RECT  0.06 45.384 2.408 45.504 ;
     RECT  0.084 45.504 2.408 45.528 ;
     RECT  0.06 45.528 2.408 45.648 ;
     RECT  0.084 45.648 2.408 45.672 ;
     RECT  0.06 45.672 2.408 45.792 ;
     RECT  0.084 45.792 2.408 45.816 ;
     RECT  0.06 45.816 2.408 45.936 ;
     RECT  0.084 45.936 2.408 45.96 ;
     RECT  0.06 45.96 2.408 46.08 ;
     RECT  0.084 46.08 2.408 46.104 ;
     RECT  0.06 46.104 2.408 46.224 ;
     RECT  0.084 46.224 2.408 46.248 ;
     RECT  0.06 46.248 2.408 46.368 ;
     RECT  0.084 46.368 2.408 46.392 ;
     RECT  0.06 46.392 2.408 46.512 ;
     RECT  0.084 46.512 2.408 46.536 ;
     RECT  0.06 46.536 2.408 46.656 ;
     RECT  0.084 46.656 2.408 46.68 ;
     RECT  0.06 46.68 2.408 46.8 ;
     RECT  0.084 46.8 2.408 46.824 ;
     RECT  0.06 46.824 2.408 46.944 ;
     RECT  0.084 46.944 2.408 46.968 ;
     RECT  0.06 46.968 2.408 47.088 ;
     RECT  0.084 47.088 2.408 47.112 ;
     RECT  0.06 47.112 2.408 47.232 ;
     RECT  0.084 47.232 2.408 47.256 ;
     RECT  0.06 47.256 2.408 47.376 ;
     RECT  0.084 47.376 2.408 47.4 ;
     RECT  0.06 47.4 2.408 47.52 ;
     RECT  0.084 47.52 2.408 47.544 ;
     RECT  0.06 47.544 2.408 47.664 ;
     RECT  0.084 47.664 2.408 47.688 ;
     RECT  0.06 47.688 2.408 47.808 ;
     RECT  0.084 47.808 2.408 47.832 ;
     RECT  0.06 47.832 2.408 47.952 ;
     RECT  0.084 47.952 2.408 47.976 ;
     RECT  0.06 47.976 2.408 48.096 ;
     RECT  0.084 48.096 2.408 48.12 ;
     RECT  0.06 48.12 2.408 48.24 ;
     RECT  0.084 48.24 2.408 48.264 ;
     RECT  0.06 48.264 2.408 48.384 ;
     RECT  0.084 48.384 2.408 48.408 ;
     RECT  0.06 48.408 2.408 48.528 ;
     RECT  0.084 48.528 2.408 48.552 ;
     RECT  0.06 48.552 2.408 48.672 ;
     RECT  0.084 48.672 2.408 48.696 ;
     RECT  0.06 48.696 2.408 48.816 ;
     RECT  0.084 48.816 2.408 48.84 ;
     RECT  0.06 48.84 2.408 48.96 ;
     RECT  0.084 48.96 2.408 48.984 ;
     RECT  0.06 48.984 2.408 49.104 ;
     RECT  0.084 49.104 2.408 49.128 ;
     RECT  0.06 49.128 2.408 49.248 ;
     RECT  0.084 49.248 2.408 49.272 ;
     RECT  0.06 49.272 2.408 49.392 ;
     RECT  0.084 49.392 2.408 49.416 ;
     RECT  0.06 49.416 2.408 49.536 ;
     RECT  0.084 49.536 2.408 49.56 ;
     RECT  0.097 50.832 2.408 78.456 ;
     RECT  0.084 79.632 2.408 79.656 ;
     RECT  0.06 79.656 2.408 79.776 ;
     RECT  0.084 79.776 2.408 79.8 ;
     RECT  0.06 79.8 2.408 79.92 ;
     RECT  0.084 79.92 2.408 79.944 ;
     RECT  0.06 79.944 2.408 80.064 ;
     RECT  0.084 80.064 2.408 80.088 ;
     RECT  0.06 80.088 2.408 80.208 ;
     RECT  0.084 80.208 2.408 80.232 ;
     RECT  0.06 80.232 2.408 80.352 ;
     RECT  0.084 80.352 2.408 80.376 ;
     RECT  0.06 80.376 2.408 80.496 ;
     RECT  0.084 80.496 2.408 80.52 ;
     RECT  0.06 80.52 2.408 80.64 ;
     RECT  0.084 80.64 2.408 80.664 ;
     RECT  0.06 80.664 2.408 80.784 ;
     RECT  0.084 80.784 2.408 80.808 ;
     RECT  0.06 80.808 2.408 80.928 ;
     RECT  0.084 80.928 2.408 80.952 ;
     RECT  0.06 80.952 2.408 81.072 ;
     RECT  0.084 81.072 2.408 81.096 ;
     RECT  0.06 81.096 2.408 81.216 ;
     RECT  0.084 81.216 2.408 81.24 ;
     RECT  0.06 81.24 2.408 81.36 ;
     RECT  0.084 81.36 2.408 81.384 ;
     RECT  0.06 81.384 2.408 81.504 ;
     RECT  0.084 81.504 2.408 81.528 ;
     RECT  0.06 81.528 2.408 81.648 ;
     RECT  0.084 81.648 2.408 81.672 ;
     RECT  0.06 81.672 2.408 81.792 ;
     RECT  0.084 81.792 2.408 81.816 ;
     RECT  0.06 81.816 2.408 81.936 ;
     RECT  0.084 81.936 2.408 81.96 ;
     RECT  0.06 81.96 2.408 82.08 ;
     RECT  0.084 82.08 2.408 82.104 ;
     RECT  0.06 82.104 2.408 82.224 ;
     RECT  0.084 82.224 2.408 82.248 ;
     RECT  0.06 82.248 2.408 82.368 ;
     RECT  0.084 82.368 2.408 82.392 ;
     RECT  0.06 82.392 2.408 82.512 ;
     RECT  0.084 82.512 2.408 82.536 ;
     RECT  0.06 82.536 2.408 82.656 ;
     RECT  0.084 82.656 2.408 82.68 ;
     RECT  0.06 82.68 2.408 82.8 ;
     RECT  0.084 82.8 2.408 82.824 ;
     RECT  0.06 82.824 2.408 82.944 ;
     RECT  0.084 82.944 2.408 82.968 ;
     RECT  0.06 82.968 2.408 83.088 ;
     RECT  0.084 83.088 2.408 83.112 ;
     RECT  0.06 83.112 2.408 83.232 ;
     RECT  0.084 83.232 2.408 83.256 ;
     RECT  0.06 83.256 2.408 83.376 ;
     RECT  0.084 83.376 2.408 83.4 ;
     RECT  0.06 83.4 2.408 83.52 ;
     RECT  0.084 83.52 2.408 83.544 ;
     RECT  0.06 83.544 2.408 83.664 ;
     RECT  0.084 83.664 2.408 83.688 ;
     RECT  0.06 83.688 2.408 83.808 ;
     RECT  0.084 83.808 2.408 83.832 ;
     RECT  0.06 83.832 2.408 83.952 ;
     RECT  0.084 83.952 2.408 83.976 ;
     RECT  0.06 83.976 2.408 84.096 ;
     RECT  0.084 84.096 2.408 84.12 ;
     RECT  0.06 84.12 2.408 84.24 ;
     RECT  0.084 84.24 2.408 84.264 ;
     RECT  0.06 84.264 2.408 84.384 ;
     RECT  0.084 84.384 2.408 84.408 ;
     RECT  0.06 84.408 2.408 84.528 ;
     RECT  0.084 84.528 2.408 84.552 ;
     RECT  0.06 84.552 2.408 84.672 ;
     RECT  0.084 84.672 2.408 84.696 ;
     RECT  0.06 84.696 2.408 84.816 ;
     RECT  0.084 84.816 2.408 84.84 ;
     RECT  0.06 84.84 2.408 84.96 ;
     RECT  0.084 84.96 2.408 84.984 ;
     RECT  0.06 84.984 2.408 85.104 ;
     RECT  0.084 85.104 2.408 85.128 ;
     RECT  0.06 85.128 2.408 85.248 ;
     RECT  0.084 85.248 2.408 85.272 ;
     RECT  0.06 85.272 2.408 85.392 ;
     RECT  0.084 85.392 2.408 85.416 ;
     RECT  0.06 85.416 2.408 85.536 ;
     RECT  0.084 85.536 2.408 85.56 ;
     RECT  0.06 85.56 2.408 85.68 ;
     RECT  0.084 85.68 2.408 85.704 ;
     RECT  0.06 85.704 2.408 85.824 ;
     RECT  0.084 85.824 2.408 85.848 ;
     RECT  0.06 85.848 2.408 85.968 ;
     RECT  0.084 85.968 2.408 85.992 ;
     RECT  0.06 85.992 2.408 86.112 ;
     RECT  0.084 86.112 2.408 86.136 ;
     RECT  0.06 86.136 2.408 86.256 ;
     RECT  0.084 86.256 2.408 86.28 ;
     RECT  0.06 86.28 2.408 86.4 ;
     RECT  0.084 86.4 2.408 86.424 ;
     RECT  0.06 86.424 2.408 86.544 ;
     RECT  0.084 86.544 2.408 86.568 ;
     RECT  0.06 86.568 2.408 86.688 ;
     RECT  0.084 86.688 2.408 86.712 ;
     RECT  0.06 86.712 2.408 86.832 ;
     RECT  0.084 86.832 2.408 86.856 ;
     RECT  0.06 86.856 2.408 86.976 ;
     RECT  0.084 86.976 2.408 87 ;
     RECT  0.06 87 2.408 87.12 ;
     RECT  0.084 87.12 2.408 87.144 ;
     RECT  0.06 87.144 2.408 87.264 ;
     RECT  0.084 87.264 2.408 87.288 ;
     RECT  0.06 87.288 2.408 87.408 ;
     RECT  0.084 87.408 2.408 87.432 ;
     RECT  0.06 87.432 2.408 87.552 ;
     RECT  0.084 87.552 2.408 87.576 ;
     RECT  0.06 87.576 2.408 87.696 ;
     RECT  0.084 87.696 2.408 87.72 ;
     RECT  0.06 87.72 2.408 87.84 ;
     RECT  0.084 87.84 2.408 87.864 ;
     RECT  0.06 87.864 2.408 87.984 ;
     RECT  0.084 87.984 2.408 88.008 ;
     RECT  0.06 88.008 2.408 88.128 ;
     RECT  0.084 88.128 2.408 88.152 ;
     RECT  0.06 88.152 2.408 88.272 ;
     RECT  0.084 88.272 2.408 88.296 ;
     RECT  0.06 88.296 2.408 88.416 ;
     RECT  0.084 88.416 2.408 88.44 ;
     RECT  0.06 88.44 2.408 88.56 ;
     RECT  0.084 88.56 2.408 88.584 ;
     RECT  0.06 88.584 2.408 88.704 ;
     RECT  0.084 88.704 2.408 88.728 ;
     RECT  0.06 88.728 2.408 88.848 ;
     RECT  0.084 88.848 2.408 88.872 ;
     RECT  0.06 88.872 2.408 88.992 ;
     RECT  0.084 88.992 2.408 89.016 ;
     RECT  0.06 89.016 2.408 89.136 ;
     RECT  0.084 89.136 2.408 89.16 ;
     RECT  0.06 89.16 2.408 89.28 ;
     RECT  0.084 89.28 2.408 89.304 ;
     RECT  0.06 89.304 2.408 89.424 ;
     RECT  0.084 89.424 2.408 89.448 ;
     RECT  0.06 89.448 2.408 89.568 ;
     RECT  0.084 89.568 2.408 89.592 ;
     RECT  0.06 89.592 2.408 89.712 ;
     RECT  0.084 89.712 2.408 89.736 ;
     RECT  0.06 89.736 2.408 89.856 ;
     RECT  0.084 89.856 2.408 89.88 ;
     RECT  0.06 89.88 2.408 90 ;
     RECT  0.084 90 2.408 90.024 ;
     RECT  0.06 90.024 2.408 90.144 ;
     RECT  0.084 90.144 2.408 90.168 ;
     RECT  0.06 90.168 2.408 90.288 ;
     RECT  0.084 90.288 2.408 90.312 ;
     RECT  0.06 90.312 2.408 90.432 ;
     RECT  0.084 90.432 2.408 90.456 ;
     RECT  0.06 90.456 2.408 90.576 ;
     RECT  0.084 90.576 2.408 90.6 ;
     RECT  0.06 90.6 2.408 90.72 ;
     RECT  0.084 90.72 2.408 90.744 ;
     RECT  0.06 90.744 2.408 90.864 ;
     RECT  0.084 90.864 2.408 90.888 ;
     RECT  0.06 90.888 2.408 91.008 ;
     RECT  0.084 91.008 2.408 91.032 ;
     RECT  0.06 91.032 2.408 91.152 ;
     RECT  0.084 91.152 2.408 91.176 ;
     RECT  0.06 91.176 2.408 91.296 ;
     RECT  0.084 91.296 2.408 91.32 ;
     RECT  0.06 91.32 2.408 91.44 ;
     RECT  0.084 91.44 2.408 91.464 ;
     RECT  0.06 91.464 2.408 91.584 ;
     RECT  0.084 91.584 2.408 91.608 ;
     RECT  0.06 91.608 2.408 91.728 ;
     RECT  0.084 91.728 2.408 91.752 ;
     RECT  0.06 91.752 2.408 91.872 ;
     RECT  0.084 91.872 2.408 91.896 ;
     RECT  0.06 91.896 2.408 92.016 ;
     RECT  0.084 92.016 2.408 92.04 ;
     RECT  0.06 92.04 2.408 92.16 ;
     RECT  0.084 92.16 2.408 92.184 ;
     RECT  0.06 92.184 2.408 92.304 ;
     RECT  0.084 92.304 2.408 92.328 ;
     RECT  0.06 92.328 2.408 92.448 ;
     RECT  0.084 92.448 2.408 92.472 ;
     RECT  0.06 92.472 2.408 92.592 ;
     RECT  0.084 92.592 2.408 92.616 ;
     RECT  0.06 92.616 2.408 92.736 ;
     RECT  0.084 92.736 2.408 92.76 ;
     RECT  0.06 92.76 2.408 92.88 ;
     RECT  0.084 92.88 2.408 92.904 ;
     RECT  0.06 92.904 2.408 93.024 ;
     RECT  0.084 93.024 2.408 93.048 ;
     RECT  0.06 93.048 2.408 93.168 ;
     RECT  0.084 93.168 2.408 93.192 ;
     RECT  0.06 93.192 2.408 93.312 ;
     RECT  0.084 93.312 2.408 93.336 ;
     RECT  0.06 93.336 2.408 93.456 ;
     RECT  0.084 93.456 2.408 93.48 ;
     RECT  0.06 93.48 2.408 93.6 ;
     RECT  0.084 93.6 2.408 93.624 ;
     RECT  0.06 93.624 2.408 93.744 ;
     RECT  0.084 93.744 2.408 93.768 ;
     RECT  0.06 93.768 2.408 93.888 ;
     RECT  0.084 93.888 2.408 93.912 ;
     RECT  0.06 93.912 2.408 94.032 ;
     RECT  0.084 94.032 2.408 94.056 ;
     RECT  0.06 94.056 2.408 94.176 ;
     RECT  0.084 94.176 2.408 94.2 ;
     RECT  0.06 94.2 2.408 94.32 ;
     RECT  0.084 94.32 2.408 94.344 ;
     RECT  0.06 94.344 2.408 94.464 ;
     RECT  0.084 94.464 2.408 94.488 ;
     RECT  0.06 94.488 2.408 94.608 ;
     RECT  0.084 94.608 2.408 94.632 ;
     RECT  0.06 94.632 2.408 94.752 ;
     RECT  0.084 94.752 2.408 94.776 ;
     RECT  0.06 94.776 2.408 94.896 ;
     RECT  0.084 94.896 2.408 94.92 ;
     RECT  0.06 94.92 2.408 95.04 ;
     RECT  0.084 95.04 2.408 95.064 ;
     RECT  0.06 95.064 2.408 95.184 ;
     RECT  0.084 95.184 2.408 95.208 ;
     RECT  0.06 95.208 2.408 95.328 ;
     RECT  0.084 95.328 2.408 95.352 ;
     RECT  0.06 95.352 2.408 95.472 ;
     RECT  0.084 95.472 2.408 95.496 ;
     RECT  0.06 95.496 2.408 95.616 ;
     RECT  0.084 95.616 2.408 95.64 ;
     RECT  0.06 95.64 2.408 95.76 ;
     RECT  0.084 95.76 2.408 95.784 ;
     RECT  0.06 95.784 2.408 95.904 ;
     RECT  0.084 95.904 2.408 95.928 ;
     RECT  0.06 95.928 2.408 96.048 ;
     RECT  0.084 96.048 2.408 96.072 ;
     RECT  0.06 96.072 2.408 96.192 ;
     RECT  0.084 96.192 2.408 96.216 ;
     RECT  0.06 96.216 2.408 96.336 ;
     RECT  0.084 96.336 2.408 96.36 ;
     RECT  0.06 96.36 2.408 96.48 ;
     RECT  0.084 96.48 2.408 96.504 ;
     RECT  0.06 96.504 2.408 96.624 ;
     RECT  0.084 96.624 2.408 96.648 ;
     RECT  0.06 96.648 2.408 96.768 ;
     RECT  0.084 96.768 2.408 96.792 ;
     RECT  0.06 96.792 2.408 96.912 ;
     RECT  0.084 96.912 2.408 96.936 ;
     RECT  0.06 96.936 2.408 97.056 ;
     RECT  0.084 97.056 2.408 97.08 ;
     RECT  0.06 97.08 2.408 97.2 ;
     RECT  0.084 97.2 2.408 97.224 ;
     RECT  0.06 97.224 2.408 97.344 ;
     RECT  0.084 97.344 2.408 97.368 ;
     RECT  0.06 97.368 2.408 97.488 ;
     RECT  0.084 97.488 2.408 97.512 ;
     RECT  0.06 97.512 2.408 97.632 ;
     RECT  0.084 97.632 2.408 97.656 ;
     RECT  0.06 97.656 2.408 97.776 ;
     RECT  0.084 97.776 2.408 97.8 ;
     RECT  0.06 97.8 2.408 97.92 ;
     RECT  0.084 97.92 2.408 97.944 ;
     RECT  2.408 2.148 2.512 105.852 ;
     RECT  2.512 2.418 2.704 105.582 ;
     RECT  2.704 12.048 2.819 20.856 ;
     RECT  2.704 22.32 2.873 78.36 ;
     RECT  2.704 79.776 2.945 98.184 ;
     RECT  2.819 12.24 2.981 20.856 ;
     RECT  2.981 13.392 3.269 20.856 ;
     RECT  2.945 79.824 3.269 98.184 ;
     RECT  2.981 12.24 3.305 12.264 ;
     RECT  3.269 13.584 3.413 20.856 ;
     RECT  3.269 98.16 3.593 98.184 ;
     RECT  3.413 13.968 3.737 20.856 ;
     RECT  3.737 13.968 4.061 16.872 ;
     RECT  3.269 79.824 4.061 96.792 ;
     RECT  4.061 92.784 4.097 96.792 ;
     RECT  3.737 18.288 4.133 20.856 ;
     RECT  4.061 13.968 5.108 14.424 ;
     RECT  4.061 15.456 5.108 16.872 ;
     RECT  4.133 18.288 5.108 20.04 ;
     RECT  4.981 21.12 5.108 21.144 ;
     RECT  2.873 22.32 5.108 23.064 ;
     RECT  2.873 24.192 5.108 78.36 ;
     RECT  4.061 80.256 5.108 91.464 ;
     RECT  4.097 93.024 5.108 96.792 ;
     RECT  5.108 2.148 5.212 105.852 ;
     RECT  5.212 2.418 5.404 105.582 ;
     RECT  5.404 25.104 5.555 28.44 ;
     RECT  5.404 69.696 5.555 78.888 ;
     RECT  5.404 40.944 5.603 68.616 ;
     RECT  5.603 40.944 5.644 68.184 ;
     RECT  5.555 74.304 5.645 78.888 ;
     RECT  5.404 86.064 5.645 90.6 ;
     RECT  5.645 74.4 5.717 78.888 ;
     RECT  5.717 74.4 5.843 76.968 ;
     RECT  5.404 35.76 5.897 39.816 ;
     RECT  5.404 15.36 6.005 18.84 ;
     RECT  5.404 79.968 6.185 84.84 ;
     RECT  6.185 83.136 6.22 84.84 ;
     RECT  5.843 74.4 6.221 76.776 ;
     RECT  5.717 77.952 6.227 78.888 ;
     RECT  6.005 15.36 6.293 18.216 ;
     RECT  6.185 79.968 6.293 82.104 ;
     RECT  5.645 86.064 6.293 90.072 ;
     RECT  5.555 25.104 6.397 27.336 ;
     RECT  6.293 79.968 6.467 81.288 ;
     RECT  5.644 40.944 6.469 67.8 ;
     RECT  5.404 94.32 6.469 94.344 ;
     RECT  5.555 28.32 6.476 28.44 ;
     RECT  6.476 28.32 6.505 28.824 ;
     RECT  5.404 29.808 6.505 34.584 ;
     RECT  5.404 95.76 6.515 96.408 ;
     RECT  5.404 92.16 6.517 93.336 ;
     RECT  6.469 94.32 6.517 94.44 ;
     RECT  6.517 92.16 6.541 94.68 ;
     RECT  6.505 28.32 6.545 34.584 ;
     RECT  6.221 74.4 6.545 75.48 ;
     RECT  6.293 86.544 6.563 90.072 ;
     RECT  6.293 15.456 6.581 18.216 ;
     RECT  5.404 19.92 6.617 21.576 ;
     RECT  6.541 97.488 6.625 97.512 ;
     RECT  5.404 12.336 6.649 13.656 ;
     RECT  6.545 28.416 6.649 34.584 ;
     RECT  5.897 35.76 6.649 38.952 ;
     RECT  5.555 69.696 6.721 73.272 ;
     RECT  6.563 88.656 6.721 90.072 ;
     RECT  5.404 23.328 6.757 23.352 ;
     RECT  6.721 69.504 6.757 73.272 ;
     RECT  6.397 25.056 6.803 27.336 ;
     RECT  6.541 91.68 6.803 94.68 ;
     RECT  6.469 40.368 6.829 67.8 ;
     RECT  6.757 68.784 6.829 73.272 ;
     RECT  6.649 12.336 6.833 14.232 ;
     RECT  6.721 88.656 6.865 90.552 ;
     RECT  6.803 91.68 6.865 92.28 ;
     RECT  6.829 40.368 6.973 73.272 ;
     RECT  6.545 74.4 6.973 75.24 ;
     RECT  6.757 23.328 7.148 23.976 ;
     RECT  6.617 20.544 7.189 21.576 ;
     RECT  7.148 22.704 7.189 23.976 ;
     RECT  6.803 25.056 7.189 27.144 ;
     RECT  6.515 96.336 7.261 96.408 ;
     RECT  6.221 76.464 7.405 76.776 ;
     RECT  6.649 28.416 7.429 38.952 ;
     RECT  6.973 40.368 7.429 75.24 ;
     RECT  6.22 83.76 7.441 84.84 ;
     RECT  6.467 79.968 7.513 80.328 ;
     RECT  7.429 28.416 7.541 75.24 ;
     RECT  7.513 79.728 7.573 80.328 ;
     RECT  7.333 81.504 7.573 81.528 ;
     RECT  6.563 86.544 7.649 87.096 ;
     RECT  6.865 88.656 7.649 92.28 ;
     RECT  6.833 12.336 7.808 12.6 ;
     RECT  6.833 13.632 7.808 14.232 ;
     RECT  6.581 15.456 7.808 15.912 ;
     RECT  6.581 17.088 7.808 18.216 ;
     RECT  7.189 20.544 7.808 21.672 ;
     RECT  7.189 22.704 7.808 27.144 ;
     RECT  7.541 28.416 7.808 75.336 ;
     RECT  7.405 76.464 7.808 76.968 ;
     RECT  6.227 77.952 7.808 78.12 ;
     RECT  7.573 79.728 7.808 81.528 ;
     RECT  7.441 83.76 7.808 85.464 ;
     RECT  7.649 86.544 7.808 92.28 ;
     RECT  6.803 93.264 7.808 94.68 ;
     RECT  7.261 96.336 7.808 96.984 ;
     RECT  7.808 2.148 7.912 105.852 ;
     RECT  7.912 2.418 8.104 105.582 ;
     RECT  8.104 39.84 8.201 78.12 ;
     RECT  8.104 89.664 8.201 93.768 ;
     RECT  8.104 82.128 8.243 83.112 ;
     RECT  8.104 79.824 8.381 80.952 ;
     RECT  8.104 19.92 8.387 22.248 ;
     RECT  8.201 40.32 8.489 78.12 ;
     RECT  8.104 12.336 8.525 15.384 ;
     RECT  8.489 43.536 8.525 78.12 ;
     RECT  8.201 91.44 8.572 93.768 ;
     RECT  8.525 14.544 8.597 15.384 ;
     RECT  8.525 70.032 8.597 78.12 ;
     RECT  8.381 79.824 8.723 80.424 ;
     RECT  8.104 17.616 8.741 18.264 ;
     RECT  8.104 25.68 8.741 37.608 ;
     RECT  8.597 70.08 8.764 78.12 ;
     RECT  8.104 96.912 8.785 97.56 ;
     RECT  8.764 70.08 8.813 77.064 ;
     RECT  8.741 18.048 8.921 18.264 ;
     RECT  8.741 25.68 8.921 27.672 ;
     RECT  8.785 97.488 8.921 97.56 ;
     RECT  8.764 78.096 8.957 78.12 ;
     RECT  8.243 82.656 9.011 83.112 ;
     RECT  8.572 92.976 9.029 93.768 ;
     RECT  8.741 28.944 9.059 37.608 ;
     RECT  8.921 26.496 9.065 27.672 ;
     RECT  9.059 30.096 9.097 37.608 ;
     RECT  8.387 19.92 9.109 20.904 ;
     RECT  8.104 84.576 9.133 85.512 ;
     RECT  9.097 30.096 9.169 37.992 ;
     RECT  9.065 26.496 9.203 27.336 ;
     RECT  9.133 84.576 9.241 86.04 ;
     RECT  8.489 40.32 9.281 42.552 ;
     RECT  9.109 19.104 9.299 20.904 ;
     RECT  9.029 93.504 9.299 93.528 ;
     RECT  9.169 30.096 9.313 38.808 ;
     RECT  9.281 40.32 9.353 40.584 ;
     RECT  9.241 84.336 9.353 86.04 ;
     RECT  8.525 12.336 9.395 12.936 ;
     RECT  8.201 89.664 9.397 90.072 ;
     RECT  8.572 91.44 9.397 91.704 ;
     RECT  8.104 87.168 9.421 88.68 ;
     RECT  9.397 89.664 9.421 91.704 ;
     RECT  8.597 15.36 9.443 15.384 ;
     RECT  9.281 41.616 9.443 42.552 ;
     RECT  9.353 85.488 9.443 86.04 ;
     RECT  9.299 19.104 9.461 19.128 ;
     RECT  9.313 30.096 9.461 38.856 ;
     RECT  8.525 43.536 9.484 68.808 ;
     RECT  9.421 87.168 9.484 91.704 ;
     RECT  8.104 16.56 9.497 16.584 ;
     RECT  9.443 41.712 9.497 42.552 ;
     RECT  8.387 22.224 9.541 22.248 ;
     RECT  9.443 86.016 9.685 86.04 ;
     RECT  9.484 87.168 9.685 89.688 ;
     RECT  9.497 41.76 9.781 42.552 ;
     RECT  9.484 43.536 9.781 68.52 ;
     RECT  9.5 24.096 9.829 24.12 ;
     RECT  9.461 32.448 9.997 38.856 ;
     RECT  8.104 95.76 9.997 95.784 ;
     RECT  8.921 97.536 10.069 97.56 ;
     RECT  9.829 24.096 10.117 24.936 ;
     RECT  9.059 28.944 10.141 29.112 ;
     RECT  9.461 30.096 10.141 31.32 ;
     RECT  9.395 12.336 10.508 12.36 ;
     RECT  9.601 14.256 10.508 14.28 ;
     RECT  8.921 18.048 10.508 18.072 ;
     RECT  9.299 20.88 10.508 20.904 ;
     RECT  9.541 22.224 10.508 22.68 ;
     RECT  10.117 24.096 10.508 24.984 ;
     RECT  9.203 26.496 10.508 27.144 ;
     RECT  10.141 28.944 10.508 31.32 ;
     RECT  9.997 32.448 10.508 38.952 ;
     RECT  9.353 40.32 10.508 40.392 ;
     RECT  9.781 41.76 10.508 68.52 ;
     RECT  8.813 70.08 10.508 75.96 ;
     RECT  8.813 77.04 10.508 77.064 ;
     RECT  8.723 80.4 10.508 80.424 ;
     RECT  9.011 83.088 10.508 83.112 ;
     RECT  9.353 84.336 10.508 84.36 ;
     RECT  9.685 86.016 10.508 89.688 ;
     RECT  9.484 91.44 10.508 91.704 ;
     RECT  9.889 94.656 10.508 94.68 ;
     RECT  9.997 95.76 10.508 96.36 ;
     RECT  10.069 97.488 10.508 97.56 ;
     RECT  10.508 2.148 10.612 105.852 ;
     RECT  10.612 2.418 10.804 105.582 ;
     RECT  10.804 31.488 10.829 31.512 ;
     RECT  10.804 36.816 10.829 37.416 ;
     RECT  10.804 73.872 10.829 74.136 ;
     RECT  10.804 43.584 10.931 58.728 ;
     RECT  10.829 74.016 10.931 74.136 ;
     RECT  10.804 77.04 11.027 77.064 ;
     RECT  10.804 41.76 11.045 42.552 ;
     RECT  10.931 43.824 11.045 58.728 ;
     RECT  10.804 88.368 11.075 88.392 ;
     RECT  11.045 58.416 11.117 58.728 ;
     RECT  10.829 36.816 11.369 36.936 ;
     RECT  10.804 60.288 11.797 63.096 ;
     RECT  10.804 64.32 11.797 66.504 ;
     RECT  10.804 33.792 12.445 33.816 ;
     RECT  10.931 74.016 12.481 74.088 ;
     RECT  12.445 33.792 12.553 34.056 ;
     RECT  10.804 10.08 13.208 10.104 ;
     RECT  10.804 12.336 13.208 12.84 ;
     RECT  10.804 24.912 13.208 24.984 ;
     RECT  10.804 27.12 13.208 27.144 ;
     RECT  10.804 30.096 13.208 30.12 ;
     RECT  12.553 33.792 13.208 34.248 ;
     RECT  11.369 36.816 13.208 36.84 ;
     RECT  11.045 41.904 13.208 42.552 ;
     RECT  11.045 43.824 13.208 57.432 ;
     RECT  11.797 60.288 13.208 66.504 ;
     RECT  10.804 70.8 13.208 70.824 ;
     RECT  10.804 71.856 13.208 71.88 ;
     RECT  12.481 73.872 13.208 74.088 ;
     RECT  10.804 75.936 13.208 75.96 ;
     RECT  12.229 83.568 13.208 83.592 ;
     RECT  13.208 2.148 13.312 105.852 ;
     RECT  13.312 2.418 13.504 105.582 ;
     RECT  13.504 41.904 14.284 52.248 ;
     RECT  13.504 60.288 14.573 60.84 ;
     RECT  13.504 53.28 14.609 54.36 ;
     RECT  14.609 54.336 14.821 54.36 ;
     RECT  13.504 55.536 14.821 56.328 ;
     RECT  13.504 71.856 14.821 71.88 ;
     RECT  13.504 36.816 14.857 36.84 ;
     RECT  14.284 41.904 14.861 42.072 ;
     RECT  14.821 71.856 14.861 71.976 ;
     RECT  14.821 38.784 14.933 38.808 ;
     RECT  14.821 54.336 14.933 56.328 ;
     RECT  13.504 10.08 15.908 10.104 ;
     RECT  13.504 12.336 15.908 12.84 ;
     RECT  13.504 24.912 15.908 24.984 ;
     RECT  13.504 27.12 15.908 27.144 ;
     RECT  13.504 30.096 15.908 30.12 ;
     RECT  13.504 34.128 15.908 34.152 ;
     RECT  14.857 36.816 15.908 36.888 ;
     RECT  14.861 41.904 15.908 41.976 ;
     RECT  14.284 43.824 15.908 52.248 ;
     RECT  14.609 53.28 15.908 53.304 ;
     RECT  14.933 54.336 15.908 54.36 ;
     RECT  14.933 55.68 15.908 56.328 ;
     RECT  13.504 57.312 15.908 57.336 ;
     RECT  14.573 60.288 15.908 60.648 ;
     RECT  13.504 62.16 15.908 66.504 ;
     RECT  13.504 70.8 15.908 70.824 ;
     RECT  14.861 71.952 15.908 71.976 ;
     RECT  13.504 73.872 15.908 74.088 ;
     RECT  13.504 75.936 15.908 75.96 ;
     RECT  13.504 83.568 15.908 83.592 ;
     RECT  15.908 2.148 16.012 105.852 ;
     RECT  16.012 2.418 16.204 105.582 ;
     RECT  16.204 90 16.265 90.024 ;
     RECT  16.204 43.248 16.589 52.056 ;
     RECT  16.204 80.928 16.643 80.952 ;
     RECT  16.204 32.832 16.739 34.152 ;
     RECT  16.204 53.28 17.129 54.36 ;
     RECT  16.204 58.704 17.197 59.208 ;
     RECT  16.204 60.288 17.197 60.648 ;
     RECT  16.204 68.88 17.233 68.904 ;
     RECT  17.233 68.4 17.345 68.904 ;
     RECT  16.204 70.704 17.413 70.824 ;
     RECT  16.204 71.952 17.413 71.976 ;
     RECT  17.197 58.704 17.417 60.648 ;
     RECT  16.204 62.544 17.521 66.552 ;
     RECT  17.417 59.808 17.525 60.648 ;
     RECT  17.521 62.544 17.557 67.272 ;
     RECT  17.345 68.4 17.557 68.76 ;
     RECT  17.557 62.544 17.603 68.76 ;
     RECT  17.413 70.704 17.605 71.976 ;
     RECT  16.204 24.912 18.313 24.984 ;
     RECT  16.204 10.08 18.608 10.104 ;
     RECT  16.204 12.336 18.608 12.84 ;
     RECT  18.313 24.624 18.608 24.984 ;
     RECT  16.204 27.12 18.608 27.144 ;
     RECT  16.204 30.096 18.608 30.12 ;
     RECT  16.739 32.832 18.608 33.624 ;
     RECT  16.204 36.816 18.608 36.936 ;
     RECT  16.204 41.904 18.608 41.976 ;
     RECT  16.589 43.824 18.608 52.056 ;
     RECT  17.129 53.28 18.608 53.544 ;
     RECT  16.204 55.68 18.608 56.328 ;
     RECT  16.204 57.312 18.608 57.336 ;
     RECT  17.417 58.704 18.608 58.824 ;
     RECT  17.525 60.288 18.608 60.648 ;
     RECT  17.603 62.544 18.608 67.656 ;
     RECT  17.603 68.736 18.608 68.76 ;
     RECT  17.605 70.608 18.608 71.976 ;
     RECT  16.204 73.584 18.608 74.088 ;
     RECT  16.204 75.936 18.608 75.96 ;
     RECT  16.204 82.224 18.608 82.248 ;
     RECT  16.204 83.568 18.608 83.592 ;
     RECT  18.608 2.148 18.712 105.852 ;
     RECT  18.712 2.418 18.904 105.582 ;
     RECT  18.904 59.04 19.073 59.064 ;
     RECT  18.904 41.904 19.801 42.216 ;
     RECT  18.904 57.312 20.261 57.336 ;
     RECT  18.904 71.856 21.085 71.88 ;
     RECT  18.904 10.08 21.308 10.104 ;
     RECT  18.904 12.336 21.308 12.84 ;
     RECT  18.904 24.624 21.308 24.984 ;
     RECT  18.904 27.12 21.308 27.144 ;
     RECT  18.904 30.096 21.308 30.12 ;
     RECT  18.904 31.392 21.308 31.416 ;
     RECT  18.904 32.832 21.308 33.624 ;
     RECT  18.904 36.816 21.308 36.936 ;
     RECT  19.801 41.904 21.308 42.072 ;
     RECT  18.904 44.688 21.308 52.056 ;
     RECT  18.904 53.28 21.308 53.544 ;
     RECT  18.904 55.68 21.308 56.328 ;
     RECT  18.904 60.288 21.308 60.552 ;
     RECT  18.904 62.544 21.308 66.552 ;
     RECT  18.904 67.632 21.308 68.76 ;
     RECT  18.904 69.984 21.308 70.824 ;
     RECT  21.085 71.856 21.308 71.976 ;
     RECT  18.904 73.584 21.308 74.088 ;
     RECT  18.904 75.936 21.308 75.96 ;
     RECT  18.904 82.224 21.308 82.248 ;
     RECT  18.904 83.568 21.308 83.592 ;
     RECT  21.308 2.148 21.412 105.852 ;
     RECT  21.412 2.418 21.604 105.582 ;
     RECT  21.604 69.984 21.953 70.824 ;
     RECT  21.604 41.904 22.669 42.072 ;
     RECT  21.604 60.528 22.813 60.552 ;
     RECT  21.604 36.816 22.844 36.936 ;
     RECT  21.604 44.688 22.844 52.056 ;
     RECT  21.604 53.28 22.844 53.544 ;
     RECT  21.604 73.776 22.885 74.088 ;
     RECT  21.604 32.832 22.921 33.576 ;
     RECT  22.844 44.688 22.925 53.544 ;
     RECT  22.844 36.816 22.931 37.512 ;
     RECT  22.925 48.192 22.931 53.544 ;
     RECT  22.925 44.688 22.961 47.16 ;
     RECT  22.885 72.96 22.972 74.088 ;
     RECT  21.604 55.68 23.029 56.328 ;
     RECT  22.813 58.224 23.137 58.248 ;
     RECT  22.813 60.528 23.137 60.648 ;
     RECT  21.953 69.984 23.137 70.632 ;
     RECT  21.604 71.952 23.137 71.976 ;
     RECT  21.604 27.12 23.209 27.144 ;
     RECT  21.604 24.624 23.221 24.984 ;
     RECT  23.029 55.68 23.276 57.048 ;
     RECT  21.604 12.336 23.281 12.84 ;
     RECT  22.921 32.784 23.317 33.576 ;
     RECT  22.931 53.28 23.317 53.544 ;
     RECT  23.276 54.816 23.317 57.048 ;
     RECT  23.209 27.12 23.353 27.384 ;
     RECT  23.317 59.424 23.353 59.448 ;
     RECT  23.137 60.528 23.353 61.08 ;
     RECT  21.604 62.544 23.365 66.552 ;
     RECT  22.972 73.776 23.389 74.088 ;
     RECT  21.604 82.224 23.42 82.248 ;
     RECT  23.317 88.944 23.42 89.496 ;
     RECT  21.604 31.392 23.425 31.416 ;
     RECT  23.221 26.112 23.461 26.136 ;
     RECT  23.353 27.12 23.461 27.672 ;
     RECT  22.669 41.904 23.461 42.84 ;
     RECT  21.604 83.568 23.461 83.592 ;
     RECT  23.42 88.032 23.461 89.496 ;
     RECT  23.221 23.328 23.557 23.352 ;
     RECT  23.389 73.776 23.557 74.184 ;
     RECT  23.557 22.656 23.677 23.352 ;
     RECT  23.137 69.984 23.677 71.976 ;
     RECT  23.557 73.776 23.713 74.568 ;
     RECT  23.317 91.056 23.749 91.08 ;
     RECT  21.604 30.096 23.756 30.12 ;
     RECT  23.425 31.2 23.756 31.416 ;
     RECT  23.677 22.464 23.785 23.352 ;
     RECT  23.756 30.096 23.785 31.416 ;
     RECT  23.749 91.056 23.821 91.128 ;
     RECT  23.461 41.904 23.852 43.176 ;
     RECT  22.961 44.688 23.852 47.112 ;
     RECT  23.785 22.032 23.893 23.352 ;
     RECT  23.365 62.256 23.893 66.552 ;
     RECT  23.852 41.904 23.965 47.112 ;
     RECT  22.931 48.192 23.965 52.2 ;
     RECT  23.893 62.16 23.965 66.552 ;
     RECT  23.821 90.864 23.965 91.128 ;
     RECT  21.604 10.08 24.008 10.104 ;
     RECT  23.281 11.952 24.008 12.84 ;
     RECT  23.317 15.84 24.008 15.864 ;
     RECT  23.353 17.616 24.008 17.64 ;
     RECT  23.317 18.816 24.008 18.84 ;
     RECT  23.893 21.504 24.008 23.352 ;
     RECT  23.221 24.624 24.008 25.08 ;
     RECT  23.461 26.112 24.008 27.672 ;
     RECT  23.785 30.048 24.008 31.416 ;
     RECT  23.317 32.784 24.008 34.152 ;
     RECT  22.931 36.816 24.008 36.936 ;
     RECT  22.885 38.736 24.008 38.76 ;
     RECT  23.965 41.376 24.008 52.2 ;
     RECT  23.317 53.28 24.008 57.048 ;
     RECT  23.137 58.224 24.008 58.392 ;
     RECT  23.353 59.424 24.008 61.08 ;
     RECT  23.965 62.16 24.008 66.6 ;
     RECT  21.604 67.632 24.008 68.76 ;
     RECT  23.677 69.984 24.008 72.456 ;
     RECT  23.713 73.776 24.008 74.712 ;
     RECT  21.604 75.936 24.008 75.96 ;
     RECT  23.245 77.28 24.008 77.304 ;
     RECT  23.42 82.032 24.008 82.248 ;
     RECT  23.461 83.568 24.008 84.168 ;
     RECT  23.245 85.92 24.008 85.944 ;
     RECT  23.461 87.36 24.008 89.496 ;
     RECT  23.965 90.816 24.008 91.128 ;
     RECT  24.001 92.208 24.008 92.232 ;
     RECT  23.533 93.504 24.008 93.528 ;
     RECT  23.461 94.944 24.008 94.968 ;
     RECT  24.008 2.148 24.112 105.852 ;
     RECT  24.112 2.418 24.304 105.582 ;
     RECT  24.304 17.088 24.419 19.8 ;
     RECT  24.304 36.816 24.437 41.976 ;
     RECT  24.304 88.752 24.437 91.128 ;
     RECT  24.304 44.064 24.473 44.136 ;
     RECT  24.419 18 24.508 19.8 ;
     RECT  24.437 39.6 24.508 41.976 ;
     RECT  24.304 75.936 24.509 84.984 ;
     RECT  24.304 94.944 24.617 95.208 ;
     RECT  24.473 44.112 24.653 44.136 ;
     RECT  24.304 11.952 24.689 13.656 ;
     RECT  24.304 30.048 24.689 30.12 ;
     RECT  24.304 32.784 24.689 34.824 ;
     RECT  24.304 15.84 24.725 16.008 ;
     RECT  24.689 12.336 24.797 13.656 ;
     RECT  24.437 36.816 24.803 38.04 ;
     RECT  24.304 92.208 24.905 93.528 ;
     RECT  24.508 18 24.977 18.84 ;
     RECT  24.304 31.2 24.977 31.416 ;
     RECT  24.977 18 25.085 18.024 ;
     RECT  24.304 21.504 25.085 28.296 ;
     RECT  24.803 36.816 25.085 36.984 ;
     RECT  24.509 77.952 25.091 84.984 ;
     RECT  24.437 90.048 25.121 91.128 ;
     RECT  24.304 45.168 25.333 56.52 ;
     RECT  24.304 71.952 25.333 74.712 ;
     RECT  24.509 75.936 25.333 76.968 ;
     RECT  25.333 45.168 25.405 56.76 ;
     RECT  24.508 39.6 25.513 39.768 ;
     RECT  25.085 21.504 25.553 28.248 ;
     RECT  24.304 59.184 25.585 59.208 ;
     RECT  24.304 60.576 25.585 70.92 ;
     RECT  25.585 59.184 25.621 70.92 ;
     RECT  25.333 71.952 25.621 76.968 ;
     RECT  25.085 36.816 25.657 36.84 ;
     RECT  25.513 39.504 25.657 39.768 ;
     RECT  24.437 88.752 25.715 88.776 ;
     RECT  25.621 59.184 25.717 76.968 ;
     RECT  25.091 77.952 25.717 82.296 ;
     RECT  24.689 32.784 25.729 34.776 ;
     RECT  25.405 45.168 25.733 58.152 ;
     RECT  25.729 32.784 25.765 34.92 ;
     RECT  25.657 36.048 25.765 36.84 ;
     RECT  25.657 38.544 25.801 39.768 ;
     RECT  24.508 41.088 25.801 41.976 ;
     RECT  25.801 38.544 25.873 41.976 ;
     RECT  25.873 38.544 25.981 42.024 ;
     RECT  25.405 91.488 26.089 92.04 ;
     RECT  25.717 59.184 26.101 82.296 ;
     RECT  25.091 83.28 26.101 84.984 ;
     RECT  25.553 21.504 26.125 24.984 ;
     RECT  25.553 26.208 26.125 28.248 ;
     RECT  25.733 45.168 26.125 56.52 ;
     RECT  24.617 95.184 26.125 95.208 ;
     RECT  24.977 31.392 26.161 31.416 ;
     RECT  25.765 32.784 26.161 36.84 ;
     RECT  26.125 44.448 26.161 56.52 ;
     RECT  26.161 31.392 26.252 36.84 ;
     RECT  25.981 38.544 26.252 42.36 ;
     RECT  24.304 10.08 26.485 10.104 ;
     RECT  24.689 30.096 26.485 30.12 ;
     RECT  25.657 93.84 26.533 93.864 ;
     RECT  26.125 20.592 26.581 24.984 ;
     RECT  26.125 26.208 26.581 28.44 ;
     RECT  26.089 91.104 26.581 92.04 ;
     RECT  26.533 93.504 26.581 93.864 ;
     RECT  25.733 57.552 26.665 58.152 ;
     RECT  26.101 59.184 26.665 84.984 ;
     RECT  26.485 9.264 26.708 10.104 ;
     RECT  24.797 12.336 26.708 13.608 ;
     RECT  24.725 15.984 26.708 16.008 ;
     RECT  26.125 18.768 26.708 18.792 ;
     RECT  26.581 20.592 26.708 28.44 ;
     RECT  26.485 29.856 26.708 30.12 ;
     RECT  26.252 31.392 26.708 42.36 ;
     RECT  26.161 43.824 26.708 56.52 ;
     RECT  26.665 57.552 26.708 84.984 ;
     RECT  26.437 86.592 26.708 86.616 ;
     RECT  26.485 88.896 26.708 88.92 ;
     RECT  25.121 90.048 26.708 90.12 ;
     RECT  26.581 91.104 26.708 93.864 ;
     RECT  26.125 95.184 26.708 95.784 ;
     RECT  26.708 2.148 26.812 105.852 ;
     RECT  26.812 2.418 27.004 105.582 ;
     RECT  27.004 19.344 27.065 25.752 ;
     RECT  27.004 61.632 27.065 86.664 ;
     RECT  27.004 26.88 27.137 30.312 ;
     RECT  27.004 44.448 27.137 53.304 ;
     RECT  27.004 17.088 27.203 17.688 ;
     RECT  27.065 20.976 27.209 25.752 ;
     RECT  27.137 44.448 27.245 53.112 ;
     RECT  27.004 95.184 27.251 95.784 ;
     RECT  27.004 15.984 27.299 16.008 ;
     RECT  27.065 85.296 27.299 86.664 ;
     RECT  27.203 17.472 27.317 17.688 ;
     RECT  27.004 57.456 27.34 60.648 ;
     RECT  27.004 93.84 27.353 94.152 ;
     RECT  27.251 95.376 27.353 95.784 ;
     RECT  27.004 11.952 27.389 13.32 ;
     RECT  27.065 19.344 27.389 19.944 ;
     RECT  27.004 31.392 27.389 35.736 ;
     RECT  27.004 36.816 27.389 36.84 ;
     RECT  27.245 44.736 27.389 53.112 ;
     RECT  27.137 27.216 27.395 30.312 ;
     RECT  27.34 57.888 27.425 60.648 ;
     RECT  27.065 61.632 27.461 84.216 ;
     RECT  27.389 11.952 27.497 12.84 ;
     RECT  27.395 27.216 27.497 28.44 ;
     RECT  27.395 29.856 27.605 30.312 ;
     RECT  27.425 57.888 27.605 60.408 ;
     RECT  27.605 29.856 27.641 30.216 ;
     RECT  27.004 88.32 27.721 91.944 ;
     RECT  27.389 19.392 27.731 19.944 ;
     RECT  27.317 17.472 27.772 17.592 ;
     RECT  27.389 44.976 27.779 53.112 ;
     RECT  27.209 21.216 27.785 25.752 ;
     RECT  27.497 27.216 27.785 27.864 ;
     RECT  27.785 21.216 27.821 23.928 ;
     RECT  27.779 44.976 27.827 52.776 ;
     RECT  27.004 54.432 27.857 56.376 ;
     RECT  27.461 61.632 27.965 80.904 ;
     RECT  27.965 61.68 28.001 80.904 ;
     RECT  27.004 9.264 28.037 10.104 ;
     RECT  27.605 57.888 28.037 60.36 ;
     RECT  27.299 86.64 28.109 86.664 ;
     RECT  27.004 37.92 28.141 43.32 ;
     RECT  27.827 46.512 28.145 52.776 ;
     RECT  28.037 10.08 28.177 10.104 ;
     RECT  27.389 31.392 28.177 35.352 ;
     RECT  27.353 95.376 28.181 95.4 ;
     RECT  28.145 46.512 28.217 52.056 ;
     RECT  27.353 93.984 28.249 94.152 ;
     RECT  28.217 46.512 28.253 50.904 ;
     RECT  27.857 54.528 28.253 56.376 ;
     RECT  28.037 57.888 28.253 59.304 ;
     RECT  27.721 88.32 28.253 90.552 ;
     RECT  27.497 12.096 28.289 12.84 ;
     RECT  28.253 88.368 28.289 90.552 ;
     RECT  28.037 60.288 28.325 60.36 ;
     RECT  28.249 93.984 28.333 94.632 ;
     RECT  28.141 37.584 28.357 43.32 ;
     RECT  27.721 91.872 28.357 91.944 ;
     RECT  27.821 21.216 28.361 23.4 ;
     RECT  28.357 37.584 28.361 43.848 ;
     RECT  28.253 54.528 28.361 55.704 ;
     RECT  27.827 44.976 28.397 45.528 ;
     RECT  28.001 61.68 28.397 75.864 ;
     RECT  28.361 21.216 28.433 21.528 ;
     RECT  28.253 46.512 28.433 48.984 ;
     RECT  28.333 93.984 28.433 94.152 ;
     RECT  28.361 43.296 28.573 43.848 ;
     RECT  28.289 12.096 28.681 12.696 ;
     RECT  27.772 17.568 28.753 17.592 ;
     RECT  27.785 27.216 29.005 27.624 ;
     RECT  28.397 45.504 29.257 45.528 ;
     RECT  28.433 46.512 29.257 47.304 ;
     RECT  28.681 11.952 29.365 12.696 ;
     RECT  28.325 60.336 29.365 60.36 ;
     RECT  28.397 61.68 29.365 63.096 ;
     RECT  29.329 1.728 29.408 1.752 ;
     RECT  28.177 10.08 29.408 10.872 ;
     RECT  29.365 11.952 29.408 13.416 ;
     RECT  29.113 14.688 29.408 14.712 ;
     RECT  28.429 16.368 29.408 16.392 ;
     RECT  28.753 17.568 29.408 17.64 ;
     RECT  27.731 19.488 29.408 19.944 ;
     RECT  28.433 21.408 29.408 21.528 ;
     RECT  28.361 22.704 29.408 23.4 ;
     RECT  27.785 24.96 29.408 25.752 ;
     RECT  29.005 27.072 29.408 27.624 ;
     RECT  28.177 31.248 29.408 35.352 ;
     RECT  28.357 36.576 29.408 36.6 ;
     RECT  28.361 37.584 29.408 41.976 ;
     RECT  28.573 43.296 29.408 44.328 ;
     RECT  29.257 45.504 29.408 47.304 ;
     RECT  28.433 48.384 29.408 48.984 ;
     RECT  28.253 50.016 29.408 50.904 ;
     RECT  28.217 52.032 29.408 52.056 ;
     RECT  28.361 55.248 29.408 55.32 ;
     RECT  28.253 59.232 29.408 59.304 ;
     RECT  29.365 60.336 29.408 63.096 ;
     RECT  28.397 64.32 29.408 75.864 ;
     RECT  28.001 76.896 29.408 79.752 ;
     RECT  28.001 80.88 29.408 80.904 ;
     RECT  27.461 82.272 29.408 84.216 ;
     RECT  27.299 85.296 29.408 85.32 ;
     RECT  28.289 88.368 29.408 90.024 ;
     RECT  28.357 91.872 29.408 92.376 ;
     RECT  28.433 94.128 29.408 94.152 ;
     RECT  29.408 1.728 29.512 105.852 ;
     RECT  29.512 1.728 29.555 105.582 ;
     RECT  29.555 2.418 29.704 105.582 ;
     RECT  29.704 59.328 30.697 62.088 ;
     RECT  29.704 63.072 30.697 64.104 ;
     RECT  29.704 65.52 30.697 71.88 ;
     RECT  29.704 72.864 30.697 79.8 ;
     RECT  29.704 87.12 30.697 88.152 ;
     RECT  29.704 89.28 30.697 96.216 ;
     RECT  29.704 10.08 30.733 10.104 ;
     RECT  29.704 11.088 30.733 11.976 ;
     RECT  29.704 13.104 30.733 13.416 ;
     RECT  29.704 14.688 30.733 17.64 ;
     RECT  29.704 18.72 30.733 25.656 ;
     RECT  29.704 26.784 30.733 28.104 ;
     RECT  29.704 29.52 30.733 36.456 ;
     RECT  29.704 37.584 30.733 41.352 ;
     RECT  29.704 48.96 30.733 50.424 ;
     RECT  29.704 52.848 30.733 57.048 ;
     RECT  30.697 59.328 30.733 64.104 ;
     RECT  30.697 65.52 30.733 79.8 ;
     RECT  29.704 80.928 30.733 85.416 ;
     RECT  30.733 29.52 30.769 41.352 ;
     RECT  29.704 42.336 30.769 46.248 ;
     RECT  29.704 47.232 30.769 47.256 ;
     RECT  30.733 58.464 30.769 64.104 ;
     RECT  30.733 65.52 30.769 85.416 ;
     RECT  30.733 48.528 31.093 50.424 ;
     RECT  31.093 48.528 31.201 50.568 ;
     RECT  30.769 51.696 31.201 51.72 ;
     RECT  30.769 29.52 31.237 47.4 ;
     RECT  31.201 48.528 31.237 51.72 ;
     RECT  30.733 52.704 31.237 57.048 ;
     RECT  30.769 58.464 31.273 85.416 ;
     RECT  30.733 10.08 31.309 28.248 ;
     RECT  31.273 58.464 31.345 85.704 ;
     RECT  31.345 58.32 32.281 85.704 ;
     RECT  31.309 9.936 32.316 9.96 ;
     RECT  31.309 9.96 32.364 10.08 ;
     RECT  31.309 10.08 32.316 10.104 ;
     RECT  31.309 10.104 32.364 10.224 ;
     RECT  31.309 10.224 32.316 10.248 ;
     RECT  31.309 10.248 32.364 10.368 ;
     RECT  31.309 10.368 32.316 10.392 ;
     RECT  31.309 10.392 32.364 10.512 ;
     RECT  31.309 10.512 32.316 10.536 ;
     RECT  31.309 10.536 32.364 10.656 ;
     RECT  31.309 10.656 32.316 10.68 ;
     RECT  31.309 10.68 32.364 10.8 ;
     RECT  31.309 10.8 32.316 10.824 ;
     RECT  31.309 10.824 32.364 10.944 ;
     RECT  31.309 10.944 32.316 10.968 ;
     RECT  31.309 10.968 32.364 11.088 ;
     RECT  31.309 11.088 32.316 11.112 ;
     RECT  31.309 11.112 32.364 11.232 ;
     RECT  31.309 11.232 32.316 11.256 ;
     RECT  31.309 11.256 32.364 11.376 ;
     RECT  31.309 11.376 32.316 11.4 ;
     RECT  31.309 11.4 32.364 11.52 ;
     RECT  31.309 11.52 32.316 11.544 ;
     RECT  31.309 11.544 32.364 11.664 ;
     RECT  31.309 11.664 32.316 11.688 ;
     RECT  31.309 11.688 32.364 11.808 ;
     RECT  31.309 11.808 32.316 11.832 ;
     RECT  31.309 11.832 32.364 11.952 ;
     RECT  31.309 11.952 32.316 11.976 ;
     RECT  31.309 11.976 32.364 12.096 ;
     RECT  31.309 12.096 32.316 12.12 ;
     RECT  31.309 12.12 32.364 12.24 ;
     RECT  31.309 12.24 32.316 12.264 ;
     RECT  31.309 12.264 32.364 12.384 ;
     RECT  31.309 12.384 32.316 12.408 ;
     RECT  31.309 12.408 32.364 12.528 ;
     RECT  31.309 12.528 32.316 12.552 ;
     RECT  31.309 12.552 32.364 12.672 ;
     RECT  31.309 12.672 32.316 12.696 ;
     RECT  31.309 12.696 32.364 12.816 ;
     RECT  31.309 12.816 32.316 12.84 ;
     RECT  31.309 12.84 32.364 12.96 ;
     RECT  31.309 12.96 32.316 12.984 ;
     RECT  31.309 12.984 32.364 13.104 ;
     RECT  31.309 13.104 32.316 13.128 ;
     RECT  31.309 13.128 32.364 13.248 ;
     RECT  31.309 13.248 32.316 13.272 ;
     RECT  31.309 13.272 32.364 13.392 ;
     RECT  31.309 13.392 32.316 13.416 ;
     RECT  31.309 13.416 32.364 13.536 ;
     RECT  31.309 13.536 32.316 13.56 ;
     RECT  31.309 13.56 32.364 13.68 ;
     RECT  31.309 13.68 32.316 13.704 ;
     RECT  31.309 13.704 32.364 13.824 ;
     RECT  31.309 13.824 32.316 13.848 ;
     RECT  31.309 13.848 32.364 13.968 ;
     RECT  31.309 13.968 32.316 13.992 ;
     RECT  31.309 13.992 32.364 14.112 ;
     RECT  31.309 14.112 32.316 14.136 ;
     RECT  31.309 14.136 32.364 14.544 ;
     RECT  31.309 14.544 32.316 14.568 ;
     RECT  31.309 14.568 32.364 14.688 ;
     RECT  31.309 14.688 32.316 14.712 ;
     RECT  31.309 14.712 32.364 14.832 ;
     RECT  31.309 14.832 32.316 14.856 ;
     RECT  31.309 14.856 32.364 14.976 ;
     RECT  31.309 14.976 32.316 15 ;
     RECT  31.309 15 32.364 15.12 ;
     RECT  31.309 15.12 32.316 15.144 ;
     RECT  31.309 15.144 32.364 15.264 ;
     RECT  31.309 15.264 32.316 15.288 ;
     RECT  31.309 15.288 32.364 15.408 ;
     RECT  31.309 15.408 32.316 15.432 ;
     RECT  31.309 15.432 32.364 15.552 ;
     RECT  31.309 15.552 32.316 15.576 ;
     RECT  31.309 15.576 32.364 15.696 ;
     RECT  31.309 15.696 32.316 15.72 ;
     RECT  31.309 15.72 32.364 15.84 ;
     RECT  31.309 15.84 32.316 15.864 ;
     RECT  31.309 15.864 32.364 15.984 ;
     RECT  31.309 15.984 32.316 16.008 ;
     RECT  31.309 16.008 32.364 16.128 ;
     RECT  31.309 16.128 32.316 16.152 ;
     RECT  31.309 16.152 32.364 16.272 ;
     RECT  31.309 16.272 32.316 16.296 ;
     RECT  31.309 16.296 32.364 16.416 ;
     RECT  31.309 16.416 32.316 16.44 ;
     RECT  31.309 16.44 32.364 16.56 ;
     RECT  31.309 16.56 32.316 16.584 ;
     RECT  31.309 16.584 32.364 16.704 ;
     RECT  31.309 16.704 32.316 16.728 ;
     RECT  31.309 16.728 32.364 16.848 ;
     RECT  31.309 16.848 32.316 16.872 ;
     RECT  31.309 16.872 32.364 16.992 ;
     RECT  31.309 16.992 32.316 17.016 ;
     RECT  31.309 17.016 32.364 17.136 ;
     RECT  31.309 17.136 32.316 17.16 ;
     RECT  31.309 17.16 32.364 17.28 ;
     RECT  31.309 17.28 32.316 17.304 ;
     RECT  31.309 17.304 32.364 17.424 ;
     RECT  31.309 17.424 32.316 17.448 ;
     RECT  31.309 17.448 32.364 17.568 ;
     RECT  31.309 17.568 32.316 17.592 ;
     RECT  31.309 17.592 32.364 17.712 ;
     RECT  31.309 17.712 32.316 17.736 ;
     RECT  31.309 17.736 32.364 17.856 ;
     RECT  31.309 17.856 32.316 17.88 ;
     RECT  31.309 17.88 32.364 18 ;
     RECT  31.309 18 32.316 18.024 ;
     RECT  31.309 18.024 32.364 18.144 ;
     RECT  31.309 18.144 32.316 18.168 ;
     RECT  31.309 18.168 32.364 18.288 ;
     RECT  31.309 18.288 32.316 18.312 ;
     RECT  31.309 18.312 32.364 18.432 ;
     RECT  31.309 18.432 32.316 18.456 ;
     RECT  31.309 18.456 32.364 18.576 ;
     RECT  31.309 18.576 32.316 18.6 ;
     RECT  31.309 18.6 32.364 18.72 ;
     RECT  31.309 18.72 32.316 18.744 ;
     RECT  31.309 18.744 32.364 18.864 ;
     RECT  31.309 18.864 32.316 18.888 ;
     RECT  31.309 18.888 32.364 19.008 ;
     RECT  31.309 19.008 32.316 19.032 ;
     RECT  31.309 19.032 32.364 19.152 ;
     RECT  31.309 19.152 32.316 19.176 ;
     RECT  31.309 19.176 32.364 19.296 ;
     RECT  31.309 19.296 32.316 19.32 ;
     RECT  31.309 19.32 32.364 19.44 ;
     RECT  31.309 19.44 32.316 19.464 ;
     RECT  31.309 19.464 32.364 19.584 ;
     RECT  31.309 19.584 32.316 19.608 ;
     RECT  31.309 19.608 32.364 19.728 ;
     RECT  31.309 19.728 32.316 19.752 ;
     RECT  31.309 19.752 32.364 19.872 ;
     RECT  31.309 19.872 32.316 19.896 ;
     RECT  31.309 19.896 32.364 20.016 ;
     RECT  31.309 20.016 32.316 20.04 ;
     RECT  31.309 20.04 32.364 20.16 ;
     RECT  31.309 20.16 32.316 20.184 ;
     RECT  31.309 20.184 32.364 20.304 ;
     RECT  31.309 20.304 32.316 20.328 ;
     RECT  31.309 20.328 32.364 20.448 ;
     RECT  31.309 20.448 32.316 20.472 ;
     RECT  31.309 20.472 32.364 20.592 ;
     RECT  31.309 20.592 32.316 20.616 ;
     RECT  31.309 20.616 32.364 20.736 ;
     RECT  31.309 20.736 32.316 20.76 ;
     RECT  31.309 20.76 32.364 20.88 ;
     RECT  31.309 20.88 32.316 20.904 ;
     RECT  31.309 20.904 32.364 21.024 ;
     RECT  31.309 21.024 32.316 21.048 ;
     RECT  31.309 21.048 32.364 21.168 ;
     RECT  31.309 21.168 32.316 21.192 ;
     RECT  31.309 21.192 32.364 21.312 ;
     RECT  31.309 21.312 32.316 21.336 ;
     RECT  31.309 21.336 32.364 21.456 ;
     RECT  31.309 21.456 32.316 21.48 ;
     RECT  31.309 21.48 32.364 21.6 ;
     RECT  31.309 21.6 32.316 21.624 ;
     RECT  31.309 21.624 32.364 21.744 ;
     RECT  31.309 21.744 32.316 21.768 ;
     RECT  31.309 21.768 32.364 21.888 ;
     RECT  31.309 21.888 32.316 21.912 ;
     RECT  31.309 21.912 32.364 22.032 ;
     RECT  31.309 22.032 32.316 22.056 ;
     RECT  31.309 22.056 32.364 22.176 ;
     RECT  31.309 22.176 32.316 22.2 ;
     RECT  31.309 22.2 32.364 22.32 ;
     RECT  31.309 22.32 32.316 22.344 ;
     RECT  31.309 22.344 32.364 22.464 ;
     RECT  31.309 22.464 32.316 22.488 ;
     RECT  31.309 22.488 32.364 22.608 ;
     RECT  31.309 22.608 32.316 22.632 ;
     RECT  31.309 22.632 32.364 22.752 ;
     RECT  31.309 22.752 32.316 22.776 ;
     RECT  31.309 22.776 32.364 22.896 ;
     RECT  31.309 22.896 32.316 22.92 ;
     RECT  31.309 22.92 32.364 23.04 ;
     RECT  31.309 23.04 32.316 23.064 ;
     RECT  31.309 23.064 32.364 23.184 ;
     RECT  31.309 23.184 32.316 23.208 ;
     RECT  31.309 23.208 32.364 23.328 ;
     RECT  31.309 23.328 32.316 23.352 ;
     RECT  31.309 23.352 32.364 23.472 ;
     RECT  31.309 23.472 32.316 23.496 ;
     RECT  31.309 23.496 32.364 23.616 ;
     RECT  31.309 23.616 32.316 23.64 ;
     RECT  31.309 23.64 32.364 23.76 ;
     RECT  31.309 23.76 32.316 23.784 ;
     RECT  31.309 23.784 32.364 23.904 ;
     RECT  31.309 23.904 32.316 23.928 ;
     RECT  31.309 23.928 32.364 24.048 ;
     RECT  31.309 24.048 32.316 24.072 ;
     RECT  31.309 24.072 32.364 24.192 ;
     RECT  31.309 24.192 32.316 24.216 ;
     RECT  31.309 24.216 32.364 24.336 ;
     RECT  31.309 24.336 32.316 24.36 ;
     RECT  31.309 24.36 32.364 24.48 ;
     RECT  31.309 24.48 32.316 24.504 ;
     RECT  31.309 24.504 32.364 24.624 ;
     RECT  31.309 24.624 32.316 24.648 ;
     RECT  31.309 24.648 32.364 24.768 ;
     RECT  31.309 24.768 32.316 24.792 ;
     RECT  31.309 24.792 32.364 24.912 ;
     RECT  31.309 24.912 32.316 24.936 ;
     RECT  31.309 24.936 32.364 25.056 ;
     RECT  31.309 25.056 32.316 25.08 ;
     RECT  31.309 25.08 32.364 25.2 ;
     RECT  31.309 25.2 32.316 25.224 ;
     RECT  31.309 25.224 32.364 25.344 ;
     RECT  31.309 25.344 32.316 25.368 ;
     RECT  31.309 25.368 32.364 25.488 ;
     RECT  31.309 25.488 32.316 25.512 ;
     RECT  31.309 25.512 32.364 25.632 ;
     RECT  31.309 25.632 32.316 25.656 ;
     RECT  31.309 25.656 32.364 25.776 ;
     RECT  31.309 25.776 32.316 25.8 ;
     RECT  31.309 25.8 32.364 25.92 ;
     RECT  31.309 25.92 32.316 25.944 ;
     RECT  31.309 25.944 32.364 26.064 ;
     RECT  31.309 26.064 32.316 26.088 ;
     RECT  31.309 26.088 32.364 26.208 ;
     RECT  31.309 26.208 32.316 26.232 ;
     RECT  31.309 26.232 32.364 26.352 ;
     RECT  31.309 26.352 32.316 26.376 ;
     RECT  31.309 26.376 32.364 26.496 ;
     RECT  31.309 26.496 32.316 26.52 ;
     RECT  31.309 26.52 32.364 26.64 ;
     RECT  31.309 26.64 32.316 26.664 ;
     RECT  31.309 26.664 32.364 26.784 ;
     RECT  31.309 26.784 32.316 26.808 ;
     RECT  31.309 26.808 32.364 26.928 ;
     RECT  31.309 26.928 32.316 26.952 ;
     RECT  31.309 26.952 32.364 27.072 ;
     RECT  31.309 27.072 32.316 27.096 ;
     RECT  31.309 27.096 32.364 27.216 ;
     RECT  31.309 27.216 32.316 27.24 ;
     RECT  31.309 27.24 32.364 27.36 ;
     RECT  31.309 27.36 32.316 27.384 ;
     RECT  31.309 27.384 32.364 27.504 ;
     RECT  31.309 27.504 32.316 27.528 ;
     RECT  31.309 27.528 32.364 27.648 ;
     RECT  31.309 27.648 32.316 27.672 ;
     RECT  31.309 27.672 32.364 27.792 ;
     RECT  31.309 27.792 32.316 27.816 ;
     RECT  31.309 27.816 32.364 27.936 ;
     RECT  31.309 27.936 32.316 27.96 ;
     RECT  31.309 27.96 32.364 28.08 ;
     RECT  31.309 28.08 32.316 28.104 ;
     RECT  31.309 28.104 32.364 28.224 ;
     RECT  31.309 28.224 32.316 28.248 ;
     RECT  31.237 29.52 32.316 29.544 ;
     RECT  31.237 29.544 32.364 29.664 ;
     RECT  31.237 29.664 32.316 29.688 ;
     RECT  31.237 29.688 32.364 29.808 ;
     RECT  31.237 29.808 32.316 29.832 ;
     RECT  31.237 29.832 32.364 29.952 ;
     RECT  31.237 29.952 32.316 29.976 ;
     RECT  31.237 29.976 32.364 30.096 ;
     RECT  31.237 30.096 32.316 30.12 ;
     RECT  31.237 30.12 32.364 30.24 ;
     RECT  31.237 30.24 32.316 30.264 ;
     RECT  31.237 30.264 32.364 30.384 ;
     RECT  31.237 30.384 32.316 30.408 ;
     RECT  31.237 30.408 32.364 30.528 ;
     RECT  31.237 30.528 32.316 30.552 ;
     RECT  31.237 30.552 32.364 30.672 ;
     RECT  31.237 30.672 32.316 30.696 ;
     RECT  31.237 30.696 32.364 30.816 ;
     RECT  31.237 30.816 32.316 30.84 ;
     RECT  31.237 30.84 32.364 30.96 ;
     RECT  31.237 30.96 32.316 30.984 ;
     RECT  31.237 30.984 32.364 31.104 ;
     RECT  31.237 31.104 32.316 31.128 ;
     RECT  31.237 31.128 32.364 31.248 ;
     RECT  31.237 31.248 32.316 31.272 ;
     RECT  31.237 31.272 32.364 31.392 ;
     RECT  31.237 31.392 32.316 31.416 ;
     RECT  31.237 31.416 32.364 31.536 ;
     RECT  31.237 31.536 32.316 31.56 ;
     RECT  31.237 31.56 32.364 31.68 ;
     RECT  31.237 31.68 32.316 31.704 ;
     RECT  31.237 31.704 32.364 31.824 ;
     RECT  31.237 31.824 32.316 31.848 ;
     RECT  31.237 31.848 32.364 31.968 ;
     RECT  31.237 31.968 32.316 31.992 ;
     RECT  31.237 31.992 32.364 32.112 ;
     RECT  31.237 32.112 32.316 32.136 ;
     RECT  31.237 32.136 32.364 32.256 ;
     RECT  31.237 32.256 32.316 32.28 ;
     RECT  31.237 32.28 32.364 32.4 ;
     RECT  31.237 32.4 32.316 32.424 ;
     RECT  31.237 32.424 32.364 32.544 ;
     RECT  31.237 32.544 32.316 32.568 ;
     RECT  31.237 32.568 32.364 32.688 ;
     RECT  31.237 32.688 32.316 32.712 ;
     RECT  31.237 32.712 32.364 32.832 ;
     RECT  31.237 32.832 32.316 32.856 ;
     RECT  31.237 32.856 32.364 32.976 ;
     RECT  31.237 32.976 32.316 33 ;
     RECT  31.237 33 32.364 33.12 ;
     RECT  31.237 33.12 32.316 33.144 ;
     RECT  31.237 33.144 32.364 33.264 ;
     RECT  31.237 33.264 32.316 33.288 ;
     RECT  31.237 33.288 32.364 33.408 ;
     RECT  31.237 33.408 32.316 33.432 ;
     RECT  31.237 33.432 32.364 33.552 ;
     RECT  31.237 33.552 32.316 33.576 ;
     RECT  31.237 33.576 32.364 33.696 ;
     RECT  31.237 33.696 32.316 33.72 ;
     RECT  31.237 33.72 32.364 33.84 ;
     RECT  31.237 33.84 32.316 33.864 ;
     RECT  31.237 33.864 32.364 33.984 ;
     RECT  31.237 33.984 32.316 34.008 ;
     RECT  31.237 34.008 32.364 34.128 ;
     RECT  31.237 34.128 32.316 34.152 ;
     RECT  31.237 34.152 32.364 34.272 ;
     RECT  31.237 34.272 32.316 34.296 ;
     RECT  31.237 34.296 32.364 34.416 ;
     RECT  31.237 34.416 32.316 34.44 ;
     RECT  31.237 34.44 32.364 34.56 ;
     RECT  31.237 34.56 32.316 34.584 ;
     RECT  31.237 34.584 32.364 34.704 ;
     RECT  31.237 34.704 32.316 34.728 ;
     RECT  31.237 34.728 32.364 34.848 ;
     RECT  31.237 34.848 32.316 34.872 ;
     RECT  31.237 34.872 32.364 34.992 ;
     RECT  31.237 34.992 32.316 35.016 ;
     RECT  31.237 35.016 32.364 35.136 ;
     RECT  31.237 35.136 32.316 35.16 ;
     RECT  31.237 35.16 32.364 35.28 ;
     RECT  31.237 35.28 32.316 35.304 ;
     RECT  31.237 35.304 32.364 35.424 ;
     RECT  31.237 35.424 32.316 35.448 ;
     RECT  31.237 35.448 32.364 35.568 ;
     RECT  31.237 35.568 32.316 35.592 ;
     RECT  31.237 35.592 32.364 35.712 ;
     RECT  31.237 35.712 32.316 35.736 ;
     RECT  31.237 35.736 32.364 35.856 ;
     RECT  31.237 35.856 32.316 35.88 ;
     RECT  31.237 35.88 32.364 36 ;
     RECT  31.237 36 32.316 36.024 ;
     RECT  31.237 36.024 32.364 36.144 ;
     RECT  31.237 36.144 32.316 36.168 ;
     RECT  31.237 36.168 32.364 36.288 ;
     RECT  31.237 36.288 32.316 36.312 ;
     RECT  31.237 36.312 32.364 36.432 ;
     RECT  31.237 36.432 32.316 36.456 ;
     RECT  31.237 36.456 32.364 36.576 ;
     RECT  31.237 36.576 32.316 36.6 ;
     RECT  31.237 36.6 32.364 36.72 ;
     RECT  31.237 36.72 32.316 36.744 ;
     RECT  31.237 36.744 32.364 36.864 ;
     RECT  31.237 36.864 32.316 36.888 ;
     RECT  31.237 36.888 32.364 37.008 ;
     RECT  31.237 37.008 32.316 37.032 ;
     RECT  31.237 37.032 32.364 37.152 ;
     RECT  31.237 37.152 32.316 37.176 ;
     RECT  31.237 37.176 32.364 37.296 ;
     RECT  31.237 37.296 32.316 37.32 ;
     RECT  31.237 37.32 32.364 37.44 ;
     RECT  31.237 37.44 32.316 37.464 ;
     RECT  31.237 37.464 32.364 37.584 ;
     RECT  31.237 37.584 32.316 37.608 ;
     RECT  31.237 37.608 32.364 37.728 ;
     RECT  31.237 37.728 32.316 37.752 ;
     RECT  31.237 37.752 32.364 37.872 ;
     RECT  31.237 37.872 32.316 37.896 ;
     RECT  31.237 37.896 32.364 38.016 ;
     RECT  31.237 38.016 32.316 38.04 ;
     RECT  31.237 38.04 32.364 38.16 ;
     RECT  31.237 38.16 32.316 38.184 ;
     RECT  31.237 38.184 32.364 38.304 ;
     RECT  31.237 38.304 32.316 38.328 ;
     RECT  31.237 38.328 32.364 38.448 ;
     RECT  31.237 38.448 32.316 38.472 ;
     RECT  31.237 38.472 32.364 38.592 ;
     RECT  31.237 38.592 32.316 38.616 ;
     RECT  31.237 38.616 32.364 38.736 ;
     RECT  31.237 38.736 32.316 38.76 ;
     RECT  31.237 38.76 32.364 38.88 ;
     RECT  31.237 38.88 32.316 38.904 ;
     RECT  31.237 38.904 32.364 39.024 ;
     RECT  31.237 39.024 32.316 39.048 ;
     RECT  31.237 39.048 32.364 39.168 ;
     RECT  31.237 39.168 32.316 39.192 ;
     RECT  31.237 39.192 32.364 39.312 ;
     RECT  31.237 39.312 32.316 39.336 ;
     RECT  31.237 39.336 32.364 39.456 ;
     RECT  31.237 39.456 32.316 39.48 ;
     RECT  31.237 39.48 32.364 39.6 ;
     RECT  31.237 39.6 32.316 39.624 ;
     RECT  31.237 39.624 32.364 39.744 ;
     RECT  31.237 39.744 32.316 39.768 ;
     RECT  31.237 39.768 32.364 39.888 ;
     RECT  31.237 39.888 32.316 39.912 ;
     RECT  31.237 39.912 32.364 40.032 ;
     RECT  31.237 40.032 32.316 40.056 ;
     RECT  31.237 40.056 32.364 40.176 ;
     RECT  31.237 40.176 32.316 40.2 ;
     RECT  31.237 40.2 32.364 40.32 ;
     RECT  31.237 40.32 32.316 40.344 ;
     RECT  31.237 40.344 32.364 40.464 ;
     RECT  31.237 40.464 32.316 40.488 ;
     RECT  31.237 40.488 32.364 40.608 ;
     RECT  31.237 40.608 32.316 40.632 ;
     RECT  31.237 40.632 32.364 40.752 ;
     RECT  31.237 40.752 32.316 40.776 ;
     RECT  31.237 40.776 32.364 40.896 ;
     RECT  31.237 40.896 32.316 40.92 ;
     RECT  31.237 40.92 32.364 41.04 ;
     RECT  31.237 41.04 32.316 41.064 ;
     RECT  31.237 41.064 32.364 41.184 ;
     RECT  31.237 41.184 32.316 41.208 ;
     RECT  31.237 41.208 32.364 41.328 ;
     RECT  31.237 41.328 32.316 41.352 ;
     RECT  31.237 41.352 32.364 41.472 ;
     RECT  31.237 41.472 32.316 41.496 ;
     RECT  31.237 41.496 32.364 41.616 ;
     RECT  31.237 41.616 32.316 41.64 ;
     RECT  31.237 41.64 32.364 41.76 ;
     RECT  31.237 41.76 32.316 41.784 ;
     RECT  31.237 41.784 32.364 41.904 ;
     RECT  31.237 41.904 32.316 41.928 ;
     RECT  31.237 41.928 32.364 42.048 ;
     RECT  31.237 42.048 32.316 42.072 ;
     RECT  31.237 42.072 32.364 42.192 ;
     RECT  31.237 42.192 32.316 42.216 ;
     RECT  31.237 42.216 32.364 42.336 ;
     RECT  31.237 42.336 32.316 42.36 ;
     RECT  31.237 42.36 32.364 42.48 ;
     RECT  31.237 42.48 32.316 42.504 ;
     RECT  31.237 42.504 32.364 42.624 ;
     RECT  31.237 42.624 32.316 42.648 ;
     RECT  31.237 42.648 32.364 42.768 ;
     RECT  31.237 42.768 32.316 42.792 ;
     RECT  31.237 42.792 32.364 42.912 ;
     RECT  31.237 42.912 32.316 42.936 ;
     RECT  31.237 42.936 32.364 43.056 ;
     RECT  31.237 43.056 32.316 43.08 ;
     RECT  31.237 43.08 32.364 43.2 ;
     RECT  31.237 43.2 32.316 43.224 ;
     RECT  31.237 43.224 32.364 43.344 ;
     RECT  31.237 43.344 32.316 43.368 ;
     RECT  31.237 43.368 32.364 43.488 ;
     RECT  31.237 43.488 32.316 43.512 ;
     RECT  31.237 43.512 32.364 43.632 ;
     RECT  31.237 43.632 32.316 43.656 ;
     RECT  31.237 43.656 32.364 43.776 ;
     RECT  31.237 43.776 32.316 43.8 ;
     RECT  31.237 43.8 32.364 43.92 ;
     RECT  31.237 43.92 32.316 43.944 ;
     RECT  31.237 43.944 32.364 44.064 ;
     RECT  31.237 44.064 32.316 44.088 ;
     RECT  31.237 44.088 32.364 44.208 ;
     RECT  31.237 44.208 32.316 44.232 ;
     RECT  31.237 44.232 32.364 44.352 ;
     RECT  31.237 44.352 32.316 44.376 ;
     RECT  31.237 44.376 32.364 44.496 ;
     RECT  31.237 44.496 32.316 44.52 ;
     RECT  31.237 44.52 32.364 44.64 ;
     RECT  31.237 44.64 32.316 44.664 ;
     RECT  31.237 44.664 32.364 44.784 ;
     RECT  31.237 44.784 32.316 44.808 ;
     RECT  31.237 44.808 32.364 44.928 ;
     RECT  31.237 44.928 32.316 44.952 ;
     RECT  31.237 44.952 32.364 45.072 ;
     RECT  31.237 45.072 32.316 45.096 ;
     RECT  31.237 45.096 32.364 45.216 ;
     RECT  31.237 45.216 32.316 45.24 ;
     RECT  31.237 45.24 32.364 45.36 ;
     RECT  31.237 45.36 32.316 45.384 ;
     RECT  31.237 45.384 32.364 45.504 ;
     RECT  31.237 45.504 32.316 45.528 ;
     RECT  31.237 45.528 32.364 45.648 ;
     RECT  31.237 45.648 32.316 45.672 ;
     RECT  31.237 45.672 32.364 45.792 ;
     RECT  31.237 45.792 32.316 45.816 ;
     RECT  31.237 45.816 32.364 45.936 ;
     RECT  31.237 45.936 32.316 45.96 ;
     RECT  31.237 45.96 32.364 46.08 ;
     RECT  31.237 46.08 32.316 46.104 ;
     RECT  31.237 46.104 32.364 46.224 ;
     RECT  31.237 46.224 32.316 46.248 ;
     RECT  31.237 46.248 32.364 46.368 ;
     RECT  31.237 46.368 32.316 46.392 ;
     RECT  31.237 46.392 32.364 46.512 ;
     RECT  31.237 46.512 32.316 46.536 ;
     RECT  31.237 46.536 32.364 46.656 ;
     RECT  31.237 46.656 32.316 46.68 ;
     RECT  31.237 46.68 32.364 46.8 ;
     RECT  31.237 46.8 32.316 46.824 ;
     RECT  31.237 46.824 32.364 46.944 ;
     RECT  31.237 46.944 32.316 46.968 ;
     RECT  31.237 46.968 32.364 47.088 ;
     RECT  31.237 47.088 32.316 47.112 ;
     RECT  31.237 47.112 32.364 47.232 ;
     RECT  31.237 47.232 32.316 47.256 ;
     RECT  31.237 47.256 32.364 47.376 ;
     RECT  31.237 47.376 32.316 47.4 ;
     RECT  31.237 47.4 32.364 47.52 ;
     RECT  31.237 47.52 32.316 47.544 ;
     RECT  31.237 47.544 32.364 47.664 ;
     RECT  31.237 47.664 32.316 47.688 ;
     RECT  31.237 47.688 32.364 47.808 ;
     RECT  31.237 47.808 32.316 47.832 ;
     RECT  31.237 47.832 32.364 47.952 ;
     RECT  31.237 47.952 32.316 47.976 ;
     RECT  31.237 47.976 32.364 48.096 ;
     RECT  31.237 48.096 32.316 48.12 ;
     RECT  31.237 48.12 32.364 48.24 ;
     RECT  31.237 48.24 32.316 48.264 ;
     RECT  31.237 48.264 32.364 48.384 ;
     RECT  31.237 48.384 32.316 48.408 ;
     RECT  31.237 48.408 32.364 48.528 ;
     RECT  31.237 48.528 32.316 48.552 ;
     RECT  31.237 48.552 32.364 48.672 ;
     RECT  31.237 48.672 32.316 48.696 ;
     RECT  31.237 48.696 32.364 48.816 ;
     RECT  31.237 48.816 32.316 48.84 ;
     RECT  31.237 48.84 32.364 48.96 ;
     RECT  31.237 48.96 32.316 48.984 ;
     RECT  31.237 48.984 32.364 49.104 ;
     RECT  31.237 49.104 32.316 49.128 ;
     RECT  31.237 49.128 32.364 49.248 ;
     RECT  31.237 49.248 32.316 49.272 ;
     RECT  31.237 49.272 32.364 49.392 ;
     RECT  31.237 49.392 32.316 49.416 ;
     RECT  31.237 49.416 32.364 49.536 ;
     RECT  31.237 49.536 32.316 49.56 ;
     RECT  31.237 49.56 32.364 49.68 ;
     RECT  31.237 49.68 32.316 49.704 ;
     RECT  31.237 49.704 32.364 49.824 ;
     RECT  31.237 49.824 32.316 49.848 ;
     RECT  31.237 49.848 32.364 49.968 ;
     RECT  31.237 49.968 32.316 49.992 ;
     RECT  31.237 49.992 32.364 50.112 ;
     RECT  31.237 50.112 32.316 50.136 ;
     RECT  31.237 50.136 32.364 50.256 ;
     RECT  31.237 50.256 32.316 50.28 ;
     RECT  31.237 50.28 32.364 50.4 ;
     RECT  31.237 50.4 32.316 50.424 ;
     RECT  31.237 50.424 32.364 50.544 ;
     RECT  31.237 50.544 32.316 50.568 ;
     RECT  31.237 50.568 32.364 50.688 ;
     RECT  31.237 50.688 32.316 50.712 ;
     RECT  31.237 50.712 32.364 50.832 ;
     RECT  31.237 50.832 32.316 50.856 ;
     RECT  31.237 50.856 32.364 50.976 ;
     RECT  31.237 50.976 32.316 51 ;
     RECT  31.237 51 32.364 51.12 ;
     RECT  31.237 51.12 32.316 51.144 ;
     RECT  31.237 51.144 32.364 51.264 ;
     RECT  31.237 51.264 32.316 51.288 ;
     RECT  31.237 51.288 32.364 51.408 ;
     RECT  31.237 51.408 32.316 51.432 ;
     RECT  31.237 51.432 32.364 51.552 ;
     RECT  31.237 51.552 32.316 51.576 ;
     RECT  31.237 51.576 32.364 51.696 ;
     RECT  31.237 51.696 32.316 51.72 ;
     RECT  31.237 51.72 32.364 51.84 ;
     RECT  31.237 51.84 32.316 51.864 ;
     RECT  31.237 51.864 32.364 51.984 ;
     RECT  31.237 51.984 32.316 52.008 ;
     RECT  31.237 52.008 32.364 52.128 ;
     RECT  31.237 52.128 32.316 52.152 ;
     RECT  31.237 52.152 32.364 52.272 ;
     RECT  31.237 52.272 32.316 52.296 ;
     RECT  31.237 52.296 32.364 52.416 ;
     RECT  31.237 52.416 32.316 52.44 ;
     RECT  31.237 52.44 32.364 52.56 ;
     RECT  31.237 52.56 32.316 52.584 ;
     RECT  31.237 52.584 32.364 52.704 ;
     RECT  31.237 52.704 32.316 52.728 ;
     RECT  31.237 52.728 32.364 52.848 ;
     RECT  31.237 52.848 32.316 52.872 ;
     RECT  31.237 52.872 32.364 52.992 ;
     RECT  31.237 52.992 32.316 53.016 ;
     RECT  31.237 53.016 32.364 53.136 ;
     RECT  31.237 53.136 32.316 53.16 ;
     RECT  31.237 53.16 32.364 53.28 ;
     RECT  31.237 53.28 32.316 53.304 ;
     RECT  31.237 53.304 32.364 53.424 ;
     RECT  31.237 53.424 32.316 53.448 ;
     RECT  31.237 53.448 32.364 53.568 ;
     RECT  31.237 53.568 32.316 53.592 ;
     RECT  31.237 53.592 32.364 53.712 ;
     RECT  31.237 53.712 32.316 53.736 ;
     RECT  31.237 53.736 32.364 53.856 ;
     RECT  31.237 53.856 32.316 53.88 ;
     RECT  31.237 53.88 32.364 54 ;
     RECT  31.237 54 32.316 54.024 ;
     RECT  31.237 54.024 32.364 54.144 ;
     RECT  31.237 54.144 32.316 54.168 ;
     RECT  31.237 54.168 32.364 54.288 ;
     RECT  31.237 54.288 32.316 54.312 ;
     RECT  31.237 54.312 32.364 54.432 ;
     RECT  31.237 54.432 32.316 54.456 ;
     RECT  31.237 54.456 32.364 54.576 ;
     RECT  31.237 54.576 32.316 54.6 ;
     RECT  31.237 54.6 32.364 54.72 ;
     RECT  31.237 54.72 32.316 54.744 ;
     RECT  31.237 54.744 32.364 54.864 ;
     RECT  31.237 54.864 32.316 54.888 ;
     RECT  31.237 54.888 32.364 55.008 ;
     RECT  31.237 55.008 32.316 55.032 ;
     RECT  31.237 55.032 32.364 55.152 ;
     RECT  31.237 55.152 32.316 55.176 ;
     RECT  31.237 55.176 32.364 55.296 ;
     RECT  31.237 55.296 32.316 55.32 ;
     RECT  31.237 55.32 32.364 55.44 ;
     RECT  31.237 55.44 32.316 55.464 ;
     RECT  31.237 55.464 32.364 55.584 ;
     RECT  31.237 55.584 32.316 55.608 ;
     RECT  31.237 55.608 32.364 55.728 ;
     RECT  31.237 55.728 32.316 55.752 ;
     RECT  31.237 55.752 32.364 55.872 ;
     RECT  31.237 55.872 32.316 55.896 ;
     RECT  31.237 55.896 32.364 56.016 ;
     RECT  31.237 56.016 32.316 56.04 ;
     RECT  31.237 56.04 32.364 56.16 ;
     RECT  31.237 56.16 32.316 56.184 ;
     RECT  31.237 56.184 32.364 56.304 ;
     RECT  31.237 56.304 32.316 56.328 ;
     RECT  31.237 56.328 32.364 56.448 ;
     RECT  31.237 56.448 32.316 56.472 ;
     RECT  31.237 56.472 32.364 56.592 ;
     RECT  31.237 56.592 32.316 56.616 ;
     RECT  31.237 56.616 32.364 56.736 ;
     RECT  31.237 56.736 32.316 56.76 ;
     RECT  31.237 56.76 32.364 56.88 ;
     RECT  31.237 56.88 32.316 56.904 ;
     RECT  31.237 56.904 32.364 57.024 ;
     RECT  31.237 57.024 32.316 57.048 ;
     RECT  32.281 58.32 32.316 58.344 ;
     RECT  32.281 58.344 32.364 58.464 ;
     RECT  32.281 58.464 32.316 58.488 ;
     RECT  32.281 58.488 32.364 58.608 ;
     RECT  32.281 58.608 32.316 58.632 ;
     RECT  32.281 58.632 32.364 58.752 ;
     RECT  32.281 58.752 32.316 58.776 ;
     RECT  32.281 58.776 32.364 58.896 ;
     RECT  32.281 58.896 32.316 58.92 ;
     RECT  32.281 58.92 32.364 59.04 ;
     RECT  32.281 59.04 32.316 59.064 ;
     RECT  32.281 59.064 32.364 59.184 ;
     RECT  32.281 59.184 32.316 59.208 ;
     RECT  32.281 59.208 32.364 59.328 ;
     RECT  32.281 59.328 32.316 59.352 ;
     RECT  32.281 59.352 32.364 59.472 ;
     RECT  32.281 59.472 32.316 59.496 ;
     RECT  32.281 59.496 32.364 59.616 ;
     RECT  32.281 59.616 32.316 59.64 ;
     RECT  32.281 59.64 32.364 59.76 ;
     RECT  32.281 59.76 32.316 59.784 ;
     RECT  32.281 59.784 32.364 59.904 ;
     RECT  32.281 59.904 32.316 59.928 ;
     RECT  32.281 59.928 32.364 60.048 ;
     RECT  32.281 60.048 32.316 60.072 ;
     RECT  32.281 60.072 32.364 60.192 ;
     RECT  32.281 60.192 32.316 60.216 ;
     RECT  32.281 60.216 32.364 60.336 ;
     RECT  32.281 60.336 32.316 60.36 ;
     RECT  32.281 60.36 32.364 60.48 ;
     RECT  32.281 60.48 32.316 60.504 ;
     RECT  32.281 60.504 32.364 60.624 ;
     RECT  32.281 60.624 32.316 60.648 ;
     RECT  32.281 60.648 32.364 60.768 ;
     RECT  32.281 60.768 32.316 60.792 ;
     RECT  32.281 60.792 32.364 60.912 ;
     RECT  32.281 60.912 32.316 60.936 ;
     RECT  32.281 60.936 32.364 61.056 ;
     RECT  32.281 61.056 32.316 61.08 ;
     RECT  32.281 61.08 32.364 61.2 ;
     RECT  32.281 61.2 32.316 61.224 ;
     RECT  32.281 61.224 32.364 61.344 ;
     RECT  32.281 61.344 32.316 61.368 ;
     RECT  32.281 61.368 32.364 61.488 ;
     RECT  32.281 61.488 32.316 61.512 ;
     RECT  32.281 61.512 32.364 61.632 ;
     RECT  32.281 61.632 32.316 61.656 ;
     RECT  32.281 61.656 32.364 61.776 ;
     RECT  32.281 61.776 32.316 61.8 ;
     RECT  32.281 61.8 32.364 61.92 ;
     RECT  32.281 61.92 32.316 61.944 ;
     RECT  32.281 61.944 32.364 62.064 ;
     RECT  32.281 62.064 32.316 62.088 ;
     RECT  32.281 62.088 32.364 62.208 ;
     RECT  32.281 62.208 32.316 62.232 ;
     RECT  32.281 62.232 32.364 62.352 ;
     RECT  32.281 62.352 32.316 62.376 ;
     RECT  32.281 62.376 32.364 62.496 ;
     RECT  32.281 62.496 32.316 62.52 ;
     RECT  32.281 62.52 32.364 62.64 ;
     RECT  32.281 62.64 32.316 62.664 ;
     RECT  32.281 62.664 32.364 62.784 ;
     RECT  32.281 62.784 32.316 62.808 ;
     RECT  32.281 62.808 32.364 62.928 ;
     RECT  32.281 62.928 32.316 62.952 ;
     RECT  32.281 62.952 32.364 63.072 ;
     RECT  32.281 63.072 32.316 63.096 ;
     RECT  32.281 63.096 32.364 63.216 ;
     RECT  32.281 63.216 32.316 63.24 ;
     RECT  32.281 63.24 32.364 63.36 ;
     RECT  32.281 63.36 32.316 63.384 ;
     RECT  32.281 63.384 32.364 63.504 ;
     RECT  32.281 63.504 32.316 63.528 ;
     RECT  32.281 63.528 32.364 63.648 ;
     RECT  32.281 63.648 32.316 63.672 ;
     RECT  32.281 63.672 32.364 63.792 ;
     RECT  32.281 63.792 32.316 63.816 ;
     RECT  32.281 63.816 32.364 63.936 ;
     RECT  32.281 63.936 32.316 63.96 ;
     RECT  32.281 63.96 32.364 64.08 ;
     RECT  32.281 64.08 32.316 64.104 ;
     RECT  32.281 64.104 32.364 64.224 ;
     RECT  32.281 64.224 32.316 64.248 ;
     RECT  32.281 64.248 32.364 64.368 ;
     RECT  32.281 64.368 32.316 64.392 ;
     RECT  32.281 64.392 32.364 64.512 ;
     RECT  32.281 64.512 32.316 64.536 ;
     RECT  32.281 64.536 32.364 64.656 ;
     RECT  32.281 64.656 32.316 64.68 ;
     RECT  32.281 64.68 32.364 64.8 ;
     RECT  32.281 64.8 32.316 64.824 ;
     RECT  32.281 64.824 32.364 64.944 ;
     RECT  32.281 64.944 32.316 64.968 ;
     RECT  32.281 64.968 32.364 65.088 ;
     RECT  32.281 65.088 32.316 65.112 ;
     RECT  32.281 65.112 32.364 65.232 ;
     RECT  32.281 65.232 32.316 65.256 ;
     RECT  32.281 65.256 32.364 65.376 ;
     RECT  32.281 65.376 32.316 65.4 ;
     RECT  32.281 65.4 32.364 65.52 ;
     RECT  32.281 65.52 32.316 65.544 ;
     RECT  32.281 65.544 32.364 65.664 ;
     RECT  32.281 65.664 32.316 65.688 ;
     RECT  32.281 65.688 32.364 65.808 ;
     RECT  32.281 65.808 32.316 65.832 ;
     RECT  32.281 65.832 32.364 65.952 ;
     RECT  32.281 65.952 32.316 65.976 ;
     RECT  32.281 65.976 32.364 66.096 ;
     RECT  32.281 66.096 32.316 66.12 ;
     RECT  32.281 66.12 32.364 66.24 ;
     RECT  32.281 66.24 32.316 66.264 ;
     RECT  32.281 66.264 32.364 66.384 ;
     RECT  32.281 66.384 32.316 66.408 ;
     RECT  32.281 66.408 32.364 66.528 ;
     RECT  32.281 66.528 32.316 66.552 ;
     RECT  32.281 66.552 32.364 66.672 ;
     RECT  32.281 66.672 32.316 66.696 ;
     RECT  32.281 66.696 32.364 66.816 ;
     RECT  32.281 66.816 32.316 66.84 ;
     RECT  32.281 66.84 32.364 66.96 ;
     RECT  32.281 66.96 32.316 66.984 ;
     RECT  32.281 66.984 32.364 67.104 ;
     RECT  32.281 67.104 32.316 67.128 ;
     RECT  32.281 67.128 32.364 67.248 ;
     RECT  32.281 67.248 32.316 67.272 ;
     RECT  32.281 67.272 32.364 67.392 ;
     RECT  32.281 67.392 32.316 67.416 ;
     RECT  32.281 67.416 32.364 67.536 ;
     RECT  32.281 67.536 32.316 67.56 ;
     RECT  32.281 67.56 32.364 67.68 ;
     RECT  32.281 67.68 32.316 67.704 ;
     RECT  32.281 67.704 32.364 67.824 ;
     RECT  32.281 67.824 32.316 67.848 ;
     RECT  32.281 67.848 32.364 67.968 ;
     RECT  32.281 67.968 32.316 67.992 ;
     RECT  32.281 67.992 32.364 68.112 ;
     RECT  32.281 68.112 32.316 68.136 ;
     RECT  32.281 68.136 32.364 68.256 ;
     RECT  32.281 68.256 32.316 68.28 ;
     RECT  32.281 68.28 32.364 68.4 ;
     RECT  32.281 68.4 32.316 68.424 ;
     RECT  32.281 68.424 32.364 68.544 ;
     RECT  32.281 68.544 32.316 68.568 ;
     RECT  32.281 68.568 32.364 68.688 ;
     RECT  32.281 68.688 32.316 68.712 ;
     RECT  32.281 68.712 32.364 68.832 ;
     RECT  32.281 68.832 32.316 68.856 ;
     RECT  32.281 68.856 32.364 68.976 ;
     RECT  32.281 68.976 32.316 69 ;
     RECT  32.281 69 32.364 69.12 ;
     RECT  32.281 69.12 32.316 69.144 ;
     RECT  32.281 69.144 32.364 69.264 ;
     RECT  32.281 69.264 32.316 69.288 ;
     RECT  32.281 69.288 32.364 69.408 ;
     RECT  32.281 69.408 32.316 69.432 ;
     RECT  32.281 69.432 32.364 69.552 ;
     RECT  32.281 69.552 32.316 69.576 ;
     RECT  32.281 69.576 32.364 69.696 ;
     RECT  32.281 69.696 32.316 69.72 ;
     RECT  32.281 69.72 32.364 69.84 ;
     RECT  32.281 69.84 32.316 69.864 ;
     RECT  32.281 69.864 32.364 69.984 ;
     RECT  32.281 69.984 32.316 70.008 ;
     RECT  32.281 70.008 32.364 70.128 ;
     RECT  32.281 70.128 32.316 70.152 ;
     RECT  32.281 70.152 32.364 70.272 ;
     RECT  32.281 70.272 32.316 70.296 ;
     RECT  32.281 70.296 32.364 70.416 ;
     RECT  32.281 70.416 32.316 70.44 ;
     RECT  32.281 70.44 32.364 70.56 ;
     RECT  32.281 70.56 32.316 70.584 ;
     RECT  32.281 70.584 32.364 70.704 ;
     RECT  32.281 70.704 32.316 70.728 ;
     RECT  32.281 70.728 32.364 70.848 ;
     RECT  32.281 70.848 32.316 70.872 ;
     RECT  32.281 70.872 32.364 70.992 ;
     RECT  32.281 70.992 32.316 71.016 ;
     RECT  32.281 71.016 32.364 71.136 ;
     RECT  32.281 71.136 32.316 71.16 ;
     RECT  32.281 71.16 32.364 71.28 ;
     RECT  32.281 71.28 32.316 71.304 ;
     RECT  32.281 71.304 32.364 71.424 ;
     RECT  32.281 71.424 32.316 71.448 ;
     RECT  32.281 71.448 32.364 71.568 ;
     RECT  32.281 71.568 32.316 71.592 ;
     RECT  32.281 71.592 32.364 71.712 ;
     RECT  32.281 71.712 32.316 71.736 ;
     RECT  32.281 71.736 32.364 71.856 ;
     RECT  32.281 71.856 32.316 71.88 ;
     RECT  32.281 71.88 32.364 72 ;
     RECT  32.281 72 32.316 72.024 ;
     RECT  32.281 72.024 32.364 72.144 ;
     RECT  32.281 72.144 32.316 72.168 ;
     RECT  32.281 72.168 32.364 72.288 ;
     RECT  32.281 72.288 32.316 72.312 ;
     RECT  32.281 72.312 32.364 72.432 ;
     RECT  32.281 72.432 32.316 72.456 ;
     RECT  32.281 72.456 32.364 72.576 ;
     RECT  32.281 72.576 32.316 72.6 ;
     RECT  32.281 72.6 32.364 72.72 ;
     RECT  32.281 72.72 32.316 72.744 ;
     RECT  32.281 72.744 32.364 72.864 ;
     RECT  32.281 72.864 32.316 72.888 ;
     RECT  32.281 72.888 32.364 73.008 ;
     RECT  32.281 73.008 32.316 73.032 ;
     RECT  32.281 73.032 32.364 73.152 ;
     RECT  32.281 73.152 32.316 73.176 ;
     RECT  32.281 73.176 32.364 73.296 ;
     RECT  32.281 73.296 32.316 73.32 ;
     RECT  32.281 73.32 32.364 73.44 ;
     RECT  32.281 73.44 32.316 73.464 ;
     RECT  32.281 73.464 32.364 73.584 ;
     RECT  32.281 73.584 32.316 73.608 ;
     RECT  32.281 73.608 32.364 73.728 ;
     RECT  32.281 73.728 32.316 73.752 ;
     RECT  32.281 73.752 32.364 73.872 ;
     RECT  32.281 73.872 32.316 73.896 ;
     RECT  32.281 73.896 32.364 74.016 ;
     RECT  32.281 74.016 32.316 74.04 ;
     RECT  32.281 74.04 32.364 74.16 ;
     RECT  32.281 74.16 32.316 74.184 ;
     RECT  32.281 74.184 32.364 74.304 ;
     RECT  32.281 74.304 32.316 74.328 ;
     RECT  32.281 74.328 32.364 74.448 ;
     RECT  32.281 74.448 32.316 74.472 ;
     RECT  32.281 74.472 32.364 74.592 ;
     RECT  32.281 74.592 32.316 74.616 ;
     RECT  32.281 74.616 32.364 74.736 ;
     RECT  32.281 74.736 32.316 74.76 ;
     RECT  32.281 74.76 32.364 74.88 ;
     RECT  32.281 74.88 32.316 74.904 ;
     RECT  32.281 74.904 32.364 75.024 ;
     RECT  32.281 75.024 32.316 75.048 ;
     RECT  32.281 75.048 32.364 75.168 ;
     RECT  32.281 75.168 32.316 75.192 ;
     RECT  32.281 75.192 32.364 75.312 ;
     RECT  32.281 75.312 32.316 75.336 ;
     RECT  32.281 75.336 32.364 75.456 ;
     RECT  32.281 75.456 32.316 75.48 ;
     RECT  32.281 75.48 32.364 75.6 ;
     RECT  32.281 75.6 32.316 75.624 ;
     RECT  32.281 75.624 32.364 75.744 ;
     RECT  32.281 75.744 32.316 75.768 ;
     RECT  32.281 75.768 32.364 75.888 ;
     RECT  32.281 75.888 32.316 75.912 ;
     RECT  32.281 75.912 32.364 76.032 ;
     RECT  32.281 76.032 32.316 76.056 ;
     RECT  32.281 76.056 32.364 76.176 ;
     RECT  32.281 76.176 32.316 76.2 ;
     RECT  32.281 76.2 32.364 76.32 ;
     RECT  32.281 76.32 32.316 76.344 ;
     RECT  32.281 76.344 32.364 76.464 ;
     RECT  32.281 76.464 32.316 76.488 ;
     RECT  32.281 76.488 32.364 76.608 ;
     RECT  32.281 76.608 32.316 76.632 ;
     RECT  32.281 76.632 32.364 76.752 ;
     RECT  32.281 76.752 32.316 76.776 ;
     RECT  32.281 76.776 32.364 76.896 ;
     RECT  32.281 76.896 32.316 76.92 ;
     RECT  32.281 76.92 32.364 77.04 ;
     RECT  32.281 77.04 32.316 77.064 ;
     RECT  32.281 77.064 32.364 77.184 ;
     RECT  32.281 77.184 32.316 77.208 ;
     RECT  32.281 77.208 32.364 77.328 ;
     RECT  32.281 77.328 32.316 77.352 ;
     RECT  32.281 77.352 32.364 77.472 ;
     RECT  32.281 77.472 32.316 77.496 ;
     RECT  32.281 77.496 32.364 77.616 ;
     RECT  32.281 77.616 32.316 77.64 ;
     RECT  32.281 77.64 32.364 77.76 ;
     RECT  32.281 77.76 32.316 77.784 ;
     RECT  32.281 77.784 32.364 77.904 ;
     RECT  32.281 77.904 32.316 77.928 ;
     RECT  32.281 77.928 32.364 78.048 ;
     RECT  32.281 78.048 32.316 78.072 ;
     RECT  32.281 78.072 32.364 78.192 ;
     RECT  32.281 78.192 32.316 78.216 ;
     RECT  32.281 78.216 32.364 78.336 ;
     RECT  32.281 78.336 32.316 78.36 ;
     RECT  32.281 78.36 32.364 78.48 ;
     RECT  32.281 78.48 32.316 78.504 ;
     RECT  32.281 78.504 32.364 78.624 ;
     RECT  32.281 78.624 32.316 78.648 ;
     RECT  32.281 78.648 32.364 78.768 ;
     RECT  32.281 78.768 32.316 78.792 ;
     RECT  32.281 78.792 32.364 78.912 ;
     RECT  32.281 78.912 32.316 78.936 ;
     RECT  32.281 78.936 32.364 79.056 ;
     RECT  32.281 79.056 32.316 79.08 ;
     RECT  32.281 79.08 32.364 79.2 ;
     RECT  32.281 79.2 32.316 79.224 ;
     RECT  32.281 79.224 32.364 79.344 ;
     RECT  32.281 79.344 32.316 79.368 ;
     RECT  32.281 79.368 32.364 79.488 ;
     RECT  32.281 79.488 32.316 79.512 ;
     RECT  32.281 79.512 32.364 79.632 ;
     RECT  32.281 79.632 32.316 79.656 ;
     RECT  32.281 79.656 32.364 79.776 ;
     RECT  32.281 79.776 32.316 79.8 ;
     RECT  32.281 79.8 32.364 79.92 ;
     RECT  32.281 79.92 32.316 79.944 ;
     RECT  32.281 79.944 32.364 80.064 ;
     RECT  32.281 80.064 32.316 80.088 ;
     RECT  32.281 80.088 32.364 80.208 ;
     RECT  32.281 80.208 32.316 80.232 ;
     RECT  32.281 80.232 32.364 80.352 ;
     RECT  32.281 80.352 32.316 80.376 ;
     RECT  32.281 80.376 32.364 80.496 ;
     RECT  32.281 80.496 32.316 80.52 ;
     RECT  32.281 80.52 32.364 80.64 ;
     RECT  32.281 80.64 32.316 80.664 ;
     RECT  32.281 80.664 32.364 80.784 ;
     RECT  32.281 80.784 32.316 80.808 ;
     RECT  32.281 80.808 32.364 80.928 ;
     RECT  32.281 80.928 32.316 80.952 ;
     RECT  32.281 80.952 32.364 81.072 ;
     RECT  32.281 81.072 32.316 81.096 ;
     RECT  32.281 81.096 32.364 81.216 ;
     RECT  32.281 81.216 32.316 81.24 ;
     RECT  32.281 81.24 32.364 81.36 ;
     RECT  32.281 81.36 32.316 81.384 ;
     RECT  32.281 81.384 32.364 81.504 ;
     RECT  32.281 81.504 32.316 81.528 ;
     RECT  32.281 81.528 32.364 81.648 ;
     RECT  32.281 81.648 32.316 81.672 ;
     RECT  32.281 81.672 32.364 81.792 ;
     RECT  32.281 81.792 32.316 81.816 ;
     RECT  32.281 81.816 32.364 81.936 ;
     RECT  32.281 81.936 32.316 81.96 ;
     RECT  32.281 81.96 32.364 82.08 ;
     RECT  32.281 82.08 32.316 82.104 ;
     RECT  32.281 82.104 32.364 82.224 ;
     RECT  32.281 82.224 32.316 82.248 ;
     RECT  32.281 82.248 32.364 82.368 ;
     RECT  32.281 82.368 32.316 82.392 ;
     RECT  32.281 82.392 32.364 82.512 ;
     RECT  32.281 82.512 32.316 82.536 ;
     RECT  32.281 82.536 32.364 82.656 ;
     RECT  32.281 82.656 32.316 82.68 ;
     RECT  32.281 82.68 32.364 82.8 ;
     RECT  32.281 82.8 32.316 82.824 ;
     RECT  32.281 82.824 32.364 82.944 ;
     RECT  32.281 82.944 32.316 82.968 ;
     RECT  32.281 82.968 32.364 83.088 ;
     RECT  32.281 83.088 32.316 83.112 ;
     RECT  32.281 83.112 32.364 83.232 ;
     RECT  32.281 83.232 32.316 83.256 ;
     RECT  32.281 83.256 32.364 83.376 ;
     RECT  32.281 83.376 32.316 83.4 ;
     RECT  32.281 83.4 32.364 83.52 ;
     RECT  32.281 83.52 32.316 83.544 ;
     RECT  32.281 83.544 32.364 83.664 ;
     RECT  32.281 83.664 32.316 83.688 ;
     RECT  32.281 83.688 32.364 83.808 ;
     RECT  32.281 83.808 32.316 83.832 ;
     RECT  32.281 83.832 32.364 83.952 ;
     RECT  32.281 83.952 32.316 83.976 ;
     RECT  32.281 83.976 32.364 84.096 ;
     RECT  32.281 84.096 32.316 84.12 ;
     RECT  32.281 84.12 32.364 84.24 ;
     RECT  32.281 84.24 32.316 84.264 ;
     RECT  32.281 84.264 32.364 84.384 ;
     RECT  32.281 84.384 32.316 84.408 ;
     RECT  32.281 84.408 32.364 84.528 ;
     RECT  32.281 84.528 32.316 84.552 ;
     RECT  32.281 84.552 32.364 84.672 ;
     RECT  32.281 84.672 32.316 84.696 ;
     RECT  32.281 84.696 32.364 84.816 ;
     RECT  32.281 84.816 32.316 84.84 ;
     RECT  32.281 84.84 32.364 84.96 ;
     RECT  32.281 84.96 32.316 84.984 ;
     RECT  32.281 84.984 32.364 85.104 ;
     RECT  32.281 85.104 32.316 85.128 ;
     RECT  32.281 85.128 32.364 85.248 ;
     RECT  32.281 85.248 32.316 85.272 ;
     RECT  32.281 85.272 32.364 85.392 ;
     RECT  32.281 85.392 32.316 85.416 ;
     RECT  32.281 85.416 32.364 85.536 ;
     RECT  32.281 85.536 32.316 85.56 ;
     RECT  32.281 85.56 32.364 85.68 ;
     RECT  32.281 85.68 32.316 85.704 ;
     RECT  32.281 85.704 32.364 85.824 ;
     RECT  32.281 85.824 32.316 85.848 ;
     RECT  30.697 87.12 32.316 87.144 ;
     RECT  30.697 87.144 32.364 87.264 ;
     RECT  30.697 87.264 32.316 87.288 ;
     RECT  30.697 87.288 32.364 87.408 ;
     RECT  30.697 87.408 32.316 87.432 ;
     RECT  30.697 87.432 32.364 87.552 ;
     RECT  30.697 87.552 32.316 87.576 ;
     RECT  30.697 87.576 32.364 87.696 ;
     RECT  30.697 87.696 32.316 87.72 ;
     RECT  30.697 87.72 32.364 87.84 ;
     RECT  30.697 87.84 32.316 87.864 ;
     RECT  30.697 87.864 32.364 87.984 ;
     RECT  30.697 87.984 32.316 88.008 ;
     RECT  30.697 88.008 32.364 88.128 ;
     RECT  30.697 88.128 32.316 88.152 ;
     RECT  30.697 88.152 32.364 88.272 ;
     RECT  30.697 88.272 32.316 88.296 ;
     RECT  30.697 88.296 32.364 88.416 ;
     RECT  30.697 88.416 32.316 88.44 ;
     RECT  30.697 88.44 32.364 88.56 ;
     RECT  30.697 88.56 32.316 88.584 ;
     RECT  30.697 88.584 32.364 88.704 ;
     RECT  30.697 88.704 32.316 88.728 ;
     RECT  30.697 88.728 32.364 88.848 ;
     RECT  30.697 88.848 32.316 88.872 ;
     RECT  30.697 88.872 32.364 88.992 ;
     RECT  30.697 88.992 32.316 89.016 ;
     RECT  30.697 89.016 32.364 89.136 ;
     RECT  30.697 89.136 32.316 89.16 ;
     RECT  30.697 89.16 32.364 89.28 ;
     RECT  30.697 89.28 32.316 89.304 ;
     RECT  30.697 89.304 32.364 89.424 ;
     RECT  30.697 89.424 32.316 89.448 ;
     RECT  30.697 89.448 32.364 89.568 ;
     RECT  30.697 89.568 32.316 89.592 ;
     RECT  30.697 89.592 32.364 89.712 ;
     RECT  30.697 89.712 32.316 89.736 ;
     RECT  30.697 89.736 32.364 89.856 ;
     RECT  30.697 89.856 32.316 89.88 ;
     RECT  30.697 89.88 32.364 90 ;
     RECT  30.697 90 32.316 90.024 ;
     RECT  30.697 90.024 32.364 90.144 ;
     RECT  30.697 90.144 32.316 90.168 ;
     RECT  30.697 90.168 32.364 90.288 ;
     RECT  30.697 90.288 32.316 90.312 ;
     RECT  30.697 90.312 32.364 90.432 ;
     RECT  30.697 90.432 32.316 90.456 ;
     RECT  30.697 90.456 32.364 90.576 ;
     RECT  30.697 90.576 32.316 90.6 ;
     RECT  30.697 90.6 32.364 90.72 ;
     RECT  30.697 90.72 32.316 90.744 ;
     RECT  30.697 90.744 32.364 90.864 ;
     RECT  30.697 90.864 32.316 90.888 ;
     RECT  30.697 90.888 32.364 91.008 ;
     RECT  30.697 91.008 32.316 91.032 ;
     RECT  30.697 91.032 32.364 91.152 ;
     RECT  30.697 91.152 32.316 91.176 ;
     RECT  30.697 91.176 32.364 91.296 ;
     RECT  30.697 91.296 32.316 91.32 ;
     RECT  30.697 91.32 32.364 91.44 ;
     RECT  30.697 91.44 32.316 91.464 ;
     RECT  30.697 91.464 32.364 91.584 ;
     RECT  30.697 91.584 32.316 91.608 ;
     RECT  30.697 91.608 32.364 91.728 ;
     RECT  30.697 91.728 32.316 91.752 ;
     RECT  30.697 91.752 32.364 91.872 ;
     RECT  30.697 91.872 32.316 91.896 ;
     RECT  30.697 91.896 32.364 92.016 ;
     RECT  30.697 92.016 32.316 92.04 ;
     RECT  30.697 92.04 32.364 92.16 ;
     RECT  30.697 92.16 32.316 92.184 ;
     RECT  30.697 92.184 32.364 92.304 ;
     RECT  30.697 92.304 32.316 92.328 ;
     RECT  30.697 92.328 32.364 92.448 ;
     RECT  30.697 92.448 32.316 92.472 ;
     RECT  30.697 92.472 32.364 92.592 ;
     RECT  30.697 92.592 32.316 92.616 ;
     RECT  30.697 92.616 32.364 92.736 ;
     RECT  30.697 92.736 32.316 92.76 ;
     RECT  30.697 92.76 32.364 92.88 ;
     RECT  30.697 92.88 32.316 92.904 ;
     RECT  30.697 92.904 32.364 93.024 ;
     RECT  30.697 93.024 32.316 93.048 ;
     RECT  30.697 93.048 32.364 93.168 ;
     RECT  30.697 93.168 32.316 93.192 ;
     RECT  30.697 93.192 32.364 93.312 ;
     RECT  30.697 93.312 32.316 93.336 ;
     RECT  30.697 93.336 32.364 93.456 ;
     RECT  30.697 93.456 32.316 93.48 ;
     RECT  30.697 93.48 32.364 93.6 ;
     RECT  30.697 93.6 32.316 93.624 ;
     RECT  30.697 93.624 32.364 93.744 ;
     RECT  30.697 93.744 32.316 93.768 ;
     RECT  30.697 93.768 32.364 93.888 ;
     RECT  30.697 93.888 32.316 93.912 ;
     RECT  30.697 93.912 32.364 94.032 ;
     RECT  30.697 94.032 32.316 94.056 ;
     RECT  30.697 94.056 32.364 94.176 ;
     RECT  30.697 94.176 32.316 94.2 ;
     RECT  30.697 94.2 32.364 94.32 ;
     RECT  30.697 94.32 32.316 94.344 ;
     RECT  30.697 94.344 32.364 94.464 ;
     RECT  30.697 94.464 32.316 94.488 ;
     RECT  30.697 94.488 32.364 94.608 ;
     RECT  30.697 94.608 32.316 94.632 ;
     RECT  30.697 94.632 32.364 94.752 ;
     RECT  30.697 94.752 32.316 94.776 ;
     RECT  30.697 94.776 32.364 94.896 ;
     RECT  30.697 94.896 32.316 94.92 ;
     RECT  30.697 94.92 32.364 95.04 ;
     RECT  30.697 95.04 32.316 95.064 ;
     RECT  30.697 95.064 32.364 95.184 ;
     RECT  30.697 95.184 32.316 95.208 ;
     RECT  30.697 95.208 32.364 95.328 ;
     RECT  30.697 95.328 32.316 95.352 ;
     RECT  30.697 95.352 32.364 95.472 ;
     RECT  30.697 95.472 32.316 95.496 ;
     RECT  30.697 95.496 32.364 95.616 ;
     RECT  30.697 95.616 32.316 95.64 ;
     RECT  30.697 95.64 32.364 95.76 ;
     RECT  30.697 95.76 32.316 95.784 ;
     RECT  30.697 95.784 32.364 95.904 ;
     RECT  30.697 95.904 32.316 95.928 ;
     RECT  30.697 95.928 32.364 96.048 ;
     RECT  30.697 96.048 32.316 96.072 ;
     RECT  30.697 96.072 32.364 96.192 ;
     RECT  30.697 96.192 32.316 96.216 ;
    LAYER M5 ;
     RECT  2.4 2.137 2.52 2.151 ;
     RECT  5.1 2.137 5.22 2.151 ;
     RECT  7.8 2.137 7.92 2.151 ;
     RECT  10.5 2.137 10.62 2.151 ;
     RECT  13.2 2.137 13.32 2.151 ;
     RECT  15.9 2.137 16.02 2.151 ;
     RECT  18.6 2.137 18.72 2.151 ;
     RECT  21.3 2.137 21.42 2.151 ;
     RECT  24 2.137 24.12 2.151 ;
     RECT  26.7 2.137 26.82 2.151 ;
     RECT  29.4 2.137 29.544 2.151 ;
     RECT  26.7 2.151 27.012 9.253 ;
     RECT  26.7 9.253 27.864 10.019 ;
     RECT  10.5 2.151 10.812 10.069 ;
     RECT  2.4 2.151 2.712 12.037 ;
     RECT  5.1 2.151 5.412 12.325 ;
     RECT  7.8 2.151 8.112 12.901 ;
     RECT  26.7 10.019 27.012 13.045 ;
     RECT  2.4 12.037 2.808 13.571 ;
     RECT  7.8 12.901 8.376 13.667 ;
     RECT  9.36 12.901 9.384 15.349 ;
     RECT  26.7 13.045 27.288 16.019 ;
     RECT  7.8 13.667 8.112 17.077 ;
     RECT  24 2.151 24.312 17.077 ;
     RECT  26.7 16.019 27.144 17.077 ;
     RECT  26.7 17.077 27.192 17.461 ;
     RECT  5.1 12.325 6.168 17.509 ;
     RECT  5.1 17.509 6.264 17.651 ;
     RECT  9.36 15.349 9.432 18.037 ;
     RECT  10.5 10.069 11.736 18.037 ;
     RECT  7.344 17.077 8.112 18.181 ;
     RECT  24 17.077 24.408 18.805 ;
     RECT  9.36 18.037 11.736 19.093 ;
     RECT  26.7 17.461 27.72 19.427 ;
     RECT  0.144 19.573 0.168 19.811 ;
     RECT  24 18.805 24.456 19.811 ;
     RECT  7.296 18.181 8.112 20.869 ;
     RECT  9.12 19.093 11.736 20.869 ;
     RECT  5.1 17.651 6.168 21.109 ;
     RECT  4.992 21.109 6.168 21.541 ;
     RECT  7.296 20.869 11.736 21.541 ;
     RECT  24 19.811 24.312 22.645 ;
     RECT  1.152 22.549 1.176 22.787 ;
     RECT  26.7 19.427 27.144 22.837 ;
     RECT  26.016 22.837 27.144 22.883 ;
     RECT  23.568 22.645 24.312 23.317 ;
     RECT  26.016 22.883 27.012 23.317 ;
     RECT  4.992 21.541 11.736 23.363 ;
     RECT  25.44 23.317 27.012 23.843 ;
     RECT  7.2 23.363 11.736 24.131 ;
     RECT  23.232 23.317 24.312 27.157 ;
     RECT  4.992 23.363 6.168 27.301 ;
     RECT  7.296 24.131 11.736 27.301 ;
     RECT  23.232 27.157 24.552 27.395 ;
     RECT  26.016 23.843 27.012 27.637 ;
     RECT  3.936 27.109 3.96 29.893 ;
     RECT  24 27.395 24.552 30.083 ;
     RECT  26.016 27.637 27.432 30.323 ;
     RECT  24 30.083 24.312 30.421 ;
     RECT  0.144 30.373 0.168 30.611 ;
     RECT  23.808 30.421 24.312 31.235 ;
     RECT  18.6 2.151 18.912 31.381 ;
     RECT  15.9 2.151 16.212 32.821 ;
     RECT  24 31.235 24.312 32.965 ;
     RECT  24 32.965 24.408 33.541 ;
     RECT  4.992 27.301 11.736 34.117 ;
     RECT  13.2 2.151 13.512 34.117 ;
     RECT  26.016 30.323 27.012 34.117 ;
     RECT  4.992 34.117 13.512 34.259 ;
     RECT  24 33.541 24.648 34.835 ;
     RECT  26.016 34.117 27.336 34.835 ;
     RECT  26.016 34.835 27.144 35.411 ;
     RECT  24 34.835 24.312 36.949 ;
     RECT  26.7 35.411 27.144 37.573 ;
     RECT  24 36.949 24.792 37.955 ;
     RECT  26.304 37.573 27.144 38.677 ;
     RECT  22.896 37.477 22.92 38.771 ;
     RECT  25.872 38.677 27.144 39.011 ;
     RECT  2.4 13.571 2.712 39.205 ;
     RECT  2.4 39.205 2.856 39.347 ;
     RECT  24 37.955 24.744 39.589 ;
     RECT  0.144 40.021 0.168 40.163 ;
     RECT  24 39.589 25.224 41.651 ;
     RECT  18.6 31.381 19.752 42.227 ;
     RECT  4.992 34.259 11.736 42.517 ;
     RECT  13.2 34.259 13.512 42.517 ;
     RECT  24 41.651 24.312 42.757 ;
     RECT  4.992 42.517 13.512 42.997 ;
     RECT  4.992 42.997 14.232 43.331 ;
     RECT  3.888 29.893 3.96 43.621 ;
     RECT  4.992 43.331 13.512 43.621 ;
     RECT  26.7 39.011 27.144 43.813 ;
     RECT  15.9 32.821 17.16 43.955 ;
     RECT  26.592 43.813 27.144 44.483 ;
     RECT  26.7 44.483 27.144 44.965 ;
     RECT  0.144 45.253 0.168 45.539 ;
     RECT  23.904 42.757 24.312 45.683 ;
     RECT  26.7 44.965 27.816 46.213 ;
     RECT  26.496 46.213 27.816 46.549 ;
     RECT  3.888 43.621 13.512 46.837 ;
     RECT  24 45.683 24.312 46.837 ;
     RECT  2.4 39.347 2.712 46.885 ;
     RECT  26.496 46.549 28.392 47.027 ;
     RECT  28.368 47.027 28.392 47.029 ;
     RECT  29.4 2.151 29.712 47.029 ;
     RECT  2.304 46.885 2.712 47.075 ;
     RECT  26.496 47.027 27.144 48.469 ;
     RECT  26.496 48.469 27.288 49.091 ;
     RECT  26.496 49.091 27.24 49.237 ;
     RECT  23.76 46.837 24.312 50.965 ;
     RECT  2.4 47.075 2.712 51.157 ;
     RECT  2.304 51.157 2.712 51.299 ;
     RECT  23.376 50.965 24.312 52.165 ;
     RECT  22.896 52.165 24.312 52.211 ;
     RECT  26.208 49.237 27.24 52.405 ;
     RECT  28.368 47.029 29.712 52.405 ;
     RECT  26.208 52.405 29.712 53.123 ;
     RECT  24 52.211 24.312 53.509 ;
     RECT  22.896 52.211 22.92 54.373 ;
     RECT  24 53.509 24.648 54.373 ;
     RECT  26.208 53.123 27.24 54.661 ;
     RECT  26.208 54.661 27.384 55.907 ;
     RECT  2.4 51.299 2.712 56.965 ;
     RECT  3.84 46.837 13.512 56.965 ;
     RECT  2.4 56.965 13.512 57.443 ;
     RECT  26.208 55.907 27.24 57.445 ;
     RECT  26.208 57.445 27.288 57.541 ;
     RECT  26.064 57.541 27.288 57.877 ;
     RECT  26.016 57.877 27.288 58.117 ;
     RECT  28.368 53.123 29.712 58.117 ;
     RECT  25.92 58.117 29.712 59.315 ;
     RECT  2.4 57.443 2.712 59.413 ;
     RECT  3.84 57.443 13.512 59.413 ;
     RECT  0.144 59.461 0.168 59.603 ;
     RECT  2.4 59.413 13.512 59.651 ;
     RECT  25.92 59.315 27.384 59.891 ;
     RECT  25.92 59.891 27.24 60.275 ;
     RECT  0.144 60.613 0.168 60.851 ;
     RECT  26.064 60.275 27.24 61.333 ;
     RECT  0.144 61.909 0.168 62.051 ;
     RECT  25.632 61.333 27.24 62.243 ;
     RECT  22.896 54.373 24.648 62.291 ;
     RECT  3.84 59.651 13.512 62.867 ;
     RECT  28.368 59.315 29.712 63.589 ;
     RECT  25.872 62.243 27.24 64.357 ;
     RECT  28.272 63.589 29.712 64.357 ;
     RECT  18.6 42.227 18.912 64.741 ;
     RECT  2.4 59.651 2.712 64.981 ;
     RECT  2.256 64.981 2.712 65.123 ;
     RECT  25.872 64.357 29.712 65.509 ;
     RECT  0.144 65.941 0.168 66.083 ;
     RECT  24 62.291 24.648 66.085 ;
     RECT  25.632 65.509 29.712 66.085 ;
     RECT  24 66.085 29.712 66.467 ;
     RECT  24 66.467 27.24 66.755 ;
     RECT  15.9 43.955 16.728 67.237 ;
     RECT  18.6 64.741 19.32 67.237 ;
     RECT  15.9 67.237 19.32 67.765 ;
     RECT  15.9 67.765 19.368 68.771 ;
     RECT  25.872 66.755 27.24 68.917 ;
     RECT  28.272 66.467 29.712 68.917 ;
     RECT  25.872 68.917 29.712 69.443 ;
     RECT  25.968 69.443 29.712 69.587 ;
     RECT  18.6 68.771 19.368 70.019 ;
     RECT  22.896 62.291 22.92 70.021 ;
     RECT  24 66.755 24.648 70.021 ;
     RECT  15.9 68.771 16.728 70.597 ;
     RECT  18.6 70.019 18.912 70.597 ;
     RECT  22.896 70.021 24.648 70.645 ;
     RECT  25.968 69.587 27.24 70.645 ;
     RECT  22.896 70.645 27.24 70.931 ;
     RECT  25.968 70.931 27.24 70.981 ;
     RECT  28.272 69.587 29.712 70.981 ;
     RECT  15.9 70.597 18.912 71.315 ;
     RECT  22.896 70.931 24.648 71.315 ;
     RECT  22.896 71.315 22.92 72.995 ;
     RECT  25.968 70.981 29.712 73.765 ;
     RECT  24 71.315 24.648 73.861 ;
     RECT  15.9 71.315 16.824 73.907 ;
     RECT  23.568 73.861 24.648 74.579 ;
     RECT  0.144 75.493 0.168 75.779 ;
     RECT  2.4 65.123 2.712 75.781 ;
     RECT  25.68 73.765 29.712 75.875 ;
     RECT  2.304 75.781 2.712 75.971 ;
     RECT  3.84 62.867 11.064 76.499 ;
     RECT  0.144 76.741 0.168 76.883 ;
     RECT  25.68 75.875 27.24 76.885 ;
     RECT  28.272 75.875 29.712 76.885 ;
     RECT  3.84 76.499 3.864 77.123 ;
     RECT  25.68 76.885 29.712 77.555 ;
     RECT  25.68 77.555 27.288 77.987 ;
     RECT  26.208 77.987 27.288 78.613 ;
     RECT  28.272 77.555 29.712 78.613 ;
     RECT  24 74.579 24.648 79.573 ;
     RECT  24 79.573 25.08 79.765 ;
     RECT  26.208 78.613 29.712 79.765 ;
     RECT  24 79.765 29.712 80.435 ;
     RECT  24 80.435 27.288 80.579 ;
     RECT  15.9 73.907 16.212 80.917 ;
     RECT  24 80.579 25.08 82.021 ;
     RECT  23.472 82.021 25.08 82.115 ;
     RECT  15.9 80.917 16.632 82.259 ;
     RECT  26.208 80.579 27.288 82.453 ;
     RECT  28.272 80.435 29.712 82.453 ;
     RECT  23.472 82.115 24.648 83.173 ;
     RECT  26.208 82.453 29.712 83.173 ;
     RECT  12.24 62.867 13.512 83.603 ;
     RECT  26.112 83.173 29.712 83.843 ;
     RECT  23.472 83.173 25.08 84.419 ;
     RECT  26.208 83.843 29.712 86.675 ;
     RECT  2.4 75.971 2.712 87.877 ;
     RECT  2.304 87.877 2.712 88.019 ;
     RECT  23.472 84.419 24.648 88.067 ;
     RECT  4.896 76.499 11.064 88.403 ;
     RECT  26.208 86.675 27.24 88.741 ;
     RECT  2.4 88.019 2.712 89.797 ;
     RECT  2.304 89.797 2.712 89.987 ;
     RECT  25.68 88.741 27.24 90.131 ;
     RECT  26.208 90.131 27.24 90.565 ;
     RECT  28.272 86.675 29.712 90.565 ;
     RECT  26.208 90.565 29.712 91.235 ;
     RECT  28.272 91.235 29.712 92.387 ;
     RECT  4.896 88.403 10.812 94.355 ;
     RECT  28.272 92.387 28.296 94.643 ;
     RECT  2.4 89.987 2.712 94.693 ;
     RECT  2.4 94.693 2.808 94.883 ;
     RECT  30.72 94.597 30.744 94.883 ;
     RECT  26.208 91.235 27.24 95.219 ;
     RECT  6.48 94.355 10.812 95.795 ;
     RECT  4.896 94.355 5.412 95.891 ;
     RECT  10.032 95.795 10.812 96.371 ;
     RECT  0.144 96.469 0.168 96.611 ;
     RECT  6.576 95.795 8.856 96.995 ;
     RECT  6.576 96.995 6.6 97.523 ;
     RECT  7.8 96.995 8.856 97.523 ;
     RECT  10.08 96.371 10.812 97.523 ;
     RECT  2.4 94.883 2.712 105.849 ;
     RECT  5.1 95.891 5.412 105.849 ;
     RECT  7.8 97.523 8.112 105.849 ;
     RECT  10.5 97.523 10.812 105.849 ;
     RECT  13.2 83.603 13.512 105.849 ;
     RECT  15.9 82.259 16.212 105.849 ;
     RECT  18.6 71.315 18.912 105.849 ;
     RECT  21.3 2.151 21.612 105.849 ;
     RECT  26.7 95.219 27.012 105.849 ;
     RECT  29.4 92.387 29.712 105.849 ;
     RECT  2.4 105.849 2.52 105.863 ;
     RECT  5.1 105.849 5.22 105.863 ;
     RECT  7.8 105.849 7.92 105.863 ;
     RECT  10.5 105.849 10.62 105.863 ;
     RECT  13.2 105.849 13.32 105.863 ;
     RECT  15.9 105.849 16.02 105.863 ;
     RECT  18.6 105.849 18.72 105.863 ;
     RECT  21.3 105.849 21.42 105.863 ;
     RECT  24 88.067 24.648 105.863 ;
     RECT  26.7 105.849 26.82 105.863 ;
     RECT  29.4 105.849 29.52 105.863 ;
     RECT  11.736 10.069 13.2 34.117 ;
     RECT  8.376 12.901 9.36 13.667 ;
     RECT  9.384 12.901 10.5 15.349 ;
     RECT  8.112 13.667 9.36 19.093 ;
     RECT  9.432 15.349 10.5 18.037 ;
     RECT  27.144 16.019 27.288 17.077 ;
     RECT  6.168 17.077 7.344 17.509 ;
     RECT  27.192 17.077 27.288 17.461 ;
     RECT  6.264 17.509 7.344 17.651 ;
     RECT  6.168 17.651 7.344 18.181 ;
     RECT  6.168 18.181 7.296 21.541 ;
     RECT  8.112 19.093 9.12 20.869 ;
     RECT  1.176 22.549 2.4 22.787 ;
     RECT  24.312 23.317 25.44 23.843 ;
     RECT  6.168 23.363 7.2 24.131 ;
     RECT  6.168 24.131 7.296 27.301 ;
     RECT  2.712 27.109 3.936 29.893 ;
     RECT  3.96 27.109 4.992 43.621 ;
     RECT  24.552 27.157 26.016 30.083 ;
     RECT  2.712 29.893 3.888 39.205 ;
     RECT  17.16 32.821 18.6 43.955 ;
     RECT  24.648 33.541 26.016 34.835 ;
     RECT  11.736 34.259 13.2 42.517 ;
     RECT  21.612 37.477 22.896 38.771 ;
     RECT  22.92 37.477 24 38.771 ;
     RECT  24.792 37.573 26.304 37.955 ;
     RECT  24.744 37.955 26.304 38.677 ;
     RECT  24.744 38.677 25.872 39.011 ;
     RECT  24.744 39.011 26.7 39.589 ;
     RECT  2.856 39.205 3.888 39.347 ;
     RECT  2.712 39.347 3.888 46.837 ;
     RECT  25.224 39.589 26.7 41.651 ;
     RECT  23.904 45.683 24 46.837 ;
     RECT  28.392 46.549 29.4 47.029 ;
     RECT  2.712 46.837 3.84 56.965 ;
     RECT  27.144 47.027 28.368 48.469 ;
     RECT  27.288 48.469 28.368 49.091 ;
     RECT  27.24 49.091 28.368 52.405 ;
     RECT  21.612 52.165 22.896 72.995 ;
     RECT  22.92 52.211 24 54.373 ;
     RECT  27.24 53.123 28.368 54.661 ;
     RECT  27.384 54.661 28.368 55.907 ;
     RECT  27.24 55.907 28.368 57.445 ;
     RECT  2.712 57.443 3.84 59.413 ;
     RECT  27.288 57.445 28.368 58.117 ;
     RECT  24.648 57.541 26.064 57.877 ;
     RECT  24.648 57.877 26.016 58.117 ;
     RECT  24.648 58.117 25.92 60.275 ;
     RECT  27.384 59.315 28.368 59.891 ;
     RECT  0.144 59.603 0.168 60.613 ;
     RECT  2.712 59.651 3.84 77.123 ;
     RECT  27.24 59.891 28.368 63.589 ;
     RECT  24.648 60.275 26.064 61.333 ;
     RECT  0.144 60.851 0.168 61.909 ;
     RECT  24.648 61.333 25.632 62.243 ;
     RECT  24.648 62.243 25.872 65.509 ;
     RECT  22.92 62.291 24 70.021 ;
     RECT  11.064 62.867 12.24 83.603 ;
     RECT  27.24 63.589 28.272 64.357 ;
     RECT  24.648 65.509 25.632 66.085 ;
     RECT  27.24 66.467 28.272 68.917 ;
     RECT  24.648 66.755 25.872 69.443 ;
     RECT  24.648 69.443 25.968 70.645 ;
     RECT  27.24 69.587 28.272 70.981 ;
     RECT  24.648 70.931 25.968 73.765 ;
     RECT  22.92 71.315 24 72.995 ;
     RECT  23.568 72.995 24 73.861 ;
     RECT  24.648 73.765 25.68 77.987 ;
     RECT  0.144 75.779 0.168 76.741 ;
     RECT  27.24 75.875 28.272 76.885 ;
     RECT  3.864 76.499 4.896 77.123 ;
     RECT  27.288 77.555 28.272 78.613 ;
     RECT  25.08 79.573 26.208 79.765 ;
     RECT  27.288 80.435 28.272 82.453 ;
     RECT  25.08 80.579 26.208 82.115 ;
     RECT  24.648 82.115 26.208 83.173 ;
     RECT  25.08 83.173 26.112 83.843 ;
     RECT  25.08 83.843 26.208 84.419 ;
     RECT  27.24 86.675 28.272 90.565 ;
     RECT  24.648 88.741 25.68 90.131 ;
     RECT  27.24 91.235 28.272 94.643 ;
     RECT  28.296 92.387 29.4 94.643 ;
     RECT  5.412 94.355 6.48 95.795 ;
     RECT  29.712 94.597 30.72 94.883 ;
     RECT  5.412 95.795 6.576 97.523 ;
     RECT  8.856 95.795 10.032 96.371 ;
     RECT  8.856 96.371 10.08 97.523 ;
     RECT  6.6 96.995 7.8 97.523 ;
  END
END qkd_seq_fan_s
END LIBRARY
